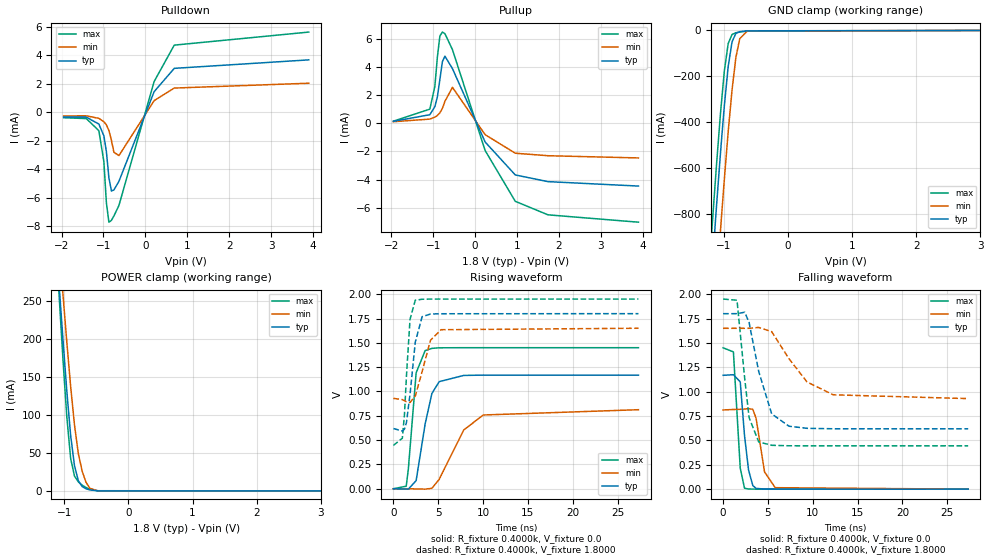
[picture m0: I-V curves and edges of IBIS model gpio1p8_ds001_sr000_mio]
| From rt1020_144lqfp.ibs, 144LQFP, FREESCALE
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[Model] gpio1p8_ds001_sr000_mio
|   Model gpio1p8_ds001_sr000_mio
| This model was characterised for following simulation conditions:
| External (pad) voltage:
|   - Typ: 1.8V,   - Min: 1.65V,   - Max: 1.95V
| Library cells for typ/min/max conditions are connected as defined below:
|  pad - External Pad
|  ipp_do - Core Input
|  ipp_obe - Output Buffer Enable
|  esd_boost - ovdd
|  ipp_dse0 - vddi
|  ipp_dse1 - vssi
|  ipp_dse2 - vssi
|  ipp_fsel0 - vssi
|  ipp_fsel1 - vssi
|  ipp_ina - ipp_ina
|  ipp_ind - ipp_ind
|  ipp_pwr_stable - vddi
|  ipp_sre - vssi
|  ovdd - ovdd
|  ovss - ovss
|  vddi - vddi
|  vssi - vssi
| All other pins connected to ground
Model_type I/O
Polarity   Non-Inverting
Enable   Active-High
Vinl =   0.5400V
Vinh =   1.2600V
Vmeas =  0.9000V
Cref =   0.0F
Rref =   0.4000k
Vref =   0.9000V
C_comp   1.2573pF   1.2208pF   1.3054pF
|C_comp_pullup   0.6439pF   0.6609pF   0.6284pF
|C_comp_pulldown   0.5473pF   0.5786pF   0.5258pF
[Model Spec]
| variable   typ   min   max
Vinh   1.2600V   1.1550V   1.3650V
Vinl   0.5400V   0.4950V   0.5850V
S_overshoot_high   1.8000V   1.6500V   1.9500V
S_overshoot_low   0.0V   0.0V   0.0V
Vmeas   0.9000V   0.8250V   0.9750V
Vref   0.9000V   0.8250V   0.9750V
Cref   0.0F   0.0F   0.0F
Rref   0.4000k   0.4000k   0.4000k
[Temperature Range]   25.0000   0.1050k   -20.0000
[Voltage Range]   1.8000V   1.6500V   1.9500V
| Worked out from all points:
|   slope of the pulldown table from 0 to 0.27 V, typ, clamps not added: 153 ohm
|   slope of the pullup table from 0 to 0.27 V, typ, clamps not added: 182 ohm
|   GND clamp passes 1 mA (typ) near -0.55 V on its own axis
|   POWER clamp passes 1 mA (typ) near -0.58 V on its own axis
|   rising waveform, R_fixture 0.4000k, V_fixture 0.0: 20-80 % time 1.3ns typ, 2.8ns min, 747ps max; typ from 0 V to 1.17 V
|   rising waveform, R_fixture 0.4000k, V_fixture 1.8000: 20-80 % time 809ps typ, 1.19ns min, 546ps max; typ from 0.619 V to 1.8 V
|   falling waveform, R_fixture 0.4000k, V_fixture 0.0: 20-80 % time 681ps typ, 847ps min, 496ps max; typ from 1.17 V to 0 V
|   falling waveform, R_fixture 0.4000k, V_fixture 1.8000: 20-80 % time 1.74ns typ, 3.42ns min, 947ps max; typ from 1.8 V to 0.619 V
[Pulldown]
|Voltage   I(typ)   I(min)   I(max)
-1.95V    -342uA     -265uA     -391uA
-1.41V    -350uA     -258uA     -451uA
-1.11V    -834.5uA   -436uA     -1.299mA
-990mV    -1.66mA    -669.8uA   -3.467mA
-930mV    -2.764mA   -895.4uA   -6.362mA
-870mV    -4.603mA   -1.287mA   -7.724mA
-810mV    -5.539mA   -1.972mA   -7.596mA
-750mV    -5.458mA   -2.817mA   -7.285mA
-630mV    -4.849mA   -3.046mA   -6.544mA
210mV     1.438mA    808.6uA    2.151mA
690mV     3.074mA    1.691mA    4.705mA
3.9V      3.67mA     2.03mA     5.62mA
[Pullup]
|Voltage   I(typ)   I(min)   I(max)
-1.95V    130uA      100uA      140uA
-1.08V    597uA      286uA      991uA
-960mV    1.17mA     422uA      2.604mA
-900mV    1.859mA    544uA      4.683mA
-840mV    3.095mA    733.5uA    6.184mA
-780mV    4.362mA    1.044mA    6.458mA
-720mV    4.75mA     1.549mA    6.347mA
-540mV    3.868mA    2.538mA    5.213mA
240mV     -1.338mA   -819.3uA   -1.942mA
960mV     -3.677mA   -2.134mA   -5.547mA
1.74V     -4.15mA    -2.312mA   -6.505mA
3.9V      -4.465mA   -2.469mA   -7.027mA
[GND_clamp]
|Voltage   I(typ)   I(min)   I(max)
-1.95V    -4.191A    -4.477A    -4.042A
-1.23V    -1.234A    -1.577A    -1.052A
-1.17V    -993.2mA   -1.338A    -811.1mA
-1.11V    -758.1mA   -1.102A    -578.5mA
-1.05V    -533.7mA   -870.8mA   -361.6mA
-990mV    -328mA     -648.8mA   -176.9mA
-930mV    -157.5mA   -441.8mA   -57.56mA
-870mV    -50.13mA   -259.5mA   -18.17mA
-810mV    -13.28mA   -118mA     -10.41mA
-750mV    -5.921mA   -36.52mA   -7.502mA
-630mV    -2.275mA   -2.653mA   -3.283mA
3.9V      0A         0A         0A
[POWER_clamp]
|Voltage   I(typ)   I(min)   I(max)
-1.95V    1.356A     1.328A     1.514A
-1.08V    270.6mA    322.7mA    256.8mA
-1.02V    199mA      258.1mA    173mA
-960mV    131.2mA    195.7mA    97.36mA
-900mV    72.67mA    137.2mA    42.48mA
-840mV    32.99mA    86.34mA    19.5mA
-780mV    13.32mA    48.87mA    11.87mA
-720mV    5.671mA    25.66mA    7.515mA
-660mV    2.793mA    11.19mA    4.477mA
-600mV    1.289mA    3.449mA    2.334mA
-480mV    122.1uA    182.3uA    260.9uA
3.9V      0A         0A         0A
[Ramp]
| variable   typ   min   max
dV/dt_r  0.7010/1.3019n   0.4876/2.8035n   0.8700/0.7474n
dV/dt_f  0.7085/1.7382n   0.4327/3.4239n   0.9031/0.9472n
R_load = 0.4000k
[Rising Waveform]
R_fixture= 0.4000k
V_fixture= 0.0
V_fixture_min= 0.0
V_fixture_max= 0.0
|time   V(typ)   V(min)   V(max)
0s        2.139nV    20.29nV    4.327nV
1.431ns   -2.85mV    235.8uV    26.33mV
1.669ns   -4.3mV     55.13uV    203.8mV
2.539ns   84.13mV    -1.822mV   1.192V
3.546ns   668.2mV    -3.978mV   1.421V
4.294ns   979.2mV    4.643mV    1.443V
5.107ns   1.101V     96.72mV    1.449V
7.845ns   1.165V     603.8mV    1.45V
10.02ns   1.168V     758.2mV    1.45V
27.33ns   1.168V     812.6mV    1.45V
[Rising Waveform]
R_fixture= 0.4000k
V_fixture= 1.8000
V_fixture_min= 1.6500
V_fixture_max= 1.9500
|time   V(typ)   V(min)   V(max)
0s        619.2mV    928.9mV    444.9mV
999.8ps   593.5mV    916.4mV    519.8mV
1.231ns   612.7mV    905.3mV    756.5mV
1.464ns   683mV      894.5mV    1.169V
1.857ns   973.2mV    886.9mV    1.742V
2.442ns   1.507V     953mV      1.938V
3.205ns   1.769V     1.205V     1.948V
4.137ns   1.796V     1.526V     1.95V
5.32ns    1.799V     1.635V     1.95V
27.33ns   1.8V       1.65V      1.95V
[Falling Waveform]
R_fixture= 0.4000k
V_fixture= 0.0
V_fixture_min= 0.0
V_fixture_max= 0.0
|time   V(typ)   V(min)   V(max)
0s        1.168V     812.6mV    1.45V
1.149ns   1.174V     817.2mV    1.408V
1.91ns    1.101V     819.3mV    216.3mV
2.387ns   550.1mV    821.6mV    9.584mV
2.836ns   196.7mV    826.4mV    1.791mV
3.312ns   36.88mV    818.7mV    930.4uV
3.674ns   8.03mV     728.9mV    571uV
4.621ns   1.159mV    176.5mV    153.6uV
5.811ns   395.8uV    15.16mV    27.52uV
27.33ns   3.031nV    1.416nV    11.3nV
[Falling Waveform]
R_fixture= 0.4000k
V_fixture= 1.8000
V_fixture_min= 1.6500
V_fixture_max= 1.9500
|time   V(typ)   V(min)   V(max)
0s        1.8V       1.65V      1.95V
1.549ns   1.8V       1.65V      1.938V
2.413ns   1.815V     1.65V      1.131V
2.898ns   1.71V      1.65V      733.5mV
3.97ns    1.207V     1.659V     484.8mV
5.416ns   772.1mV    1.616V     450.1mV
7.352ns   645.6mV    1.337V     445.1mV
9.351ns   624.2mV    1.1V       444.8mV
12.28ns   619.5mV    967.9mV    444.9mV
27.33ns   619.2mV    928.9mV    444.9mV
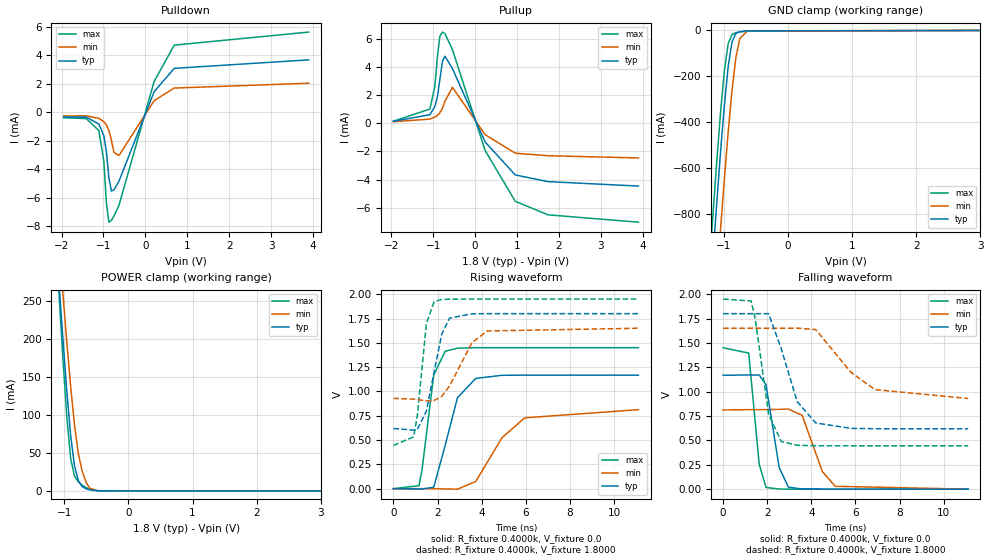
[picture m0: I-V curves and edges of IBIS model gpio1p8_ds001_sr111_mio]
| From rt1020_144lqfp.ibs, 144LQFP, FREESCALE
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[Model] gpio1p8_ds001_sr111_mio
|   Model gpio1p8_ds001_sr111_mio
| This model was characterised for following simulation conditions:
| External (pad) voltage:
|   - Typ: 1.8V,   - Min: 1.65V,   - Max: 1.95V
| Library cells for typ/min/max conditions are connected as defined below:
|  pad - External Pad
|  ipp_do - Core Input
|  ipp_obe - Output Buffer Enable
|  esd_boost - ovdd
|  ipp_dse0 - vddi
|  ipp_dse1 - vssi
|  ipp_dse2 - vssi
|  ipp_fsel0 - vddi
|  ipp_fsel1 - vddi
|  ipp_ina - ipp_ina
|  ipp_ind - ipp_ind
|  ipp_pwr_stable - vddi
|  ipp_sre - vddi
|  ovdd - ovdd
|  ovss - ovss
|  vddi - vddi
|  vssi - vssi
| All other pins connected to ground
Model_type I/O
Polarity   Non-Inverting
Enable   Active-High
Vinl =   0.5400V
Vinh =   1.2600V
Vmeas =  0.9000V
Cref =   0.0F
Rref =   0.4000k
Vref =   0.9000V
C_comp   1.2573pF   1.2208pF   1.3056pF
|C_comp_pullup   0.6440pF   0.6611pF   0.6285pF
|C_comp_pulldown   0.5474pF   0.5788pF   0.5258pF
[Model Spec]
| variable   typ   min   max
Vinh   1.2600V   1.1550V   1.3650V
Vinl   0.5400V   0.4950V   0.5850V
S_overshoot_high   1.8000V   1.6500V   1.9500V
S_overshoot_low   0.0V   0.0V   0.0V
Vmeas   0.9000V   0.8250V   0.9750V
Vref   0.9000V   0.8250V   0.9750V
Cref   0.0F   0.0F   0.0F
Rref   0.4000k   0.4000k   0.4000k
[Temperature Range]   25.0000   0.1050k   -20.0000
[Voltage Range]   1.8000V   1.6500V   1.9500V
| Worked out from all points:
|   slope of the pulldown table from 0 to 0.27 V, typ, clamps not added: 153 ohm
|   slope of the pullup table from 0 to 0.27 V, typ, clamps not added: 182 ohm
|   GND clamp passes 1 mA (typ) near -0.55 V on its own axis
|   POWER clamp passes 1 mA (typ) near -0.58 V on its own axis
|   rising waveform, R_fixture 0.4000k, V_fixture 0.0: 20-80 % time 752ps typ, 1.44ns min, 470ps max; typ from 0 V to 1.17 V
|   rising waveform, R_fixture 0.4000k, V_fixture 1.8000: 20-80 % time 605ps typ, 990ps min, 382ps max; typ from 0.619 V to 1.8 V
|   falling waveform, R_fixture 0.4000k, V_fixture 0.0: 20-80 % time 458ps typ, 735ps min, 307ps max; typ from 1.17 V to 0 V
|   falling waveform, R_fixture 0.4000k, V_fixture 1.8000: 20-80 % time 953ps typ, 1.66ns min, 572ps max; typ from 1.8 V to 0.619 V
[Pulldown]
|Voltage   I(typ)   I(min)   I(max)
-1.95V    -342uA     -265uA     -391uA
-1.41V    -350uA     -258uA     -451uA
-1.11V    -834.5uA   -436uA     -1.299mA
-990mV    -1.66mA    -669.8uA   -3.467mA
-930mV    -2.764mA   -895.4uA   -6.362mA
-870mV    -4.603mA   -1.287mA   -7.724mA
-810mV    -5.539mA   -1.972mA   -7.596mA
-750mV    -5.458mA   -2.817mA   -7.285mA
-630mV    -4.849mA   -3.046mA   -6.544mA
210mV     1.438mA    808.6uA    2.151mA
690mV     3.074mA    1.691mA    4.705mA
3.9V      3.67mA     2.03mA     5.62mA
[Pullup]
|Voltage   I(typ)   I(min)   I(max)
-1.95V    130uA      100uA      140uA
-1.08V    597uA      286uA      991uA
-960mV    1.17mA     422uA      2.604mA
-900mV    1.859mA    544uA      4.683mA
-840mV    3.095mA    733.5uA    6.184mA
-780mV    4.362mA    1.044mA    6.458mA
-720mV    4.75mA     1.549mA    6.347mA
-540mV    3.868mA    2.538mA    5.213mA
240mV     -1.338mA   -819.3uA   -1.942mA
960mV     -3.677mA   -2.134mA   -5.547mA
1.74V     -4.15mA    -2.312mA   -6.505mA
3.9V      -4.465mA   -2.469mA   -7.027mA
[GND_clamp]
|Voltage   I(typ)   I(min)   I(max)
-1.95V    -4.191A    -4.477A    -4.042A
-1.23V    -1.234A    -1.577A    -1.052A
-1.17V    -993.2mA   -1.338A    -811.1mA
-1.11V    -758.1mA   -1.102A    -578.5mA
-1.05V    -533.7mA   -870.8mA   -361.6mA
-990mV    -328mA     -648.8mA   -176.9mA
-930mV    -157.5mA   -441.8mA   -57.56mA
-870mV    -50.13mA   -259.5mA   -18.17mA
-810mV    -13.28mA   -118mA     -10.41mA
-750mV    -5.921mA   -36.52mA   -7.502mA
-630mV    -2.275mA   -2.653mA   -3.283mA
3.9V      0A         0A         0A
[POWER_clamp]
|Voltage   I(typ)   I(min)   I(max)
-1.95V    1.356A     1.328A     1.514A
-1.08V    270.6mA    322.7mA    256.8mA
-1.02V    199mA      258.1mA    173mA
-960mV    131.2mA    195.7mA    97.36mA
-900mV    72.67mA    137.2mA    42.48mA
-840mV    32.99mA    86.34mA    19.5mA
-780mV    13.32mA    48.87mA    11.87mA
-720mV    5.671mA    25.66mA    7.515mA
-660mV    2.793mA    11.19mA    4.477mA
-600mV    1.289mA    3.449mA    2.334mA
-480mV    122.1uA    182.3uA    260.9uA
3.9V      0A         0A         0A
[Ramp]
| variable   typ   min   max
dV/dt_r  0.7010/0.7524n   0.4875/1.4360n   0.8700/0.4697n
dV/dt_f  0.7085/0.9530n   0.4320/1.6566n   0.9031/0.5717n
R_load = 0.4000k
[Rising Waveform]
R_fixture= 0.4000k
V_fixture= 0.0
V_fixture_min= 0.0
V_fixture_max= 0.0
|time   V(typ)   V(min)   V(max)
0s        2.139nV    20.13nV    4.326nV
1.16ns    -1.984mV   207.4uV    31.12mV
1.3ns     -3.491mV   182uV      194.4mV
1.829ns   15.39mV    -477.3uV   1.169V
2.348ns   445.8mV    -2.4mV     1.413V
2.904ns   934.9mV    -4.934mV   1.445V
3.732ns   1.134V     74.28mV    1.45V
4.93ns    1.166V     525.9mV    1.45V
5.957ns   1.168V     728.8mV    1.45V
11.11ns   1.168V     812.5mV    1.45V
[Rising Waveform]
R_fixture= 0.4000k
V_fixture= 1.8000
V_fixture_min= 1.6500
V_fixture_max= 1.9500
|time   V(typ)   V(min)   V(max)
0s        619.2mV    928.9mV    444.9mV
921.8ps   602.2mV    921.1mV    533.1mV
1.09ns    611.9mV    915.4mV    760mV
1.497ns   796.9mV    903mV      1.701V
1.85ns    1.208V     906.4mV    1.925V
2.196ns   1.591V     950.8mV    1.946V
2.548ns   1.754V     1.058V     1.949V
3.566ns   1.798V     1.503V     1.95V
4.253ns   1.8V       1.622V     1.95V
11.11ns   1.8V       1.65V      1.95V
[Falling Waveform]
R_fixture= 0.4000k
V_fixture= 0.0
V_fixture_min= 0.0
V_fixture_max= 0.0
|time   V(typ)   V(min)   V(max)
0s        1.168V     812.6mV    1.45V
1.16ns    1.172V     815.7mV    1.396V
1.637ns   1.171V     816.1mV    255.4mV
1.945ns   1.071V     816.5mV    17.49mV
2.542ns   221.5mV    818.6mV    1.01mV
2.958ns   20.94mV    821.7mV    475.5uV
3.583ns   1.499mV    757.1mV    185.2uV
4.501ns   349.6uV    179.8mV    57.18uV
5.08ns    160.2uV    29.49mV    27.92uV
11.11ns   439.2nV    5.686uV    135.4nV
[Falling Waveform]
R_fixture= 0.4000k
V_fixture= 1.8000
V_fixture_min= 1.6500
V_fixture_max= 1.9500
|time   V(typ)   V(min)   V(max)
0s        1.8V       1.65V      1.95V
1.272ns   1.8V       1.65V      1.93V
1.452ns   1.8V       1.65V      1.752V
2.062ns   1.8V       1.65V      770.8mV
2.633ns   1.442V     1.65V      489.1mV
3.357ns   898.3mV    1.652V     450.4mV
4.198ns   679.1mV    1.637V     445.5mV
5.797ns   623.3mV    1.198V     444.9mV
6.883ns   619.8mV    1.021V     444.9mV
11.11ns   619.2mV    930mV      444.9mV
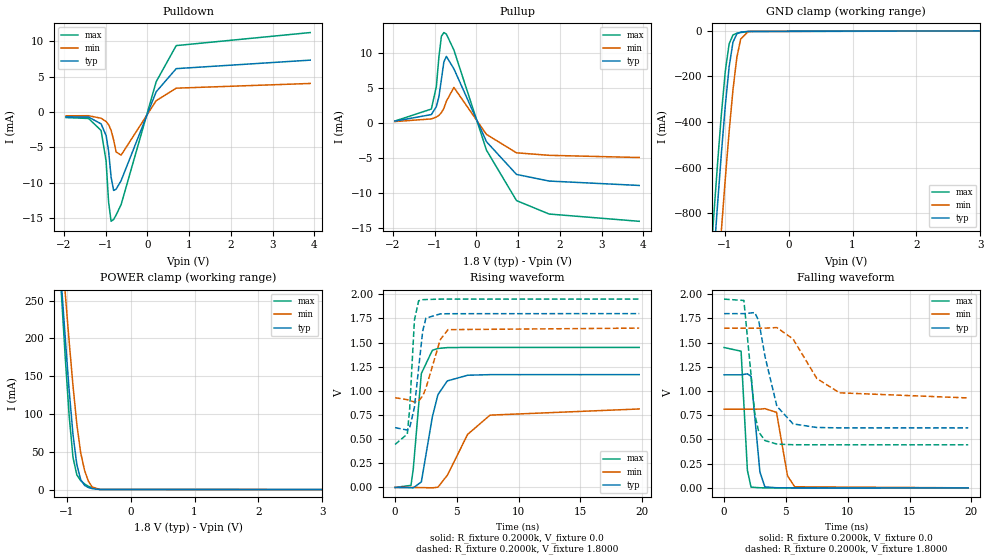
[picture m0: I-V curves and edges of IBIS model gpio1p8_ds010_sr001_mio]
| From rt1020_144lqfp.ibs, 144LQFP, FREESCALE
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[Model] gpio1p8_ds010_sr001_mio
|   Model gpio1p8_ds010_sr001_mio
| This model was characterised for following simulation conditions:
| External (pad) voltage:
|   - Typ: 1.8V,   - Min: 1.65V,   - Max: 1.95V
| Library cells for typ/min/max conditions are connected as defined below:
|  pad - External Pad
|  ipp_do - Core Input
|  ipp_obe - Output Buffer Enable
|  esd_boost - ovdd
|  ipp_dse0 - vssi
|  ipp_dse1 - vddi
|  ipp_dse2 - vssi
|  ipp_fsel0 - vddi
|  ipp_fsel1 - vssi
|  ipp_ina - ipp_ina
|  ipp_ind - ipp_ind
|  ipp_pwr_stable - vddi
|  ipp_sre - vssi
|  ovdd - ovdd
|  ovss - ovss
|  vddi - vddi
|  vssi - vssi
| All other pins connected to ground
Model_type I/O
Polarity   Non-Inverting
Enable   Active-High
Vinl =   0.5400V
Vinh =   1.2600V
Vmeas =  0.9000V
Cref =   0.0F
Rref =   0.2000k
Vref =   0.9000V
C_comp   1.2573pF   1.2208pF   1.3054pF
|C_comp_pullup   0.6439pF   0.6609pF   0.6284pF
|C_comp_pulldown   0.5473pF   0.5786pF   0.5258pF
[Model Spec]
| variable   typ   min   max
Vinh   1.2600V   1.1550V   1.3650V
Vinl   0.5400V   0.4950V   0.5850V
S_overshoot_high   1.8000V   1.6500V   1.9500V
S_overshoot_low   0.0V   0.0V   0.0V
Vmeas   0.9000V   0.8250V   0.9750V
Vref   0.9000V   0.8250V   0.9750V
Cref   0.0F   0.0F   0.0F
Rref   0.2000k   0.2000k   0.2000k
[Temperature Range]   25.0000   0.1050k   -20.0000
[Voltage Range]   1.8000V   1.6500V   1.9500V
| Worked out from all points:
|   slope of the pulldown table from 0 to 0.27 V, typ, clamps not added: 76.7 ohm
|   slope of the pullup table from 0 to 0.27 V, typ, clamps not added: 91 ohm
|   GND clamp passes 1 mA (typ) near -0.55 V on its own axis
|   POWER clamp passes 1 mA (typ) near -0.58 V on its own axis
|   rising waveform, R_fixture 0.2000k, V_fixture 0.0: 20-80 % time 1.01ns typ, 2.15ns min, 570ps max; typ from 0 V to 1.17 V
|   rising waveform, R_fixture 0.2000k, V_fixture 1.8000: 20-80 % time 582ps typ, 972ps min, 374ps max; typ from 0.619 V to 1.8 V
|   falling waveform, R_fixture 0.2000k, V_fixture 0.0: 20-80 % time 402ps typ, 594ps min, 280ps max; typ from 1.17 V to 0 V
|   falling waveform, R_fixture 0.2000k, V_fixture 1.8000: 20-80 % time 1.19ns typ, 2.27ns min, 642ps max; typ from 1.8 V to 0.619 V
[Pulldown]
|Voltage   I(typ)   I(min)   I(max)
-1.95V    -679uA     -527uA     -778uA
-1.41V    -700uA     -513uA     -902uA
-1.11V    -1.667mA   -870uA     -2.597mA
-990mV    -3.318mA   -1.338mA   -6.94mA
-930mV    -5.527mA   -1.788mA   -12.74mA
-870mV    -9.21mA    -2.57mA    -15.45mA
-810mV    -11.08mA   -3.94mA    -15.19mA
-750mV    -10.91mA   -5.632mA   -14.56mA
-630mV    -9.694mA   -6.09mA    -13.08mA
210mV     2.875mA    1.617mA    4.3mA
690mV     6.147mA    3.383mA    9.407mA
3.9V      7.35mA     4.05mA     11.25mA
[Pullup]
|Voltage   I(typ)   I(min)   I(max)
-1.95V    260uA      200uA      280uA
-1.08V    1.195mA    574uA      1.984mA
-960mV    2.342mA    845uA      5.218mA
-900mV    3.721mA    1.088mA    9.383mA
-840mV    6.196mA    1.468mA    12.37mA
-780mV    8.726mA    2.089mA    12.91mA
-720mV    9.498mA    3.099mA    12.69mA
-540mV    7.732mA    5.075mA    10.42mA
240mV     -2.675mA   -1.638mA   -3.883mA
960mV     -7.353mA   -4.267mA   -11.09mA
1.74V     -8.3mA     -4.625mA   -13.01mA
3.9V      -8.929mA   -4.938mA   -14.05mA
[GND_clamp]
|Voltage   I(typ)   I(min)   I(max)
-1.95V    -4.191A    -4.477A    -4.042A
-1.23V    -1.234A    -1.577A    -1.052A
-1.17V    -993.2mA   -1.338A    -811.1mA
-1.11V    -758.1mA   -1.102A    -578.5mA
-1.05V    -533.7mA   -870.8mA   -361.6mA
-990mV    -328mA     -648.8mA   -176.9mA
-930mV    -157.5mA   -441.8mA   -57.56mA
-870mV    -50.13mA   -259.5mA   -18.17mA
-810mV    -13.28mA   -118mA     -10.41mA
-750mV    -5.921mA   -36.52mA   -7.502mA
-630mV    -2.275mA   -2.653mA   -3.283mA
3.9V      0A         0A         0A
[POWER_clamp]
|Voltage   I(typ)   I(min)   I(max)
-1.95V    1.356A     1.328A     1.514A
-1.08V    270.6mA    322.7mA    256.8mA
-1.02V    199mA      258.1mA    173mA
-960mV    131.2mA    195.7mA    97.36mA
-900mV    72.67mA    137.2mA    42.48mA
-840mV    32.99mA    86.34mA    19.5mA
-780mV    13.32mA    48.87mA    11.87mA
-720mV    5.671mA    25.66mA    7.515mA
-660mV    2.793mA    11.19mA    4.477mA
-600mV    1.289mA    3.449mA    2.334mA
-480mV    122.1uA    182.3uA    260.9uA
3.9V      0A         0A         0A
[Ramp]
| variable   typ   min   max
dV/dt_r  0.7010/1.0091n   0.4875/2.1522n   0.8699/0.5697n
dV/dt_f  0.7084/1.1889n   0.4327/2.2737n   0.9030/0.6420n
R_load = 0.2000k
[Rising Waveform]
R_fixture= 0.2000k
V_fixture= 0.0
V_fixture_min= 0.0
V_fixture_max= 0.0
|time   V(typ)   V(min)   V(max)
0s        1.07nV     10.15nV    2.165nV
1.288ns   -2.879mV   250.1uV    21.54mV
1.473ns   -4.242mV   129.2uV    189.7mV
2.127ns   57.36mV    -1.559mV   1.18V
3.017ns   730.3mV    -4.03mV    1.42V
3.466ns   960.5mV    2.327mV    1.439V
4.225ns   1.103V     126.1mV    1.448V
5.875ns   1.162V     549.9mV    1.45V
7.68ns    1.168V     748.8mV    1.45V
19.75ns   1.168V     812.6mV    1.45V
[Rising Waveform]
R_fixture= 0.2000k
V_fixture= 1.8000
V_fixture_min= 1.6500
V_fixture_max= 1.9500
|time   V(typ)   V(min)   V(max)
0s        619.3mV    928.9mV    445mV
992.1ps   594.1mV    908.9mV    553.2mV
1.183ns   618.7mV    899.2mV    815.1mV
1.568ns   829.7mV    885.3mV    1.734V
1.91ns    1.238V     895.2mV    1.933V
2.238ns   1.621V     948.8mV    1.944V
2.495ns   1.753V     1.027V     1.946V
3.65ns    1.797V     1.528V     1.95V
4.278ns   1.799V     1.634V     1.95V
19.75ns   1.8V       1.65V      1.95V
[Falling Waveform]
R_fixture= 0.2000k
V_fixture= 0.0
V_fixture_min= 0.0
V_fixture_max= 0.0
|time   V(typ)   V(min)   V(max)
0s        1.168V     812.6mV    1.45V
1.376ns   1.168V     812.3mV    1.412V
1.886ns   1.178V     812.3mV    182.1mV
2.182ns   1.153V     812.3mV    7.233mV
2.899ns   163.2mV    813.7mV    1.108mV
3.299ns   9.851mV    818.5mV    562.6uV
4.241ns   1.202mV    780.6mV    113.5uV
5.132ns   412.4uV    124.3mV    25.77uV
5.714ns   200.3uV    11.06mV    10.23uV
19.75ns   7.434nV    69.75nV    8.35nV
[Falling Waveform]
R_fixture= 0.2000k
V_fixture= 1.8000
V_fixture_min= 1.6500
V_fixture_max= 1.9500
|time   V(typ)   V(min)   V(max)
0s        1.8V       1.65V      1.95V
1.603ns   1.8V       1.65V      1.936V
2.485ns   1.811V     1.65V      763.4mV
2.805ns   1.726V     1.65V      576.8mV
3.314ns   1.356V     1.65V      488.4mV
4.269ns   843.8mV    1.656V     452.6mV
5.581ns   660.9mV    1.538V     445.6mV
7.503ns   623.9mV    1.13V      445mV
9.339ns   619.7mV    982mV      445mV
19.75ns   619.3mV    928.9mV    445mV
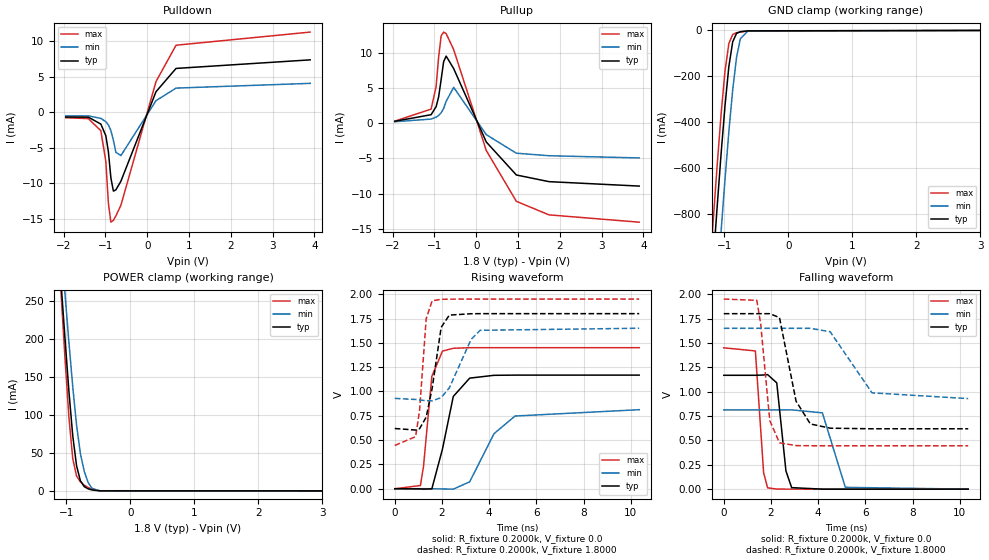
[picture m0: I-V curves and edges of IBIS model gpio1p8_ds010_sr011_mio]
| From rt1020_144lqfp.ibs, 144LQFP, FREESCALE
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[Model] gpio1p8_ds010_sr011_mio
|   Model gpio1p8_ds010_sr011_mio
| This model was characterised for following simulation conditions:
| External (pad) voltage:
|   - Typ: 1.8V,   - Min: 1.65V,   - Max: 1.95V
| Library cells for typ/min/max conditions are connected as defined below:
|  pad - External Pad
|  ipp_do - Core Input
|  ipp_obe - Output Buffer Enable
|  esd_boost - ovdd
|  ipp_dse0 - vssi
|  ipp_dse1 - vddi
|  ipp_dse2 - vssi
|  ipp_fsel0 - vddi
|  ipp_fsel1 - vddi
|  ipp_ina - ipp_ina
|  ipp_ind - ipp_ind
|  ipp_pwr_stable - vddi
|  ipp_sre - vssi
|  ovdd - ovdd
|  ovss - ovss
|  vddi - vddi
|  vssi - vssi
| All other pins connected to ground
Model_type I/O
Polarity   Non-Inverting
Enable   Active-High
Vinl =   0.5400V
Vinh =   1.2600V
Vmeas =  0.9000V
Cref =   0.0F
Rref =   0.2000k
Vref =   0.9000V
C_comp   1.2573pF   1.2208pF   1.3056pF
|C_comp_pullup   0.6440pF   0.6611pF   0.6285pF
|C_comp_pulldown   0.5474pF   0.5788pF   0.5258pF
[Model Spec]
| variable   typ   min   max
Vinh   1.2600V   1.1550V   1.3650V
Vinl   0.5400V   0.4950V   0.5850V
S_overshoot_high   1.8000V   1.6500V   1.9500V
S_overshoot_low   0.0V   0.0V   0.0V
Vmeas   0.9000V   0.8250V   0.9750V
Vref   0.9000V   0.8250V   0.9750V
Cref   0.0F   0.0F   0.0F
Rref   0.2000k   0.2000k   0.2000k
[Temperature Range]   25.0000   0.1050k   -20.0000
[Voltage Range]   1.8000V   1.6500V   1.9500V
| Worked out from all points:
|   slope of the pulldown table from 0 to 0.27 V, typ, clamps not added: 76.7 ohm
|   slope of the pullup table from 0 to 0.27 V, typ, clamps not added: 91 ohm
|   GND clamp passes 1 mA (typ) near -0.55 V on its own axis
|   POWER clamp passes 1 mA (typ) near -0.58 V on its own axis
|   rising waveform, R_fixture 0.2000k, V_fixture 0.0: 20-80 % time 556ps typ, 1.1ns min, 334ps max; typ from 0 V to 1.17 V
|   rising waveform, R_fixture 0.2000k, V_fixture 1.8000: 20-80 % time 431ps typ, 774ps min, 263ps max; typ from 0.619 V to 1.8 V
|   falling waveform, R_fixture 0.2000k, V_fixture 0.0: 20-80 % time 263ps typ, 424ps min, 185ps max; typ from 1.17 V to 0 V
|   falling waveform, R_fixture 0.2000k, V_fixture 1.8000: 20-80 % time 560ps typ, 955ps min, 339ps max; typ from 1.8 V to 0.619 V
[Pulldown]
|Voltage   I(typ)   I(min)   I(max)
-1.95V    -679uA     -527uA     -778uA
-1.41V    -700uA     -513uA     -902uA
-1.11V    -1.667mA   -870uA     -2.597mA
-990mV    -3.318mA   -1.338mA   -6.94mA
-930mV    -5.527mA   -1.788mA   -12.74mA
-870mV    -9.21mA    -2.57mA    -15.45mA
-810mV    -11.08mA   -3.94mA    -15.19mA
-750mV    -10.91mA   -5.632mA   -14.56mA
-630mV    -9.694mA   -6.09mA    -13.08mA
210mV     2.875mA    1.617mA    4.3mA
690mV     6.147mA    3.383mA    9.407mA
3.9V      7.35mA     4.05mA     11.25mA
[Pullup]
|Voltage   I(typ)   I(min)   I(max)
-1.95V    260uA      200uA      280uA
-1.08V    1.195mA    574uA      1.984mA
-960mV    2.342mA    845uA      5.218mA
-900mV    3.721mA    1.088mA    9.383mA
-840mV    6.196mA    1.468mA    12.37mA
-780mV    8.726mA    2.089mA    12.91mA
-720mV    9.498mA    3.099mA    12.69mA
-540mV    7.732mA    5.075mA    10.42mA
240mV     -2.675mA   -1.638mA   -3.883mA
960mV     -7.353mA   -4.267mA   -11.09mA
1.74V     -8.3mA     -4.625mA   -13.01mA
3.9V      -8.929mA   -4.938mA   -14.05mA
[GND_clamp]
|Voltage   I(typ)   I(min)   I(max)
-1.95V    -4.191A    -4.477A    -4.042A
-1.23V    -1.234A    -1.577A    -1.052A
-1.17V    -993.2mA   -1.338A    -811.1mA
-1.11V    -758.1mA   -1.102A    -578.5mA
-1.05V    -533.7mA   -870.8mA   -361.6mA
-990mV    -328mA     -648.8mA   -176.9mA
-930mV    -157.5mA   -441.8mA   -57.56mA
-870mV    -50.13mA   -259.5mA   -18.17mA
-810mV    -13.28mA   -118mA     -10.41mA
-750mV    -5.921mA   -36.52mA   -7.502mA
-630mV    -2.275mA   -2.653mA   -3.283mA
3.9V      0A         0A         0A
[POWER_clamp]
|Voltage   I(typ)   I(min)   I(max)
-1.95V    1.356A     1.328A     1.514A
-1.08V    270.6mA    322.7mA    256.8mA
-1.02V    199mA      258.1mA    173mA
-960mV    131.2mA    195.7mA    97.36mA
-900mV    72.67mA    137.2mA    42.48mA
-840mV    32.99mA    86.34mA    19.5mA
-780mV    13.32mA    48.87mA    11.87mA
-720mV    5.671mA    25.66mA    7.515mA
-660mV    2.793mA    11.19mA    4.477mA
-600mV    1.289mA    3.449mA    2.334mA
-480mV    122.1uA    182.3uA    260.9uA
3.9V      0A         0A         0A
[Ramp]
| variable   typ   min   max
dV/dt_r  0.7010/0.5561n   0.4875/1.1023n   0.8699/0.3344n
dV/dt_f  0.7084/0.5600n   0.4326/0.9546n   0.9030/0.3385n
R_load = 0.2000k
[Rising Waveform]
R_fixture= 0.2000k
V_fixture= 0.0
V_fixture_min= 0.0
V_fixture_max= 0.0
|time   V(typ)   V(min)   V(max)
0s        1.069nV    10.06nV    2.165nV
1.087ns   -2.116mV   168.2uV    32.85mV
1.218ns   -3.762mV   137.9uV    230mV
1.571ns   -1.582mV   -264.4uV   1.155V
2.023ns   409mV      -2.027mV   1.415V
2.48ns    948.6mV    -4.52mV    1.444V
3.175ns   1.137V     70.98mV    1.45V
4.207ns   1.166V     566.1mV    1.45V
5.099ns   1.168V     747.5mV    1.45V
10.36ns   1.168V     812.6mV    1.45V
[Rising Waveform]
R_fixture= 0.2000k
V_fixture= 1.8000
V_fixture_min= 1.6500
V_fixture_max= 1.9500
|time   V(typ)   V(min)   V(max)
0s        619.3mV    928.9mV    445mV
884.4ps   603.1mV    917.7mV    535.6mV
1.05ns    617.3mV    912.4mV    802.5mV
1.332ns   736mV      904.9mV    1.748V
1.585ns   1.033V     904mV      1.932V
1.966ns   1.659V     936.6mV    1.947V
2.312ns   1.785V     1.037V     1.949V
3.233ns   1.799V     1.535V     1.95V
3.623ns   1.8V       1.629V     1.95V
10.36ns   1.8V       1.65V      1.95V
[Falling Waveform]
R_fixture= 0.2000k
V_fixture= 0.0
V_fixture_min= 0.0
V_fixture_max= 0.0
|time   V(typ)   V(min)   V(max)
0s        1.168V     812.6mV    1.45V
1.339ns   1.168V     812.4mV    1.418V
1.688ns   1.171V     812.4mV    169.3mV
1.857ns   1.175V     812.4mV    13.2mV
2.246ns   1.09V      812.4mV    1.214mV
2.634ns   187.4mV    812.7mV    409.6uV
2.876ns   15.76mV    813.4mV    248uV
4.179ns   244.8uV    782.7mV    44.33uV
5.152ns   66.62uV    18.7mV     13.28uV
10.36ns   401.5nV    5.118uV    91.23nV
[Falling Waveform]
R_fixture= 0.2000k
V_fixture= 1.8000
V_fixture_min= 1.6500
V_fixture_max= 1.9500
|time   V(typ)   V(min)   V(max)
0s        1.8V       1.65V      1.95V
1.4ns     1.8V       1.65V      1.937V
1.564ns   1.8V       1.65V      1.695V
1.948ns   1.8V       1.65V      704.5mV
2.361ns   1.76V      1.65V      475.7mV
3.063ns   902.5mV    1.65V      447.1mV
3.67ns    668.9mV    1.65V      445.3mV
4.509ns   625.5mV    1.615V     445.1mV
6.283ns   619.4mV    988mV      445mV
10.36ns   619.3mV    929mV      445mV
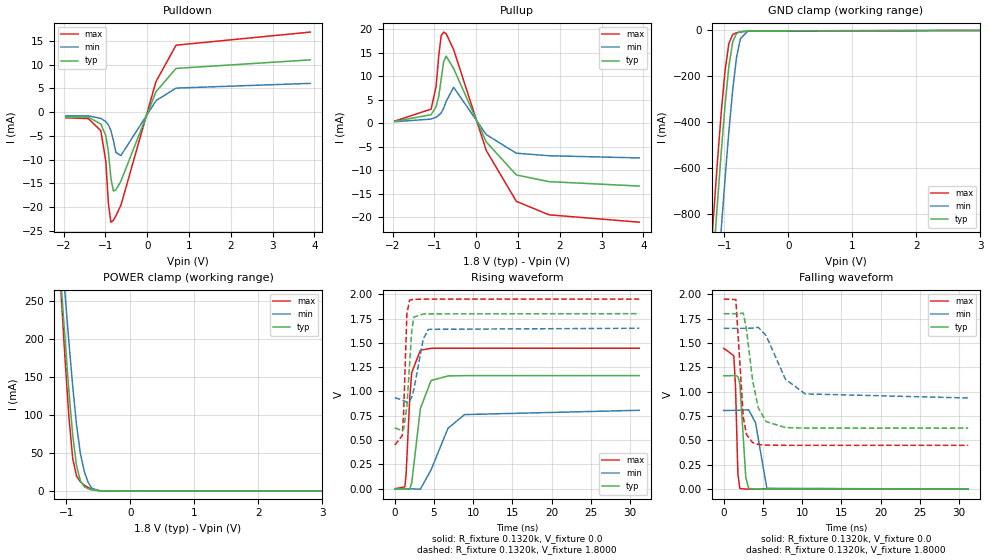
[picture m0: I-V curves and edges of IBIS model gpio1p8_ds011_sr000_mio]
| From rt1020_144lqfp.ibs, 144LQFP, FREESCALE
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[Model] gpio1p8_ds011_sr000_mio
|   Model gpio1p8_ds011_sr000_mio
| This model was characterised for following simulation conditions:
| External (pad) voltage:
|   - Typ: 1.8V,   - Min: 1.65V,   - Max: 1.95V
| Library cells for typ/min/max conditions are connected as defined below:
|  pad - External Pad
|  ipp_do - Core Input
|  ipp_obe - Output Buffer Enable
|  esd_boost - ovdd
|  ipp_dse0 - vddi
|  ipp_dse1 - vddi
|  ipp_dse2 - vssi
|  ipp_fsel0 - vssi
|  ipp_fsel1 - vssi
|  ipp_ina - ipp_ina
|  ipp_ind - ipp_ind
|  ipp_pwr_stable - vddi
|  ipp_sre - vssi
|  ovdd - ovdd
|  ovss - ovss
|  vddi - vddi
|  vssi - vssi
| All other pins connected to ground
Model_type I/O
Polarity   Non-Inverting
Enable   Active-High
Vinl =   0.5400V
Vinh =   1.2600V
Vmeas =  0.9000V
Cref =   0.0F
Rref =   0.1320k
Vref =   0.9000V
C_comp   1.2573pF   1.2208pF   1.3054pF
|C_comp_pullup   0.6439pF   0.6609pF   0.6284pF
|C_comp_pulldown   0.5473pF   0.5786pF   0.5258pF
[Model Spec]
| variable   typ   min   max
Vinh   1.2600V   1.1550V   1.3650V
Vinl   0.5400V   0.4950V   0.5850V
S_overshoot_high   1.8000V   1.6500V   1.9500V
S_overshoot_low   0.0V   0.0V   0.0V
Vmeas   0.9000V   0.8250V   0.9750V
Vref   0.9000V   0.8250V   0.9750V
Cref   0.0F   0.0F   0.0F
Rref   0.1320k   0.1320k   0.1320k
[Temperature Range]   25.0000   0.1050k   -20.0000
[Voltage Range]   1.8000V   1.6500V   1.9500V
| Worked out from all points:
|   slope of the pulldown table from 0 to 0.27 V, typ, clamps not added: 51.1 ohm
|   slope of the pullup table from 0 to 0.27 V, typ, clamps not added: 60.7 ohm
|   GND clamp passes 1 mA (typ) near -0.55 V on its own axis
|   POWER clamp passes 1 mA (typ) near -0.58 V on its own axis
|   rising waveform, R_fixture 0.1320k, V_fixture 0.0: 20-80 % time 1.1ns typ, 2.5ns min, 584ps max; typ from 0 V to 1.16 V
|   rising waveform, R_fixture 0.1320k, V_fixture 1.8000: 20-80 % time 546ps typ, 954ps min, 348ps max; typ from 0.626 V to 1.8 V
|   falling waveform, R_fixture 0.1320k, V_fixture 0.0: 20-80 % time 454ps typ, 745ps min, 298ps max; typ from 1.16 V to 0 V
|   falling waveform, R_fixture 0.1320k, V_fixture 1.8000: 20-80 % time 1.31ns typ, 2.65ns min, 664ps max; typ from 1.8 V to 0.626 V
[Pulldown]
|Voltage   I(typ)   I(min)   I(max)
-1.95V    -1.02mA    -793uA     -1.17mA
-1.41V    -1.051mA   -771uA     -1.353mA
-1.11V    -2.503mA   -1.306mA   -3.899mA
-990mV    -4.984mA   -2.008mA   -10.44mA
-930mV    -8.308mA   -2.685mA   -19.17mA
-870mV    -13.84mA   -3.86mA    -23.17mA
-810mV    -16.62mA   -5.918mA   -22.77mA
-750mV    -16.37mA   -8.456mA   -21.84mA
-630mV    -14.54mA   -9.133mA   -19.62mA
210mV     4.312mA    2.425mA    6.447mA
690mV     9.219mA    5.074mA    14.11mA
3.9V      11.02mA    6.07mA     16.87mA
[Pullup]
|Voltage   I(typ)   I(min)   I(max)
-1.95V    380uA      300uA      430uA
-1.08V    1.792mA    861uA      2.975mA
-960mV    3.514mA    1.267mA    7.834mA
-900mV    5.585mA    1.631mA    14.1mA
-840mV    9.305mA    2.201mA    18.57mA
-780mV    13.1mA     3.135mA    19.37mA
-720mV    14.25mA    4.65mA     19.03mA
-540mV    11.59mA    7.612mA    15.62mA
240mV     -4.012mA   -2.457mA   -5.822mA
960mV     -11.03mA   -6.4mA     -16.64mA
1.74V     -12.45mA   -6.938mA   -19.51mA
3.9V      -13.39mA   -7.407mA   -21.08mA
[GND_clamp]
|Voltage   I(typ)   I(min)   I(max)
-1.95V    -4.191A    -4.477A    -4.042A
-1.23V    -1.234A    -1.577A    -1.052A
-1.17V    -993.2mA   -1.338A    -811.1mA
-1.11V    -758.1mA   -1.102A    -578.5mA
-1.05V    -533.7mA   -870.8mA   -361.6mA
-990mV    -328mA     -648.8mA   -176.9mA
-930mV    -157.5mA   -441.8mA   -57.56mA
-870mV    -50.13mA   -259.5mA   -18.17mA
-810mV    -13.28mA   -118mA     -10.41mA
-750mV    -5.921mA   -36.52mA   -7.502mA
-630mV    -2.275mA   -2.653mA   -3.283mA
3.9V      0A         0A         0A
[POWER_clamp]
|Voltage   I(typ)   I(min)   I(max)
-1.95V    1.356A     1.328A     1.514A
-1.08V    270.6mA    322.7mA    256.8mA
-1.02V    199mA      258.1mA    173mA
-960mV    131.2mA    195.7mA    97.36mA
-900mV    72.67mA    137.2mA    42.48mA
-840mV    32.99mA    86.34mA    19.5mA
-780mV    13.32mA    48.87mA    11.87mA
-720mV    5.671mA    25.66mA    7.515mA
-660mV    2.793mA    11.19mA    4.477mA
-600mV    1.289mA    3.449mA    2.334mA
-480mV    122.1uA    182.3uA    260.9uA
3.9V      0A         0A         0A
[Ramp]
| variable   typ   min   max
dV/dt_r  0.6978/1.0954n   0.4841/2.5005n   0.8672/0.5842n
dV/dt_f  0.7044/1.3081n   0.4287/2.6523n   0.9000/0.6639n
R_load = 0.1320k
[Rising Waveform]
R_fixture= 0.1320k
V_fixture= 0.0
V_fixture_min= 0.0
V_fixture_max= 0.0
|time   V(typ)   V(min)   V(max)
0s        711.9pV    6.687nV    1.441nV
1.29ns    -2.865mV   249uV      19.12mV
1.452ns   -4.007mV   146.2uV    160mV
1.919ns   563.8uV    -821.4uV   944.7mV
2.164ns   62.45mV    -1.591mV   1.195V
3.27ns    826.2mV    -2.987mV   1.424V
4.624ns   1.112V     193.9mV    1.444V
6.783ns   1.16V      621.7mV    1.445V
8.891ns   1.163V     762.6mV    1.445V
31.16ns   1.163V     806.8mV    1.445V
[Rising Waveform]
R_fixture= 0.1320k
V_fixture= 1.8000
V_fixture_min= 1.6500
V_fixture_max= 1.9500
|time   V(typ)   V(min)   V(max)
0s        626mV      935.4mV    450mV
955ps     597.3mV    914.5mV    546mV
1.133ns   616.4mV    904.9mV    783.8mV
1.544ns   842.4mV    888.8mV    1.799V
1.886ns   1.276V     898.5mV    1.939V
2.162ns   1.621V     941.5mV    1.944V
2.429ns   1.764V     1.018V     1.946V
3.637ns   1.797V     1.541V     1.95V
4.29ns    1.798V     1.639V     1.95V
31.16ns   1.8V       1.65V      1.95V
[Falling Waveform]
R_fixture= 0.1320k
V_fixture= 0.0
V_fixture_min= 0.0
V_fixture_max= 0.0
|time   V(typ)   V(min)   V(max)
0s        1.163V     806.8mV    1.445V
1.276ns   1.165V     808.6mV    1.369V
1.493ns   1.167V     808.7mV    1.056V
1.797ns   1.154V     809mV      157.8mV
2.046ns   1.085V     809.3mV    6.986mV
2.804ns   121.2mV    812.7mV    1.16mV
3.164ns   7.164mV    814.4mV    656.4uV
4.042ns   1.37mV     683.1mV    162uV
5.487ns   288.9uV    9.199mV    15.67uV
31.16ns   1.457nV    8.333nV    3.68nV
[Falling Waveform]
R_fixture= 0.1320k
V_fixture= 1.8000
V_fixture_min= 1.6500
V_fixture_max= 1.9500
|time   V(typ)   V(min)   V(max)
0s        1.8V       1.65V      1.95V
1.532ns   1.8V       1.65V      1.945V
2.489ns   1.805V     1.65V      737.9mV
2.888ns   1.641V     1.65V      562.5mV
3.683ns   1.111V     1.652V     476.7mV
4.394ns   835.4mV    1.66V      458.6mV
5.397ns   692.8mV    1.575V     451.7mV
7.86ns    631.7mV    1.127V     450mV
10.39ns   626.4mV    977.3mV    450mV
31.16ns   626mV      935.4mV    450mV
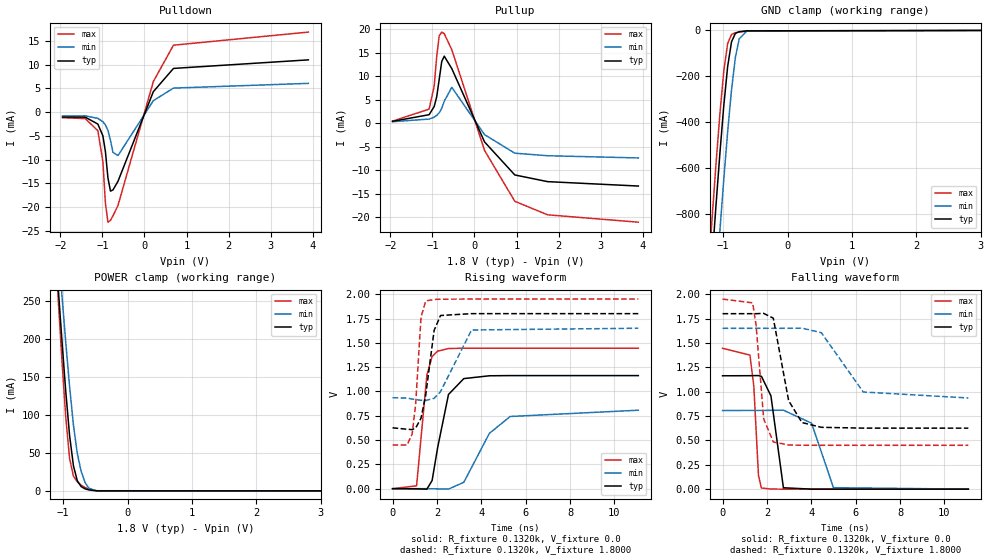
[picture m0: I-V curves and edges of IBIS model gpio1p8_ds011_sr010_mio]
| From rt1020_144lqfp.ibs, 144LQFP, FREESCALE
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[Model] gpio1p8_ds011_sr010_mio
|   Model gpio1p8_ds011_sr010_mio
| This model was characterised for following simulation conditions:
| External (pad) voltage:
|   - Typ: 1.8V,   - Min: 1.65V,   - Max: 1.95V
| Library cells for typ/min/max conditions are connected as defined below:
|  pad - External Pad
|  ipp_do - Core Input
|  ipp_obe - Output Buffer Enable
|  esd_boost - ovdd
|  ipp_dse0 - vddi
|  ipp_dse1 - vddi
|  ipp_dse2 - vssi
|  ipp_fsel0 - vssi
|  ipp_fsel1 - vddi
|  ipp_ina - ipp_ina
|  ipp_ind - ipp_ind
|  ipp_pwr_stable - vddi
|  ipp_sre - vssi
|  ovdd - ovdd
|  ovss - ovss
|  vddi - vddi
|  vssi - vssi
| All other pins connected to ground
Model_type I/O
Polarity   Non-Inverting
Enable   Active-High
Vinl =   0.5400V
Vinh =   1.2600V
Vmeas =  0.9000V
Cref =   0.0F
Rref =   0.1320k
Vref =   0.9000V
C_comp   1.2573pF   1.2208pF   1.3056pF
|C_comp_pullup   0.6440pF   0.6611pF   0.6285pF
|C_comp_pulldown   0.5474pF   0.5788pF   0.5258pF
[Model Spec]
| variable   typ   min   max
Vinh   1.2600V   1.1550V   1.3650V
Vinl   0.5400V   0.4950V   0.5850V
S_overshoot_high   1.8000V   1.6500V   1.9500V
S_overshoot_low   0.0V   0.0V   0.0V
Vmeas   0.9000V   0.8250V   0.9750V
Vref   0.9000V   0.8250V   0.9750V
Cref   0.0F   0.0F   0.0F
Rref   0.1320k   0.1320k   0.1320k
[Temperature Range]   25.0000   0.1050k   -20.0000
[Voltage Range]   1.8000V   1.6500V   1.9500V
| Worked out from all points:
|   slope of the pulldown table from 0 to 0.27 V, typ, clamps not added: 51.1 ohm
|   slope of the pullup table from 0 to 0.27 V, typ, clamps not added: 60.7 ohm
|   GND clamp passes 1 mA (typ) near -0.55 V on its own axis
|   POWER clamp passes 1 mA (typ) near -0.58 V on its own axis
|   rising waveform, R_fixture 0.1320k, V_fixture 0.0: 20-80 % time 551ps typ, 1.2ns min, 311ps max; typ from 0 V to 1.16 V
|   rising waveform, R_fixture 0.1320k, V_fixture 1.8000: 20-80 % time 411ps typ, 751ps min, 244ps max; typ from 0.626 V to 1.8 V
|   falling waveform, R_fixture 0.1320k, V_fixture 0.0: 20-80 % time 309ps typ, 573ps min, 199ps max; typ from 1.16 V to 0 V
|   falling waveform, R_fixture 0.1320k, V_fixture 1.8000: 20-80 % time 550ps typ, 1.03ns min, 313ps max; typ from 1.8 V to 0.626 V
[Pulldown]
|Voltage   I(typ)   I(min)   I(max)
-1.95V    -1.02mA    -793uA     -1.17mA
-1.41V    -1.051mA   -771uA     -1.353mA
-1.11V    -2.503mA   -1.306mA   -3.899mA
-990mV    -4.984mA   -2.008mA   -10.44mA
-930mV    -8.308mA   -2.685mA   -19.17mA
-870mV    -13.84mA   -3.86mA    -23.17mA
-810mV    -16.62mA   -5.918mA   -22.77mA
-750mV    -16.37mA   -8.456mA   -21.84mA
-630mV    -14.54mA   -9.133mA   -19.62mA
210mV     4.312mA    2.425mA    6.447mA
690mV     9.219mA    5.074mA    14.11mA
3.9V      11.02mA    6.07mA     16.87mA
[Pullup]
|Voltage   I(typ)   I(min)   I(max)
-1.95V    380uA      300uA      430uA
-1.08V    1.792mA    861uA      2.975mA
-960mV    3.514mA    1.267mA    7.834mA
-900mV    5.585mA    1.631mA    14.1mA
-840mV    9.305mA    2.201mA    18.57mA
-780mV    13.1mA     3.135mA    19.37mA
-720mV    14.25mA    4.65mA     19.03mA
-540mV    11.59mA    7.612mA    15.62mA
240mV     -4.012mA   -2.457mA   -5.822mA
960mV     -11.03mA   -6.4mA     -16.64mA
1.74V     -12.45mA   -6.938mA   -19.51mA
3.9V      -13.39mA   -7.407mA   -21.08mA
[GND_clamp]
|Voltage   I(typ)   I(min)   I(max)
-1.95V    -4.191A    -4.477A    -4.042A
-1.23V    -1.234A    -1.577A    -1.052A
-1.17V    -993.2mA   -1.338A    -811.1mA
-1.11V    -758.1mA   -1.102A    -578.5mA
-1.05V    -533.7mA   -870.8mA   -361.6mA
-990mV    -328mA     -648.8mA   -176.9mA
-930mV    -157.5mA   -441.8mA   -57.56mA
-870mV    -50.13mA   -259.5mA   -18.17mA
-810mV    -13.28mA   -118mA     -10.41mA
-750mV    -5.921mA   -36.52mA   -7.502mA
-630mV    -2.275mA   -2.653mA   -3.283mA
3.9V      0A         0A         0A
[POWER_clamp]
|Voltage   I(typ)   I(min)   I(max)
-1.95V    1.356A     1.328A     1.514A
-1.08V    270.6mA    322.7mA    256.8mA
-1.02V    199mA      258.1mA    173mA
-960mV    131.2mA    195.7mA    97.36mA
-900mV    72.67mA    137.2mA    42.48mA
-840mV    32.99mA    86.34mA    19.5mA
-780mV    13.32mA    48.87mA    11.87mA
-720mV    5.671mA    25.66mA    7.515mA
-660mV    2.793mA    11.19mA    4.477mA
-600mV    1.289mA    3.449mA    2.334mA
-480mV    122.1uA    182.3uA    260.9uA
3.9V      0A         0A         0A
[Ramp]
| variable   typ   min   max
dV/dt_r  0.6978/0.5515n   0.4841/1.2023n   0.8672/0.3109n
dV/dt_f  0.7044/0.5501n   0.4287/1.0314n   0.9000/0.3126n
R_load = 0.1320k
[Rising Waveform]
R_fixture= 0.1320k
V_fixture= 0.0
V_fixture_min= 0.0
V_fixture_max= 0.0
|time   V(typ)   V(min)   V(max)
0s        711.9pV    6.687nV    1.441nV
1.083ns   -2.131mV   172.8uV    29.47mV
1.546ns   -5.151mV   -182.5uV   1.167V
1.782ns   83.33mV    -875.4uV   1.358V
2.033ns   422.8mV    -2.005mV   1.415V
2.521ns   968.7mV    -4.505mV   1.441V
3.212ns   1.132V     65.38mV    1.445V
4.363ns   1.161V     568mV      1.445V
5.3ns     1.163V     742.3mV    1.445V
11.08ns   1.163V     806.8mV    1.445V
[Rising Waveform]
R_fixture= 0.1320k
V_fixture= 1.8000
V_fixture_min= 1.6500
V_fixture_max= 1.9500
|time   V(typ)   V(min)   V(max)
0s        626mV      935.4mV    450mV
648.9ps   611.3mV    931.9mV    448.2mV
882.2ps   607.6mV    922.1mV    560.2mV
1.04ns    622.9mV    916.4mV    867mV
1.282ns   724.5mV    909.2mV    1.763V
1.494ns   961.7mV    906.2mV    1.931V
1.874ns   1.628V     929mV      1.946V
2.161ns   1.781V     997.3mV    1.949V
3.561ns   1.8V       1.632V     1.95V
11.08ns   1.8V       1.65V      1.95V
[Falling Waveform]
R_fixture= 0.1320k
V_fixture= 0.0
V_fixture_min= 0.0
V_fixture_max= 0.0
|time   V(typ)   V(min)   V(max)
0s        1.163V     806.8mV    1.445V
1.234ns   1.164V     807.8mV    1.376V
1.409ns   1.165V     807.9mV    1.056V
1.62ns    1.165V     807.9mV    136.7mV
1.754ns   1.157V     808mV      11.99mV
2.181ns   956.6mV    808.3mV    1.143mV
2.743ns   14.32mV    810.1mV    230.1uV
4.012ns   276.9uV    677mV      25.27uV
4.999ns   54.44uV    15.27mV    4.949uV
11.08ns   145.2nV    1.746uV    -208.3nV
[Falling Waveform]
R_fixture= 0.1320k
V_fixture= 1.8000
V_fixture_min= 1.6500
V_fixture_max= 1.9500
|time   V(typ)   V(min)   V(max)
0s        1.8V       1.65V      1.95V
1.357ns   1.8V       1.65V      1.911V
1.514ns   1.8V       1.65V      1.676V
1.854ns   1.803V     1.65V      720.9mV
2.287ns   1.754V     1.65V      484.3mV
2.979ns   907.4mV    1.65V      453.2mV
3.58ns    683.4mV    1.652V     450.6mV
4.452ns   634.5mV    1.605V     450.1mV
6.344ns   626.1mV    996.6mV    450mV
11.08ns   626mV      935.5mV    450mV
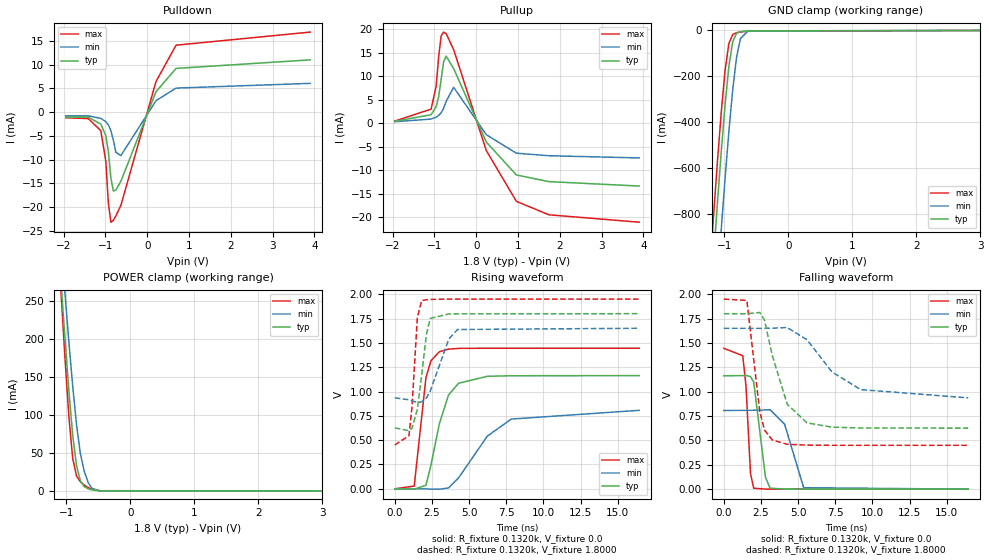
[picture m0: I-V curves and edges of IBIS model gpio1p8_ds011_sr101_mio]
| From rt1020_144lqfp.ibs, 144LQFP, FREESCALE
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[Model] gpio1p8_ds011_sr101_mio
|   Model gpio1p8_ds011_sr101_mio
| This model was characterised for following simulation conditions:
| External (pad) voltage:
|   - Typ: 1.8V,   - Min: 1.65V,   - Max: 1.95V
| Library cells for typ/min/max conditions are connected as defined below:
|  pad - External Pad
|  ipp_do - Core Input
|  ipp_obe - Output Buffer Enable
|  esd_boost - ovdd
|  ipp_dse0 - vddi
|  ipp_dse1 - vddi
|  ipp_dse2 - vssi
|  ipp_fsel0 - vddi
|  ipp_fsel1 - vssi
|  ipp_ina - ipp_ina
|  ipp_ind - ipp_ind
|  ipp_pwr_stable - vddi
|  ipp_sre - vddi
|  ovdd - ovdd
|  ovss - ovss
|  vddi - vddi
|  vssi - vssi
| All other pins connected to ground
Model_type I/O
Polarity   Non-Inverting
Enable   Active-High
Vinl =   0.5400V
Vinh =   1.2600V
Vmeas =  0.9000V
Cref =   0.0F
Rref =   0.1320k
Vref =   0.9000V
C_comp   1.2573pF   1.2208pF   1.3054pF
|C_comp_pullup   0.6439pF   0.6609pF   0.6284pF
|C_comp_pulldown   0.5473pF   0.5786pF   0.5258pF
[Model Spec]
| variable   typ   min   max
Vinh   1.2600V   1.1550V   1.3650V
Vinl   0.5400V   0.4950V   0.5850V
S_overshoot_high   1.8000V   1.6500V   1.9500V
S_overshoot_low   0.0V   0.0V   0.0V
Vmeas   0.9000V   0.8250V   0.9750V
Vref   0.9000V   0.8250V   0.9750V
Cref   0.0F   0.0F   0.0F
Rref   0.1320k   0.1320k   0.1320k
[Temperature Range]   25.0000   0.1050k   -20.0000
[Voltage Range]   1.8000V   1.6500V   1.9500V
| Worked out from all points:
|   slope of the pulldown table from 0 to 0.27 V, typ, clamps not added: 51.1 ohm
|   slope of the pullup table from 0 to 0.27 V, typ, clamps not added: 60.7 ohm
|   GND clamp passes 1 mA (typ) near -0.55 V on its own axis
|   POWER clamp passes 1 mA (typ) near -0.58 V on its own axis
|   rising waveform, R_fixture 0.1320k, V_fixture 0.0: 20-80 % time 1.1ns typ, 2.5ns min, 584ps max; typ from 0 V to 1.16 V
|   rising waveform, R_fixture 0.1320k, V_fixture 1.8000: 20-80 % time 546ps typ, 954ps min, 348ps max; typ from 0.626 V to 1.8 V
|   falling waveform, R_fixture 0.1320k, V_fixture 0.0: 20-80 % time 454ps typ, 745ps min, 298ps max; typ from 1.16 V to 0 V
|   falling waveform, R_fixture 0.1320k, V_fixture 1.8000: 20-80 % time 1.31ns typ, 2.64ns min, 664ps max; typ from 1.8 V to 0.626 V
[Pulldown]
|Voltage   I(typ)   I(min)   I(max)
-1.95V    -1.02mA    -793uA     -1.17mA
-1.41V    -1.051mA   -771uA     -1.353mA
-1.11V    -2.503mA   -1.306mA   -3.899mA
-990mV    -4.984mA   -2.008mA   -10.44mA
-930mV    -8.308mA   -2.685mA   -19.17mA
-870mV    -13.84mA   -3.86mA    -23.17mA
-810mV    -16.62mA   -5.918mA   -22.77mA
-750mV    -16.37mA   -8.456mA   -21.84mA
-630mV    -14.54mA   -9.133mA   -19.62mA
210mV     4.312mA    2.425mA    6.447mA
690mV     9.219mA    5.074mA    14.11mA
3.9V      11.02mA    6.07mA     16.87mA
[Pullup]
|Voltage   I(typ)   I(min)   I(max)
-1.95V    380uA      300uA      430uA
-1.08V    1.792mA    861uA      2.975mA
-960mV    3.514mA    1.267mA    7.834mA
-900mV    5.585mA    1.631mA    14.1mA
-840mV    9.305mA    2.201mA    18.57mA
-780mV    13.1mA     3.135mA    19.37mA
-720mV    14.25mA    4.65mA     19.03mA
-540mV    11.59mA    7.612mA    15.62mA
240mV     -4.012mA   -2.457mA   -5.822mA
960mV     -11.03mA   -6.4mA     -16.64mA
1.74V     -12.45mA   -6.938mA   -19.51mA
3.9V      -13.39mA   -7.407mA   -21.08mA
[GND_clamp]
|Voltage   I(typ)   I(min)   I(max)
-1.95V    -4.191A    -4.477A    -4.042A
-1.23V    -1.234A    -1.577A    -1.052A
-1.17V    -993.2mA   -1.338A    -811.1mA
-1.11V    -758.1mA   -1.102A    -578.5mA
-1.05V    -533.7mA   -870.8mA   -361.6mA
-990mV    -328mA     -648.8mA   -176.9mA
-930mV    -157.5mA   -441.8mA   -57.56mA
-870mV    -50.13mA   -259.5mA   -18.17mA
-810mV    -13.28mA   -118mA     -10.41mA
-750mV    -5.921mA   -36.52mA   -7.502mA
-630mV    -2.275mA   -2.653mA   -3.283mA
3.9V      0A         0A         0A
[POWER_clamp]
|Voltage   I(typ)   I(min)   I(max)
-1.95V    1.356A     1.328A     1.514A
-1.08V    270.6mA    322.7mA    256.8mA
-1.02V    199mA      258.1mA    173mA
-960mV    131.2mA    195.7mA    97.36mA
-900mV    72.67mA    137.2mA    42.48mA
-840mV    32.99mA    86.34mA    19.5mA
-780mV    13.32mA    48.87mA    11.87mA
-720mV    5.671mA    25.66mA    7.515mA
-660mV    2.793mA    11.19mA    4.477mA
-600mV    1.289mA    3.449mA    2.334mA
-480mV    122.1uA    182.3uA    260.9uA
3.9V      0A         0A         0A
[Ramp]
| variable   typ   min   max
dV/dt_r  0.6978/1.0955n   0.4839/2.4990n   0.8672/0.5843n
dV/dt_f  0.7044/1.3081n   0.4281/2.6435n   0.9000/0.6639n
R_load = 0.1320k
[Rising Waveform]
R_fixture= 0.1320k
V_fixture= 0.0
V_fixture_min= 0.0
V_fixture_max= 0.0
|time   V(typ)   V(min)   V(max)
0s        711.9pV    6.687nV    1.441nV
1.309ns   -3.008mV   238.9uV    27.97mV
2.096ns   35.69mV    -1.378mV   1.142V
2.431ns   241.6mV    -2.353mV   1.316V
2.993ns   664.6mV    -3.744mV   1.408V
3.611ns   962.9mV    8.15mV     1.435V
4.29ns    1.085V     112mV      1.443V
6.223ns   1.156V     540.9mV    1.445V
7.832ns   1.162V     716.6mV    1.445V
16.44ns   1.163V     806.5mV    1.445V
[Rising Waveform]
R_fixture= 0.1320k
V_fixture= 1.8000
V_fixture_min= 1.6500
V_fixture_max= 1.9500
|time   V(typ)   V(min)   V(max)
0s        626mV      935.4mV    450mV
954.8ps   597.3mV    914.5mV    545.8mV
1.16ns    622.5mV    903.5mV    842.6mV
1.517ns   816.3mV    889.2mV    1.757V
1.806ns   1.164V     892.7mV    1.934V
2.124ns   1.583V     932.8mV    1.943V
2.38ns    1.751V     1.002V     1.946V
3.637ns   1.797V     1.54V      1.95V
4.22ns    1.798V     1.637V     1.95V
16.44ns   1.8V       1.65V      1.95V
[Falling Waveform]
R_fixture= 0.1320k
V_fixture= 0.0
V_fixture_min= 0.0
V_fixture_max= 0.0
|time   V(typ)   V(min)   V(max)
0s        1.163V     806.8mV    1.445V
1.276ns   1.165V     808.6mV    1.369V
1.493ns   1.167V     808.7mV    1.057V
1.797ns   1.154V     809mV      158.1mV
2.013ns   1.1V       809.2mV    9.287mV
2.803ns   121.5mV    812.7mV    1.16mV
3.113ns   9.772mV    814.7mV    716.3uV
4.093ns   1.3mV      665.5mV    149.3uV
5.373ns   330uV      14.89mV    18.26uV
16.44ns   16.53nV    3.79uV     9.796nV
[Falling Waveform]
R_fixture= 0.1320k
V_fixture= 1.8000
V_fixture_min= 1.6500
V_fixture_max= 1.9500
|time   V(typ)   V(min)   V(max)
0s        1.8V       1.65V      1.95V
1.552ns   1.8V       1.65V      1.936V
2.421ns   1.812V     1.65V      793mV
2.737ns   1.734V     1.65V      606.6mV
3.26ns    1.372V     1.651V     505.2mV
4.264ns   871.6mV    1.658V     460.4mV
5.596ns   680.1mV    1.533V     451.3mV
7.283ns   636.1mV    1.201V     450.1mV
9.218ns   627.5mV    1.021V     450mV
16.44ns   626mV      936.5mV    450mV
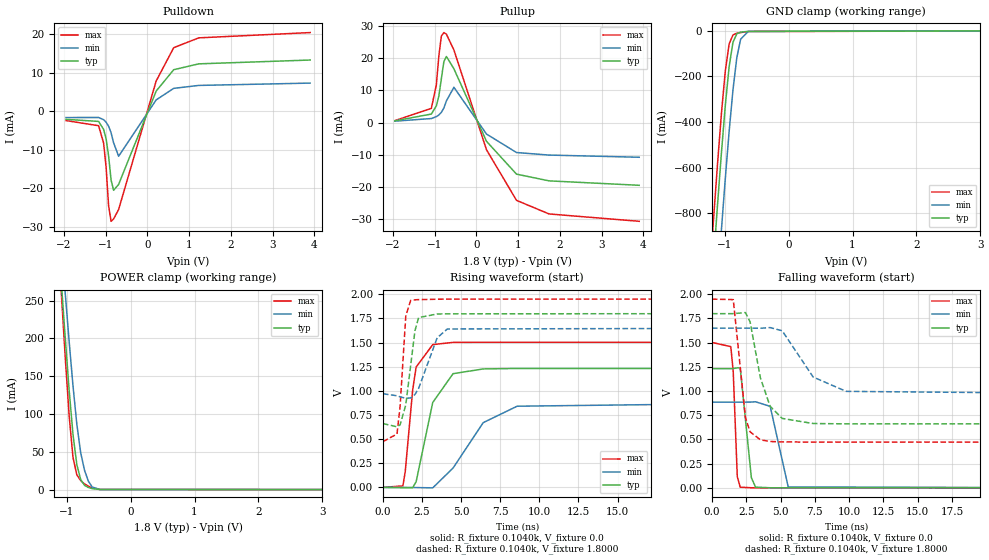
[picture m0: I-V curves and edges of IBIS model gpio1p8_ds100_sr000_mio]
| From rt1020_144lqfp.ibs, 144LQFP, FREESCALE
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[Model] gpio1p8_ds100_sr000_mio
|   Model gpio1p8_ds100_sr000_mio
| This model was characterised for following simulation conditions:
| External (pad) voltage:
|   - Typ: 1.8V,   - Min: 1.65V,   - Max: 1.95V
| Library cells for typ/min/max conditions are connected as defined below:
|  pad - External Pad
|  ipp_do - Core Input
|  ipp_obe - Output Buffer Enable
|  esd_boost - ovdd
|  ipp_dse0 - vssi
|  ipp_dse1 - vssi
|  ipp_dse2 - vddi
|  ipp_fsel0 - vssi
|  ipp_fsel1 - vssi
|  ipp_ina - ipp_ina
|  ipp_ind - ipp_ind
|  ipp_pwr_stable - vddi
|  ipp_sre - vssi
|  ovdd - ovdd
|  ovss - ovss
|  vddi - vddi
|  vssi - vssi
| All other pins connected to ground
Model_type I/O
Polarity   Non-Inverting
Enable   Active-High
Vinl =   0.5400V
Vinh =   1.2600V
Vmeas =  0.9000V
Cref =   0.0F
Rref =   0.1040k
Vref =   0.9000V
C_comp   1.2573pF   1.2208pF   1.3054pF
|C_comp_pullup   0.6439pF   0.6609pF   0.6284pF
|C_comp_pulldown   0.5473pF   0.5786pF   0.5258pF
[Model Spec]
| variable   typ   min   max
Vinh   1.2600V   1.1550V   1.3650V
Vinl   0.5400V   0.4950V   0.5850V
S_overshoot_high   1.8000V   1.6500V   1.9500V
S_overshoot_low   0.0V   0.0V   0.0V
Vmeas   0.9000V   0.8250V   0.9750V
Vref   0.9000V   0.8250V   0.9750V
Cref   0.0F   0.0F   0.0F
Rref   0.1040k   0.1040k   0.1040k
[Temperature Range]   25.0000   0.1050k   -20.0000
[Voltage Range]   1.8000V   1.6500V   1.9500V
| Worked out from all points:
|   slope of the pulldown table from 0 to 0.27 V, typ, clamps not added: 42.3 ohm
|   slope of the pullup table from 0 to 0.27 V, typ, clamps not added: 41.8 ohm
|   GND clamp passes 1 mA (typ) near -0.55 V on its own axis
|   POWER clamp passes 1 mA (typ) near -0.58 V on its own axis
|   rising waveform, R_fixture 0.1040k, V_fixture 0.0: 20-80 % time 1.03ns typ, 2.26ns min, 565ps max; typ from 0 V to 1.23 V
|   rising waveform, R_fixture 0.1040k, V_fixture 1.8000: 20-80 % time 506ps typ, 874ps min, 333ps max; typ from 0.661 V to 1.8 V
|   falling waveform, R_fixture 0.1040k, V_fixture 0.0: 20-80 % time 346ps typ, 560ps min, 230ps max; typ from 1.23 V to 0 V
|   falling waveform, R_fixture 0.1040k, V_fixture 1.8000: 20-80 % time 1.12ns typ, 2.14ns min, 573ps max; typ from 1.8 V to 0.661 V
[Pulldown]
|Voltage   I(typ)   I(min)   I(max)
-1.95V    -2.116mA   -1.648mA   -2.433mA
-1.17V    -2.655mA   -1.64mA    -3.771mA
-1.05V    -4.712mA   -2.199mA   -8.241mA
-990mV    -7.134mA   -2.853mA   -14.49mA
-930mV    -11.63mA   -3.901mA   -24.57mA
-870mV    -17.89mA   -5.605mA   -28.55mA
-810mV    -20.51mA   -8.198mA   -27.94mA
-690mV    -18.99mA   -11.69mA   -25.49mA
210mV     5.219mA    2.926mA    7.83mA
630mV     10.75mA    5.914mA    16.46mA
1.23V     12.27mA    6.677mA    19.01mA
3.9V      13.26mA    7.28mA     20.38mA
[Pullup]
|Voltage   I(typ)   I(min)   I(max)
-1.95V    560uA      440uA      630uA
-1.08V    2.65mA     1.257mA    4.43mA
-960mV    5.224mA    1.847mA    11.81mA
-900mV    8.315mA    2.377mA    20.88mA
-840mV    13.72mA    3.206mA    26.97mA
-780mV    19.01mA    4.561mA    28.05mA
-720mV    20.6mA     6.748mA    27.55mA
-540mV    16.77mA    11mA       22.63mA
240mV     -5.825mA   -3.571mA   -8.452mA
960mV     -16.07mA   -9.337mA   -24.24mA
1.74V     -18.17mA   -10.13mA   -28.48mA
3.9V      -19.55mA   -10.81mA   -30.77mA
[GND_clamp]
|Voltage   I(typ)   I(min)   I(max)
-1.95V    -4.191A    -4.477A    -4.042A
-1.23V    -1.234A    -1.577A    -1.052A
-1.17V    -993.2mA   -1.338A    -811.1mA
-1.11V    -758.1mA   -1.102A    -578.5mA
-1.05V    -533.7mA   -870.8mA   -361.6mA
-990mV    -328mA     -648.8mA   -176.9mA
-930mV    -157.5mA   -441.8mA   -57.56mA
-870mV    -50.13mA   -259.5mA   -18.17mA
-810mV    -13.28mA   -118mA     -10.41mA
-750mV    -5.921mA   -36.52mA   -7.502mA
-630mV    -2.275mA   -2.653mA   -3.283mA
3.9V      0A         0A         0A
[POWER_clamp]
|Voltage   I(typ)   I(min)   I(max)
-1.95V    1.356A     1.328A     1.514A
-1.08V    270.6mA    322.7mA    256.8mA
-1.02V    199mA      258.1mA    173mA
-960mV    131.2mA    195.7mA    97.36mA
-900mV    72.67mA    137.2mA    42.48mA
-840mV    32.99mA    86.34mA    19.5mA
-780mV    13.32mA    48.87mA    11.87mA
-720mV    5.671mA    25.66mA    7.515mA
-660mV    2.793mA    11.19mA    4.477mA
-600mV    1.289mA    3.449mA    2.334mA
-480mV    122.1uA    182.3uA    260.9uA
3.9V      0A         0A         0A
[Ramp]
| variable   typ   min   max
dV/dt_r  0.7391/1.0299n   0.5313/2.2640n   0.9019/0.5652n
dV/dt_f  0.6833/1.1203n   0.4079/2.1394n   0.8860/0.5734n
R_load = 0.1040k
[Rising Waveform]
R_fixture= 0.1040k
V_fixture= 0.0
V_fixture_min= 0.0
V_fixture_max= 0.0
|time   V(typ)   V(min)   V(max)
0s        580.6pV    5.471nV    1.176nV
1.282ns   -3.308mV   267.1uV    15.58mV
1.432ns   -4.529mV   155.1uV    164.5mV
1.902ns   -3.518mV   -990.7uV   1.004V
2.127ns   58.37mV    -1.827mV   1.246V
3.189ns   879.5mV    -4.714mV   1.479V
4.488ns   1.178V     200.5mV    1.502V
6.416ns   1.227V     670.9mV    1.503V
8.583ns   1.232V     840.9mV    1.503V
31.5ns    1.232V     885.4mV    1.503V
[Rising Waveform]
R_fixture= 0.1040k
V_fixture= 1.8000
V_fixture_min= 1.6500
V_fixture_max= 1.9500
|time   V(typ)   V(min)   V(max)
0s        661.1mV    970.1mV    473.3mV
905ps     627.9mV    949.3mV    553.2mV
1.103ns   648.5mV    938.3mV    838.4mV
1.466ns   854.4mV    922.8mV    1.775V
1.778ns   1.262V     926.7mV    1.937V
2.051ns   1.622V     962mV      1.943V
2.288ns   1.759V     1.026V     1.945V
3.471ns   1.796V     1.549V     1.949V
4.124ns   1.798V     1.641V     1.95V
31.5ns    1.8V       1.65V      1.95V
[Falling Waveform]
R_fixture= 0.1040k
V_fixture= 0.0
V_fixture_min= 0.0
V_fixture_max= 0.0
|time   V(typ)   V(min)   V(max)
0s        1.232V     885.4mV    1.503V
1.379ns   1.232V     885.2mV    1.459V
1.555ns   1.233V     885.2mV    1.203V
1.852ns   1.24V      885.2mV    115.4mV
2.065ns   1.24V      885.2mV    6.969mV
2.877ns   104.7mV    886.5mV    913.9uV
3.184ns   7.29mV     889.5mV    525uV
4.249ns   987.4uV    841.7mV    74.65uV
5.561ns   185.7uV    9.564mV    7.103uV
31.5ns    1.323nV    9.109nV    3.065nV
[Falling Waveform]
R_fixture= 0.1040k
V_fixture= 1.8000
V_fixture_min= 1.6500
V_fixture_max= 1.9500
|time   V(typ)   V(min)   V(max)
0s        1.8V       1.65V      1.95V
1.559ns   1.8V       1.65V      1.945V
2.446ns   1.811V     1.65V      726.2mV
2.783ns   1.716V     1.65V      579.5mV
3.534ns   1.137V     1.649V     495.9mV
4.241ns   842.8mV    1.656V     479.3mV
5.122ns   717.6mV    1.623V     474.3mV
7.378ns   664.7mV    1.145V     473.3mV
9.781ns   661.3mV    997mV      473.3mV
31.5ns    661.1mV    970.1mV    473.3mV
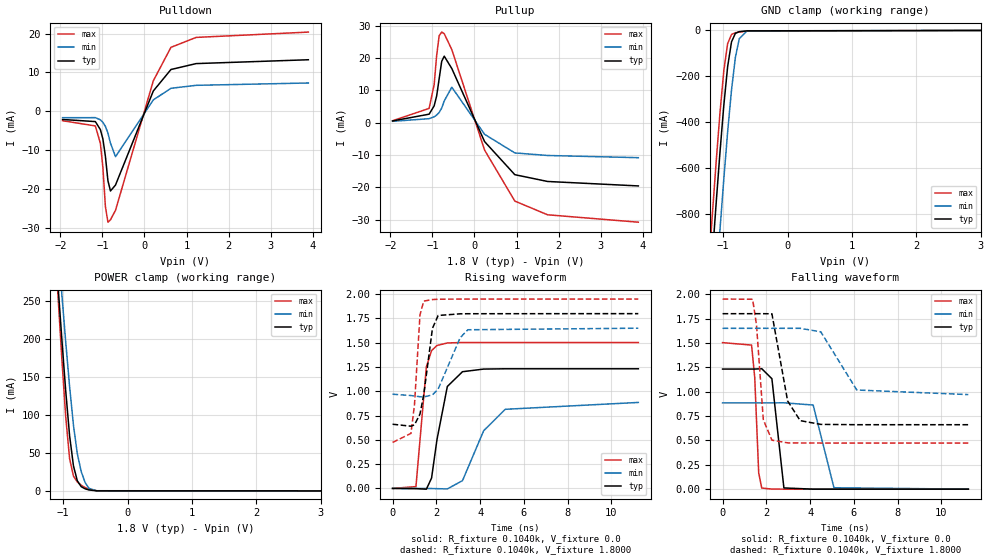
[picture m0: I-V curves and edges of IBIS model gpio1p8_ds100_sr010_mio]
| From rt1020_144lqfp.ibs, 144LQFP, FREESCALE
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[Model] gpio1p8_ds100_sr010_mio
|   Model gpio1p8_ds100_sr010_mio
| This model was characterised for following simulation conditions:
| External (pad) voltage:
|   - Typ: 1.8V,   - Min: 1.65V,   - Max: 1.95V
| Library cells for typ/min/max conditions are connected as defined below:
|  pad - External Pad
|  ipp_do - Core Input
|  ipp_obe - Output Buffer Enable
|  esd_boost - ovdd
|  ipp_dse0 - vssi
|  ipp_dse1 - vssi
|  ipp_dse2 - vddi
|  ipp_fsel0 - vssi
|  ipp_fsel1 - vddi
|  ipp_ina - ipp_ina
|  ipp_ind - ipp_ind
|  ipp_pwr_stable - vddi
|  ipp_sre - vssi
|  ovdd - ovdd
|  ovss - ovss
|  vddi - vddi
|  vssi - vssi
| All other pins connected to ground
Model_type I/O
Polarity   Non-Inverting
Enable   Active-High
Vinl =   0.5400V
Vinh =   1.2600V
Vmeas =  0.9000V
Cref =   0.0F
Rref =   0.1040k
Vref =   0.9000V
C_comp   1.2573pF   1.2208pF   1.3056pF
|C_comp_pullup   0.6440pF   0.6611pF   0.6285pF
|C_comp_pulldown   0.5474pF   0.5788pF   0.5258pF
[Model Spec]
| variable   typ   min   max
Vinh   1.2600V   1.1550V   1.3650V
Vinl   0.5400V   0.4950V   0.5850V
S_overshoot_high   1.8000V   1.6500V   1.9500V
S_overshoot_low   0.0V   0.0V   0.0V
Vmeas   0.9000V   0.8250V   0.9750V
Vref   0.9000V   0.8250V   0.9750V
Cref   0.0F   0.0F   0.0F
Rref   0.1040k   0.1040k   0.1040k
[Temperature Range]   25.0000   0.1050k   -20.0000
[Voltage Range]   1.8000V   1.6500V   1.9500V
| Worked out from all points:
|   slope of the pulldown table from 0 to 0.27 V, typ, clamps not added: 42.3 ohm
|   slope of the pullup table from 0 to 0.27 V, typ, clamps not added: 41.8 ohm
|   GND clamp passes 1 mA (typ) near -0.55 V on its own axis
|   POWER clamp passes 1 mA (typ) near -0.58 V on its own axis
|   rising waveform, R_fixture 0.1040k, V_fixture 0.0: 20-80 % time 526ps typ, 1.13ns min, 297ps max; typ from 0 V to 1.23 V
|   rising waveform, R_fixture 0.1040k, V_fixture 1.8000: 20-80 % time 401ps typ, 719ps min, 240ps max; typ from 0.661 V to 1.8 V
|   falling waveform, R_fixture 0.1040k, V_fixture 0.0: 20-80 % time 234ps typ, 398ps min, 163ps max; typ from 1.23 V to 0 V
|   falling waveform, R_fixture 0.1040k, V_fixture 1.8000: 20-80 % time 459ps typ, 814ps min, 269ps max; typ from 1.8 V to 0.661 V
[Pulldown]
|Voltage   I(typ)   I(min)   I(max)
-1.95V    -2.116mA   -1.648mA   -2.433mA
-1.17V    -2.655mA   -1.64mA    -3.771mA
-1.05V    -4.712mA   -2.199mA   -8.241mA
-990mV    -7.134mA   -2.853mA   -14.49mA
-930mV    -11.63mA   -3.901mA   -24.57mA
-870mV    -17.89mA   -5.605mA   -28.55mA
-810mV    -20.51mA   -8.198mA   -27.94mA
-690mV    -18.99mA   -11.69mA   -25.49mA
210mV     5.219mA    2.926mA    7.83mA
630mV     10.75mA    5.914mA    16.46mA
1.23V     12.27mA    6.677mA    19.01mA
3.9V      13.26mA    7.28mA     20.38mA
[Pullup]
|Voltage   I(typ)   I(min)   I(max)
-1.95V    560uA      440uA      630uA
-1.08V    2.65mA     1.257mA    4.43mA
-960mV    5.224mA    1.847mA    11.81mA
-900mV    8.315mA    2.377mA    20.88mA
-840mV    13.72mA    3.206mA    26.97mA
-780mV    19.01mA    4.561mA    28.05mA
-720mV    20.6mA     6.748mA    27.55mA
-540mV    16.77mA    11mA       22.63mA
240mV     -5.825mA   -3.571mA   -8.452mA
960mV     -16.07mA   -9.337mA   -24.24mA
1.74V     -18.17mA   -10.13mA   -28.48mA
3.9V      -19.55mA   -10.81mA   -30.77mA
[GND_clamp]
|Voltage   I(typ)   I(min)   I(max)
-1.95V    -4.191A    -4.477A    -4.042A
-1.23V    -1.234A    -1.577A    -1.052A
-1.17V    -993.2mA   -1.338A    -811.1mA
-1.11V    -758.1mA   -1.102A    -578.5mA
-1.05V    -533.7mA   -870.8mA   -361.6mA
-990mV    -328mA     -648.8mA   -176.9mA
-930mV    -157.5mA   -441.8mA   -57.56mA
-870mV    -50.13mA   -259.5mA   -18.17mA
-810mV    -13.28mA   -118mA     -10.41mA
-750mV    -5.921mA   -36.52mA   -7.502mA
-630mV    -2.275mA   -2.653mA   -3.283mA
3.9V      0A         0A         0A
[POWER_clamp]
|Voltage   I(typ)   I(min)   I(max)
-1.95V    1.356A     1.328A     1.514A
-1.08V    270.6mA    322.7mA    256.8mA
-1.02V    199mA      258.1mA    173mA
-960mV    131.2mA    195.7mA    97.36mA
-900mV    72.67mA    137.2mA    42.48mA
-840mV    32.99mA    86.34mA    19.5mA
-780mV    13.32mA    48.87mA    11.87mA
-720mV    5.671mA    25.66mA    7.515mA
-660mV    2.793mA    11.19mA    4.477mA
-600mV    1.289mA    3.449mA    2.334mA
-480mV    122.1uA    182.3uA    260.9uA
3.9V      0A         0A         0A
[Ramp]
| variable   typ   min   max
dV/dt_r  0.7391/0.5256n   0.5313/1.1285n   0.9019/0.2967n
dV/dt_f  0.6833/0.4587n   0.4079/0.8135n   0.8860/0.2686n
R_load = 0.1040k
[Rising Waveform]
R_fixture= 0.1040k
V_fixture= 0.0
V_fixture_min= 0.0
V_fixture_max= 0.0
|time   V(typ)   V(min)   V(max)
0s        580.6pV    5.426nV    1.176nV
1.068ns   -2.335mV   178.1uV    18.66mV
1.545ns   -7.641mV   -289.2uV   1.253V
1.782ns   106.7mV    -1.127mV   1.419V
2.029ns   502.4mV    -2.445mV   1.472V
2.503ns   1.05V      -5.386mV   1.498V
3.196ns   1.202V     80.56mV    1.503V
4.162ns   1.229V     593.9mV    1.503V
5.149ns   1.232V     814.8mV    1.503V
11.23ns   1.232V     885.5mV    1.503V
[Rising Waveform]
R_fixture= 0.1040k
V_fixture= 1.8000
V_fixture_min= 1.6500
V_fixture_max= 1.9500
|time   V(typ)   V(min)   V(max)
0s        661.1mV    970.1mV    473.3mV
841.7ps   640.7mV    956.8mV    566.9mV
1.002ns   654.7mV    951.2mV    863mV
1.253ns   766.1mV    944.3mV    1.787V
1.424ns   963.5mV    941.8mV    1.929V
1.823ns   1.649V     963.3mV    1.945V
2.084ns   1.781V     1.024V     1.948V
3.089ns   1.798V     1.552V     1.95V
3.442ns   1.799V     1.634V     1.95V
11.23ns   1.8V       1.65V      1.95V
[Falling Waveform]
R_fixture= 0.1040k
V_fixture= 0.0
V_fixture_min= 0.0
V_fixture_max= 0.0
|time   V(typ)   V(min)   V(max)
0s        1.232V     885.4mV    1.503V
1.325ns   1.232V     885.3mV    1.478V
1.47ns    1.232V     885.3mV    1.145V
1.651ns   1.234V     885.3mV    166.5mV
1.789ns   1.236V     885.3mV    11.67mV
2.254ns   1.133V     885.3mV    798.8uV
2.802ns   12.58mV    886mV      153.6uV
4.141ns   148uV      862.7mV    19.41uV
5.09ns    32.15uV    14.56mV    4.147uV
11.23ns   -506.8nV   1.291uV    -154.5nV
[Falling Waveform]
R_fixture= 0.1040k
V_fixture= 1.8000
V_fixture_min= 1.6500
V_fixture_max= 1.9500
|time   V(typ)   V(min)   V(max)
0s        1.8V       1.65V      1.95V
1.374ns   1.8V       1.65V      1.948V
1.55ns    1.8V       1.65V      1.686V
1.862ns   1.8V       1.65V      712.6mV
2.255ns   1.799V     1.65V      502.6mV
2.972ns   905mV      1.65V      474.8mV
3.547ns   702.9mV    1.65V      473.5mV
4.487ns   664.5mV    1.614V     473.3mV
6.133ns   661.2mV    1.017V     473.3mV
11.23ns   661.1mV    970.1mV    473.3mV
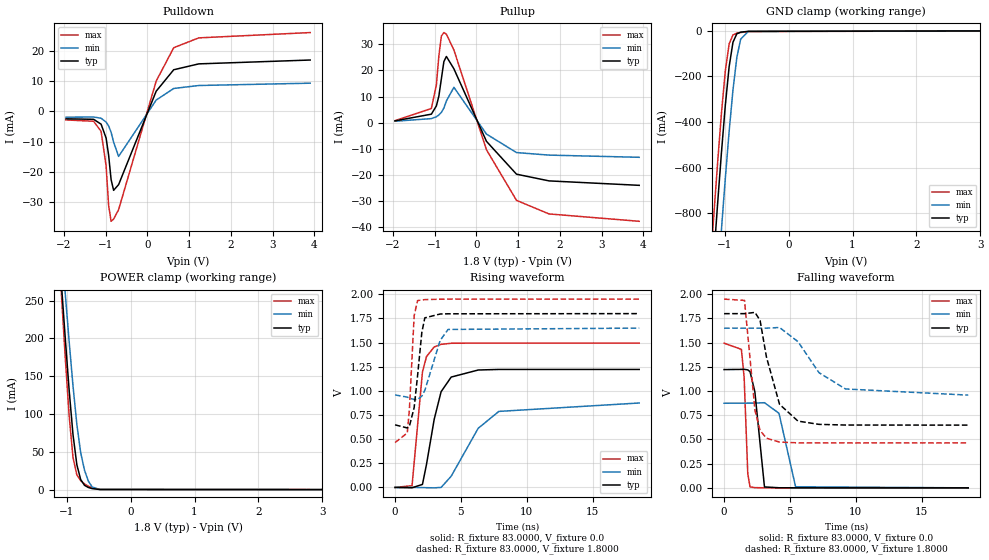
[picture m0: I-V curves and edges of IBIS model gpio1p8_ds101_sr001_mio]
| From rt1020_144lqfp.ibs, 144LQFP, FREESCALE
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[Model] gpio1p8_ds101_sr001_mio
|   Model gpio1p8_ds101_sr001_mio
| This model was characterised for following simulation conditions:
| External (pad) voltage:
|   - Typ: 1.8V,   - Min: 1.65V,   - Max: 1.95V
| Library cells for typ/min/max conditions are connected as defined below:
|  pad - External Pad
|  ipp_do - Core Input
|  ipp_obe - Output Buffer Enable
|  esd_boost - ovdd
|  ipp_dse0 - vddi
|  ipp_dse1 - vssi
|  ipp_dse2 - vddi
|  ipp_fsel0 - vddi
|  ipp_fsel1 - vssi
|  ipp_ina - ipp_ina
|  ipp_ind - ipp_ind
|  ipp_pwr_stable - vddi
|  ipp_sre - vssi
|  ovdd - ovdd
|  ovss - ovss
|  vddi - vddi
|  vssi - vssi
| All other pins connected to ground
Model_type I/O
Polarity   Non-Inverting
Enable   Active-High
Vinl =   0.5400V
Vinh =   1.2600V
Vmeas =  0.9000V
Cref =   0.0F
Rref =   83.0000
Vref =   0.9000V
C_comp   1.2573pF   1.2208pF   1.3054pF
|C_comp_pullup   0.6439pF   0.6609pF   0.6284pF
|C_comp_pulldown   0.5473pF   0.5786pF   0.5258pF
[Model Spec]
| variable   typ   min   max
Vinh   1.2600V   1.1550V   1.3650V
Vinl   0.5400V   0.4950V   0.5850V
S_overshoot_high   1.8000V   1.6500V   1.9500V
S_overshoot_low   0.0V   0.0V   0.0V
Vmeas   0.9000V   0.8250V   0.9750V
Vref   0.9000V   0.8250V   0.9750V
Cref   0.0F   0.0F   0.0F
Rref   83.0000   83.0000   83.0000
[Temperature Range]   25.0000   0.1050k   -20.0000
[Voltage Range]   1.8000V   1.6500V   1.9500V
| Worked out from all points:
|   slope of the pulldown table from 0 to 0.27 V, typ, clamps not added: 33.1 ohm
|   slope of the pullup table from 0 to 0.27 V, typ, clamps not added: 34 ohm
|   GND clamp passes 1 mA (typ) near -0.55 V on its own axis
|   POWER clamp passes 1 mA (typ) near -0.58 V on its own axis
|   rising waveform, R_fixture 83.0000, V_fixture 0.0: 20-80 % time 1.07ns typ, 2.41ns min, 574ps max; typ from 0 V to 1.22 V
|   rising waveform, R_fixture 83.0000, V_fixture 1.8000: 20-80 % time 502ps typ, 892ps min, 323ps max; typ from 0.648 V to 1.8 V
|   falling waveform, R_fixture 83.0000, V_fixture 0.0: 20-80 % time 387ps typ, 641ps min, 250ps max; typ from 1.22 V to 0 V
|   falling waveform, R_fixture 83.0000, V_fixture 1.8000: 20-80 % time 1.21ns typ, 2.43ns min, 598ps max; typ from 1.8 V to 0.648 V
[Pulldown]
|Voltage   I(typ)   I(min)   I(max)
-1.95V    -2.457mA   -1.914mA   -2.825mA
-1.29V    -2.614mA   -1.868mA   -3.261mA
-1.11V    -4.227mA   -2.263mA   -6.582mA
-990mV    -8.797mA   -3.523mA   -17.97mA
-930mV    -14.4mA    -4.797mA   -30.96mA
-870mV    -22.51mA   -6.893mA   -36.27mA
-810mV    -26.05mA   -10.17mA   -35.53mA
-690mV    -24.16mA   -14.85mA   -32.42mA
210mV     6.656mA    3.734mA    9.979mA
630mV     13.73mA    7.555mA    21mA
1.23V     15.67mA    8.534mA    24.25mA
3.9V      16.94mA    9.3mA      26mA
[Pullup]
|Voltage   I(typ)   I(min)   I(max)
-1.95V    690uA      540uA      780uA
-1.08V    3.247mA    1.544mA    5.422mA
-960mV    6.396mA    2.27mA     14.43mA
-900mV    10.18mA    2.92mA     25.61mA
-840mV    16.83mA    3.941mA    33.18mA
-780mV    23.39mA    5.607mA    34.51mA
-720mV    25.35mA    8.301mA    33.89mA
-540mV    20.63mA    13.54mA    27.83mA
240mV     -7.162mA   -4.39mA    -10.39mA
960mV     -19.75mA   -11.47mA   -29.78mA
1.74V     -22.32mA   -12.44mA   -34.98mA
3.9V      -24.02mA   -13.28mA   -37.8mA
[GND_clamp]
|Voltage   I(typ)   I(min)   I(max)
-1.95V    -4.191A    -4.477A    -4.042A
-1.23V    -1.234A    -1.577A    -1.052A
-1.17V    -993.2mA   -1.338A    -811.1mA
-1.11V    -758.1mA   -1.102A    -578.5mA
-1.05V    -533.7mA   -870.8mA   -361.6mA
-990mV    -328mA     -648.8mA   -176.9mA
-930mV    -157.5mA   -441.8mA   -57.56mA
-870mV    -50.13mA   -259.5mA   -18.17mA
-810mV    -13.28mA   -118mA     -10.41mA
-750mV    -5.921mA   -36.52mA   -7.502mA
-630mV    -2.275mA   -2.653mA   -3.283mA
3.9V      0A         0A         0A
[POWER_clamp]
|Voltage   I(typ)   I(min)   I(max)
-1.95V    1.356A     1.328A     1.514A
-1.08V    270.6mA    322.7mA    256.8mA
-1.02V    199mA      258.1mA    173mA
-960mV    131.2mA    195.7mA    97.36mA
-900mV    72.67mA    137.2mA    42.48mA
-840mV    32.99mA    86.34mA    19.5mA
-780mV    13.32mA    48.87mA    11.87mA
-720mV    5.671mA    25.66mA    7.515mA
-660mV    2.793mA    11.19mA    4.477mA
-600mV    1.289mA    3.449mA    2.334mA
-480mV    122.1uA    182.3uA    260.9uA
3.9V      0A         0A         0A
[Ramp]
| variable   typ   min   max
dV/dt_r  0.7334/1.0681n   0.5246/2.4052n   0.8972/0.5745n
dV/dt_f  0.6911/1.2132n   0.4151/2.4286n   0.8914/0.5975n
R_load = 83.0000
[Rising Waveform]
R_fixture= 83.0000
V_fixture= 0.0
V_fixture_min= 0.0
V_fixture_max= 0.0
|time   V(typ)   V(min)   V(max)
0s        457.3pV    4.283nV    925.5pV
1.291ns   -3.273mV   259.6uV    18.23mV
2.081ns   31.4mV     -1.564mV   1.196V
2.39ns    240.2mV    -2.56mV    1.356V
2.973ns   705.7mV    -4.267mV   1.455V
3.498ns   991.8mV    160.2uV    1.482V
4.264ns   1.143V     116.7mV    1.493V
6.312ns   1.216V     612.1mV    1.495V
7.881ns   1.222V     787.4mV    1.495V
18.54ns   1.222V     874.4mV    1.495V
[Rising Waveform]
R_fixture= 83.0000
V_fixture= 1.8000
V_fixture_min= 1.6500
V_fixture_max= 1.9500
|time   V(typ)   V(min)   V(max)
0s        648.2mV    958mV      464.3mV
927.4ps   616mV      935mV      564.2mV
1.088ns   632.9mV    926.1mV    803.4mV
1.451ns   827.4mV    910.1mV    1.778V
1.705ns   1.15V      910.1mV    1.934V
2.032ns   1.604V     945.5mV    1.942V
2.26ns    1.756V     1.005V     1.945V
3.427ns   1.796V     1.523V     1.949V
4.026ns   1.798V     1.636V     1.95V
18.54ns   1.8V       1.65V      1.95V
[Falling Waveform]
R_fixture= 83.0000
V_fixture= 0.0
V_fixture_min= 0.0
V_fixture_max= 0.0
|time   V(typ)   V(min)   V(max)
0s        1.222V     874.4mV    1.495V
1.315ns   1.224V     875.3mV    1.431V
1.523ns   1.225V     875.4mV    1.143V
1.8ns     1.219V     875.5mV    147.2mV
1.972ns   1.201V     875.6mV    9.733mV
2.335ns   995.1mV    876mV      2.434mV
3.067ns   9.753mV    879.8mV    655.9uV
4.17ns    1.084mV    770.3mV    98.85uV
5.431ns   253.2uV    11.05mV    11.89uV
18.54ns   7.673nV    614.9nV    4.744nV
[Falling Waveform]
R_fixture= 83.0000
V_fixture= 1.8000
V_fixture_min= 1.6500
V_fixture_max= 1.9500
|time   V(typ)   V(min)   V(max)
0s        1.8V       1.65V      1.95V
1.55ns    1.8V       1.65V      1.937V
2.347ns   1.813V     1.65V      800.7mV
2.736ns   1.729V     1.65V      592.5mV
3.219ns   1.351V     1.65V      512.9mV
4.212ns   863.1mV    1.657V     473mV
5.611ns   689.7mV    1.511V     465.2mV
7.208ns   656mV      1.19V      464.4mV
9.219ns   649.1mV    1.022V     464.3mV
18.54ns   648.2mV    958.2mV    464.3mV
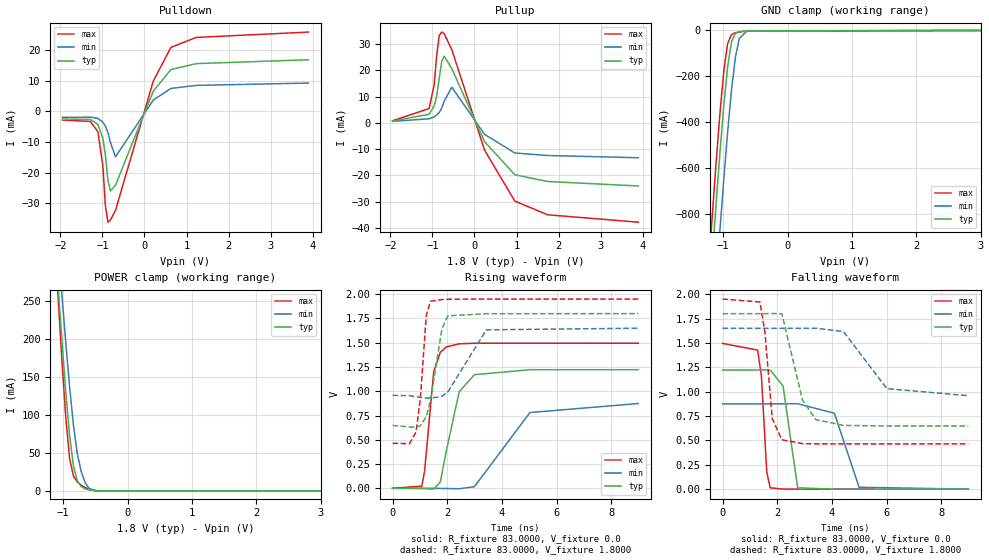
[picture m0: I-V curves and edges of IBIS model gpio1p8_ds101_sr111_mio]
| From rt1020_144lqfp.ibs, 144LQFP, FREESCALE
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[Model] gpio1p8_ds101_sr111_mio
|   Model gpio1p8_ds101_sr111_mio
| This model was characterised for following simulation conditions:
| External (pad) voltage:
|   - Typ: 1.8V,   - Min: 1.65V,   - Max: 1.95V
| Library cells for typ/min/max conditions are connected as defined below:
|  pad - External Pad
|  ipp_do - Core Input
|  ipp_obe - Output Buffer Enable
|  esd_boost - ovdd
|  ipp_dse0 - vddi
|  ipp_dse1 - vssi
|  ipp_dse2 - vddi
|  ipp_fsel0 - vddi
|  ipp_fsel1 - vddi
|  ipp_ina - ipp_ina
|  ipp_ind - ipp_ind
|  ipp_pwr_stable - vddi
|  ipp_sre - vddi
|  ovdd - ovdd
|  ovss - ovss
|  vddi - vddi
|  vssi - vssi
| All other pins connected to ground
Model_type I/O
Polarity   Non-Inverting
Enable   Active-High
Vinl =   0.5400V
Vinh =   1.2600V
Vmeas =  0.9000V
Cref =   0.0F
Rref =   83.0000
Vref =   0.9000V
C_comp   1.2573pF   1.2208pF   1.3056pF
|C_comp_pullup   0.6440pF   0.6611pF   0.6285pF
|C_comp_pulldown   0.5474pF   0.5788pF   0.5258pF
[Model Spec]
| variable   typ   min   max
Vinh   1.2600V   1.1550V   1.3650V
Vinl   0.5400V   0.4950V   0.5850V
S_overshoot_high   1.8000V   1.6500V   1.9500V
S_overshoot_low   0.0V   0.0V   0.0V
Vmeas   0.9000V   0.8250V   0.9750V
Vref   0.9000V   0.8250V   0.9750V
Cref   0.0F   0.0F   0.0F
Rref   83.0000   83.0000   83.0000
[Temperature Range]   25.0000   0.1050k   -20.0000
[Voltage Range]   1.8000V   1.6500V   1.9500V
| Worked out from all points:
|   slope of the pulldown table from 0 to 0.27 V, typ, clamps not added: 33.1 ohm
|   slope of the pullup table from 0 to 0.27 V, typ, clamps not added: 34 ohm
|   GND clamp passes 1 mA (typ) near -0.55 V on its own axis
|   POWER clamp passes 1 mA (typ) near -0.58 V on its own axis
|   rising waveform, R_fixture 83.0000, V_fixture 0.0: 20-80 % time 529ps typ, 1.17ns min, 292ps max; typ from 0 V to 1.22 V
|   rising waveform, R_fixture 83.0000, V_fixture 1.8000: 20-80 % time 393ps typ, 719ps min, 231ps max; typ from 0.648 V to 1.8 V
|   falling waveform, R_fixture 83.0000, V_fixture 0.0: 20-80 % time 263ps typ, 467ps min, 176ps max; typ from 1.22 V to 0 V
|   falling waveform, R_fixture 83.0000, V_fixture 1.8000: 20-80 % time 471ps typ, 888ps min, 266ps max; typ from 1.8 V to 0.648 V
[Pulldown]
|Voltage   I(typ)   I(min)   I(max)
-1.95V    -2.457mA   -1.914mA   -2.825mA
-1.29V    -2.614mA   -1.868mA   -3.261mA
-1.11V    -4.227mA   -2.263mA   -6.582mA
-990mV    -8.797mA   -3.523mA   -17.97mA
-930mV    -14.4mA    -4.797mA   -30.96mA
-870mV    -22.51mA   -6.893mA   -36.27mA
-810mV    -26.05mA   -10.17mA   -35.53mA
-690mV    -24.16mA   -14.85mA   -32.42mA
210mV     6.656mA    3.734mA    9.979mA
630mV     13.73mA    7.555mA    21mA
1.23V     15.67mA    8.534mA    24.25mA
3.9V      16.94mA    9.3mA      26mA
[Pullup]
|Voltage   I(typ)   I(min)   I(max)
-1.95V    690uA      540uA      780uA
-1.08V    3.247mA    1.544mA    5.422mA
-960mV    6.396mA    2.27mA     14.43mA
-900mV    10.18mA    2.92mA     25.61mA
-840mV    16.83mA    3.941mA    33.18mA
-780mV    23.39mA    5.607mA    34.51mA
-720mV    25.35mA    8.301mA    33.89mA
-540mV    20.63mA    13.54mA    27.83mA
240mV     -7.162mA   -4.39mA    -10.39mA
960mV     -19.75mA   -11.47mA   -29.78mA
1.74V     -22.32mA   -12.44mA   -34.98mA
3.9V      -24.02mA   -13.28mA   -37.8mA
[GND_clamp]
|Voltage   I(typ)   I(min)   I(max)
-1.95V    -4.191A    -4.477A    -4.042A
-1.23V    -1.234A    -1.577A    -1.052A
-1.17V    -993.2mA   -1.338A    -811.1mA
-1.11V    -758.1mA   -1.102A    -578.5mA
-1.05V    -533.7mA   -870.8mA   -361.6mA
-990mV    -328mA     -648.8mA   -176.9mA
-930mV    -157.5mA   -441.8mA   -57.56mA
-870mV    -50.13mA   -259.5mA   -18.17mA
-810mV    -13.28mA   -118mA     -10.41mA
-750mV    -5.921mA   -36.52mA   -7.502mA
-630mV    -2.275mA   -2.653mA   -3.283mA
3.9V      0A         0A         0A
[POWER_clamp]
|Voltage   I(typ)   I(min)   I(max)
-1.95V    1.356A     1.328A     1.514A
-1.08V    270.6mA    322.7mA    256.8mA
-1.02V    199mA      258.1mA    173mA
-960mV    131.2mA    195.7mA    97.36mA
-900mV    72.67mA    137.2mA    42.48mA
-840mV    32.99mA    86.34mA    19.5mA
-780mV    13.32mA    48.87mA    11.87mA
-720mV    5.671mA    25.66mA    7.515mA
-660mV    2.793mA    11.19mA    4.477mA
-600mV    1.289mA    3.449mA    2.334mA
-480mV    122.1uA    182.3uA    260.9uA
3.9V      0A         0A         0A
[Ramp]
| variable   typ   min   max
dV/dt_r  0.7334/0.5291n   0.5244/1.1703n   0.8972/0.2916n
dV/dt_f  0.6911/0.4713n   0.4146/0.8883n   0.8914/0.2659n
R_load = 83.0000
[Rising Waveform]
R_fixture= 83.0000
V_fixture= 0.0
V_fixture_min= 0.0
V_fixture_max= 0.0
|time   V(typ)   V(min)   V(max)
0s        457.3pV    4.283nV    925.5pV
1.073ns   -2.36mV    180.2uV    22.69mV
1.172ns   -3.731mV   163.9uV    178.7mV
1.506ns   -8.769mV   -175.6uV   1.203V
1.748ns   67.33mV    -920.4uV   1.402V
1.968ns   387.4mV    -1.99mV    1.457V
2.437ns   994.8mV    -4.733mV   1.489V
2.994ns   1.171V     16.54mV    1.495V
5.024ns   1.222V     780.6mV    1.495V
8.99ns    1.222V     874mV      1.495V
[Rising Waveform]
R_fixture= 83.0000
V_fixture= 1.8000
V_fixture_min= 1.6500
V_fixture_max= 1.9500
|time   V(typ)   V(min)   V(max)
0s        648.2mV    958mV      464.3mV
613.9ps   632.4mV    954.2mV    459.3mV
858.4ps   627.7mV    943.2mV    579.6mV
1.016ns   644.2mV    937.6mV    922.3mV
1.232ns   738.7mV    931.3mV    1.78V
1.386ns   904.2mV    928.2mV    1.927V
1.805ns   1.641V     947.6mV    1.945V
2.022ns   1.777V     992.6mV    1.948V
3.43ns    1.799V     1.633V     1.95V
8.99ns    1.8V       1.65V      1.95V
[Falling Waveform]
R_fixture= 83.0000
V_fixture= 0.0
V_fixture_min= 0.0
V_fixture_max= 0.0
|time   V(typ)   V(min)   V(max)
0s        1.222V     874.4mV    1.495V
1.283ns   1.223V     874.9mV    1.427V
1.422ns   1.224V     874.9mV    1.155V
1.617ns   1.224V     875mV      175.1mV
1.743ns   1.221V     875mV      13.53mV
2.213ns   1.058V     875.2mV    867.1uV
2.747ns   13.58mV    876.5mV    160uV
4.09ns    172.7uV    778.8mV    15.2uV
4.991ns   38.01uV    19.61mV    3.535uV
8.99ns    548.5nV    15.9uV     -358nV
[Falling Waveform]
R_fixture= 83.0000
V_fixture= 1.8000
V_fixture_min= 1.6500
V_fixture_max= 1.9500
|time   V(typ)   V(min)   V(max)
0s        1.8V       1.65V      1.95V
1.367ns   1.8V       1.65V      1.92V
1.548ns   1.8V       1.65V      1.613V
1.817ns   1.802V     1.65V      724.1mV
2.169ns   1.799V     1.65V      506.2mV
2.926ns   912.5mV    1.65V      466.9mV
3.416ns   712.5mV    1.651V     464.8mV
4.422ns   654.2mV    1.617V     464.4mV
6.011ns   648.3mV    1.031V     464.3mV
8.99ns    648.2mV    959mV      464.3mV
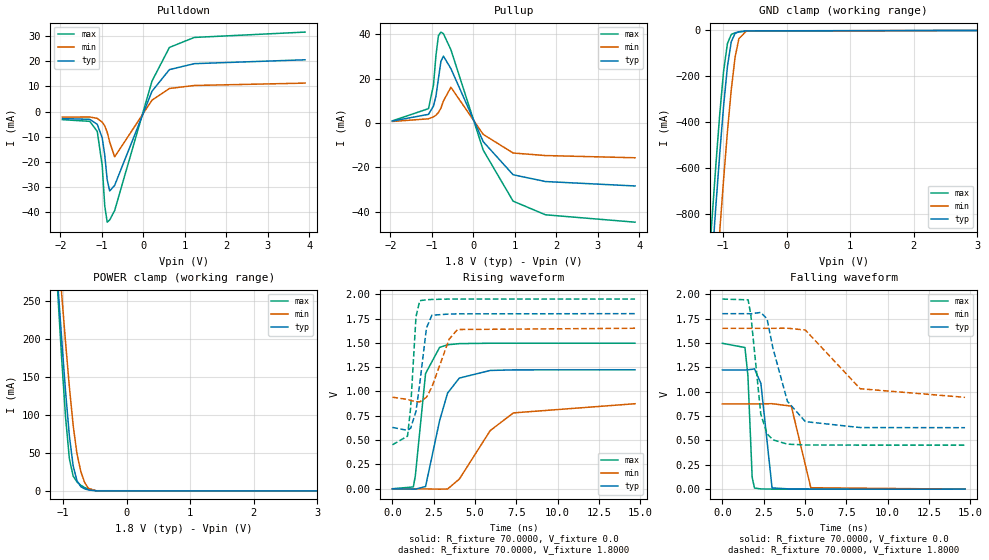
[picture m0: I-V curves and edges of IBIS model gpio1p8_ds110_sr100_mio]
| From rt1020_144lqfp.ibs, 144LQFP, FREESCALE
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[Model] gpio1p8_ds110_sr100_mio
|   Model gpio1p8_ds110_sr100_mio
| This model was characterised for following simulation conditions:
| External (pad) voltage:
|   - Typ: 1.8V,   - Min: 1.65V,   - Max: 1.95V
| Library cells for typ/min/max conditions are connected as defined below:
|  pad - External Pad
|  ipp_do - Core Input
|  ipp_obe - Output Buffer Enable
|  esd_boost - ovdd
|  ipp_dse0 - vssi
|  ipp_dse1 - vddi
|  ipp_dse2 - vddi
|  ipp_fsel0 - vssi
|  ipp_fsel1 - vssi
|  ipp_ina - ipp_ina
|  ipp_ind - ipp_ind
|  ipp_pwr_stable - vddi
|  ipp_sre - vddi
|  ovdd - ovdd
|  ovss - ovss
|  vddi - vddi
|  vssi - vssi
| All other pins connected to ground
Model_type I/O
Polarity   Non-Inverting
Enable   Active-High
Vinl =   0.5400V
Vinh =   1.2600V
Vmeas =  0.9000V
Cref =   0.0F
Rref =   70.0000
Vref =   0.9000V
C_comp   1.2573pF   1.2208pF   1.3054pF
|C_comp_pullup   0.6439pF   0.6609pF   0.6284pF
|C_comp_pulldown   0.5473pF   0.5786pF   0.5258pF
[Model Spec]
| variable   typ   min   max
Vinh   1.2600V   1.1550V   1.3650V
Vinl   0.5400V   0.4950V   0.5850V
S_overshoot_high   1.8000V   1.6500V   1.9500V
S_overshoot_low   0.0V   0.0V   0.0V
Vmeas   0.9000V   0.8250V   0.9750V
Vref   0.9000V   0.8250V   0.9750V
Cref   0.0F   0.0F   0.0F
Rref   70.0000   70.0000   70.0000
[Temperature Range]   25.0000   0.1050k   -20.0000
[Voltage Range]   1.8000V   1.6500V   1.9500V
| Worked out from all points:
|   slope of the pulldown table from 0 to 0.27 V, typ, clamps not added: 27.2 ohm
|   slope of the pullup table from 0 to 0.27 V, typ, clamps not added: 28.7 ohm
|   GND clamp passes 1 mA (typ) near -0.55 V on its own axis
|   POWER clamp passes 1 mA (typ) near -0.58 V on its own axis
|   rising waveform, R_fixture 70.0000, V_fixture 0.0: 20-80 % time 1.01ns typ, 2.22ns min, 547ps max; typ from 0 V to 1.22 V
|   rising waveform, R_fixture 70.0000, V_fixture 1.8000: 20-80 % time 492ps typ, 878ps min, 309ps max; typ from 0.631 V to 1.8 V
|   falling waveform, R_fixture 70.0000, V_fixture 0.0: 20-80 % time 323ps typ, 532ps min, 213ps max; typ from 1.22 V to 0 V
|   falling waveform, R_fixture 70.0000, V_fixture 1.8000: 20-80 % time 1.11ns typ, 2.17ns min, 553ps max; typ from 1.8 V to 0.631 V
[Pulldown]
|Voltage   I(typ)   I(min)   I(max)
-1.95V    -2.794mA   -2.176mA   -3.212mA
-1.29V    -3.073mA   -2.149mA   -3.876mA
-1.11V    -5.06mA    -2.697mA   -7.882mA
-990mV    -10.46mA   -4.192mA   -21.47mA
-930mV    -17.18mA   -5.69mA    -37.39mA
-870mV    -27.13mA   -8.178mA   -44mA
-810mV    -31.59mA   -12.14mA   -43.11mA
-690mV    -29.33mA   -18mA      -39.34mA
210mV     8.092mA    4.542mA    12.13mA
630mV     16.7mA     9.196mA    25.53mA
1.23V     19.07mA    10.39mA    29.5mA
3.9V      20.61mA    11.33mA    31.63mA
[Pullup]
|Voltage   I(typ)   I(min)   I(max)
-1.95V    820uA      630uA      920uA
-1.08V    3.846mA    1.832mA    6.417mA
-960mV    7.572mA    2.692mA    17.07mA
-900mV    12.06mA    3.465mA    30.37mA
-840mV    19.96mA    4.676mA    39.39mA
-780mV    27.77mA    6.655mA    40.96mA
-720mV    30.1mA     9.856mA    40.22mA
-540mV    24.49mA    16.07mA    33.02mA
240mV     -8.497mA   -5.208mA   -12.33mA
960mV     -23.42mA   -13.6mA    -35.32mA
1.74V     -26.47mA   -14.75mA   -41.48mA
3.9V      -28.48mA   -15.75mA   -44.82mA
[GND_clamp]
|Voltage   I(typ)   I(min)   I(max)
-1.95V    -4.191A    -4.477A    -4.042A
-1.23V    -1.234A    -1.577A    -1.052A
-1.17V    -993.2mA   -1.338A    -811.1mA
-1.11V    -758.1mA   -1.102A    -578.5mA
-1.05V    -533.7mA   -870.8mA   -361.6mA
-990mV    -328mA     -648.8mA   -176.9mA
-930mV    -157.5mA   -441.8mA   -57.56mA
-870mV    -50.13mA   -259.5mA   -18.17mA
-810mV    -13.28mA   -118mA     -10.41mA
-750mV    -5.921mA   -36.52mA   -7.502mA
-630mV    -2.275mA   -2.653mA   -3.283mA
3.9V      0A         0A         0A
[POWER_clamp]
|Voltage   I(typ)   I(min)   I(max)
-1.95V    1.356A     1.328A     1.514A
-1.08V    270.6mA    322.7mA    256.8mA
-1.02V    199mA      258.1mA    173mA
-960mV    131.2mA    195.7mA    97.36mA
-900mV    72.67mA    137.2mA    42.48mA
-840mV    32.99mA    86.34mA    19.5mA
-780mV    13.32mA    48.87mA    11.87mA
-720mV    5.671mA    25.66mA    7.515mA
-660mV    2.793mA    11.19mA    4.477mA
-600mV    1.289mA    3.449mA    2.334mA
-480mV    122.1uA    182.3uA    260.9uA
3.9V      0A         0A         0A
[Ramp]
| variable   typ   min   max
dV/dt_r  0.7336/1.0066n   0.5245/2.2191n   0.8973/0.5468n
dV/dt_f  0.7016/1.1108n   0.4249/2.1728n   0.8988/0.5532n
R_load = 70.0000
[Rising Waveform]
R_fixture= 70.0000
V_fixture= 0.0
V_fixture_min= 0.0
V_fixture_max= 0.0
|time   V(typ)   V(min)   V(max)
0s        378.1pV    3.555nV    765.1pV
1.268ns   -3.234mV   266.7uV    19.2mV
1.389ns   -4.195mV   186uV      133.8mV
2.008ns   23.18mV    -1.437mV   1.185V
2.857ns   700.1mV    -4.169mV   1.453V
3.34ns    983.5mV    -2.215mV   1.48V
4.052ns   1.138V     99.48mV    1.492V
5.921ns   1.216V     598.1mV    1.496V
7.326ns   1.222V     779.9mV    1.496V
14.69ns   1.223V     874.1mV    1.496V
[Rising Waveform]
R_fixture= 70.0000
V_fixture= 1.8000
V_fixture_min= 1.6500
V_fixture_max= 1.9500
|time   V(typ)   V(min)   V(max)
0s        630.7mV    941.3mV    451.9mV
914.9ps   600.3mV    918mV      541.2mV
1.103ns   621.9mV    907.9mV    829.9mV
1.428ns   795.9mV    894.2mV    1.769V
1.655ns   1.079V     893.5mV    1.933V
2.062ns   1.653V     940.2mV    1.943V
2.39ns    1.784V     1.045V     1.946V
3.43ns    1.796V     1.536V     1.95V
3.941ns   1.798V     1.637V     1.95V
14.69ns   1.8V       1.65V      1.95V
[Falling Waveform]
R_fixture= 70.0000
V_fixture= 0.0
V_fixture_min= 0.0
V_fixture_max= 0.0
|time   V(typ)   V(min)   V(max)
0s        1.223V     874.6mV    1.496V
1.364ns   1.223V     874.4mV    1.453V
1.544ns   1.224V     874.4mV    1.166V
1.801ns   1.23V      874.3mV    124.1mV
1.94ns    1.235V     874.3mV    11.67mV
2.328ns   1.086V     874.4mV    2.437mV
3.006ns   12.95mV    876.9mV    685.2uV
4.172ns   1.042mV    851.6mV    78.68uV
5.352ns   238.3uV    14.64mV    8.23uV
14.69ns   17.02nV    2.106uV    8.053nV
[Falling Waveform]
R_fixture= 70.0000
V_fixture= 1.8000
V_fixture_min= 1.6500
V_fixture_max= 1.9500
|time   V(typ)   V(min)   V(max)
0s        1.8V       1.65V      1.95V
1.557ns   1.8V       1.65V      1.942V
1.722ns   1.799V     1.65V      1.786V
2.322ns   1.813V     1.65V      771.1mV
2.702ns   1.747V     1.65V      568.7mV
3.055ns   1.449V     1.65V      506.3mV
3.935ns   901.4mV    1.651V     461.8mV
5.023ns   692.8mV    1.632V     453.2mV
8.344ns   631.8mV    1.03V      451.9mV
14.69ns   630.7mV    941.9mV    451.9mV
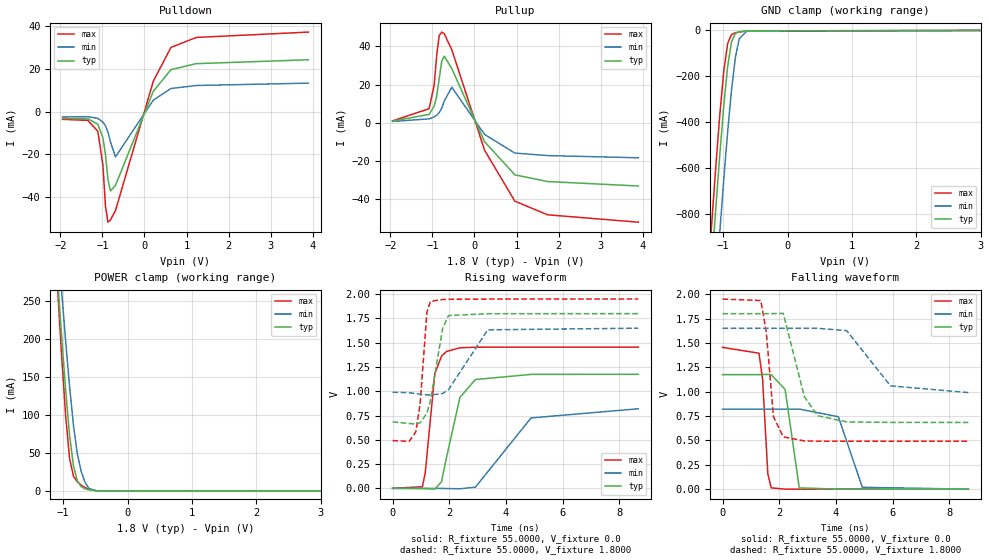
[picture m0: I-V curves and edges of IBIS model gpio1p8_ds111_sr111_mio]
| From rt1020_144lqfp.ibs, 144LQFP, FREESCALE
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[Model] gpio1p8_ds111_sr111_mio
|   Model gpio1p8_ds111_sr111_mio
| This model was characterised for following simulation conditions:
| External (pad) voltage:
|   - Typ: 1.8V,   - Min: 1.65V,   - Max: 1.95V
| Library cells for typ/min/max conditions are connected as defined below:
|  pad - External Pad
|  ipp_do - Core Input
|  ipp_obe - Output Buffer Enable
|  esd_boost - ovdd
|  ipp_dse0 - vddi
|  ipp_dse1 - vddi
|  ipp_dse2 - vddi
|  ipp_fsel0 - vddi
|  ipp_fsel1 - vddi
|  ipp_ina - ipp_ina
|  ipp_ind - ipp_ind
|  ipp_pwr_stable - vddi
|  ipp_sre - vddi
|  ovdd - ovdd
|  ovss - ovss
|  vddi - vddi
|  vssi - vssi
| All other pins connected to ground
Model_type I/O
Polarity   Non-Inverting
Enable   Active-High
Vinl =   0.5400V
Vinh =   1.2600V
Vmeas =  0.9000V
Cref =   0.0F
Rref =   55.0000
Vref =   0.9000V
C_comp   1.2573pF   1.2208pF   1.3056pF
|C_comp_pullup   0.6440pF   0.6611pF   0.6285pF
|C_comp_pulldown   0.5474pF   0.5788pF   0.5258pF
[Model Spec]
| variable   typ   min   max
Vinh   1.2600V   1.1550V   1.3650V
Vinl   0.5400V   0.4950V   0.5850V
S_overshoot_high   1.8000V   1.6500V   1.9500V
S_overshoot_low   0.0V   0.0V   0.0V
Vmeas   0.9000V   0.8250V   0.9750V
Vref   0.9000V   0.8250V   0.9750V
Cref   0.0F   0.0F   0.0F
Rref   55.0000   55.0000   55.0000
[Temperature Range]   25.0000   0.1050k   -20.0000
[Voltage Range]   1.8000V   1.6500V   1.9500V
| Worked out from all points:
|   slope of the pulldown table from 0 to 0.27 V, typ, clamps not added: 23.1 ohm
|   slope of the pullup table from 0 to 0.27 V, typ, clamps not added: 24.8 ohm
|   GND clamp passes 1 mA (typ) near -0.55 V on its own axis
|   POWER clamp passes 1 mA (typ) near -0.58 V on its own axis
|   rising waveform, R_fixture 55.0000, V_fixture 0.0: 20-80 % time 523ps typ, 1.15ns min, 286ps max; typ from 0 V to 1.18 V
|   rising waveform, R_fixture 55.0000, V_fixture 1.8000: 20-80 % time 384ps typ, 709ps min, 224ps max; typ from 0.685 V to 1.8 V
|   falling waveform, R_fixture 55.0000, V_fixture 0.0: 20-80 % time 240ps typ, 428ps min, 160ps max; typ from 1.18 V to 0 V
|   falling waveform, R_fixture 55.0000, V_fixture 1.8000: 20-80 % time 456ps typ, 853ps min, 252ps max; typ from 1.8 V to 0.685 V
[Pulldown]
|Voltage   I(typ)   I(min)   I(max)
-1.95V    -3.135mA   -2.441mA   -3.603mA
-1.35V    -3.301mA   -2.354mA   -4.07mA
-1.11V    -5.896mA   -3.133mA   -9.185mA
-990mV    -12.13mA   -4.862mA   -24.98mA
-930mV    -19.97mA   -6.587mA   -43.84mA
-870mV    -31.78mA   -9.469mA   -51.73mA
-810mV    -37.13mA   -14.13mA   -50.7mA
-690mV    -34.5mA    -21.16mA   -46.27mA
210mV     9.528mA    5.35mA     14.27mA
630mV     19.67mA    10.84mA    30.06mA
1.23V     22.47mA    12.25mA    34.74mA
3.9V      24.29mA    13.35mA    37.25mA
[Pullup]
|Voltage   I(typ)   I(min)   I(max)
-1.95V    940uA      730uA      1.07mA
-1.08V    4.444mA    2.119mA    7.411mA
-960mV    8.747mA    3.115mA    19.71mA
-900mV    13.93mA    4.008mA    35.13mA
-840mV    23.09mA    5.41mA     45.6mA
-780mV    32.16mA    7.702mA    47.42mA
-720mV    34.85mA    11.41mA    46.56mA
-540mV    28.34mA    18.61mA    38.21mA
240mV     -9.832mA   -6.026mA   -14.26mA
960mV     -27.1mA    -15.74mA   -40.86mA
1.74V     -30.62mA   -17.07mA   -47.99mA
3.9V      -32.95mA   -18.22mA   -51.85mA
[GND_clamp]
|Voltage   I(typ)   I(min)   I(max)
-1.95V    -4.191A    -4.477A    -4.042A
-1.23V    -1.234A    -1.577A    -1.052A
-1.17V    -993.2mA   -1.338A    -811.1mA
-1.11V    -758.1mA   -1.102A    -578.5mA
-1.05V    -533.7mA   -870.8mA   -361.6mA
-990mV    -328mA     -648.8mA   -176.9mA
-930mV    -157.5mA   -441.8mA   -57.56mA
-870mV    -50.13mA   -259.5mA   -18.17mA
-810mV    -13.28mA   -118mA     -10.41mA
-750mV    -5.921mA   -36.52mA   -7.502mA
-630mV    -2.275mA   -2.653mA   -3.283mA
3.9V      0A         0A         0A
[POWER_clamp]
|Voltage   I(typ)   I(min)   I(max)
-1.95V    1.356A     1.328A     1.514A
-1.08V    270.6mA    322.7mA    256.8mA
-1.02V    199mA      258.1mA    173mA
-960mV    131.2mA    195.7mA    97.36mA
-900mV    72.67mA    137.2mA    42.48mA
-840mV    32.99mA    86.34mA    19.5mA
-780mV    13.32mA    48.87mA    11.87mA
-720mV    5.671mA    25.66mA    7.515mA
-660mV    2.793mA    11.19mA    4.477mA
-600mV    1.289mA    3.449mA    2.334mA
-480mV    122.1uA    182.3uA    260.9uA
3.9V      0A         0A         0A
[Ramp]
| variable   typ   min   max
dV/dt_r  0.7048/0.5234n   0.4920/1.1499n   0.8729/0.2860n
dV/dt_f  0.6692/0.4565n   0.3956/0.8525n   0.8748/0.2515n
R_load = 55.0000
[Rising Waveform]
R_fixture= 55.0000
V_fixture= 0.0
V_fixture_min= 0.0
V_fixture_max= 0.0
|time   V(typ)   V(min)   V(max)
0s        315.1pV    2.935nV    641.2pV
1.052ns   -2.145mV   171uV      16.95mV
1.154ns   -3.5mV     155.1uV    164.1mV
1.49ns    -8.277mV   -171.4uV   1.18V
1.725ns   67.22mV    -863.8uV   1.361V
1.901ns   315.2mV    -1.672mV   1.41V
2.376ns   937.3mV    -4.329mV   1.448V
2.922ns   1.121V     12.45mV    1.454V
4.886ns   1.174V     725.5mV    1.455V
8.67ns    1.175V     819.9mV    1.455V
[Rising Waveform]
R_fixture= 55.0000
V_fixture= 1.8000
V_fixture_min= 1.6500
V_fixture_max= 1.9500
|time   V(typ)   V(min)   V(max)
0s        684.7mV    989.6mV    492mV
587.6ps   668.4mV    985.9mV    484.4mV
819.7ps   662.2mV    975.6mV    582.2mV
971.4ps   674.5mV    970.4mV    867.6mV
1.211ns   774.1mV    963.6mV    1.812V
1.334ns   900.5mV    961.1mV    1.927V
1.766ns   1.647V     977.6mV    1.945V
1.972ns   1.78V      1.017V     1.948V
3.359ns   1.799V     1.633V     1.95V
8.67ns    1.8V       1.65V      1.95V
[Falling Waveform]
R_fixture= 55.0000
V_fixture= 0.0
V_fixture_min= 0.0
V_fixture_max= 0.0
|time   V(typ)   V(min)   V(max)
0s        1.175V     820.4mV    1.455V
1.284ns   1.175V     820.7mV    1.394V
1.412ns   1.176V     820.7mV    1.13V
1.596ns   1.177V     820.8mV    158.5mV
1.715ns   1.175V     820.8mV    13.23mV
2.208ns   1.022V     821mV      770uV
2.706ns   13.29mV    822mV      136uV
4.085ns   132.3uV    742.8mV    9.849uV
4.93ns    24.36uV    19.31mV    2.434uV
8.67ns    -469.1nV   14.74uV    -287.1nV
[Falling Waveform]
R_fixture= 55.0000
V_fixture= 1.8000
V_fixture_min= 1.6500
V_fixture_max= 1.9500
|time   V(typ)   V(min)   V(max)
0s        1.8V       1.65V      1.95V
1.351ns   1.8V       1.65V      1.935V
1.542ns   1.8V       1.65V      1.611V
1.797ns   1.801V     1.65V      742.9mV
2.141ns   1.803V     1.65V      536.8mV
2.886ns   949.5mV    1.65V      494.6mV
3.354ns   752.8mV    1.65V      492.5mV
4.378ns   690.2mV    1.626V     492mV
5.923ns   684.8mV    1.06V      492mV
8.67ns    684.7mV    990.6mV    492mV
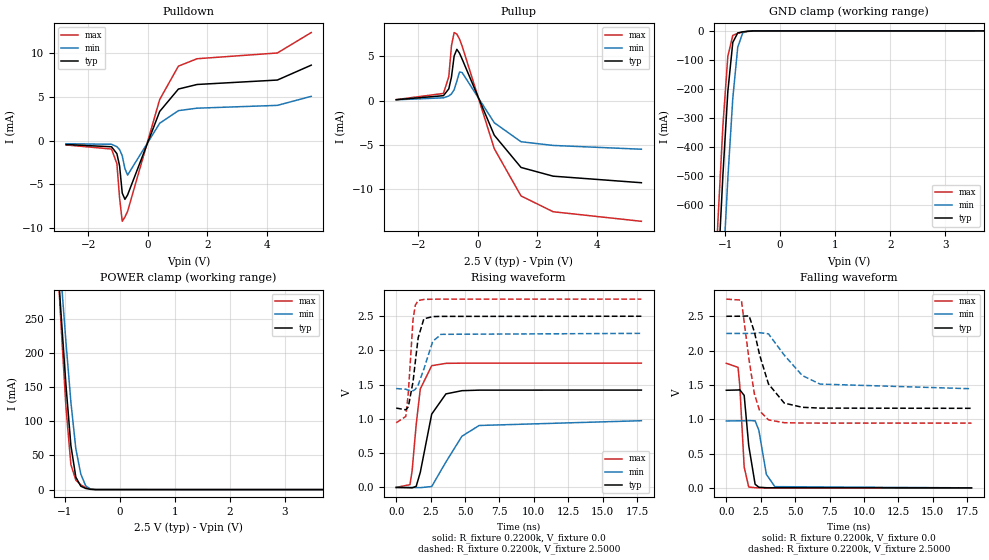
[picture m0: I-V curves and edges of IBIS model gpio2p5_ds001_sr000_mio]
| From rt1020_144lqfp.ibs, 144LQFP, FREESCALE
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[Model] gpio2p5_ds001_sr000_mio
|   Model gpio2p5_ds001_sr000_mio
| This model was characterised for following simulation conditions:
| External (pad) voltage:
|   - Typ: 2.5V,   - Min: 2.25V,   - Max: 2.75V
| Library cells for typ/min/max conditions are connected as defined below:
|  pad - External Pad
|  ipp_do - Core Input
|  ipp_obe - Output Buffer Enable
|  esd_boost - ovdd
|  ipp_dse0 - vddi
|  ipp_dse1 - vssi
|  ipp_dse2 - vssi
|  ipp_fsel0 - vssi
|  ipp_fsel1 - vssi
|  ipp_ina - ipp_ina
|  ipp_ind - ipp_ind
|  ipp_pwr_stable - vddi
|  ipp_sre - vssi
|  ovdd - ovdd
|  ovss - ovss
|  vddi - vddi
|  vssi - vssi
| All other pins connected to ground
Model_type I/O
Polarity   Non-Inverting
Enable   Active-High
Vinl =   0.7500V
Vinh =   1.7500V
Vmeas =  1.2500V
Cref =   0.0F
Rref =   0.2200k
Vref =   1.2500V
C_comp   1.2356pF   1.1994pF   1.2834pF
|C_comp_pullup   0.6221pF   0.6388pF   0.6072pF
|C_comp_pulldown   0.5474pF   0.5787pF   0.5258pF
[Model Spec]
| variable   typ   min   max
Vinh   1.7500V   1.5750V   1.9250V
Vinl   0.7500V   0.6750V   0.8250V
S_overshoot_high   2.5000V   2.2500V   2.7500V
S_overshoot_low   0.0V   0.0V   0.0V
Vmeas   1.2500V   1.1250V   1.3750V
Vref   1.2500V   1.1250V   1.3750V
Cref   0.0F   0.0F   0.0F
Rref   0.2200k   0.2200k   0.2200k
[Temperature Range]   25.0000   0.1050k   -20.0000
[Voltage Range]   2.5000V   2.2500V   2.7500V
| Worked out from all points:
|   slope of the pulldown table from 0 to 0.375 V, typ, clamps not added: 118 ohm
|   slope of the pullup table from 0 to 0.375 V, typ, clamps not added: 134 ohm
|   GND clamp passes 1 mA (typ) near -0.54 V on its own axis
|   POWER clamp passes 1 mA (typ) near -0.57 V on its own axis
|   rising waveform, R_fixture 0.2200k, V_fixture 0.0: 20-80 % time 882ps typ, 1.75ns min, 548ps max; typ from 0 V to 1.42 V
|   rising waveform, R_fixture 0.2200k, V_fixture 2.5000: 20-80 % time 484ps typ, 739ps min, 343ps max; typ from 1.16 V to 2.5 V
|   falling waveform, R_fixture 0.2200k, V_fixture 0.0: 20-80 % time 382ps typ, 492ps min, 286ps max; typ from 1.42 V to 0 V
|   falling waveform, R_fixture 0.2200k, V_fixture 2.5000: 20-80 % time 1.19ns typ, 2.03ns min, 756ps max; typ from 2.5 V to 1.16 V
[Pulldown]
|Voltage   I(typ)   I(min)   I(max)
-2.75V    -437uA     -349uA     -488uA
-1.22V    -696uA     -410uA     -955uA
-1.04V    -1.485mA   -688.7uA   -2.63mA
-950mV    -2.87mA    -1.013mA   -6.54mA
-860mV    -5.981mA   -1.728mA   -9.203mA
-770mV    -6.697mA   -3.198mA   -8.717mA
-680mV    -6.194mA   -3.924mA   -8.067mA
400mV     3.337mA    1.986mA    4.698mA
1.03V     5.893mA    3.429mA    8.508mA
1.66V     6.415mA    3.709mA    9.354mA
4.36V     6.92mA     4.03mA     10.01mA
5.5V      8.62mA     5.06mA     12.34mA
[Pullup]
|Voltage   I(typ)   I(min)   I(max)
-2.75V    90uA       80uA       100uA
-1.16V    543uA      304uA      797uA
-980mV    1.318mA    507uA      2.697mA
-890mV    2.653mA    742uA      6.183mA
-800mV    5.023mA    1.217mA    7.66mA
-710mV    5.768mA    2.181mA    7.493mA
-620mV    5.336mA    3.213mA    6.929mA
-530mV    4.654mA    3.148mA    6.127mA
550mV     -3.913mA   -2.508mA   -5.429mA
1.45V     -7.548mA   -4.649mA   -10.76mA
2.53V     -8.531mA   -5.066mA   -12.54mA
5.5V      -9.27mA    -5.494mA   -13.62mA
[GND_clamp]
|Voltage   I(typ)   I(min)   I(max)
-2.75V    -7.488A    -7.708A    -7.379A
-1.22V    -1.193A    -1.537A    -1.012A
-1.13V    -835.6mA   -1.18A     -654.7mA
-1.04V    -497.8mA   -833mA     -328mA
-950mV    -208.9mA   -508.7mA   -87.54mA
-860mV    -39.89mA   -232.5mA   -15.89mA
-770mV    -7.264mA   -56.44mA   -8.363mA
-680mV    -3.422mA   -7.048mA   -4.851mA
-590mV    -1.552mA   -1.455mA   -2.251mA
-500mV    -482.7uA   -438.2uA   -698.4uA
5.5V      0A         0A         0A
[POWER_clamp]
|Voltage   I(typ)   I(min)   I(max)
-2.75V    2.386A     2.288A     2.687A
-1.16V    368.2mA    410.8mA    372.9mA
-1.07V    258.5mA    311.8mA    242.5mA
-980mV    153.1mA    216.2mA    121.1mA
-890mV    64.5mA     128mA      36.56mA
-800mV    18.16mA    59.6mA     13.82mA
-710mV    5.012mA    22.76mA    6.935mA
-620mV    1.706mA    5.315mA    2.959mA
-530mV    383.1uA    636.8uA    795.1uA
-440mV    42.36uA    66.97uA    84.45uA
5.5V      0A         0A         0A
[Ramp]
| variable   typ   min   max
dV/dt_r  0.8533/0.8808n   0.5847/1.7456n   1.0888/0.5485n
dV/dt_f  0.8044/1.1876n   0.4833/2.0336n   1.0836/0.7560n
R_load = 0.2200k
[Rising Waveform]
R_fixture= 0.2200k
V_fixture= 0.0
V_fixture_min= 0.0
V_fixture_max= 0.0
|time   V(typ)   V(min)   V(max)
0s        3.706nV    14.41nV    11.69nV
997.9ps   -4.222mV   179.4uV    40.34mV
1.151ns   -6.178mV   -246.6uV   234.3mV
1.451ns   15.87mV    -1.638mV   917.7mV
1.749ns   220mV      -3.213mV   1.438V
2.579ns   1.071V     13.5mV     1.778V
3.612ns   1.366V     371.8mV    1.812V
4.775ns   1.413V     747.9mV    1.815V
6.027ns   1.421V     904.7mV    1.815V
17.81ns   1.422V     974.5mV    1.815V
[Rising Waveform]
R_fixture= 0.2200k
V_fixture= 2.5000
V_fixture_min= 2.2500
V_fixture_max= 2.7500
|time   V(typ)   V(min)   V(max)
0s        1.159V     1.444V     944mV
697.5ps   1.133V     1.434V     1.037V
880.4ps   1.178V     1.419V     1.381V
1.225ns   1.547V     1.412V     2.457V
1.385ns   1.83V      1.432V     2.66V
1.595ns   2.186V     1.496V     2.73V
2.008ns   2.462V     1.728V     2.745V
2.654ns   2.495V     2.133V     2.749V
3.26ns    2.498V     2.236V     2.75V
17.81ns   2.5V       2.25V      2.75V
[Falling Waveform]
R_fixture= 0.2200k
V_fixture= 0.0
V_fixture_min= 0.0
V_fixture_max= 0.0
|time   V(typ)   V(min)   V(max)
0s        1.422V     974.5mV    1.815V
851.5ps   1.426V     976.8mV    1.756V
975.3ps   1.429V     977.1mV    1.493V
1.297ns   1.347V     977.7mV    302mV
1.626ns   617.3mV    981.1mV    12.9mV
2.091ns   52.5mV     976.7mV    2.187mV
2.364ns   8.897mV    838mV      1.417mV
2.908ns   2.077mV    196.4mV    562.1uV
3.526ns   1.025mV    17.59mV    186.2uV
17.81ns   26.14nV    37.13nV    6.403nV
[Falling Waveform]
R_fixture= 0.2200k
V_fixture= 2.5000
V_fixture_min= 2.2500
V_fixture_max= 2.7500
|time   V(typ)   V(min)   V(max)
0s        2.5V       2.25V      2.75V
1.092ns   2.501V     2.25V      2.736V
1.657ns   2.505V     2.25V      1.858V
2.042ns   2.269V     2.251V     1.366V
2.425ns   1.931V     2.261V     1.12V
3.062ns   1.514V     2.244V     990.1mV
4.208ns   1.235V     1.934V     949.4mV
5.519ns   1.174V     1.636V     944.4mV
6.815ns   1.162V     1.512V     944mV
17.81ns   1.159V     1.444V     944mV
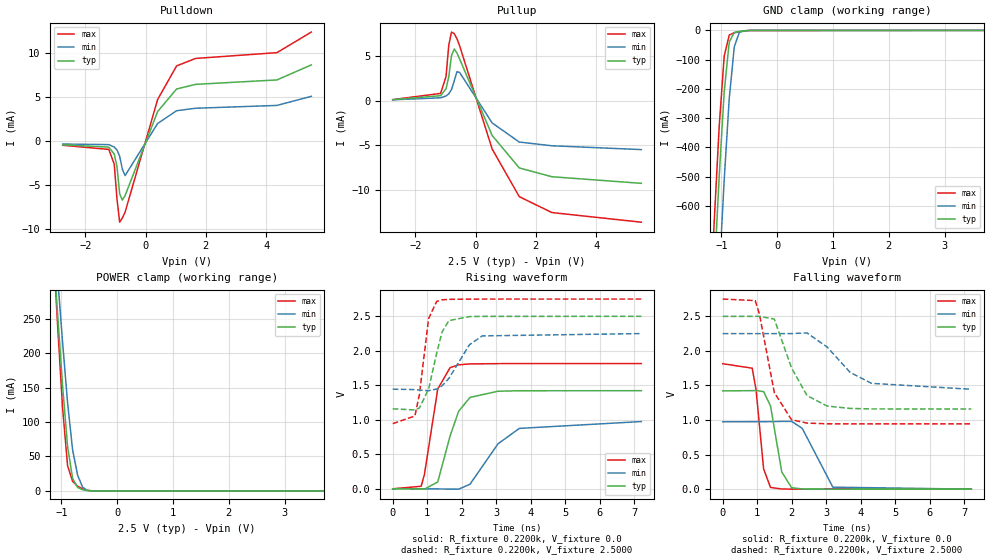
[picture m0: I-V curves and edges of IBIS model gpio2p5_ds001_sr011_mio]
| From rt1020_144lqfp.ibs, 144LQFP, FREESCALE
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[Model] gpio2p5_ds001_sr011_mio
|   Model gpio2p5_ds001_sr011_mio
| This model was characterised for following simulation conditions:
| External (pad) voltage:
|   - Typ: 2.5V,   - Min: 2.25V,   - Max: 2.75V
| Library cells for typ/min/max conditions are connected as defined below:
|  pad - External Pad
|  ipp_do - Core Input
|  ipp_obe - Output Buffer Enable
|  esd_boost - ovdd
|  ipp_dse0 - vddi
|  ipp_dse1 - vssi
|  ipp_dse2 - vssi
|  ipp_fsel0 - vddi
|  ipp_fsel1 - vddi
|  ipp_ina - ipp_ina
|  ipp_ind - ipp_ind
|  ipp_pwr_stable - vddi
|  ipp_sre - vssi
|  ovdd - ovdd
|  ovss - ovss
|  vddi - vddi
|  vssi - vssi
| All other pins connected to ground
Model_type I/O
Polarity   Non-Inverting
Enable   Active-High
Vinl =   0.7500V
Vinh =   1.7500V
Vmeas =  1.2500V
Cref =   0.0F
Rref =   0.2200k
Vref =   1.2500V
C_comp   1.2356pF   1.1994pF   1.2834pF
|C_comp_pullup   0.6222pF   0.6389pF   0.6073pF
|C_comp_pulldown   0.5474pF   0.5788pF   0.5258pF
[Model Spec]
| variable   typ   min   max
Vinh   1.7500V   1.5750V   1.9250V
Vinl   0.7500V   0.6750V   0.8250V
S_overshoot_high   2.5000V   2.2500V   2.7500V
S_overshoot_low   0.0V   0.0V   0.0V
Vmeas   1.2500V   1.1250V   1.3750V
Vref   1.2500V   1.1250V   1.3750V
Cref   0.0F   0.0F   0.0F
Rref   0.2200k   0.2200k   0.2200k
[Temperature Range]   25.0000   0.1050k   -20.0000
[Voltage Range]   2.5000V   2.2500V   2.7500V
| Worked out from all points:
|   slope of the pulldown table from 0 to 0.375 V, typ, clamps not added: 118 ohm
|   slope of the pullup table from 0 to 0.375 V, typ, clamps not added: 134 ohm
|   GND clamp passes 1 mA (typ) near -0.54 V on its own axis
|   POWER clamp passes 1 mA (typ) near -0.57 V on its own axis
|   rising waveform, R_fixture 0.2200k, V_fixture 0.0: 20-80 % time 503ps typ, 881ps min, 340ps max; typ from 0 V to 1.42 V
|   rising waveform, R_fixture 0.2200k, V_fixture 2.5000: 20-80 % time 373ps typ, 589ps min, 256ps max; typ from 1.16 V to 2.5 V
|   falling waveform, R_fixture 0.2200k, V_fixture 0.0: 20-80 % time 281ps typ, 433ps min, 202ps max; typ from 1.42 V to 0 V
|   falling waveform, R_fixture 0.2200k, V_fixture 2.5000: 20-80 % time 629ps typ, 972ps min, 439ps max; typ from 2.5 V to 1.16 V
[Pulldown]
|Voltage   I(typ)   I(min)   I(max)
-2.75V    -437uA     -349uA     -488uA
-1.22V    -696uA     -410uA     -955uA
-1.04V    -1.485mA   -688.7uA   -2.63mA
-950mV    -2.87mA    -1.013mA   -6.54mA
-860mV    -5.981mA   -1.728mA   -9.203mA
-770mV    -6.697mA   -3.198mA   -8.717mA
-680mV    -6.194mA   -3.924mA   -8.067mA
400mV     3.337mA    1.986mA    4.698mA
1.03V     5.893mA    3.429mA    8.508mA
1.66V     6.415mA    3.709mA    9.354mA
4.36V     6.92mA     4.03mA     10.01mA
5.5V      8.62mA     5.06mA     12.34mA
[Pullup]
|Voltage   I(typ)   I(min)   I(max)
-2.75V    90uA       80uA       100uA
-1.16V    543uA      304uA      797uA
-980mV    1.318mA    507uA      2.697mA
-890mV    2.653mA    742uA      6.183mA
-800mV    5.023mA    1.217mA    7.66mA
-710mV    5.768mA    2.181mA    7.493mA
-620mV    5.336mA    3.213mA    6.929mA
-530mV    4.654mA    3.148mA    6.127mA
550mV     -3.913mA   -2.508mA   -5.429mA
1.45V     -7.548mA   -4.649mA   -10.76mA
2.53V     -8.531mA   -5.066mA   -12.54mA
5.5V      -9.27mA    -5.494mA   -13.62mA
[GND_clamp]
|Voltage   I(typ)   I(min)   I(max)
-2.75V    -7.488A    -7.708A    -7.379A
-1.22V    -1.193A    -1.537A    -1.012A
-1.13V    -835.6mA   -1.18A     -654.7mA
-1.04V    -497.8mA   -833mA     -328mA
-950mV    -208.9mA   -508.7mA   -87.54mA
-860mV    -39.89mA   -232.5mA   -15.89mA
-770mV    -7.264mA   -56.44mA   -8.363mA
-680mV    -3.422mA   -7.048mA   -4.851mA
-590mV    -1.552mA   -1.455mA   -2.251mA
-500mV    -482.7uA   -438.2uA   -698.4uA
5.5V      0A         0A         0A
[POWER_clamp]
|Voltage   I(typ)   I(min)   I(max)
-2.75V    2.386A     2.288A     2.687A
-1.16V    368.2mA    410.8mA    372.9mA
-1.07V    258.5mA    311.8mA    242.5mA
-980mV    153.1mA    216.2mA    121.1mA
-890mV    64.5mA     128mA      36.56mA
-800mV    18.16mA    59.6mA     13.82mA
-710mV    5.012mA    22.76mA    6.935mA
-620mV    1.706mA    5.315mA    2.959mA
-530mV    383.1uA    636.8uA    795.1uA
-440mV    42.36uA    66.97uA    84.45uA
5.5V      0A         0A         0A
[Ramp]
| variable   typ   min   max
dV/dt_r  0.8533/0.5029n   0.5846/0.8814n   1.0888/0.3400n
dV/dt_f  0.8044/0.6294n   0.4830/0.9721n   1.0836/0.4387n
R_load = 0.2200k
[Rising Waveform]
R_fixture= 0.2200k
V_fixture= 0.0
V_fixture_min= 0.0
V_fixture_max= 0.0
|time   V(typ)   V(min)   V(max)
0s        3.704nV    14.52nV    11.69nV
825.5ps   -3.479mV   286.4uV    36.97mV
919.3ps   -5.486mV   145.9uV    205.9mV
1.306ns   98.89mV    -1.663mV   1.446V
1.665ns   766.6mV    -4.924mV   1.757V
1.912ns   1.124V     -5.442mV   1.797V
2.243ns   1.325V     66.67mV    1.81V
3.055ns   1.414V     652.9mV    1.814V
3.673ns   1.421V     875.4mV    1.815V
7.21ns    1.422V     974.4mV    1.815V
[Rising Waveform]
R_fixture= 0.2200k
V_fixture= 2.5000
V_fixture_min= 2.2500
V_fixture_max= 2.7500
|time   V(typ)   V(min)   V(max)
0s        1.159V     1.444V     944mV
643.2ps   1.143V     1.438V     1.055V
772.9ps   1.17V      1.431V     1.362V
1.041ns   1.445V     1.422V     2.467V
1.276ns   1.968V     1.446V     2.716V
1.431ns   2.272V     1.492V     2.739V
1.631ns   2.438V     1.601V     2.746V
2.226ns   2.496V     2.088V     2.749V
2.598ns   2.499V     2.216V     2.75V
7.21ns    2.5V       2.25V      2.75V
[Falling Waveform]
R_fixture= 0.2200k
V_fixture= 0.0
V_fixture_min= 0.0
V_fixture_max= 0.0
|time   V(typ)   V(min)   V(max)
0s        1.422V     974.5mV    1.815V
855.3ps   1.425V     976mV      1.75V
967.1ps   1.427V     976.1mV    1.438V
1.186ns   1.411V     976.2mV    293.5mV
1.386ns   1.205V     976.6mV    25.11mV
1.712ns   250.1mV    980.2mV    2.242mV
1.998ns   21.06mV    980.7mV    1.008mV
2.308ns   3.045mV    878.6mV    538.6uV
3.194ns   452.8uV    29.05mV    151.8uV
7.21ns    5.365uV    26.32uV    1.363uV
[Falling Waveform]
R_fixture= 0.2200k
V_fixture= 2.5000
V_fixture_min= 2.2500
V_fixture_max= 2.7500
|time   V(typ)   V(min)   V(max)
0s        2.5V       2.25V      2.75V
942.1ps   2.5V       2.25V      2.728V
1.064ns   2.501V     2.25V      2.534V
1.497ns   2.46V      2.25V      1.398V
1.996ns   1.754V     2.251V     1.004V
2.445ns   1.354V     2.26V      955.7mV
3.031ns   1.202V     2.055V     945.7mV
3.696ns   1.168V     1.689V     944.3mV
4.315ns   1.161V     1.531V     944.1mV
7.21ns    1.159V     1.445V     944mV
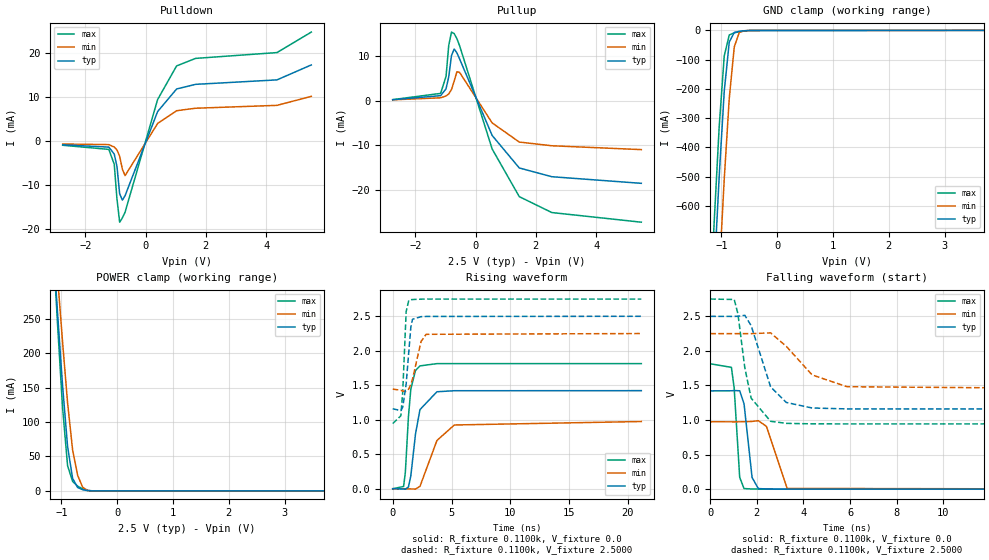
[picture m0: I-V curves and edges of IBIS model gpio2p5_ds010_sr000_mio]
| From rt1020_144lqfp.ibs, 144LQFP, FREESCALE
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[Model] gpio2p5_ds010_sr000_mio
|   Model gpio2p5_ds010_sr000_mio
| This model was characterised for following simulation conditions:
| External (pad) voltage:
|   - Typ: 2.5V,   - Min: 2.25V,   - Max: 2.75V
| Library cells for typ/min/max conditions are connected as defined below:
|  pad - External Pad
|  ipp_do - Core Input
|  ipp_obe - Output Buffer Enable
|  esd_boost - ovdd
|  ipp_dse0 - vssi
|  ipp_dse1 - vddi
|  ipp_dse2 - vssi
|  ipp_fsel0 - vssi
|  ipp_fsel1 - vssi
|  ipp_ina - ipp_ina
|  ipp_ind - ipp_ind
|  ipp_pwr_stable - vddi
|  ipp_sre - vssi
|  ovdd - ovdd
|  ovss - ovss
|  vddi - vddi
|  vssi - vssi
| All other pins connected to ground
Model_type I/O
Polarity   Non-Inverting
Enable   Active-High
Vinl =   0.7500V
Vinh =   1.7500V
Vmeas =  1.2500V
Cref =   0.0F
Rref =   0.1100k
Vref =   1.2500V
C_comp   1.2356pF   1.1994pF   1.2834pF
|C_comp_pullup   0.6221pF   0.6388pF   0.6072pF
|C_comp_pulldown   0.5474pF   0.5787pF   0.5258pF
[Model Spec]
| variable   typ   min   max
Vinh   1.7500V   1.5750V   1.9250V
Vinl   0.7500V   0.6750V   0.8250V
S_overshoot_high   2.5000V   2.2500V   2.7500V
S_overshoot_low   0.0V   0.0V   0.0V
Vmeas   1.2500V   1.1250V   1.3750V
Vref   1.2500V   1.1250V   1.3750V
Cref   0.0F   0.0F   0.0F
Rref   0.1100k   0.1100k   0.1100k
[Temperature Range]   25.0000   0.1050k   -20.0000
[Voltage Range]   2.5000V   2.2500V   2.7500V
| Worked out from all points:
|   slope of the pulldown table from 0 to 0.375 V, typ, clamps not added: 59.2 ohm
|   slope of the pullup table from 0 to 0.375 V, typ, clamps not added: 66.8 ohm
|   GND clamp passes 1 mA (typ) near -0.54 V on its own axis
|   POWER clamp passes 1 mA (typ) near -0.57 V on its own axis
|   rising waveform, R_fixture 0.1100k, V_fixture 0.0: 20-80 % time 692ps typ, 1.35ns min, 424ps max; typ from 0 V to 1.42 V
|   rising waveform, R_fixture 0.1100k, V_fixture 2.5000: 20-80 % time 388ps typ, 628ps min, 265ps max; typ from 1.16 V to 2.5 V
|   falling waveform, R_fixture 0.1100k, V_fixture 0.0: 20-80 % time 253ps typ, 373ps min, 185ps max; typ from 1.42 V to 0 V
|   falling waveform, R_fixture 0.1100k, V_fixture 2.5000: 20-80 % time 826ps typ, 1.39ns min, 517ps max; typ from 2.5 V to 1.16 V
[Pulldown]
|Voltage   I(typ)   I(min)   I(max)
-2.75V    -867uA     -694uA     -970uA
-1.22V    -1.39mA    -820uA     -1.909mA
-1.04V    -2.968mA   -1.376mA   -5.261mA
-950mV    -5.74mA    -2.023mA   -13.11mA
-860mV    -11.97mA   -3.453mA   -18.4mA
-770mV    -13.39mA   -6.394mA   -17.42mA
-680mV    -12.38mA   -7.845mA   -16.13mA
400mV     6.671mA    3.97mA     9.391mA
1.03V     11.78mA    6.858mA    17.01mA
1.66V     12.83mA    7.418mA    18.71mA
4.36V     13.84mA    8.07mA     20.03mA
5.5V      17.23mA    10.11mA    24.67mA
[Pullup]
|Voltage   I(typ)   I(min)   I(max)
-2.75V    180uA      160uA      200uA
-1.16V    1.087mA    609uA      1.595mA
-980mV    2.638mA    1.014mA    5.407mA
-890mV    5.313mA    1.485mA    12.39mA
-800mV    10.05mA    2.436mA    15.32mA
-710mV    11.53mA    4.364mA    14.98mA
-620mV    10.67mA    6.425mA    13.85mA
-530mV    9.303mA    6.294mA    12.25mA
550mV     -7.823mA   -5.015mA   -10.85mA
1.45V     -15.1mA    -9.298mA   -21.52mA
2.53V     -17.06mA   -10.13mA   -25.08mA
5.5V      -18.54mA   -10.99mA   -27.24mA
[GND_clamp]
|Voltage   I(typ)   I(min)   I(max)
-2.75V    -7.488A    -7.708A    -7.379A
-1.22V    -1.193A    -1.537A    -1.012A
-1.13V    -835.6mA   -1.18A     -654.7mA
-1.04V    -497.8mA   -833mA     -328mA
-950mV    -208.9mA   -508.7mA   -87.54mA
-860mV    -39.89mA   -232.5mA   -15.89mA
-770mV    -7.264mA   -56.44mA   -8.363mA
-680mV    -3.422mA   -7.048mA   -4.851mA
-590mV    -1.552mA   -1.455mA   -2.251mA
-500mV    -482.7uA   -438.2uA   -698.4uA
5.5V      0A         0A         0A
[POWER_clamp]
|Voltage   I(typ)   I(min)   I(max)
-2.75V    2.386A     2.288A     2.687A
-1.16V    368.2mA    410.8mA    372.9mA
-1.07V    258.5mA    311.8mA    242.5mA
-980mV    153.1mA    216.2mA    121.1mA
-890mV    64.5mA     128mA      36.56mA
-800mV    18.16mA    59.6mA     13.82mA
-710mV    5.012mA    22.76mA    6.935mA
-620mV    1.706mA    5.315mA    2.959mA
-530mV    383.1uA    636.8uA    795.1uA
-440mV    42.36uA    66.97uA    84.45uA
5.5V      0A         0A         0A
[Ramp]
| variable   typ   min   max
dV/dt_r  0.8532/0.6917n   0.5847/1.3512n   1.0887/0.4238n
dV/dt_f  0.8044/0.8260n   0.4833/1.3879n   1.0835/0.5171n
R_load = 0.1100k
[Rising Waveform]
R_fixture= 0.1100k
V_fixture= 0.0
V_fixture_min= 0.0
V_fixture_max= 0.0
|time   V(typ)   V(min)   V(max)
0s        1.854nV    7.204nV    5.85nV
927.5ps   -4.039mV   195.8uV    32.78mV
1.076ns   -6.42mV    -260.9uV   240.3mV
1.338ns   25.42mV    -1.563mV   1.046V
1.541ns   187.3mV    -2.984mV   1.446V
1.938ns   792.8mV    -5.048mV   1.714V
2.317ns   1.147V     33.82mV    1.781V
3.76ns    1.406V     699mV      1.814V
5.239ns   1.421V     924.2mV    1.814V
21.14ns   1.422V     974.5mV    1.814V
[Rising Waveform]
R_fixture= 0.1100k
V_fixture= 2.5000
V_fixture_min= 2.2500
V_fixture_max= 2.7500
|time   V(typ)   V(min)   V(max)
0s        1.159V     1.444V     944.2mV
694.1ps   1.133V     1.428V     1.058V
852.9ps   1.183V     1.415V     1.405V
1.143ns   1.516V     1.411V     2.566V
1.368ns   1.988V     1.447V     2.733V
1.543ns   2.343V     1.512V     2.741V
1.683ns   2.457V     1.589V     2.743V
2.409ns   2.495V     2.135V     2.749V
2.841ns   2.498V     2.239V     2.75V
21.14ns   2.5V       2.25V      2.75V
[Falling Waveform]
R_fixture= 0.1100k
V_fixture= 0.0
V_fixture_min= 0.0
V_fixture_max= 0.0
|time   V(typ)   V(min)   V(max)
0s        1.422V     974.5mV    1.814V
906.7ps   1.423V     974.2mV    1.762V
1.025ns   1.427V     974.1mV    1.467V
1.263ns   1.423V     974.2mV    170mV
1.45ns    1.234V     974.7mV    8.927mV
1.794ns   169mV      980mV      2.519mV
2.062ns   8.749mV    990.3mV    1.431mV
2.41ns    2.793mV    908.1mV    683.7uV
3.299ns   686.7uV    10.74mV    102.4uV
21.14ns   4.211nV    17.86nV    9.228nV
[Falling Waveform]
R_fixture= 0.1100k
V_fixture= 2.5000
V_fixture_min= 2.2500
V_fixture_max= 2.7500
|time   V(typ)   V(min)   V(max)
0s        2.5V       2.25V      2.75V
1.028ns   2.499V     2.25V      2.744V
1.186ns   2.501V     2.25V      2.537V
1.482ns   2.515V     2.25V      1.756V
1.753ns   2.367V     2.25V      1.317V
2.59ns    1.479V     2.261V     981.9mV
3.263ns   1.254V     2.066V     952mV
4.374ns   1.174V     1.652V     944.7mV
5.869ns   1.161V     1.482V     944.2mV
21.14ns   1.159V     1.444V     944.2mV
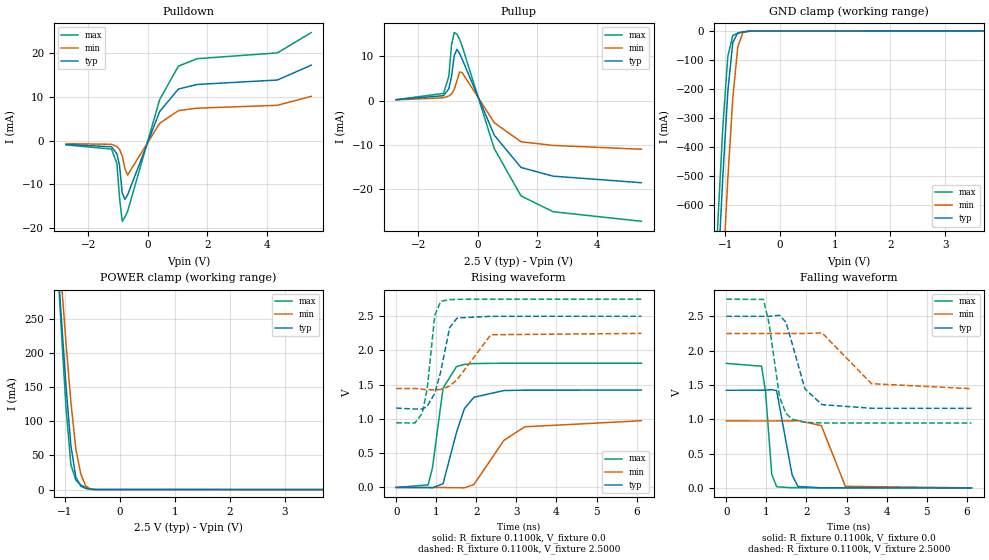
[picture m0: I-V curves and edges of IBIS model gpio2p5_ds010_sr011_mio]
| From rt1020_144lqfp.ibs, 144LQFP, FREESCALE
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[Model] gpio2p5_ds010_sr011_mio
|   Model gpio2p5_ds010_sr011_mio
| This model was characterised for following simulation conditions:
| External (pad) voltage:
|   - Typ: 2.5V,   - Min: 2.25V,   - Max: 2.75V
| Library cells for typ/min/max conditions are connected as defined below:
|  pad - External Pad
|  ipp_do - Core Input
|  ipp_obe - Output Buffer Enable
|  esd_boost - ovdd
|  ipp_dse0 - vssi
|  ipp_dse1 - vddi
|  ipp_dse2 - vssi
|  ipp_fsel0 - vddi
|  ipp_fsel1 - vddi
|  ipp_ina - ipp_ina
|  ipp_ind - ipp_ind
|  ipp_pwr_stable - vddi
|  ipp_sre - vssi
|  ovdd - ovdd
|  ovss - ovss
|  vddi - vddi
|  vssi - vssi
| All other pins connected to ground
Model_type I/O
Polarity   Non-Inverting
Enable   Active-High
Vinl =   0.7500V
Vinh =   1.7500V
Vmeas =  1.2500V
Cref =   0.0F
Rref =   0.1100k
Vref =   1.2500V
C_comp   1.2356pF   1.1994pF   1.2834pF
|C_comp_pullup   0.6222pF   0.6389pF   0.6073pF
|C_comp_pulldown   0.5474pF   0.5788pF   0.5258pF
[Model Spec]
| variable   typ   min   max
Vinh   1.7500V   1.5750V   1.9250V
Vinl   0.7500V   0.6750V   0.8250V
S_overshoot_high   2.5000V   2.2500V   2.7500V
S_overshoot_low   0.0V   0.0V   0.0V
Vmeas   1.2500V   1.1250V   1.3750V
Vref   1.2500V   1.1250V   1.3750V
Cref   0.0F   0.0F   0.0F
Rref   0.1100k   0.1100k   0.1100k
[Temperature Range]   25.0000   0.1050k   -20.0000
[Voltage Range]   2.5000V   2.2500V   2.7500V
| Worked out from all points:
|   slope of the pulldown table from 0 to 0.375 V, typ, clamps not added: 59.2 ohm
|   slope of the pullup table from 0 to 0.375 V, typ, clamps not added: 66.8 ohm
|   GND clamp passes 1 mA (typ) near -0.54 V on its own axis
|   POWER clamp passes 1 mA (typ) near -0.57 V on its own axis
|   rising waveform, R_fixture 0.1100k, V_fixture 0.0: 20-80 % time 377ps typ, 691ps min, 246ps max; typ from 0 V to 1.42 V
|   rising waveform, R_fixture 0.1100k, V_fixture 2.5000: 20-80 % time 292ps typ, 492ps min, 194ps max; typ from 1.16 V to 2.5 V
|   falling waveform, R_fixture 0.1100k, V_fixture 0.0: 20-80 % time 177ps typ, 276ps min, 133ps max; typ from 1.42 V to 0 V
|   falling waveform, R_fixture 0.1100k, V_fixture 2.5000: 20-80 % time 384ps typ, 583ps min, 269ps max; typ from 2.5 V to 1.16 V
[Pulldown]
|Voltage   I(typ)   I(min)   I(max)
-2.75V    -867uA     -694uA     -970uA
-1.22V    -1.39mA    -820uA     -1.909mA
-1.04V    -2.968mA   -1.376mA   -5.261mA
-950mV    -5.74mA    -2.023mA   -13.11mA
-860mV    -11.97mA   -3.453mA   -18.4mA
-770mV    -13.39mA   -6.394mA   -17.42mA
-680mV    -12.38mA   -7.845mA   -16.13mA
400mV     6.671mA    3.97mA     9.391mA
1.03V     11.78mA    6.858mA    17.01mA
1.66V     12.83mA    7.418mA    18.71mA
4.36V     13.84mA    8.07mA     20.03mA
5.5V      17.23mA    10.11mA    24.67mA
[Pullup]
|Voltage   I(typ)   I(min)   I(max)
-2.75V    180uA      160uA      200uA
-1.16V    1.087mA    609uA      1.595mA
-980mV    2.638mA    1.014mA    5.407mA
-890mV    5.313mA    1.485mA    12.39mA
-800mV    10.05mA    2.436mA    15.32mA
-710mV    11.53mA    4.364mA    14.98mA
-620mV    10.67mA    6.425mA    13.85mA
-530mV    9.303mA    6.294mA    12.25mA
550mV     -7.823mA   -5.015mA   -10.85mA
1.45V     -15.1mA    -9.298mA   -21.52mA
2.53V     -17.06mA   -10.13mA   -25.08mA
5.5V      -18.54mA   -10.99mA   -27.24mA
[GND_clamp]
|Voltage   I(typ)   I(min)   I(max)
-2.75V    -7.488A    -7.708A    -7.379A
-1.22V    -1.193A    -1.537A    -1.012A
-1.13V    -835.6mA   -1.18A     -654.7mA
-1.04V    -497.8mA   -833mA     -328mA
-950mV    -208.9mA   -508.7mA   -87.54mA
-860mV    -39.89mA   -232.5mA   -15.89mA
-770mV    -7.264mA   -56.44mA   -8.363mA
-680mV    -3.422mA   -7.048mA   -4.851mA
-590mV    -1.552mA   -1.455mA   -2.251mA
-500mV    -482.7uA   -438.2uA   -698.4uA
5.5V      0A         0A         0A
[POWER_clamp]
|Voltage   I(typ)   I(min)   I(max)
-2.75V    2.386A     2.288A     2.687A
-1.16V    368.2mA    410.8mA    372.9mA
-1.07V    258.5mA    311.8mA    242.5mA
-980mV    153.1mA    216.2mA    121.1mA
-890mV    64.5mA     128mA      36.56mA
-800mV    18.16mA    59.6mA     13.82mA
-710mV    5.012mA    22.76mA    6.935mA
-620mV    1.706mA    5.315mA    2.959mA
-530mV    383.1uA    636.8uA    795.1uA
-440mV    42.36uA    66.97uA    84.45uA
5.5V      0A         0A         0A
[Ramp]
| variable   typ   min   max
dV/dt_r  0.8532/0.3773n   0.5846/0.6910n   1.0887/0.2460n
dV/dt_f  0.8044/0.3836n   0.4832/0.5831n   1.0835/0.2693n
R_load = 0.1100k
[Rising Waveform]
R_fixture= 0.1100k
V_fixture= 0.0
V_fixture_min= 0.0
V_fixture_max= 0.0
|time   V(typ)   V(min)   V(max)
0s        1.854nV    7.26nV     5.849nV
795.6ps   -3.358mV   216.2uV    37.45mV
904.6ps   -6.094mV   -897.8nV   283.9mV
1.17ns    54.51mV    -1.241mV   1.451V
1.507ns   808.8mV    -4.625mV   1.766V
1.703ns   1.151V     -5.381mV   1.797V
1.94ns    1.317V     42.62mV    1.809V
2.688ns   1.415V     687.6mV    1.814V
3.207ns   1.421V     885.3mV    1.814V
6.12ns    1.422V     974.3mV    1.814V
[Rising Waveform]
R_fixture= 0.1100k
V_fixture= 2.5000
V_fixture_min= 2.2500
V_fixture_max= 2.7500
|time   V(typ)   V(min)   V(max)
0s        1.159V     1.444V     944.2mV
466.5ps   1.145V     1.445V     941.3mV
651.4ps   1.146V     1.434V     1.084V
771.8ps   1.184V     1.428V     1.432V
963.7ps   1.375V     1.423V     2.514V
1.111ns   1.689V     1.432V     2.719V
1.334ns   2.335V     1.482V     2.742V
1.524ns   2.475V     1.577V     2.747V
2.363ns   2.499V     2.23V      2.75V
6.12ns    2.5V       2.25V      2.75V
[Falling Waveform]
R_fixture= 0.1100k
V_fixture= 0.0
V_fixture_min= 0.0
V_fixture_max= 0.0
|time   V(typ)   V(min)   V(max)
0s        1.422V     974.5mV    1.814V
880.2ps   1.423V     974.2mV    1.772V
978.3ps   1.425V     974.2mV    1.402V
1.134ns   1.43V      974.2mV    197.2mV
1.256ns   1.417V     974.3mV    15.98mV
1.641ns   190.8mV    976.3mV    1.163mV
1.789ns   20.3mV     978.6mV    664.1uV
2.372ns   926.6uV    907mV      177.2uV
2.971ns   224.6uV    22.2mV     77.5uV
6.12ns    7.405uV    18.67uV    -1.983uV
[Falling Waveform]
R_fixture= 0.1100k
V_fixture= 2.5000
V_fixture_min= 2.2500
V_fixture_max= 2.7500
|time   V(typ)   V(min)   V(max)
0s        2.5V       2.25V      2.75V
924.5ps   2.5V       2.25V      2.745V
1.061ns   2.499V     2.25V      2.414V
1.329ns   2.514V     2.25V      1.324V
1.487ns   2.415V     2.25V      1.084V
1.653ns   2.082V     2.25V      996.5mV
1.961ns   1.443V     2.25V      955.1mV
2.389ns   1.212V     2.258V     945.8mV
3.623ns   1.16V      1.518V     944.4mV
6.12ns    1.159V     1.445V     944.2mV
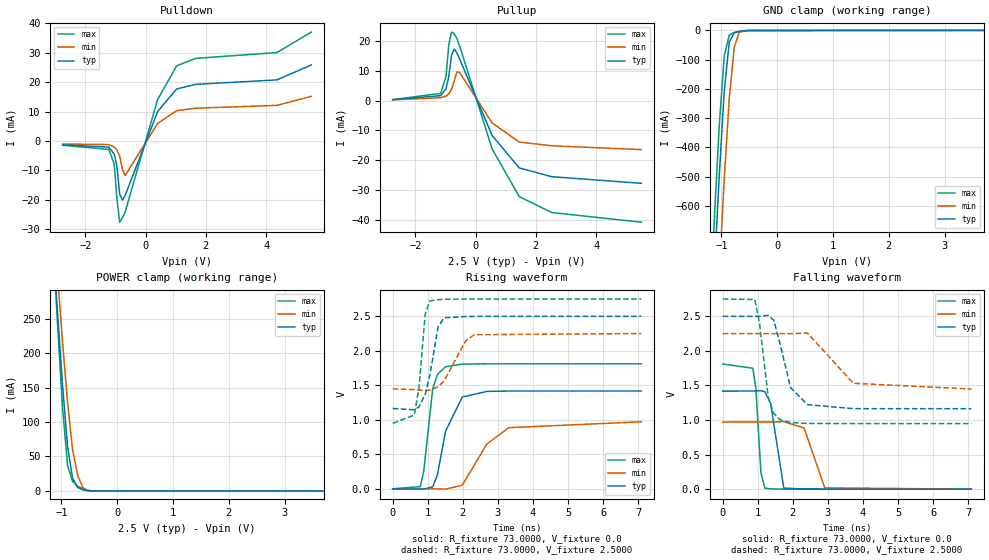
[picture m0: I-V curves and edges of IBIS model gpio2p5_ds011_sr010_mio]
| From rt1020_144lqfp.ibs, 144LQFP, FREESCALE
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[Model] gpio2p5_ds011_sr010_mio
|   Model gpio2p5_ds011_sr010_mio
| This model was characterised for following simulation conditions:
| External (pad) voltage:
|   - Typ: 2.5V,   - Min: 2.25V,   - Max: 2.75V
| Library cells for typ/min/max conditions are connected as defined below:
|  pad - External Pad
|  ipp_do - Core Input
|  ipp_obe - Output Buffer Enable
|  esd_boost - ovdd
|  ipp_dse0 - vddi
|  ipp_dse1 - vddi
|  ipp_dse2 - vssi
|  ipp_fsel0 - vssi
|  ipp_fsel1 - vddi
|  ipp_ina - ipp_ina
|  ipp_ind - ipp_ind
|  ipp_pwr_stable - vddi
|  ipp_sre - vssi
|  ovdd - ovdd
|  ovss - ovss
|  vddi - vddi
|  vssi - vssi
| All other pins connected to ground
Model_type I/O
Polarity   Non-Inverting
Enable   Active-High
Vinl =   0.7500V
Vinh =   1.7500V
Vmeas =  1.2500V
Cref =   0.0F
Rref =   73.0000
Vref =   1.2500V
C_comp   1.2356pF   1.1994pF   1.2834pF
|C_comp_pullup   0.6222pF   0.6389pF   0.6073pF
|C_comp_pulldown   0.5474pF   0.5788pF   0.5258pF
[Model Spec]
| variable   typ   min   max
Vinh   1.7500V   1.5750V   1.9250V
Vinl   0.7500V   0.6750V   0.8250V
S_overshoot_high   2.5000V   2.2500V   2.7500V
S_overshoot_low   0.0V   0.0V   0.0V
Vmeas   1.2500V   1.1250V   1.3750V
Vref   1.2500V   1.1250V   1.3750V
Cref   0.0F   0.0F   0.0F
Rref   73.0000   73.0000   73.0000
[Temperature Range]   25.0000   0.1050k   -20.0000
[Voltage Range]   2.5000V   2.2500V   2.7500V
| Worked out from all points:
|   slope of the pulldown table from 0 to 0.375 V, typ, clamps not added: 39.5 ohm
|   slope of the pullup table from 0 to 0.375 V, typ, clamps not added: 44.5 ohm
|   GND clamp passes 1 mA (typ) near -0.54 V on its own axis
|   POWER clamp passes 1 mA (typ) near -0.57 V on its own axis
|   rising waveform, R_fixture 73.0000, V_fixture 0.0: 20-80 % time 372ps typ, 730ps min, 230ps max; typ from 0 V to 1.42 V
|   rising waveform, R_fixture 73.0000, V_fixture 2.5000: 20-80 % time 287ps typ, 487ps min, 186ps max; typ from 1.16 V to 2.5 V
|   falling waveform, R_fixture 73.0000, V_fixture 0.0: 20-80 % time 174ps typ, 285ps min, 125ps max; typ from 1.42 V to 0 V
|   falling waveform, R_fixture 73.0000, V_fixture 2.5000: 20-80 % time 391ps typ, 663ps min, 253ps max; typ from 2.5 V to 1.16 V
[Pulldown]
|Voltage   I(typ)   I(min)   I(max)
-2.75V    -1.303mA   -1.044mA   -1.458mA
-1.22V    -2.085mA   -1.23mA    -2.864mA
-1.04V    -4.456mA   -2.065mA   -7.906mA
-950mV    -8.629mA   -3.037mA   -19.74mA
-860mV    -17.99mA   -5.186mA   -27.6mA
-770mV    -20.08mA   -9.605mA   -26.13mA
-680mV    -18.57mA   -11.77mA   -24.18mA
400mV     10mA       5.954mA    14.08mA
1.03V     17.67mA    10.29mA    25.51mA
1.66V     19.24mA    11.13mA    28.06mA
4.36V     20.76mA    12.1mA     30.04mA
5.5V      25.84mA    15.17mA    37mA
[Pullup]
|Voltage   I(typ)   I(min)   I(max)
-2.75V    280uA      240uA      300uA
-1.16V    1.631mA    914uA      2.392mA
-980mV    3.957mA    1.52mA     8.117mA
-890mV    7.977mA    2.227mA    18.61mA
-800mV    15.09mA    3.655mA    22.98mA
-710mV    17.3mA     6.55mA     22.47mA
-620mV    16mA       9.641mA    20.77mA
-530mV    13.95mA    9.44mA     18.36mA
550mV     -11.73mA   -7.522mA   -16.27mA
1.45V     -22.64mA   -13.95mA   -32.27mA
2.53V     -25.59mA   -15.2mA    -37.62mA
5.5V      -27.81mA   -16.48mA   -40.86mA
[GND_clamp]
|Voltage   I(typ)   I(min)   I(max)
-2.75V    -7.488A    -7.708A    -7.379A
-1.22V    -1.193A    -1.537A    -1.012A
-1.13V    -835.6mA   -1.18A     -654.7mA
-1.04V    -497.8mA   -833mA     -328mA
-950mV    -208.9mA   -508.7mA   -87.54mA
-860mV    -39.89mA   -232.5mA   -15.89mA
-770mV    -7.264mA   -56.44mA   -8.363mA
-680mV    -3.422mA   -7.048mA   -4.851mA
-590mV    -1.552mA   -1.455mA   -2.251mA
-500mV    -482.7uA   -438.2uA   -698.4uA
5.5V      0A         0A         0A
[POWER_clamp]
|Voltage   I(typ)   I(min)   I(max)
-2.75V    2.386A     2.288A     2.687A
-1.16V    368.2mA    410.8mA    372.9mA
-1.07V    258.5mA    311.8mA    242.5mA
-980mV    153.1mA    216.2mA    121.1mA
-890mV    64.5mA     128mA      36.56mA
-800mV    18.16mA    59.6mA     13.82mA
-710mV    5.012mA    22.76mA    6.935mA
-620mV    1.706mA    5.315mA    2.959mA
-530mV    383.1uA    636.8uA    795.1uA
-440mV    42.36uA    66.97uA    84.45uA
5.5V      0A         0A         0A
[Ramp]
| variable   typ   min   max
dV/dt_r  0.8510/0.3718n   0.5826/0.7298n   1.0865/0.2298n
dV/dt_f  0.8015/0.3912n   0.4812/0.6632n   1.0807/0.2531n
R_load = 73.0000
[Rising Waveform]
R_fixture= 73.0000
V_fixture= 0.0
V_fixture_min= 0.0
V_fixture_max= 0.0
|time   V(typ)   V(min)   V(max)
0s        1.235nV    4.832nV    3.898nV
784.9ps   -3.465mV   233.8uV    30.93mV
883.3ps   -5.841mV   55.19uV    248.4mV
1.141ns   28.46mV    -1.111mV   1.451V
1.275ns   201.9mV    -2.102mV   1.658V
1.507ns   834.9mV    -4.635mV   1.768V
1.984ns   1.33V      51.18mV    1.807V
2.686ns   1.411V     649.8mV    1.811V
3.31ns    1.417V     885.6mV    1.811V
7.09ns    1.418V     971.1mV    1.811V
[Rising Waveform]
R_fixture= 73.0000
V_fixture= 2.5000
V_fixture_min= 2.2500
V_fixture_max= 2.7500
|time   V(typ)   V(min)   V(max)
0s        1.164V     1.448V     948.9mV
614.7ps   1.145V     1.438V     1.069V
745.8ps   1.185V     1.43V      1.449V
927.7ps   1.371V     1.423V     2.534V
1.057ns   1.642V     1.429V     2.722V
1.295ns   2.346V     1.478V     2.742V
1.466ns   2.478V     1.563V     2.746V
2.079ns   2.497V     2.142V     2.75V
2.324ns   2.499V     2.233V     2.75V
7.09ns    2.5V       2.25V      2.75V
[Falling Waveform]
R_fixture= 73.0000
V_fixture= 0.0
V_fixture_min= 0.0
V_fixture_max= 0.0
|time   V(typ)   V(min)   V(max)
0s        1.418V     971.1mV    1.811V
860.3ps   1.42V      971.5mV    1.749V
945.2ps   1.422V     971.5mV    1.454V
1.092ns   1.424V     971.5mV    230.8mV
1.202ns   1.41V      971.6mV    16.02mV
1.366ns   1.24V      971.9mV    3.902mV
1.742ns   16.01mV    976.4mV    738.5uV
2.321ns   1.103mV    885.1mV    141.3uV
2.911ns   234.7uV    18.79mV    53.25uV
7.09ns    1.758uV    8.441uV    -1.245uV
[Falling Waveform]
R_fixture= 73.0000
V_fixture= 2.5000
V_fixture_min= 2.2500
V_fixture_max= 2.7500
|time   V(typ)   V(min)   V(max)
0s        2.5V       2.25V      2.75V
914.2ps   2.5V       2.25V      2.744V
1.051ns   2.5V       2.25V      2.401V
1.298ns   2.514V     2.25V      1.329V
1.457ns   2.443V     2.25V      1.095V
1.633ns   2.106V     2.25V      1.006V
1.937ns   1.468V     2.25V      962.9mV
2.419ns   1.222V     2.257V     950.7mV
3.724ns   1.165V     1.532V     949mV
7.09ns    1.164V     1.448V     948.9mV
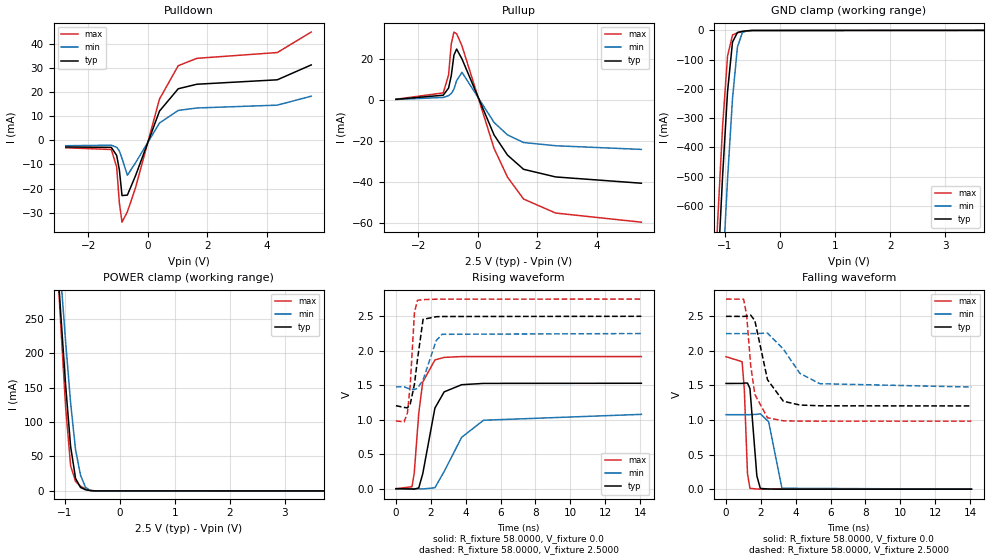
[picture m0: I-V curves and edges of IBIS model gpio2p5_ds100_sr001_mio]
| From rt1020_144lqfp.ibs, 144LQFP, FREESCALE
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[Model] gpio2p5_ds100_sr001_mio
|   Model gpio2p5_ds100_sr001_mio
| This model was characterised for following simulation conditions:
| External (pad) voltage:
|   - Typ: 2.5V,   - Min: 2.25V,   - Max: 2.75V
| Library cells for typ/min/max conditions are connected as defined below:
|  pad - External Pad
|  ipp_do - Core Input
|  ipp_obe - Output Buffer Enable
|  esd_boost - ovdd
|  ipp_dse0 - vssi
|  ipp_dse1 - vssi
|  ipp_dse2 - vddi
|  ipp_fsel0 - vddi
|  ipp_fsel1 - vssi
|  ipp_ina - ipp_ina
|  ipp_ind - ipp_ind
|  ipp_pwr_stable - vddi
|  ipp_sre - vssi
|  ovdd - ovdd
|  ovss - ovss
|  vddi - vddi
|  vssi - vssi
| All other pins connected to ground
Model_type I/O
Polarity   Non-Inverting
Enable   Active-High
Vinl =   0.7500V
Vinh =   1.7500V
Vmeas =  1.2500V
Cref =   0.0F
Rref =   58.0000
Vref =   1.2500V
C_comp   1.2356pF   1.1994pF   1.2834pF
|C_comp_pullup   0.6221pF   0.6388pF   0.6072pF
|C_comp_pulldown   0.5474pF   0.5787pF   0.5258pF
[Model Spec]
| variable   typ   min   max
Vinh   1.7500V   1.5750V   1.9250V
Vinl   0.7500V   0.6750V   0.8250V
S_overshoot_high   2.5000V   2.2500V   2.7500V
S_overshoot_low   0.0V   0.0V   0.0V
Vmeas   1.2500V   1.1250V   1.3750V
Vref   1.2500V   1.1250V   1.3750V
Cref   0.0F   0.0F   0.0F
Rref   58.0000   58.0000   58.0000
[Temperature Range]   25.0000   0.1050k   -20.0000
[Voltage Range]   2.5000V   2.2500V   2.7500V
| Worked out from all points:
|   slope of the pulldown table from 0 to 0.375 V, typ, clamps not added: 32.5 ohm
|   slope of the pullup table from 0 to 0.375 V, typ, clamps not added: 30.7 ohm
|   GND clamp passes 1 mA (typ) near -0.54 V on its own axis
|   POWER clamp passes 1 mA (typ) near -0.57 V on its own axis
|   rising waveform, R_fixture 58.0000, V_fixture 0.0: 20-80 % time 721ps typ, 1.45ns min, 429ps max; typ from 0 V to 1.53 V
|   rising waveform, R_fixture 58.0000, V_fixture 2.5000: 20-80 % time 363ps typ, 586ps min, 251ps max; typ from 1.2 V to 2.5 V
|   falling waveform, R_fixture 58.0000, V_fixture 0.0: 20-80 % time 233ps typ, 362ps min, 169ps max; typ from 1.53 V to 0 V
|   falling waveform, R_fixture 58.0000, V_fixture 2.5000: 20-80 % time 747ps typ, 1.29ns min, 453ps max; typ from 2.5 V to 1.2 V
[Pulldown]
|Voltage   I(typ)   I(min)   I(max)
-2.75V    -2.761mA   -2.233mA   -3.086mA
-1.22V    -2.901mA   -2.018mA   -3.8mA
-1.04V    -6.257mA   -2.877mA   -11.05mA
-950mV    -12.24mA   -4.387mA   -25.89mA
-860mV    -22.93mA   -7.491mA   -33.98mA
-680mV    -22.73mA   -14.5mA    -29.66mA
-410mV    -14.8mA    -9.393mA   -19.86mA
400mV     12.16mA    7.219mA    17.16mA
1.03V     21.43mA    12.43mA    31mA
1.66V     23.3mA     13.44mA    34.06mA
4.36V     25.14mA    14.62mA    36.46mA
5.5V      31.32mA    18.34mA    44.95mA
[Pullup]
|Voltage   I(typ)   I(min)   I(max)
-2.75V    410uA      350uA      450uA
-1.16V    2.417mA    1.339mA    3.554mA
-980mV    5.918mA    2.226mA    12.31mA
-890mV    11.95mA    3.26mA     27.43mA
-800mV    21.99mA    5.348mA    33.28mA
-710mV    24.98mA    9.532mA    32.5mA
-530mV    20.16mA    13.63mA    26.57mA
550mV     -17.02mA   -10.92mA   -23.61mA
1V        -26.84mA   -16.97mA   -37.61mA
1.54V     -33.79mA   -20.71mA   -48.33mA
2.62V     -37.53mA   -22.28mA   -55.18mA
5.5V      -40.6mA    -24.07mA   -59.65mA
[GND_clamp]
|Voltage   I(typ)   I(min)   I(max)
-2.75V    -7.488A    -7.708A    -7.379A
-1.22V    -1.193A    -1.537A    -1.012A
-1.13V    -835.6mA   -1.18A     -654.7mA
-1.04V    -497.8mA   -833mA     -328mA
-950mV    -208.9mA   -508.7mA   -87.54mA
-860mV    -39.89mA   -232.5mA   -15.89mA
-770mV    -7.264mA   -56.44mA   -8.363mA
-680mV    -3.422mA   -7.048mA   -4.851mA
-590mV    -1.552mA   -1.455mA   -2.251mA
-500mV    -482.7uA   -438.2uA   -698.4uA
5.5V      0A         0A         0A
[POWER_clamp]
|Voltage   I(typ)   I(min)   I(max)
-2.75V    2.386A     2.288A     2.687A
-1.16V    368.2mA    410.8mA    372.9mA
-1.07V    258.5mA    311.8mA    242.5mA
-980mV    153.1mA    216.2mA    121.1mA
-890mV    64.5mA     128mA      36.56mA
-800mV    18.16mA    59.6mA     13.82mA
-710mV    5.012mA    22.76mA    6.935mA
-620mV    1.706mA    5.315mA    2.959mA
-530mV    383.1uA    636.8uA    795.1uA
-440mV    42.36uA    66.97uA    84.45uA
5.5V      0A         0A         0A
[Ramp]
| variable   typ   min   max
dV/dt_r  0.9172/0.7212n   0.6469/1.4518n   1.1497/0.4292n
dV/dt_f  0.7774/0.7468n   0.4639/1.2855n   1.0598/0.4532n
R_load = 58.0000
[Rising Waveform]
R_fixture= 58.0000
V_fixture= 0.0
V_fixture_min= 0.0
V_fixture_max= 0.0
|time   V(typ)   V(min)   V(max)
0s        1.003nV    3.879nV    3.167nV
921.9ps   -4.594mV   183.3uV    28.4mV
1.05ns    -6.753mV   -251.8uV   224.8mV
1.309ns   11.45mV    -1.635mV   1.091V
1.537ns   214.4mV    -3.385mV   1.545V
2.236ns   1.169V     13.7mV     1.867V
2.766ns   1.404V     248.8mV    1.904V
3.769ns   1.508V     744.7mV    1.916V
5.026ns   1.527V     992.7mV    1.916V
14.08ns   1.529V     1.078V     1.916V
[Rising Waveform]
R_fixture= 58.0000
V_fixture= 2.5000
V_fixture_min= 2.2500
V_fixture_max= 2.7500
|time   V(typ)   V(min)   V(max)
0s        1.204V     1.477V     983.7mV
466.8ps   1.179V     1.477V     967.4mV
663.4ps   1.172V     1.458V     1.103V
822.5ps   1.228V     1.444V     1.511V
1.062ns   1.514V     1.438V     2.552V
1.234ns   1.87V      1.456V     2.732V
1.558ns   2.456V     1.578V     2.742V
2.307ns   2.494V     2.146V     2.748V
2.65ns    2.497V     2.239V     2.749V
14.08ns   2.5V       2.25V      2.75V
[Falling Waveform]
R_fixture= 58.0000
V_fixture= 0.0
V_fixture_min= 0.0
V_fixture_max= 0.0
|time   V(typ)   V(min)   V(max)
0s        1.529V     1.078V     1.916V
920ps     1.53V      1.078V     1.844V
1.047ns   1.535V     1.078V     1.449V
1.23ns    1.535V     1.078V     223.7mV
1.371ns   1.456V     1.078V     12.05mV
1.767ns   192.4mV    1.083V     2.332mV
1.966ns   10.71mV    1.09V      1.467mV
2.442ns   2.353mV    976.2mV    485.1uV
3.206ns   647.1uV    12.66mV    81.79uV
14.08ns   21.73nV    38.93nV    -26.51nV
[Falling Waveform]
R_fixture= 58.0000
V_fixture= 2.5000
V_fixture_min= 2.2500
V_fixture_max= 2.7500
|time   V(typ)   V(min)   V(max)
0s        2.5V       2.25V      2.75V
1.008ns   2.499V     2.25V      2.748V
1.182ns   2.502V     2.25V      2.516V
1.414ns   2.517V     2.25V      1.788V
1.653ns   2.438V     2.25V      1.371V
2.378ns   1.583V     2.258V     1.033V
3.287ns   1.272V     2.026V     988.8mV
4.235ns   1.217V     1.675V     984.1mV
5.384ns   1.206V     1.526V     983.7mV
14.08ns   1.204V     1.477V     983.7mV
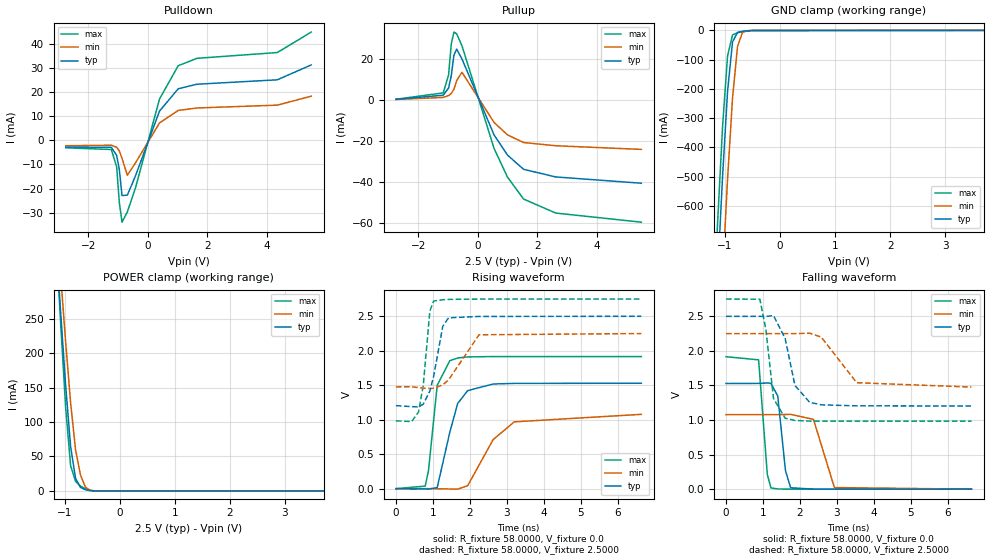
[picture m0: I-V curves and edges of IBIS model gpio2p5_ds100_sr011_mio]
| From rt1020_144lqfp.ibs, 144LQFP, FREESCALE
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[Model] gpio2p5_ds100_sr011_mio
|   Model gpio2p5_ds100_sr011_mio
| This model was characterised for following simulation conditions:
| External (pad) voltage:
|   - Typ: 2.5V,   - Min: 2.25V,   - Max: 2.75V
| Library cells for typ/min/max conditions are connected as defined below:
|  pad - External Pad
|  ipp_do - Core Input
|  ipp_obe - Output Buffer Enable
|  esd_boost - ovdd
|  ipp_dse0 - vssi
|  ipp_dse1 - vssi
|  ipp_dse2 - vddi
|  ipp_fsel0 - vddi
|  ipp_fsel1 - vddi
|  ipp_ina - ipp_ina
|  ipp_ind - ipp_ind
|  ipp_pwr_stable - vddi
|  ipp_sre - vssi
|  ovdd - ovdd
|  ovss - ovss
|  vddi - vddi
|  vssi - vssi
| All other pins connected to ground
Model_type I/O
Polarity   Non-Inverting
Enable   Active-High
Vinl =   0.7500V
Vinh =   1.7500V
Vmeas =  1.2500V
Cref =   0.0F
Rref =   58.0000
Vref =   1.2500V
C_comp   1.2356pF   1.1994pF   1.2834pF
|C_comp_pullup   0.6222pF   0.6389pF   0.6073pF
|C_comp_pulldown   0.5474pF   0.5788pF   0.5258pF
[Model Spec]
| variable   typ   min   max
Vinh   1.7500V   1.5750V   1.9250V
Vinl   0.7500V   0.6750V   0.8250V
S_overshoot_high   2.5000V   2.2500V   2.7500V
S_overshoot_low   0.0V   0.0V   0.0V
Vmeas   1.2500V   1.1250V   1.3750V
Vref   1.2500V   1.1250V   1.3750V
Cref   0.0F   0.0F   0.0F
Rref   58.0000   58.0000   58.0000
[Temperature Range]   25.0000   0.1050k   -20.0000
[Voltage Range]   2.5000V   2.2500V   2.7500V
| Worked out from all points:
|   slope of the pulldown table from 0 to 0.375 V, typ, clamps not added: 32.5 ohm
|   slope of the pullup table from 0 to 0.375 V, typ, clamps not added: 30.7 ohm
|   GND clamp passes 1 mA (typ) near -0.54 V on its own axis
|   POWER clamp passes 1 mA (typ) near -0.57 V on its own axis
|   rising waveform, R_fixture 58.0000, V_fixture 0.0: 20-80 % time 364ps typ, 715ps min, 224ps max; typ from 0 V to 1.53 V
|   rising waveform, R_fixture 58.0000, V_fixture 2.5000: 20-80 % time 279ps typ, 469ps min, 181ps max; typ from 1.2 V to 2.5 V
|   falling waveform, R_fixture 58.0000, V_fixture 0.0: 20-80 % time 165ps typ, 263ps min, 123ps max; typ from 1.53 V to 0 V
|   falling waveform, R_fixture 58.0000, V_fixture 2.5000: 20-80 % time 319ps typ, 509ps min, 221ps max; typ from 2.5 V to 1.2 V
[Pulldown]
|Voltage   I(typ)   I(min)   I(max)
-2.75V    -2.761mA   -2.233mA   -3.086mA
-1.22V    -2.901mA   -2.018mA   -3.8mA
-1.04V    -6.257mA   -2.877mA   -11.05mA
-950mV    -12.24mA   -4.387mA   -25.89mA
-860mV    -22.93mA   -7.491mA   -33.98mA
-680mV    -22.73mA   -14.5mA    -29.66mA
-410mV    -14.8mA    -9.393mA   -19.86mA
400mV     12.16mA    7.219mA    17.16mA
1.03V     21.43mA    12.43mA    31mA
1.66V     23.3mA     13.44mA    34.06mA
4.36V     25.14mA    14.62mA    36.46mA
5.5V      31.32mA    18.34mA    44.95mA
[Pullup]
|Voltage   I(typ)   I(min)   I(max)
-2.75V    410uA      350uA      450uA
-1.16V    2.417mA    1.339mA    3.554mA
-980mV    5.918mA    2.226mA    12.31mA
-890mV    11.95mA    3.26mA     27.43mA
-800mV    21.99mA    5.348mA    33.28mA
-710mV    24.98mA    9.532mA    32.5mA
-530mV    20.16mA    13.63mA    26.57mA
550mV     -17.02mA   -10.92mA   -23.61mA
1V        -26.84mA   -16.97mA   -37.61mA
1.54V     -33.79mA   -20.71mA   -48.33mA
2.62V     -37.53mA   -22.28mA   -55.18mA
5.5V      -40.6mA    -24.07mA   -59.65mA
[GND_clamp]
|Voltage   I(typ)   I(min)   I(max)
-2.75V    -7.488A    -7.708A    -7.379A
-1.22V    -1.193A    -1.537A    -1.012A
-1.13V    -835.6mA   -1.18A     -654.7mA
-1.04V    -497.8mA   -833mA     -328mA
-950mV    -208.9mA   -508.7mA   -87.54mA
-860mV    -39.89mA   -232.5mA   -15.89mA
-770mV    -7.264mA   -56.44mA   -8.363mA
-680mV    -3.422mA   -7.048mA   -4.851mA
-590mV    -1.552mA   -1.455mA   -2.251mA
-500mV    -482.7uA   -438.2uA   -698.4uA
5.5V      0A         0A         0A
[POWER_clamp]
|Voltage   I(typ)   I(min)   I(max)
-2.75V    2.386A     2.288A     2.687A
-1.16V    368.2mA    410.8mA    372.9mA
-1.07V    258.5mA    311.8mA    242.5mA
-980mV    153.1mA    216.2mA    121.1mA
-890mV    64.5mA     128mA      36.56mA
-800mV    18.16mA    59.6mA     13.82mA
-710mV    5.012mA    22.76mA    6.935mA
-620mV    1.706mA    5.315mA    2.959mA
-530mV    383.1uA    636.8uA    795.1uA
-440mV    42.36uA    66.97uA    84.45uA
5.5V      0A         0A         0A
[Ramp]
| variable   typ   min   max
dV/dt_r  0.9172/0.3643n   0.6468/0.7155n   1.1497/0.2236n
dV/dt_f  0.7774/0.3192n   0.4639/0.5093n   1.0598/0.2206n
R_load = 58.0000
[Rising Waveform]
R_fixture= 58.0000
V_fixture= 0.0
V_fixture_min= 0.0
V_fixture_max= 0.0
|time   V(typ)   V(min)   V(max)
0s        1.003nV    3.899nV    3.167nV
792ps     -3.885mV   217.2uV    37.29mV
881.2ps   -6.349mV   22.86uV    261.5mV
1.117ns   16.1mV     -1.128mV   1.5V
1.46ns    823.1mV    -4.662mV   1.857V
1.671ns   1.236V     -7.181mV   1.895V
1.942ns   1.422V     43.85mV    1.911V
2.629ns   1.518V     710.7mV    1.916V
3.201ns   1.527V     969.2mV    1.916V
6.64ns    1.529V     1.078V     1.916V
[Rising Waveform]
R_fixture= 58.0000
V_fixture= 2.5000
V_fixture_min= 2.2500
V_fixture_max= 2.7500
|time   V(typ)   V(min)   V(max)
0s        1.204V     1.477V     983.7mV
425.8ps   1.19V      1.478V     973.7mV
612.3ps   1.185V     1.466V     1.112V
740.1ps   1.227V     1.458V     1.5V
918.6ps   1.417V     1.453V     2.578V
1.021ns   1.629V     1.457V     2.721V
1.268ns   2.356V     1.505V     2.74V
1.424ns   2.478V     1.578V     2.745V
2.25ns    2.498V     2.232V     2.75V
6.64ns    2.5V       2.25V      2.75V
[Falling Waveform]
R_fixture= 58.0000
V_fixture= 0.0
V_fixture_min= 0.0
V_fixture_max= 0.0
|time   V(typ)   V(min)   V(max)
0s        1.529V     1.078V     1.916V
880.7ps   1.53V      1.078V     1.871V
1.116ns   1.536V     1.078V     214.3mV
1.215ns   1.531V     1.078V     17.45mV
1.399ns   1.348V     1.078V     3.139mV
1.607ns   270.5mV    1.08V      975.1uV
1.747ns   20.24mV    1.082V     519.9uV
2.365ns   660.8uV    1.01V      107.6uV
2.931ns   132.3uV    23.05mV    53.03uV
6.64ns    -418nV     10.82uV    652.4nV
[Falling Waveform]
R_fixture= 58.0000
V_fixture= 2.5000
V_fixture_min= 2.2500
V_fixture_max= 2.7500
|time   V(typ)   V(min)   V(max)
0s        2.5V       2.25V      2.75V
915.2ps   2.5V       2.25V      2.748V
1.076ns   2.499V     2.25V      2.316V
1.285ns   2.511V     2.25V      1.31V
1.601ns   2.176V     2.25V      1.026V
1.864ns   1.5V       2.25V      993.9mV
2.263ns   1.256V     2.256V     985mV
2.575ns   1.22V      2.2V       984mV
3.535ns   1.205V     1.54V      983.8mV
6.64ns    1.204V     1.477V     983.7mV
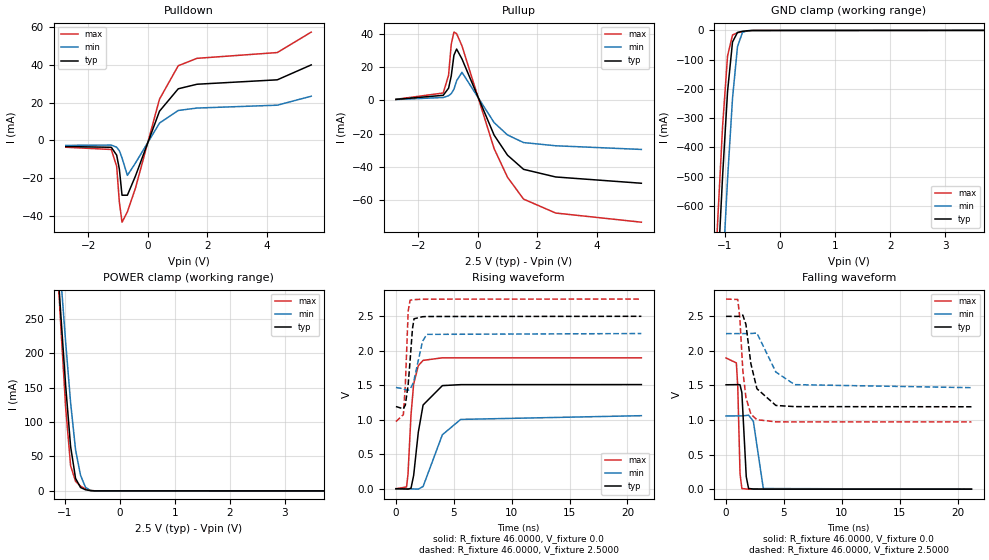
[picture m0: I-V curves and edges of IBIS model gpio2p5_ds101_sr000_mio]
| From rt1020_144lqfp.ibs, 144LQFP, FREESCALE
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[Model] gpio2p5_ds101_sr000_mio
|   Model gpio2p5_ds101_sr000_mio
| This model was characterised for following simulation conditions:
| External (pad) voltage:
|   - Typ: 2.5V,   - Min: 2.25V,   - Max: 2.75V
| Library cells for typ/min/max conditions are connected as defined below:
|  pad - External Pad
|  ipp_do - Core Input
|  ipp_obe - Output Buffer Enable
|  esd_boost - ovdd
|  ipp_dse0 - vddi
|  ipp_dse1 - vssi
|  ipp_dse2 - vddi
|  ipp_fsel0 - vssi
|  ipp_fsel1 - vssi
|  ipp_ina - ipp_ina
|  ipp_ind - ipp_ind
|  ipp_pwr_stable - vddi
|  ipp_sre - vssi
|  ovdd - ovdd
|  ovss - ovss
|  vddi - vddi
|  vssi - vssi
| All other pins connected to ground
Model_type I/O
Polarity   Non-Inverting
Enable   Active-High
Vinl =   0.7500V
Vinh =   1.7500V
Vmeas =  1.2500V
Cref =   0.0F
Rref =   46.0000
Vref =   1.2500V
C_comp   1.2356pF   1.1994pF   1.2834pF
|C_comp_pullup   0.6221pF   0.6388pF   0.6072pF
|C_comp_pulldown   0.5474pF   0.5787pF   0.5258pF
[Model Spec]
| variable   typ   min   max
Vinh   1.7500V   1.5750V   1.9250V
Vinl   0.7500V   0.6750V   0.8250V
S_overshoot_high   2.5000V   2.2500V   2.7500V
S_overshoot_low   0.0V   0.0V   0.0V
Vmeas   1.2500V   1.1250V   1.3750V
Vref   1.2500V   1.1250V   1.3750V
Cref   0.0F   0.0F   0.0F
Rref   46.0000   46.0000   46.0000
[Temperature Range]   25.0000   0.1050k   -20.0000
[Voltage Range]   2.5000V   2.2500V   2.7500V
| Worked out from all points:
|   slope of the pulldown table from 0 to 0.375 V, typ, clamps not added: 25.5 ohm
|   slope of the pullup table from 0 to 0.375 V, typ, clamps not added: 25 ohm
|   GND clamp passes 1 mA (typ) near -0.54 V on its own axis
|   POWER clamp passes 1 mA (typ) near -0.57 V on its own axis
|   rising waveform, R_fixture 46.0000, V_fixture 0.0: 20-80 % time 739ps typ, 1.51ns min, 434ps max; typ from 0 V to 1.51 V
|   rising waveform, R_fixture 46.0000, V_fixture 2.5000: 20-80 % time 363ps typ, 593ps min, 249ps max; typ from 1.19 V to 2.5 V
|   falling waveform, R_fixture 46.0000, V_fixture 0.0: 20-80 % time 243ps typ, 375ps min, 173ps max; typ from 1.51 V to 0 V
|   falling waveform, R_fixture 46.0000, V_fixture 2.5000: 20-80 % time 833ps typ, 1.48ns min, 490ps max; typ from 2.5 V to 1.19 V
[Pulldown]
|Voltage   I(typ)   I(min)   I(max)
-2.75V    -3.197mA   -2.582mA   -3.573mA
-1.22V    -3.596mA   -2.428mA   -4.755mA
-1.04V    -7.744mA   -3.566mA   -13.69mA
-950mV    -15.11mA   -5.401mA   -32.48mA
-860mV    -28.93mA   -9.221mA   -43.18mA
-680mV    -28.92mA   -18.42mA   -37.72mA
-410mV    -18.84mA   -11.96mA   -25.27mA
400mV     15.49mA    9.203mA    21.85mA
1.03V     27.32mA    15.86mA    39.51mA
1.66V     29.72mA    17.14mA    43.41mA
4.36V     32.06mA    18.65mA    46.47mA
5.5V      39.94mA    23.39mA    57.28mA
[Pullup]
|Voltage   I(typ)   I(min)   I(max)
-2.75V    500uA      430uA      550uA
-1.16V    2.96mA     1.644mA    4.352mA
-980mV    7.238mA    2.732mA    15.03mA
-890mV    14.62mA    4.003mA    33.68mA
-800mV    27.04mA    6.569mA    40.94mA
-710mV    30.75mA    11.72mA    39.99mA
-530mV    24.8mA     16.78mA    32.68mA
550mV     -20.93mA   -13.43mA   -29.03mA
1V        -32.99mA   -20.85mA   -46.23mA
1.54V     -41.51mA   -25.43mA   -59.39mA
2.62V     -46.1mA    -27.36mA   -67.77mA
5.5V      -49.87mA   -29.56mA   -73.27mA
[GND_clamp]
|Voltage   I(typ)   I(min)   I(max)
-2.75V    -7.488A    -7.708A    -7.379A
-1.22V    -1.193A    -1.537A    -1.012A
-1.13V    -835.6mA   -1.18A     -654.7mA
-1.04V    -497.8mA   -833mA     -328mA
-950mV    -208.9mA   -508.7mA   -87.54mA
-860mV    -39.89mA   -232.5mA   -15.89mA
-770mV    -7.264mA   -56.44mA   -8.363mA
-680mV    -3.422mA   -7.048mA   -4.851mA
-590mV    -1.552mA   -1.455mA   -2.251mA
-500mV    -482.7uA   -438.2uA   -698.4uA
5.5V      0A         0A         0A
[POWER_clamp]
|Voltage   I(typ)   I(min)   I(max)
-2.75V    2.386A     2.288A     2.687A
-1.16V    368.2mA    410.8mA    372.9mA
-1.07V    258.5mA    311.8mA    242.5mA
-980mV    153.1mA    216.2mA    121.1mA
-890mV    64.5mA     128mA      36.56mA
-800mV    18.16mA    59.6mA     13.82mA
-710mV    5.012mA    22.76mA    6.935mA
-620mV    1.706mA    5.315mA    2.959mA
-530mV    383.1uA    636.8uA    795.1uA
-440mV    42.36uA    66.97uA    84.45uA
5.5V      0A         0A         0A
[Ramp]
| variable   typ   min   max
dV/dt_r  0.9057/0.7388n   0.6355/1.5142n   1.1389/0.4340n
dV/dt_f  0.7845/0.8327n   0.4689/1.4842n   1.0662/0.4903n
R_load = 46.0000
[Rising Waveform]
R_fixture= 46.0000
V_fixture= 0.0
V_fixture_min= 0.0
V_fixture_max= 0.0
|time   V(typ)   V(min)   V(max)
0s        789.8pV    3.083nV    2.494nV
917.8ps   -4.501mV   189uV      25.67mV
1.042ns   -6.49mV    -220.6uV   206.2mV
1.303ns   7.541mV    -1.563mV   1.071V
1.531ns   192.3mV    -3.236mV   1.519V
1.933ns   819.3mV    -5.605mV   1.784V
2.347ns   1.214V     32.31mV    1.861V
4.012ns   1.495V     782.6mV    1.898V
5.596ns   1.509V     1.005V     1.898V
21.2ns    1.51V      1.059V     1.898V
[Rising Waveform]
R_fixture= 46.0000
V_fixture= 2.5000
V_fixture_min= 2.2500
V_fixture_max= 2.7500
|time   V(typ)   V(min)   V(max)
0s        1.192V     1.468V     973mV
643.1ps   1.158V     1.45V      1.074V
813.2ps   1.214V     1.435V     1.502V
1.06ns    1.515V     1.428V     2.578V
1.224ns   1.86V      1.446V     2.733V
1.429ns   2.319V     1.508V     2.74V
1.564ns   2.464V     1.577V     2.742V
2.297ns   2.494V     2.137V     2.748V
2.662ns   2.497V     2.238V     2.749V
21.2ns    2.5V       2.25V      2.75V
[Falling Waveform]
R_fixture= 46.0000
V_fixture= 0.0
V_fixture_min= 0.0
V_fixture_max= 0.0
|time   V(typ)   V(min)   V(max)
0s        1.51V      1.059V     1.898V
891.6ps   1.512V     1.06V      1.826V
1.012ns   1.515V     1.06V      1.483V
1.209ns   1.509V     1.06V      220.3mV
1.366ns   1.396V     1.06V      9.555mV
1.745ns   180.9mV    1.065V     2.415mV
1.945ns   9.786mV    1.071V     1.57mV
2.359ns   2.66mV     981.4mV    645.8uV
3.219ns   689.6uV    8.876mV    103.2uV
21.2ns    -1.105nV   7.971nV    4.603nV
[Falling Waveform]
R_fixture= 46.0000
V_fixture= 2.5000
V_fixture_min= 2.2500
V_fixture_max= 2.7500
|time   V(typ)   V(min)   V(max)
0s        2.5V       2.25V      2.75V
1.014ns   2.499V     2.25V      2.744V
1.193ns   2.503V     2.25V      2.474V
1.447ns   2.518V     2.25V      1.721V
1.715ns   2.385V     2.25V      1.327V
2.147ns   1.813V     2.252V     1.084V
2.667ns   1.453V     2.258V     1.005V
4.304ns   1.211V     1.694V     973.8mV
5.929ns   1.194V     1.512V     973mV
21.2ns    1.192V     1.468V     973mV
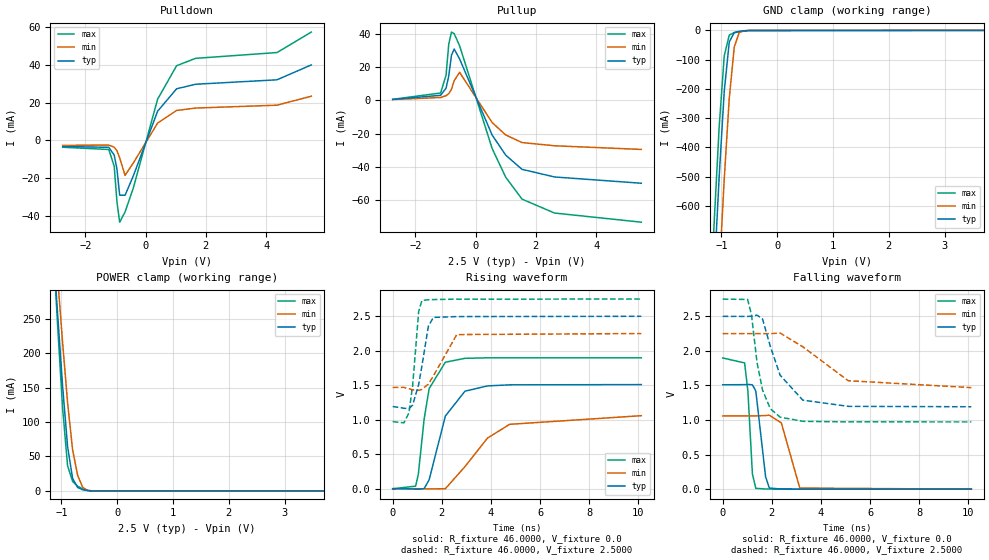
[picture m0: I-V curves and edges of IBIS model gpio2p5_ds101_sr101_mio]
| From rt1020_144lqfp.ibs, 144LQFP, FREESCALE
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[Model] gpio2p5_ds101_sr101_mio
|   Model gpio2p5_ds101_sr101_mio
| This model was characterised for following simulation conditions:
| External (pad) voltage:
|   - Typ: 2.5V,   - Min: 2.25V,   - Max: 2.75V
| Library cells for typ/min/max conditions are connected as defined below:
|  pad - External Pad
|  ipp_do - Core Input
|  ipp_obe - Output Buffer Enable
|  esd_boost - ovdd
|  ipp_dse0 - vddi
|  ipp_dse1 - vssi
|  ipp_dse2 - vddi
|  ipp_fsel0 - vddi
|  ipp_fsel1 - vssi
|  ipp_ina - ipp_ina
|  ipp_ind - ipp_ind
|  ipp_pwr_stable - vddi
|  ipp_sre - vddi
|  ovdd - ovdd
|  ovss - ovss
|  vddi - vddi
|  vssi - vssi
| All other pins connected to ground
Model_type I/O
Polarity   Non-Inverting
Enable   Active-High
Vinl =   0.7500V
Vinh =   1.7500V
Vmeas =  1.2500V
Cref =   0.0F
Rref =   46.0000
Vref =   1.2500V
C_comp   1.2356pF   1.1994pF   1.2834pF
|C_comp_pullup   0.6221pF   0.6388pF   0.6072pF
|C_comp_pulldown   0.5474pF   0.5787pF   0.5258pF
[Model Spec]
| variable   typ   min   max
Vinh   1.7500V   1.5750V   1.9250V
Vinl   0.7500V   0.6750V   0.8250V
S_overshoot_high   2.5000V   2.2500V   2.7500V
S_overshoot_low   0.0V   0.0V   0.0V
Vmeas   1.2500V   1.1250V   1.3750V
Vref   1.2500V   1.1250V   1.3750V
Cref   0.0F   0.0F   0.0F
Rref   46.0000   46.0000   46.0000
[Temperature Range]   25.0000   0.1050k   -20.0000
[Voltage Range]   2.5000V   2.2500V   2.7500V
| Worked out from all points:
|   slope of the pulldown table from 0 to 0.375 V, typ, clamps not added: 25.5 ohm
|   slope of the pullup table from 0 to 0.375 V, typ, clamps not added: 25 ohm
|   GND clamp passes 1 mA (typ) near -0.54 V on its own axis
|   POWER clamp passes 1 mA (typ) near -0.57 V on its own axis
|   rising waveform, R_fixture 46.0000, V_fixture 0.0: 20-80 % time 739ps typ, 1.51ns min, 434ps max; typ from 0 V to 1.51 V
|   rising waveform, R_fixture 46.0000, V_fixture 2.5000: 20-80 % time 363ps typ, 593ps min, 249ps max; typ from 1.19 V to 2.5 V
|   falling waveform, R_fixture 46.0000, V_fixture 0.0: 20-80 % time 243ps typ, 375ps min, 173ps max; typ from 1.51 V to 0 V
|   falling waveform, R_fixture 46.0000, V_fixture 2.5000: 20-80 % time 833ps typ, 1.48ns min, 490ps max; typ from 2.5 V to 1.19 V
[Pulldown]
|Voltage   I(typ)   I(min)   I(max)
-2.75V    -3.197mA   -2.582mA   -3.573mA
-1.22V    -3.596mA   -2.428mA   -4.755mA
-1.04V    -7.744mA   -3.566mA   -13.69mA
-950mV    -15.11mA   -5.401mA   -32.48mA
-860mV    -28.93mA   -9.221mA   -43.18mA
-680mV    -28.92mA   -18.42mA   -37.72mA
-410mV    -18.84mA   -11.96mA   -25.27mA
400mV     15.49mA    9.203mA    21.85mA
1.03V     27.32mA    15.86mA    39.51mA
1.66V     29.72mA    17.14mA    43.41mA
4.36V     32.06mA    18.65mA    46.47mA
5.5V      39.94mA    23.39mA    57.28mA
[Pullup]
|Voltage   I(typ)   I(min)   I(max)
-2.75V    500uA      430uA      550uA
-1.16V    2.96mA     1.644mA    4.352mA
-980mV    7.238mA    2.732mA    15.03mA
-890mV    14.62mA    4.003mA    33.68mA
-800mV    27.04mA    6.569mA    40.94mA
-710mV    30.75mA    11.72mA    39.99mA
-530mV    24.8mA     16.78mA    32.68mA
550mV     -20.93mA   -13.43mA   -29.03mA
1V        -32.99mA   -20.85mA   -46.23mA
1.54V     -41.51mA   -25.43mA   -59.39mA
2.62V     -46.1mA    -27.36mA   -67.77mA
5.5V      -49.87mA   -29.56mA   -73.27mA
[GND_clamp]
|Voltage   I(typ)   I(min)   I(max)
-2.75V    -7.488A    -7.708A    -7.379A
-1.22V    -1.193A    -1.537A    -1.012A
-1.13V    -835.6mA   -1.18A     -654.7mA
-1.04V    -497.8mA   -833mA     -328mA
-950mV    -208.9mA   -508.7mA   -87.54mA
-860mV    -39.89mA   -232.5mA   -15.89mA
-770mV    -7.264mA   -56.44mA   -8.363mA
-680mV    -3.422mA   -7.048mA   -4.851mA
-590mV    -1.552mA   -1.455mA   -2.251mA
-500mV    -482.7uA   -438.2uA   -698.4uA
5.5V      0A         0A         0A
[POWER_clamp]
|Voltage   I(typ)   I(min)   I(max)
-2.75V    2.386A     2.288A     2.687A
-1.16V    368.2mA    410.8mA    372.9mA
-1.07V    258.5mA    311.8mA    242.5mA
-980mV    153.1mA    216.2mA    121.1mA
-890mV    64.5mA     128mA      36.56mA
-800mV    18.16mA    59.6mA     13.82mA
-710mV    5.012mA    22.76mA    6.935mA
-620mV    1.706mA    5.315mA    2.959mA
-530mV    383.1uA    636.8uA    795.1uA
-440mV    42.36uA    66.97uA    84.45uA
5.5V      0A         0A         0A
[Ramp]
| variable   typ   min   max
dV/dt_r  0.9057/0.7389n   0.6352/1.5123n   1.1389/0.4340n
dV/dt_f  0.7845/0.8327n   0.4686/1.4815n   1.0662/0.4903n
R_load = 46.0000
[Rising Waveform]
R_fixture= 46.0000
V_fixture= 0.0
V_fixture_min= 0.0
V_fixture_max= 0.0
|time   V(typ)   V(min)   V(max)
0s        789.8pV    3.083nV    2.494nV
932.4ps   -4.748mV   148.7uV    37.31mV
1.042ns   -6.49mV    -220.5uV   206.2mV
1.279ns   1.464mV    -1.412mV   1.008V
1.485ns   130.8mV    -2.901mV   1.453V
2.143ns   1.054V     237.7uV    1.834V
2.94ns    1.414V     320.1mV    1.891V
3.861ns   1.491V     735mV      1.898V
4.758ns   1.506V     933.8mV    1.898V
10.12ns   1.51V      1.059V     1.898V
[Rising Waveform]
R_fixture= 46.0000
V_fixture= 2.5000
V_fixture_min= 2.2500
V_fixture_max= 2.7500
|time   V(typ)   V(min)   V(max)
0s        1.192V     1.468V     973mV
456.3ps   1.167V     1.469V     955.3mV
660.5ps   1.16V      1.449V     1.099V
813.1ps   1.214V     1.435V     1.501V
1.057ns   1.511V     1.428V     2.57V
1.188ns   1.778V     1.44V      2.729V
1.45ns    2.354V     1.517V     2.74V
1.654ns   2.484V     1.634V     2.743V
2.607ns   2.496V     2.235V     2.749V
10.12ns   2.5V       2.25V      2.75V
[Falling Waveform]
R_fixture= 46.0000
V_fixture= 0.0
V_fixture_min= 0.0
V_fixture_max= 0.0
|time   V(typ)   V(min)   V(max)
0s        1.51V      1.059V     1.898V
891.5ps   1.512V     1.06V      1.826V
1.025ns   1.516V     1.06V      1.42V
1.209ns   1.509V     1.06V      220.4mV
1.347ns   1.421V     1.06V      11.76mV
1.745ns   181mV      1.065V     2.415mV
1.898ns   15.84mV    1.07V      1.737mV
2.386ns   2.528mV    958.3mV    609.4uV
3.138ns   781.9uV    15.97mV    121.7uV
10.12ns   -458.6nV   5.063uV    38.87nV
[Falling Waveform]
R_fixture= 46.0000
V_fixture= 2.5000
V_fixture_min= 2.2500
V_fixture_max= 2.7500
|time   V(typ)   V(min)   V(max)
0s        2.5V       2.25V      2.75V
1.014ns   2.499V     2.25V      2.744V
1.171ns   2.502V     2.25V      2.525V
1.394ns   2.518V     2.25V      1.841V
1.622ns   2.461V     2.25V      1.433V
1.94ns    2.064V     2.25V      1.163V
2.337ns   1.649V     2.258V     1.042V
3.259ns   1.288V     2.06V      981.5mV
5.109ns   1.198V     1.569V     973.1mV
10.12ns   1.192V     1.469V     973mV
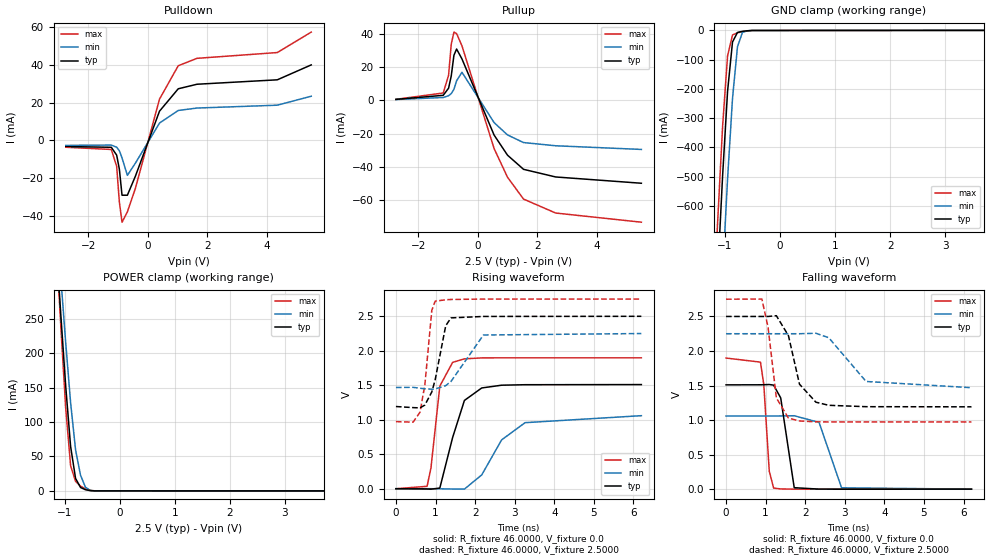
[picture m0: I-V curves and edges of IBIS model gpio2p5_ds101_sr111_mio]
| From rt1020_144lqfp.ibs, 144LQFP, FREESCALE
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[Model] gpio2p5_ds101_sr111_mio
|   Model gpio2p5_ds101_sr111_mio
| This model was characterised for following simulation conditions:
| External (pad) voltage:
|   - Typ: 2.5V,   - Min: 2.25V,   - Max: 2.75V
| Library cells for typ/min/max conditions are connected as defined below:
|  pad - External Pad
|  ipp_do - Core Input
|  ipp_obe - Output Buffer Enable
|  esd_boost - ovdd
|  ipp_dse0 - vddi
|  ipp_dse1 - vssi
|  ipp_dse2 - vddi
|  ipp_fsel0 - vddi
|  ipp_fsel1 - vddi
|  ipp_ina - ipp_ina
|  ipp_ind - ipp_ind
|  ipp_pwr_stable - vddi
|  ipp_sre - vddi
|  ovdd - ovdd
|  ovss - ovss
|  vddi - vddi
|  vssi - vssi
| All other pins connected to ground
Model_type I/O
Polarity   Non-Inverting
Enable   Active-High
Vinl =   0.7500V
Vinh =   1.7500V
Vmeas =  1.2500V
Cref =   0.0F
Rref =   46.0000
Vref =   1.2500V
C_comp   1.2356pF   1.1994pF   1.2834pF
|C_comp_pullup   0.6222pF   0.6389pF   0.6073pF
|C_comp_pulldown   0.5474pF   0.5788pF   0.5258pF
[Model Spec]
| variable   typ   min   max
Vinh   1.7500V   1.5750V   1.9250V
Vinl   0.7500V   0.6750V   0.8250V
S_overshoot_high   2.5000V   2.2500V   2.7500V
S_overshoot_low   0.0V   0.0V   0.0V
Vmeas   1.2500V   1.1250V   1.3750V
Vref   1.2500V   1.1250V   1.3750V
Cref   0.0F   0.0F   0.0F
Rref   46.0000   46.0000   46.0000
[Temperature Range]   25.0000   0.1050k   -20.0000
[Voltage Range]   2.5000V   2.2500V   2.7500V
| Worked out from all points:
|   slope of the pulldown table from 0 to 0.375 V, typ, clamps not added: 25.5 ohm
|   slope of the pullup table from 0 to 0.375 V, typ, clamps not added: 25 ohm
|   GND clamp passes 1 mA (typ) near -0.54 V on its own axis
|   POWER clamp passes 1 mA (typ) near -0.57 V on its own axis
|   rising waveform, R_fixture 46.0000, V_fixture 0.0: 20-80 % time 366ps typ, 730ps min, 220ps max; typ from 0 V to 1.51 V
|   rising waveform, R_fixture 46.0000, V_fixture 2.5000: 20-80 % time 278ps typ, 471ps min, 180ps max; typ from 1.19 V to 2.5 V
|   falling waveform, R_fixture 46.0000, V_fixture 0.0: 20-80 % time 166ps typ, 273ps min, 121ps max; typ from 1.51 V to 0 V
|   falling waveform, R_fixture 46.0000, V_fixture 2.5000: 20-80 % time 338ps typ, 577ps min, 220ps max; typ from 2.5 V to 1.19 V
[Pulldown]
|Voltage   I(typ)   I(min)   I(max)
-2.75V    -3.197mA   -2.582mA   -3.573mA
-1.22V    -3.596mA   -2.428mA   -4.755mA
-1.04V    -7.744mA   -3.566mA   -13.69mA
-950mV    -15.11mA   -5.401mA   -32.48mA
-860mV    -28.93mA   -9.221mA   -43.18mA
-680mV    -28.92mA   -18.42mA   -37.72mA
-410mV    -18.84mA   -11.96mA   -25.27mA
400mV     15.49mA    9.203mA    21.85mA
1.03V     27.32mA    15.86mA    39.51mA
1.66V     29.72mA    17.14mA    43.41mA
4.36V     32.06mA    18.65mA    46.47mA
5.5V      39.94mA    23.39mA    57.28mA
[Pullup]
|Voltage   I(typ)   I(min)   I(max)
-2.75V    500uA      430uA      550uA
-1.16V    2.96mA     1.644mA    4.352mA
-980mV    7.238mA    2.732mA    15.03mA
-890mV    14.62mA    4.003mA    33.68mA
-800mV    27.04mA    6.569mA    40.94mA
-710mV    30.75mA    11.72mA    39.99mA
-530mV    24.8mA     16.78mA    32.68mA
550mV     -20.93mA   -13.43mA   -29.03mA
1V        -32.99mA   -20.85mA   -46.23mA
1.54V     -41.51mA   -25.43mA   -59.39mA
2.62V     -46.1mA    -27.36mA   -67.77mA
5.5V      -49.87mA   -29.56mA   -73.27mA
[GND_clamp]
|Voltage   I(typ)   I(min)   I(max)
-2.75V    -7.488A    -7.708A    -7.379A
-1.22V    -1.193A    -1.537A    -1.012A
-1.13V    -835.6mA   -1.18A     -654.7mA
-1.04V    -497.8mA   -833mA     -328mA
-950mV    -208.9mA   -508.7mA   -87.54mA
-860mV    -39.89mA   -232.5mA   -15.89mA
-770mV    -7.264mA   -56.44mA   -8.363mA
-680mV    -3.422mA   -7.048mA   -4.851mA
-590mV    -1.552mA   -1.455mA   -2.251mA
-500mV    -482.7uA   -438.2uA   -698.4uA
5.5V      0A         0A         0A
[POWER_clamp]
|Voltage   I(typ)   I(min)   I(max)
-2.75V    2.386A     2.288A     2.687A
-1.16V    368.2mA    410.8mA    372.9mA
-1.07V    258.5mA    311.8mA    242.5mA
-980mV    153.1mA    216.2mA    121.1mA
-890mV    64.5mA     128mA      36.56mA
-800mV    18.16mA    59.6mA     13.82mA
-710mV    5.012mA    22.76mA    6.935mA
-620mV    1.706mA    5.315mA    2.959mA
-530mV    383.1uA    636.8uA    795.1uA
-440mV    42.36uA    66.97uA    84.45uA
5.5V      0A         0A         0A
[Ramp]
| variable   typ   min   max
dV/dt_r  0.9057/0.3659n   0.6354/0.7303n   1.1389/0.2204n
dV/dt_f  0.7845/0.3381n   0.4688/0.5766n   1.0662/0.2201n
R_load = 46.0000
[Rising Waveform]
R_fixture= 46.0000
V_fixture= 0.0
V_fixture_min= 0.0
V_fixture_max= 0.0
|time   V(typ)   V(min)   V(max)
0s        789.8pV    3.083nV    2.494nV
787.1ps   -3.872mV   228.1uV    34.78mV
885.1ps   -6.544mV   17.01uV    301.1mV
1.109ns   9.985mV    -1.065mV   1.488V
1.432ns   741.8mV    -4.201mV   1.832V
1.73ns    1.28V      -5.98mV    1.883V
2.168ns   1.461V     200.6mV    1.897V
2.67ns    1.501V     708.1mV    1.898V
3.262ns   1.508V     957.6mV    1.898V
6.2ns     1.51V      1.059V     1.898V
[Rising Waveform]
R_fixture= 46.0000
V_fixture= 2.5000
V_fixture_min= 2.2500
V_fixture_max= 2.7500
|time   V(typ)   V(min)   V(max)
0s        1.192V     1.468V     973mV
432.8ps   1.176V     1.47V      964.9mV
607.7ps   1.172V     1.457V     1.109V
730.6ps   1.213V     1.449V     1.502V
906.4ps   1.403V     1.443V     2.587V
991.4ps   1.579V     1.446V     2.719V
1.258ns   2.363V     1.495V     2.74V
1.391ns   2.477V     1.555V     2.744V
2.21ns    2.498V     2.229V     2.75V
6.2ns     2.5V       2.25V      2.75V
[Falling Waveform]
R_fixture= 46.0000
V_fixture= 0.0
V_fixture_min= 0.0
V_fixture_max= 0.0
|time   V(typ)   V(min)   V(max)
0s        1.51V      1.059V     1.898V
870ps     1.511V     1.059V     1.839V
953.8ps   1.512V     1.059V     1.513V
1.092ns   1.515V     1.059V     258.7mV
1.202ns   1.506V     1.059V     15.97mV
1.381ns   1.321V     1.06V      3.325mV
1.722ns   21.47mV    1.063V     603.4uV
2.35ns    774.4uV    966.2mV    89.08uV
2.918ns   151.1uV    19.72mV    35.36uV
6.2ns     272.6nV    15.93uV    -832.1nV
[Falling Waveform]
R_fixture= 46.0000
V_fixture= 2.5000
V_fixture_min= 2.2500
V_fixture_max= 2.7500
|time   V(typ)   V(min)   V(max)
0s        2.5V       2.25V      2.75V
905.1ps   2.5V       2.25V      2.752V
1.062ns   2.5V       2.25V      2.342V
1.271ns   2.511V     2.25V      1.321V
1.576ns   2.223V     2.25V      1.029V
1.855ns   1.52V      2.25V      987.1mV
2.27ns    1.259V     2.257V     975.1mV
2.595ns   1.214V     2.192V     973.5mV
3.537ns   1.194V     1.559V     973mV
6.2ns     1.192V     1.469V     973mV
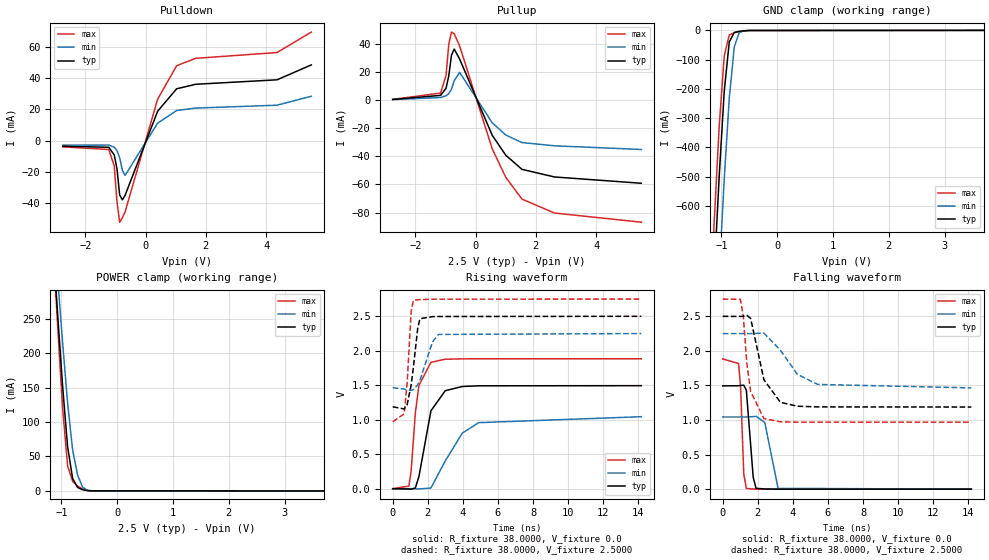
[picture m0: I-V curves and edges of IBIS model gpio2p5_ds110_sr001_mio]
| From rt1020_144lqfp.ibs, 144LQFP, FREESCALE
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[Model] gpio2p5_ds110_sr001_mio
|   Model gpio2p5_ds110_sr001_mio
| This model was characterised for following simulation conditions:
| External (pad) voltage:
|   - Typ: 2.5V,   - Min: 2.25V,   - Max: 2.75V
| Library cells for typ/min/max conditions are connected as defined below:
|  pad - External Pad
|  ipp_do - Core Input
|  ipp_obe - Output Buffer Enable
|  esd_boost - ovdd
|  ipp_dse0 - vssi
|  ipp_dse1 - vddi
|  ipp_dse2 - vddi
|  ipp_fsel0 - vddi
|  ipp_fsel1 - vssi
|  ipp_ina - ipp_ina
|  ipp_ind - ipp_ind
|  ipp_pwr_stable - vddi
|  ipp_sre - vssi
|  ovdd - ovdd
|  ovss - ovss
|  vddi - vddi
|  vssi - vssi
| All other pins connected to ground
Model_type I/O
Polarity   Non-Inverting
Enable   Active-High
Vinl =   0.7500V
Vinh =   1.7500V
Vmeas =  1.2500V
Cref =   0.0F
Rref =   38.0000
Vref =   1.2500V
C_comp   1.2356pF   1.1994pF   1.2834pF
|C_comp_pullup   0.6221pF   0.6388pF   0.6072pF
|C_comp_pulldown   0.5474pF   0.5787pF   0.5258pF
[Model Spec]
| variable   typ   min   max
Vinh   1.7500V   1.5750V   1.9250V
Vinl   0.7500V   0.6750V   0.8250V
S_overshoot_high   2.5000V   2.2500V   2.7500V
S_overshoot_low   0.0V   0.0V   0.0V
Vmeas   1.2500V   1.1250V   1.3750V
Vref   1.2500V   1.1250V   1.3750V
Cref   0.0F   0.0F   0.0F
Rref   38.0000   38.0000   38.0000
[Temperature Range]   25.0000   0.1050k   -20.0000
[Voltage Range]   2.5000V   2.2500V   2.7500V
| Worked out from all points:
|   slope of the pulldown table from 0 to 0.375 V, typ, clamps not added: 21 ohm
|   slope of the pullup table from 0 to 0.375 V, typ, clamps not added: 21.1 ohm
|   GND clamp passes 1 mA (typ) near -0.54 V on its own axis
|   POWER clamp passes 1 mA (typ) near -0.57 V on its own axis
|   rising waveform, R_fixture 38.0000, V_fixture 0.0: 20-80 % time 704ps typ, 1.42ns min, 416ps max; typ from 0 V to 1.49 V
|   rising waveform, R_fixture 38.0000, V_fixture 2.5000: 20-80 % time 359ps typ, 588ps min, 244ps max; typ from 1.19 V to 2.5 V
|   falling waveform, R_fixture 38.0000, V_fixture 0.0: 20-80 % time 221ps typ, 346ps min, 158ps max; typ from 1.49 V to 0 V
|   falling waveform, R_fixture 38.0000, V_fixture 2.5000: 20-80 % time 756ps typ, 1.31ns min, 451ps max; typ from 2.5 V to 1.19 V
[Pulldown]
|Voltage   I(typ)   I(min)   I(max)
-2.75V    -3.628mA   -2.927mA   -4.055mA
-1.22V    -4.29mA    -2.837mA   -5.71mA
-1.04V    -9.229mA   -4.254mA   -16.33mA
-950mV    -18mA      -6.412mA   -39.1mA
-860mV    -34.94mA   -10.95mA   -52.37mA
-770mV    -38.02mA   -19.05mA   -49.48mA
-680mV    -35.11mA   -22.35mA   -45.77mA
400mV     18.83mA    11.19mA    26.54mA
1.03V     33.21mA    19.29mA    48.01mA
1.66V     36.13mA    20.85mA    52.77mA
4.36V     38.98mA    22.69mA    56.49mA
5.5V      48.55mA    28.45mA    69.61mA
[Pullup]
|Voltage   I(typ)   I(min)   I(max)
-2.75V    590uA      510uA      650uA
-1.16V    3.505mA    1.949mA    5.151mA
-980mV    8.563mA    3.24mA     17.77mA
-890mV    17.3mA     4.747mA    39.95mA
-800mV    32.11mA    7.79mA     48.61mA
-710mV    36.51mA    13.91mA    47.46mA
-530mV    29.43mA    19.92mA    38.77mA
550mV     -24.83mA   -15.93mA   -34.44mA
1V        -39.13mA   -24.74mA   -54.84mA
1.54V     -49.23mA   -30.16mA   -70.43mA
2.62V     -54.66mA   -32.45mA   -80.37mA
5.5V      -59.14mA   -35.06mA   -86.89mA
[GND_clamp]
|Voltage   I(typ)   I(min)   I(max)
-2.75V    -7.488A    -7.708A    -7.379A
-1.22V    -1.193A    -1.537A    -1.012A
-1.13V    -835.6mA   -1.18A     -654.7mA
-1.04V    -497.8mA   -833mA     -328mA
-950mV    -208.9mA   -508.7mA   -87.54mA
-860mV    -39.89mA   -232.5mA   -15.89mA
-770mV    -7.264mA   -56.44mA   -8.363mA
-680mV    -3.422mA   -7.048mA   -4.851mA
-590mV    -1.552mA   -1.455mA   -2.251mA
-500mV    -482.7uA   -438.2uA   -698.4uA
5.5V      0A         0A         0A
[POWER_clamp]
|Voltage   I(typ)   I(min)   I(max)
-2.75V    2.386A     2.288A     2.687A
-1.16V    368.2mA    410.8mA    372.9mA
-1.07V    258.5mA    311.8mA    242.5mA
-980mV    153.1mA    216.2mA    121.1mA
-890mV    64.5mA     128mA      36.56mA
-800mV    18.16mA    59.6mA     13.82mA
-710mV    5.012mA    22.76mA    6.935mA
-620mV    1.706mA    5.315mA    2.959mA
-530mV    383.1uA    636.8uA    795.1uA
-440mV    42.36uA    66.97uA    84.45uA
5.5V      0A         0A         0A
[Ramp]
| variable   typ   min   max
dV/dt_r  0.8966/0.7043n   0.6266/1.4161n   1.1302/0.4158n
dV/dt_f  0.7872/0.7559n   0.4709/1.3120n   1.0685/0.4510n
R_load = 38.0000
[Rising Waveform]
R_fixture= 38.0000
V_fixture= 0.0
V_fixture_min= 0.0
V_fixture_max= 0.0
|time   V(typ)   V(min)   V(max)
0s        651pV      2.522nV    2.056nV
922.2ps   -4.634mV   148.3uV    38.08mV
1.052ns   -6.803mV   -303.1uV   261.8mV
1.291ns   11.58mV    -1.552mV   1.098V
1.495ns   176.2mV    -3.092mV   1.499V
2.179ns   1.129V     9.487mV    1.833V
2.992ns   1.421V     401.7mV    1.878V
3.966ns   1.482V     805mV      1.883V
4.89ns    1.492V     957.6mV    1.884V
14.17ns   1.494V     1.044V     1.884V
[Rising Waveform]
R_fixture= 38.0000
V_fixture= 2.5000
V_fixture_min= 2.2500
V_fixture_max= 2.7500
|time   V(typ)   V(min)   V(max)
0s        1.188V     1.465V     969.2mV
656ps     1.156V     1.445V     1.087V
823.5ps   1.219V     1.431V     1.535V
1.055ns   1.508V     1.426V     2.58V
1.185ns   1.775V     1.439V     2.731V
1.426ns   2.328V     1.508V     2.74V
1.552ns   2.465V     1.572V     2.742V
2.266ns   2.495V     2.127V     2.748V
2.605ns   2.497V     2.237V     2.749V
14.17ns   2.5V       2.25V      2.75V
[Falling Waveform]
R_fixture= 38.0000
V_fixture= 0.0
V_fixture_min= 0.0
V_fixture_max= 0.0
|time   V(typ)   V(min)   V(max)
0s        1.494V     1.044V     1.884V
904.4ps   1.496V     1.044V     1.818V
1.019ns   1.5V       1.044V     1.48V
1.2ns     1.504V     1.044V     220.6mV
1.347ns   1.433V     1.044V     10.39mV
1.739ns   169.4mV    1.049V     2.345mV
1.902ns   12.44mV    1.054V     1.62mV
2.397ns   2.389mV    966.2mV    515.5uV
3.154ns   678.5uV    11.73mV    87.04uV
14.17ns   11.97nV    20.36nV    8.23nV
[Falling Waveform]
R_fixture= 38.0000
V_fixture= 2.5000
V_fixture_min= 2.2500
V_fixture_max= 2.7500
|time   V(typ)   V(min)   V(max)
0s        2.5V       2.25V      2.75V
1.006ns   2.499V     2.25V      2.746V
1.172ns   2.501V     2.25V      2.506V
1.374ns   2.516V     2.25V      1.823V
1.592ns   2.471V     2.25V      1.413V
2.35ns    1.582V     2.258V     1.021V
3.29ns    1.256V     2.009V     974.3mV
4.259ns   1.2V       1.661V     969.6mV
5.418ns   1.19V      1.515V     969.2mV
14.17ns   1.188V     1.465V     969.2mV
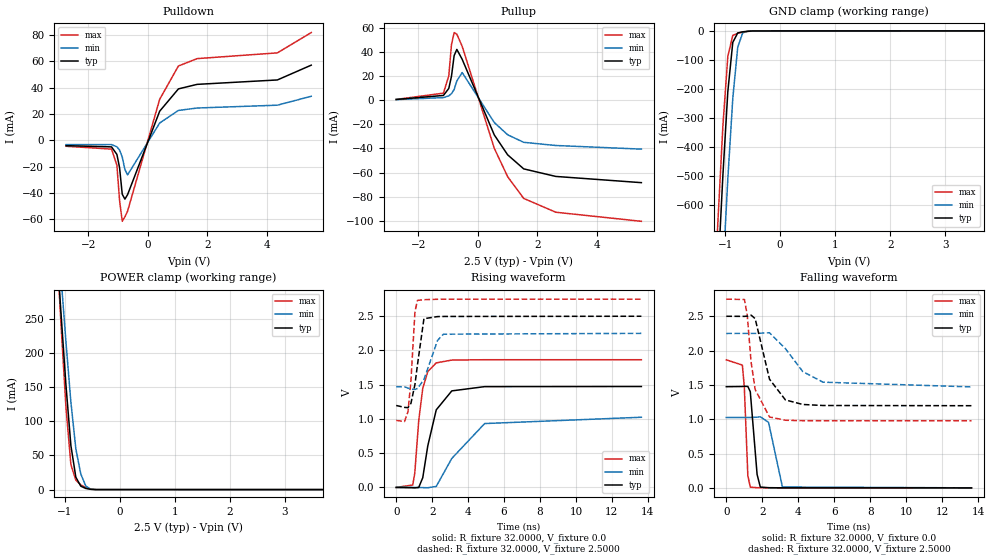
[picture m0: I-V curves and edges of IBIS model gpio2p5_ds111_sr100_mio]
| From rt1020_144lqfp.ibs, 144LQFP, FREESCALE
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[Model] gpio2p5_ds111_sr100_mio
|   Model gpio2p5_ds111_sr100_mio
| This model was characterised for following simulation conditions:
| External (pad) voltage:
|   - Typ: 2.5V,   - Min: 2.25V,   - Max: 2.75V
| Library cells for typ/min/max conditions are connected as defined below:
|  pad - External Pad
|  ipp_do - Core Input
|  ipp_obe - Output Buffer Enable
|  esd_boost - ovdd
|  ipp_dse0 - vddi
|  ipp_dse1 - vddi
|  ipp_dse2 - vddi
|  ipp_fsel0 - vssi
|  ipp_fsel1 - vssi
|  ipp_ina - ipp_ina
|  ipp_ind - ipp_ind
|  ipp_pwr_stable - vddi
|  ipp_sre - vddi
|  ovdd - ovdd
|  ovss - ovss
|  vddi - vddi
|  vssi - vssi
| All other pins connected to ground
Model_type I/O
Polarity   Non-Inverting
Enable   Active-High
Vinl =   0.7500V
Vinh =   1.7500V
Vmeas =  1.2500V
Cref =   0.0F
Rref =   32.0000
Vref =   1.2500V
C_comp   1.2356pF   1.1994pF   1.2834pF
|C_comp_pullup   0.6221pF   0.6388pF   0.6072pF
|C_comp_pulldown   0.5474pF   0.5787pF   0.5258pF
[Model Spec]
| variable   typ   min   max
Vinh   1.7500V   1.5750V   1.9250V
Vinl   0.7500V   0.6750V   0.8250V
S_overshoot_high   2.5000V   2.2500V   2.7500V
S_overshoot_low   0.0V   0.0V   0.0V
Vmeas   1.2500V   1.1250V   1.3750V
Vref   1.2500V   1.1250V   1.3750V
Cref   0.0F   0.0F   0.0F
Rref   32.0000   32.0000   32.0000
[Temperature Range]   25.0000   0.1050k   -20.0000
[Voltage Range]   2.5000V   2.2500V   2.7500V
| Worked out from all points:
|   slope of the pulldown table from 0 to 0.375 V, typ, clamps not added: 17.8 ohm
|   slope of the pullup table from 0 to 0.375 V, typ, clamps not added: 18.2 ohm
|   GND clamp passes 1 mA (typ) near -0.54 V on its own axis
|   POWER clamp passes 1 mA (typ) near -0.57 V on its own axis
|   rising waveform, R_fixture 32.0000, V_fixture 0.0: 20-80 % time 724ps typ, 1.47ns min, 425ps max; typ from 0 V to 1.47 V
|   rising waveform, R_fixture 32.0000, V_fixture 2.5000: 20-80 % time 359ps typ, 592ps min, 245ps max; typ from 1.2 V to 2.5 V
|   falling waveform, R_fixture 32.0000, V_fixture 0.0: 20-80 % time 229ps typ, 356ps min, 162ps max; typ from 1.47 V to 0 V
|   falling waveform, R_fixture 32.0000, V_fixture 2.5000: 20-80 % time 816ps typ, 1.44ns min, 483ps max; typ from 2.5 V to 1.2 V
[Pulldown]
|Voltage   I(typ)   I(min)   I(max)
-2.75V    -4.064mA   -3.276mA   -4.543mA
-1.22V    -4.986mA   -3.248mA   -6.666mA
-1.04V    -10.72mA   -4.943mA   -18.99mA
-950mV    -20.89mA   -7.426mA   -45.78mA
-860mV    -40.97mA   -12.69mA   -61.57mA
-770mV    -44.71mA   -22.26mA   -58.18mA
-680mV    -41.29mA   -26.27mA   -53.82mA
400mV     22.16mA    13.17mA    31.22mA
1.03V     39.1mA     22.72mA    56.51mA
1.66V     42.55mA    24.56mA    62.12mA
4.36V     45.9mA     26.72mA    66.5mA
5.5V      57.16mA    33.5mA     81.93mA
[Pullup]
|Voltage   I(typ)   I(min)   I(max)
-2.75V    690uA      590uA      750uA
-1.16V    4.049mA    2.254mA    5.949mA
-980mV    9.885mA    3.746mA    20.5mA
-890mV    19.98mA    5.49mA     46.24mA
-800mV    37.18mA    9.012mA    56.27mA
-710mV    42.27mA    16.11mA    54.94mA
-530mV    34.07mA    23.06mA    44.87mA
550mV     -28.73mA   -18.44mA   -39.84mA
1V        -45.28mA   -28.62mA   -63.44mA
1.54V     -56.95mA   -34.89mA   -81.48mA
2.62V     -63.23mA   -37.53mA   -92.97mA
5.5V      -68.4mA    -40.55mA   -100.5mA
[GND_clamp]
|Voltage   I(typ)   I(min)   I(max)
-2.75V    -7.488A    -7.708A    -7.379A
-1.22V    -1.193A    -1.537A    -1.012A
-1.13V    -835.6mA   -1.18A     -654.7mA
-1.04V    -497.8mA   -833mA     -328mA
-950mV    -208.9mA   -508.7mA   -87.54mA
-860mV    -39.89mA   -232.5mA   -15.89mA
-770mV    -7.264mA   -56.44mA   -8.363mA
-680mV    -3.422mA   -7.048mA   -4.851mA
-590mV    -1.552mA   -1.455mA   -2.251mA
-500mV    -482.7uA   -438.2uA   -698.4uA
5.5V      0A         0A         0A
[POWER_clamp]
|Voltage   I(typ)   I(min)   I(max)
-2.75V    2.386A     2.288A     2.687A
-1.16V    368.2mA    410.8mA    372.9mA
-1.07V    258.5mA    311.8mA    242.5mA
-980mV    153.1mA    216.2mA    121.1mA
-890mV    64.5mA     128mA      36.56mA
-800mV    18.16mA    59.6mA     13.82mA
-710mV    5.012mA    22.76mA    6.935mA
-620mV    1.706mA    5.315mA    2.959mA
-530mV    383.1uA    636.8uA    795.1uA
-440mV    42.36uA    66.97uA    84.45uA
5.5V      0A         0A         0A
[Ramp]
| variable   typ   min   max
dV/dt_r  0.8847/0.7238n   0.6151/1.4724n   1.1188/0.4246n
dV/dt_f  0.7818/0.8160n   0.4671/1.4434n   1.0631/0.4825n
R_load = 32.0000
[Rising Waveform]
R_fixture= 32.0000
V_fixture= 0.0
V_fixture_min= 0.0
V_fixture_max= 0.0
|time   V(typ)   V(min)   V(max)
0s        552pV      2.135nV    1.744nV
920.4ps   -4.562mV   155.4uV    35.63mV
1.032ns   -6.329mV   -216.5uV   204.9mV
1.253ns   -64.87uV   -1.285mV   976.8mV
1.477ns   141.7mV    -2.876mV   1.447V
1.757ns   607.1mV    -4.737mV   1.692V
2.228ns   1.133V     15.03mV    1.819V
3.093ns   1.41V      423.4mV    1.86V
4.921ns   1.472V     932.7mV    1.865V
13.64ns   1.474V     1.025V     1.865V
[Rising Waveform]
R_fixture= 32.0000
V_fixture= 2.5000
V_fixture_min= 2.2500
V_fixture_max= 2.7500
|time   V(typ)   V(min)   V(max)
0s        1.197V     1.471V     978.2mV
461.9ps   1.169V     1.47V      962.6mV
655.2ps   1.165V     1.451V     1.105V
819ps     1.227V     1.437V     1.556V
1.043ns   1.505V     1.431V     2.566V
1.183ns   1.791V     1.445V     2.732V
1.542ns   2.464V     1.574V     2.742V
2.299ns   2.495V     2.147V     2.748V
2.626ns   2.497V     2.238V     2.749V
13.64ns   2.5V       2.25V      2.75V
[Falling Waveform]
R_fixture= 32.0000
V_fixture= 0.0
V_fixture_min= 0.0
V_fixture_max= 0.0
|time   V(typ)   V(min)   V(max)
0s        1.474V     1.025V     1.865V
891.6ps   1.477V     1.025V     1.789V
999.3ps   1.48V      1.025V     1.475V
1.197ns   1.478V     1.025V     179.9mV
1.333ns   1.4V       1.026V     10.43mV
1.712ns   194.6mV    1.03V      2.465mV
1.891ns   11.64mV    1.036V     1.665mV
2.35ns    2.556mV    954.1mV    613.1uV
3.121ns   758.7uV    12.54mV    107.2uV
13.64ns   16.63nV    82.93nV    8.151nV
[Falling Waveform]
R_fixture= 32.0000
V_fixture= 2.5000
V_fixture_min= 2.2500
V_fixture_max= 2.7500
|time   V(typ)   V(min)   V(max)
0s        2.5V       2.25V      2.75V
1.009ns   2.499V     2.25V      2.744V
1.165ns   2.502V     2.25V      2.514V
1.378ns   2.517V     2.25V      1.833V
1.605ns   2.465V     2.25V      1.433V
2.403ns   1.583V     2.26V      1.033V
3.289ns   1.281V     2.028V     985.3mV
4.254ns   1.215V     1.694V     978.9mV
5.381ns   1.2V       1.54V      978.2mV
13.64ns   1.197V     1.471V     978.2mV
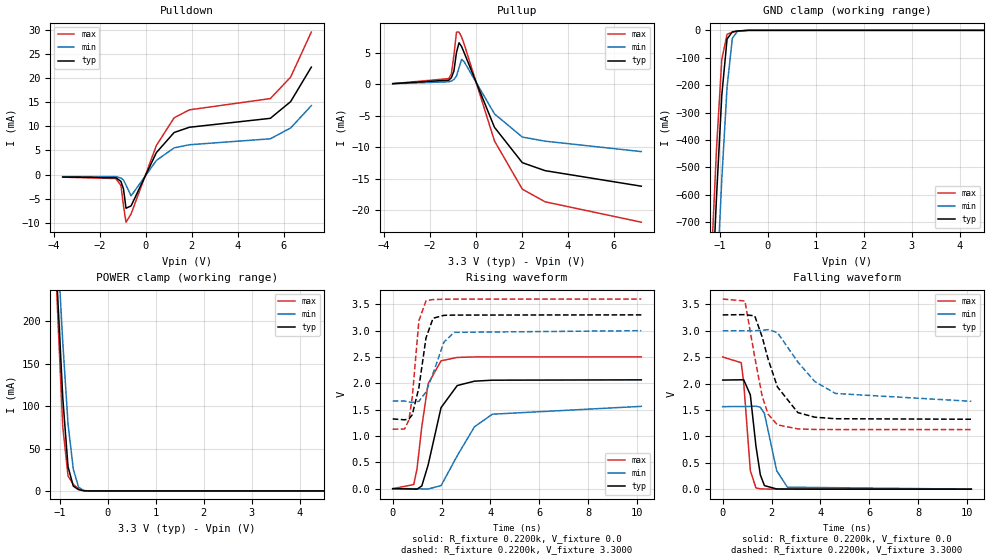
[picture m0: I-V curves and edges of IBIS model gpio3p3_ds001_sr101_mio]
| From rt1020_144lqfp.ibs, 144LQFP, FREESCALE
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[Model] gpio3p3_ds001_sr101_mio
|   Model gpio3p3_ds001_sr101_mio
| This model was characterised for following simulation conditions:
| External (pad) voltage:
|   - Typ: 3.3V,   - Min: 3.0V,   - Max: 3.6V
| Library cells for typ/min/max conditions are connected as defined below:
|  pad - External Pad
|  ipp_do - Core Input
|  ipp_obe - Output Buffer Enable
|  esd_boost - ovdd
|  ipp_dse0 - vddi
|  ipp_dse1 - vssi
|  ipp_dse2 - vssi
|  ipp_fsel0 - vddi
|  ipp_fsel1 - vssi
|  ipp_ina - ipp_ina
|  ipp_ind - ipp_ind
|  ipp_pwr_stable - vddi
|  ipp_sre - vddi
|  ovdd - ovdd
|  ovss - ovss
|  vddi - vddi
|  vssi - vssi
| All other pins connected to ground
Model_type I/O
Polarity   Non-Inverting
Enable   Active-High
Vinl =   0.9900V
Vinh =   2.3100V
Vmeas =  1.6500V
Cref =   0.0F
Rref =   0.2200k
Vref =   1.6500V
C_comp   1.2178pF   1.1833pF   1.2636pF
|C_comp_pullup   0.6042pF   0.6189pF   0.5908pF
|C_comp_pulldown   0.5474pF   0.5788pF   0.5258pF
[Model Spec]
| variable   typ   min   max
Vinh   2.3100V   2.1000V   2.5200V
Vinl   0.9900V   0.9000V   1.0800V
S_overshoot_high   3.3000V   3.0000V   3.6000V
S_overshoot_low   0.0V   0.0V   0.0V
Vmeas   1.6500V   1.5000V   1.8000V
Vref   1.6500V   1.5000V   1.8000V
Cref   0.0F   0.0F   0.0F
Rref   0.2200k   0.2200k   0.2200k
[Temperature Range]   25.0000   0.1050k   -20.0000
[Voltage Range]   3.3000V   3.0000V   3.6000V
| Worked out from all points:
|   slope of the pulldown table from 0 to 0.495 V, typ, clamps not added: 104 ohm
|   slope of the pullup table from 0 to 0.495 V, typ, clamps not added: 112 ohm
|   GND clamp passes 1 mA (typ) near -0.54 V on its own axis
|   POWER clamp passes 1 mA (typ) near -0.57 V on its own axis
|   rising waveform, R_fixture 0.2200k, V_fixture 0.0: 20-80 % time 640ps typ, 1.18ns min, 426ps max; typ from 0 V to 2.07 V
|   rising waveform, R_fixture 0.2200k, V_fixture 3.3000: 20-80 % time 385ps typ, 592ps min, 275ps max; typ from 1.32 V to 3.3 V
|   falling waveform, R_fixture 0.2200k, V_fixture 0.0: 20-80 % time 310ps typ, 419ps min, 233ps max; typ from 2.07 V to 0 V
|   falling waveform, R_fixture 0.2200k, V_fixture 3.3000: 20-80 % time 875ps typ, 1.46ns min, 582ps max; typ from 3.3 V to 1.32 V
[Pulldown]
|Voltage   I(typ)   I(min)   I(max)
-3.6V     -510uA     -430uA     -540uA
-1.29V    -647uA     -417uA     -827uA
-1.07V    -1.427mA   -731.3uA   -2.281mA
-960mV    -2.986mA   -1.137mA   -6.485mA
-850mV    -7mA       -2.186mA   -9.891mA
-630mV    -6.507mA   -4.426mA   -8.193mA
470mV     4.567mA    2.939mA    6.048mA
1.24V     8.736mA    5.546mA    11.79mA
1.9V      9.822mA    6.191mA    13.44mA
5.42V     11.68mA    7.43mA     15.78mA
6.3V      15.14mA    9.67mA     20.23mA
7.2V      22.31mA    14.31mA    29.59mA
[Pullup]
|Voltage   I(typ)   I(min)   I(max)
-3.6V     80uA       60uA       70uA
-1.16V    634uA      374uA      887uA
-1.05V    1.031mA    497uA      1.681mA
-940mV    2.112mA    740uA      4.609mA
-830mV    5.029mA    1.286mA    8.268mA
-720mV    6.574mA    2.584mA    8.272mA
-610mV    5.992mA    3.932mA    7.525mA
-500mV    5.025mA    3.584mA    6.406mA
820mV     -6.857mA   -4.721mA   -9.018mA
2.03V     -12.48mA   -8.409mA   -16.69mA
3.02V     -13.75mA   -9.063mA   -18.7mA
7.2V      -16.22mA   -10.72mA   -21.94mA
[GND_clamp]
|Voltage   I(typ)   I(min)   I(max)
-3.6V     -10.99A    -11.14A    -10.93A
-1.18V    -1.033A    -1.378A    -850.8mA
-1.07V    -607mA     -947.1mA   -431.4mA
-960mV    -236.8mA   -543mA     -106.4mA
-850mV    -31.63mA   -206.7mA   -14.18mA
-740mV    -5.424mA   -29mA      -7.092mA
-630mV    -2.275mA   -2.653mA   -3.283mA
-410mV    -62.05uA   -83.52uA   -82.05uA
7.2V      0A         0A         0A
[POWER_clamp]
|Voltage   I(typ)   I(min)   I(max)
-3.6V     3.491A     3.319A     3.949A
-1.16V    368.2mA    410.8mA    372.9mA
-1.05V    234.5mA    290.2mA    214.3mA
-940mV    110.2mA    175.6mA    75.85mA
-830mV    28.53mA    79.02mA    17.73mA
-720mV    5.671mA    25.66mA    7.515mA
-610mV    1.49mA     4.301mA    2.636mA
-500mV    198.2uA    300.8uA    424.4uA
-390mV    9.667uA    18.86uA    16.14uA
7.2V      0A         0A         0A
[Ramp]
| variable   typ   min   max
dV/dt_r  1.2397/0.6401n   0.9378/1.1760n   1.5016/0.4265n
dV/dt_f  1.1856/0.8752n   0.8015/1.4599n   1.4829/0.5817n
R_load = 0.2200k
[Rising Waveform]
R_fixture= 0.2200k
V_fixture= 0.0
V_fixture_min= 0.0
V_fixture_max= 0.0
|time   V(typ)   V(min)   V(max)
0s        16.92nV    15.3nV     179.1nV
860.6ps   -6.867mV   -208.7uV   78.47mV
993.9ps   -9.29mV    -1.259mV   372.4mV
1.191ns   51.61mV    -3.232mV   1.175V
1.45ns    449mV      -6.087mV   1.992V
1.98ns    1.539V     57.17mV    2.427V
2.642ns   1.958V     625mV      2.492V
3.348ns   2.041V     1.175V     2.501V
4.082ns   2.06V      1.414V     2.502V
10.18ns   2.066V     1.563V     2.503V
[Rising Waveform]
R_fixture= 0.2200k
V_fixture= 3.3000
V_fixture_min= 3.0000
V_fixture_max= 3.6000
|time   V(typ)   V(min)   V(max)
0s        1.324V     1.664V     1.129V
484.3ps   1.308V     1.663V     1.133V
666.1ps   1.324V     1.647V     1.305V
801.1ps   1.404V     1.635V     1.738V
1.072ns   1.919V     1.659V     3.188V
1.364ns   2.865V     1.837V     3.568V
1.653ns   3.236V     2.187V     3.591V
2.097ns   3.291V     2.783V     3.597V
2.516ns   3.296V     2.968V     3.599V
10.18ns   3.3V       3V         3.6V
[Falling Waveform]
R_fixture= 0.2200k
V_fixture= 0.0
V_fixture_min= 0.0
V_fixture_max= 0.0
|time   V(typ)   V(min)   V(max)
0s        2.066V     1.563V     2.503V
757.7ps   2.071V     1.564V     2.395V
858.2ps   2.071V     1.564V     2.027V
1.131ns   1.787V     1.567V     350.9mV
1.361ns   816mV      1.573V     23.34mV
1.542ns   268.7mV    1.55V      5.868mV
1.709ns   67.42mV    1.433V     3.676mV
2.209ns   3.835mV    351.3mV    1.514mV
2.648ns   2.047mV    37.51mV    684.9uV
10.18ns   496.3nV    2.369uV    382nV
[Falling Waveform]
R_fixture= 0.2200k
V_fixture= 3.3000
V_fixture_min= 3.0000
V_fixture_max= 3.6000
|time   V(typ)   V(min)   V(max)
0s        3.3V       3V         3.6V
908.7ps   3.305V     3V         3.564V
1.312ns   3.281V     3V         2.501V
1.619ns   2.878V     3.009V     1.753V
1.866ns   2.451V     3.021V     1.415V
2.241ns   1.936V     2.965V     1.218V
3.076ns   1.45V      2.408V     1.141V
3.769ns   1.363V     2.039V     1.131V
4.616ns   1.334V     1.812V     1.129V
10.18ns   1.324V     1.664V     1.129V
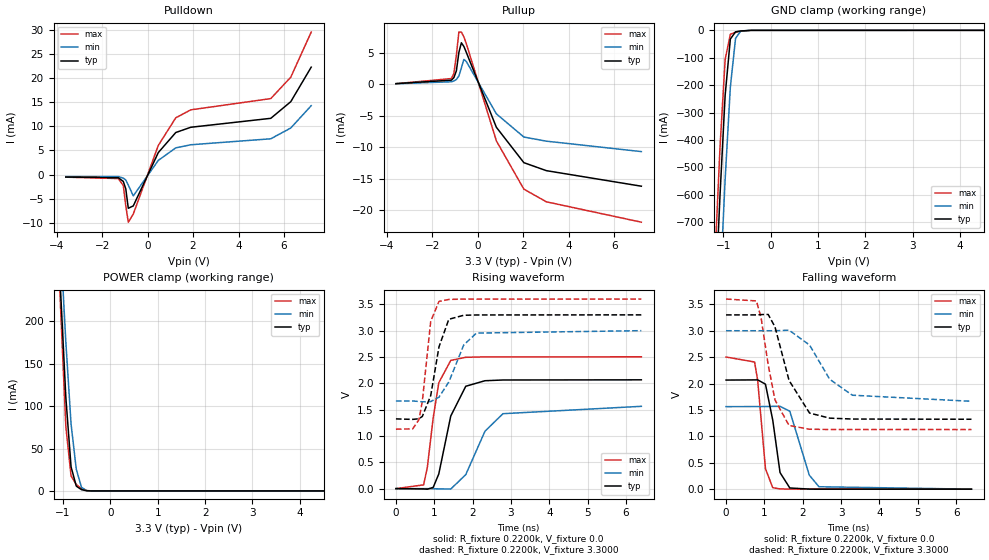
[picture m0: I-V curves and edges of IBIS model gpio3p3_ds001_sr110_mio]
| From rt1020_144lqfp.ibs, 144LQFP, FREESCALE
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[Model] gpio3p3_ds001_sr110_mio
|   Model gpio3p3_ds001_sr110_mio
| This model was characterised for following simulation conditions:
| External (pad) voltage:
|   - Typ: 3.3V,   - Min: 3.0V,   - Max: 3.6V
| Library cells for typ/min/max conditions are connected as defined below:
|  pad - External Pad
|  ipp_do - Core Input
|  ipp_obe - Output Buffer Enable
|  esd_boost - ovdd
|  ipp_dse0 - vddi
|  ipp_dse1 - vssi
|  ipp_dse2 - vssi
|  ipp_fsel0 - vssi
|  ipp_fsel1 - vddi
|  ipp_ina - ipp_ina
|  ipp_ind - ipp_ind
|  ipp_pwr_stable - vddi
|  ipp_sre - vddi
|  ovdd - ovdd
|  ovss - ovss
|  vddi - vddi
|  vssi - vssi
| All other pins connected to ground
Model_type I/O
Polarity   Non-Inverting
Enable   Active-High
Vinl =   0.9900V
Vinh =   2.3100V
Vmeas =  1.6500V
Cref =   0.0F
Rref =   0.2200k
Vref =   1.6500V
C_comp   1.2179pF   1.1833pF   1.2636pF
|C_comp_pullup   0.6043pF   0.6190pF   0.5909pF
|C_comp_pulldown   0.5474pF   0.5788pF   0.5258pF
[Model Spec]
| variable   typ   min   max
Vinh   2.3100V   2.1000V   2.5200V
Vinl   0.9900V   0.9000V   1.0800V
S_overshoot_high   3.3000V   3.0000V   3.6000V
S_overshoot_low   0.0V   0.0V   0.0V
Vmeas   1.6500V   1.5000V   1.8000V
Vref   1.6500V   1.5000V   1.8000V
Cref   0.0F   0.0F   0.0F
Rref   0.2200k   0.2200k   0.2200k
[Temperature Range]   25.0000   0.1050k   -20.0000
[Voltage Range]   3.3000V   3.0000V   3.6000V
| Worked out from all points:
|   slope of the pulldown table from 0 to 0.495 V, typ, clamps not added: 104 ohm
|   slope of the pullup table from 0 to 0.495 V, typ, clamps not added: 112 ohm
|   GND clamp passes 1 mA (typ) near -0.54 V on its own axis
|   POWER clamp passes 1 mA (typ) near -0.57 V on its own axis
|   rising waveform, R_fixture 0.2200k, V_fixture 0.0: 20-80 % time 388ps typ, 632ps min, 279ps max; typ from 0 V to 2.07 V
|   rising waveform, R_fixture 0.2200k, V_fixture 3.3000: 20-80 % time 293ps typ, 458ps min, 209ps max; typ from 1.32 V to 3.3 V
|   falling waveform, R_fixture 0.2200k, V_fixture 0.0: 20-80 % time 227ps typ, 335ps min, 175ps max; typ from 2.07 V to 0 V
|   falling waveform, R_fixture 0.2200k, V_fixture 3.3000: 20-80 % time 491ps typ, 738ps min, 354ps max; typ from 3.3 V to 1.32 V
[Pulldown]
|Voltage   I(typ)   I(min)   I(max)
-3.6V     -510uA     -430uA     -540uA
-1.29V    -647uA     -417uA     -827uA
-1.07V    -1.427mA   -731.3uA   -2.281mA
-960mV    -2.986mA   -1.137mA   -6.485mA
-850mV    -7mA       -2.186mA   -9.891mA
-630mV    -6.507mA   -4.426mA   -8.193mA
470mV     4.567mA    2.939mA    6.048mA
1.24V     8.736mA    5.546mA    11.79mA
1.9V      9.822mA    6.191mA    13.44mA
5.42V     11.68mA    7.43mA     15.78mA
6.3V      15.14mA    9.67mA     20.23mA
7.2V      22.31mA    14.31mA    29.59mA
[Pullup]
|Voltage   I(typ)   I(min)   I(max)
-3.6V     80uA       60uA       70uA
-1.16V    634uA      374uA      887uA
-1.05V    1.031mA    497uA      1.681mA
-940mV    2.112mA    740uA      4.609mA
-830mV    5.029mA    1.286mA    8.268mA
-720mV    6.574mA    2.584mA    8.272mA
-610mV    5.992mA    3.932mA    7.525mA
-500mV    5.025mA    3.584mA    6.406mA
820mV     -6.857mA   -4.721mA   -9.018mA
2.03V     -12.48mA   -8.409mA   -16.69mA
3.02V     -13.75mA   -9.063mA   -18.7mA
7.2V      -16.22mA   -10.72mA   -21.94mA
[GND_clamp]
|Voltage   I(typ)   I(min)   I(max)
-3.6V     -10.99A    -11.14A    -10.93A
-1.18V    -1.033A    -1.378A    -850.8mA
-1.07V    -607mA     -947.1mA   -431.4mA
-960mV    -236.8mA   -543mA     -106.4mA
-850mV    -31.63mA   -206.7mA   -14.18mA
-740mV    -5.424mA   -29mA      -7.092mA
-630mV    -2.275mA   -2.653mA   -3.283mA
-410mV    -62.05uA   -83.52uA   -82.04uA
7.2V      0A         0A         0A
[POWER_clamp]
|Voltage   I(typ)   I(min)   I(max)
-3.6V     3.491A     3.319A     3.949A
-1.16V    368.2mA    410.8mA    372.9mA
-1.05V    234.5mA    290.2mA    214.3mA
-940mV    110.2mA    175.6mA    75.85mA
-830mV    28.53mA    79.02mA    17.73mA
-720mV    5.671mA    25.66mA    7.515mA
-610mV    1.49mA     4.301mA    2.636mA
-500mV    198.2uA    300.8uA    424.4uA
-390mV    9.667uA    18.86uA    16.14uA
7.2V      0A         0A         0A
[Ramp]
| variable   typ   min   max
dV/dt_r  1.2397/0.3877n   0.9378/0.6316n   1.5016/0.2789n
dV/dt_f  1.1856/0.4912n   0.8016/0.7381n   1.4829/0.3544n
R_load = 0.2200k
[Rising Waveform]
R_fixture= 0.2200k
V_fixture= 0.0
V_fixture_min= 0.0
V_fixture_max= 0.0
|time   V(typ)   V(min)   V(max)
0s        16.92nV    15.3nV     179.1nV
722.4ps   -6.308mV   256.3uV    71.17mV
819.6ps   -10.38mV   -421.7uV   406.1mV
971.9ps   23.13mV    -2.057mV   1.345V
1.118ns   278.9mV    -4.189mV   2.011V
1.43ns    1.379V     -8.102mV   2.435V
1.821ns   1.944V     265.8mV    2.494V
2.322ns   2.049V     1.09V      2.502V
2.791ns   2.063V     1.423V     2.502V
6.4ns     2.066V     1.563V     2.503V
[Rising Waveform]
R_fixture= 0.2200k
V_fixture= 3.3000
V_fixture_min= 3.0000
V_fixture_max= 3.6000
|time   V(typ)   V(min)   V(max)
0s        1.324V     1.664V     1.129V
436ps     1.315V     1.665V     1.134V
600.1ps   1.327V     1.655V     1.307V
688.5ps   1.371V     1.649V     1.656V
907.3ps   1.767V     1.653V     3.179V
1.123ns   2.692V     1.737V     3.555V
1.379ns   3.216V     2.024V     3.593V
1.767ns   3.292V     2.727V     3.599V
2.099ns   3.298V     2.954V     3.599V
6.4ns     3.3V       3V         3.6V
[Falling Waveform]
R_fixture= 0.2200k
V_fixture= 0.0
V_fixture_min= 0.0
V_fixture_max= 0.0
|time   V(typ)   V(min)   V(max)
0s        2.066V     1.563V     2.503V
744.2ps   2.069V     1.564V     2.408V
825.1ps   2.07V      1.564V     2.057V
1.028ns   1.988V     1.565V     387.1mV
1.218ns   1.306V     1.568V     27.79mV
1.408ns   313.5mV    1.568V     4.712mV
1.663ns   22.34mV    1.476V     1.763mV
2.171ns   1.764mV    265mV      616uV
2.423ns   1.003mV    45.85mV    426.9uV
6.4ns     -2.423uV   38.64uV    3.64uV
[Falling Waveform]
R_fixture= 0.2200k
V_fixture= 3.3000
V_fixture_min= 3.0000
V_fixture_max= 3.6000
|time   V(typ)   V(min)   V(max)
0s        3.3V       3V         3.6V
792.5ps   3.3V       3V         3.565V
913.6ps   3.306V     3V         3.247V
1.098ns   3.309V     3V         2.359V
1.276ns   3.074V     3V         1.691V
1.643ns   2.059V     3.011V     1.205V
2.178ns   1.441V     2.729V     1.135V
2.703ns   1.345V     2.081V     1.13V
3.293ns   1.328V     1.779V     1.129V
6.4ns     1.324V     1.664V     1.129V
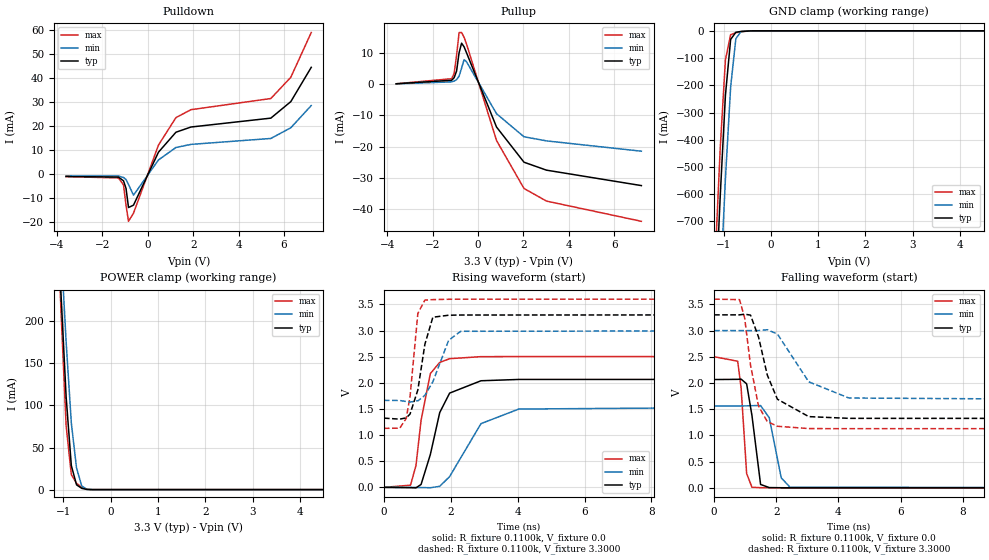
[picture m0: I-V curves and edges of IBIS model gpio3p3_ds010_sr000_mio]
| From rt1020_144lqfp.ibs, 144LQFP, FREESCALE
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[Model] gpio3p3_ds010_sr000_mio
|   Model gpio3p3_ds010_sr000_mio
| This model was characterised for following simulation conditions:
| External (pad) voltage:
|   - Typ: 3.3V,   - Min: 3.0V,   - Max: 3.6V
| Library cells for typ/min/max conditions are connected as defined below:
|  pad - External Pad
|  ipp_do - Core Input
|  ipp_obe - Output Buffer Enable
|  esd_boost - ovdd
|  ipp_dse0 - vssi
|  ipp_dse1 - vddi
|  ipp_dse2 - vssi
|  ipp_fsel0 - vssi
|  ipp_fsel1 - vssi
|  ipp_ina - ipp_ina
|  ipp_ind - ipp_ind
|  ipp_pwr_stable - vddi
|  ipp_sre - vssi
|  ovdd - ovdd
|  ovss - ovss
|  vddi - vddi
|  vssi - vssi
| All other pins connected to ground
Model_type I/O
Polarity   Non-Inverting
Enable   Active-High
Vinl =   0.9900V
Vinh =   2.3100V
Vmeas =  1.6500V
Cref =   0.0F
Rref =   0.1100k
Vref =   1.6500V
C_comp   1.2178pF   1.1833pF   1.2636pF
|C_comp_pullup   0.6042pF   0.6189pF   0.5908pF
|C_comp_pulldown   0.5474pF   0.5788pF   0.5258pF
[Model Spec]
| variable   typ   min   max
Vinh   2.3100V   2.1000V   2.5200V
Vinl   0.9900V   0.9000V   1.0800V
S_overshoot_high   3.3000V   3.0000V   3.6000V
S_overshoot_low   0.0V   0.0V   0.0V
Vmeas   1.6500V   1.5000V   1.8000V
Vref   1.6500V   1.5000V   1.8000V
Cref   0.0F   0.0F   0.0F
Rref   0.1100k   0.1100k   0.1100k
[Temperature Range]   25.0000   0.1050k   -20.0000
[Voltage Range]   3.3000V   3.0000V   3.6000V
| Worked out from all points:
|   slope of the pulldown table from 0 to 0.495 V, typ, clamps not added: 52.1 ohm
|   slope of the pullup table from 0 to 0.495 V, typ, clamps not added: 55.8 ohm
|   GND clamp passes 1 mA (typ) near -0.54 V on its own axis
|   POWER clamp passes 1 mA (typ) near -0.57 V on its own axis
|   rising waveform, R_fixture 0.1100k, V_fixture 0.0: 20-80 % time 488ps typ, 905ps min, 319ps max; typ from 0 V to 2.07 V
|   rising waveform, R_fixture 0.1100k, V_fixture 3.3000: 20-80 % time 301ps typ, 483ps min, 213ps max; typ from 1.32 V to 3.3 V
|   falling waveform, R_fixture 0.1100k, V_fixture 0.0: 20-80 % time 204ps typ, 292ps min, 158ps max; typ from 2.07 V to 0 V
|   falling waveform, R_fixture 0.1100k, V_fixture 3.3000: 20-80 % time 588ps typ, 986ps min, 380ps max; typ from 3.3 V to 1.32 V
[Pulldown]
|Voltage   I(typ)   I(min)   I(max)
-3.6V     -1.02mA    -860uA     -1.08mA
-1.29V    -1.294mA   -833uA     -1.653mA
-1.07V    -2.852mA   -1.461mA   -4.561mA
-960mV    -5.973mA   -2.272mA   -13mA
-850mV    -14.01mA   -4.368mA   -19.77mA
-630mV    -13.01mA   -8.848mA   -16.37mA
470mV     9.13mA     5.875mA    12.09mA
1.24V     17.47mA    11.09mA    23.58mA
1.9V      19.64mA    12.38mA    26.89mA
5.42V     23.36mA    14.86mA    31.56mA
6.3V      30.26mA    19.33mA    40.44mA
7.2V      44.59mA    28.62mA    59.13mA
[Pullup]
|Voltage   I(typ)   I(min)   I(max)
-3.6V     150uA      130uA      150uA
-1.16V    1.269mA    750uA      1.777mA
-1.05V    2.063mA    994uA      3.366mA
-940mV    4.231mA    1.48mA     9.243mA
-830mV    10.07mA    2.574mA    16.54mA
-720mV    13.14mA    5.17mA     16.54mA
-610mV    11.98mA    7.864mA    15.04mA
-500mV    10.04mA    7.165mA    12.8mA
820mV     -13.71mA   -9.439mA   -18.03mA
2.03V     -24.96mA   -16.82mA   -33.37mA
3.02V     -27.5mA    -18.13mA   -37.4mA
7.2V      -32.44mA   -21.43mA   -43.87mA
[GND_clamp]
|Voltage   I(typ)   I(min)   I(max)
-3.6V     -10.99A    -11.14A    -10.93A
-1.18V    -1.033A    -1.378A    -850.8mA
-1.07V    -607mA     -947.1mA   -431.4mA
-960mV    -236.8mA   -543mA     -106.4mA
-850mV    -31.63mA   -206.7mA   -14.18mA
-740mV    -5.424mA   -29mA      -7.092mA
-630mV    -2.275mA   -2.653mA   -3.283mA
-410mV    -62.05uA   -83.52uA   -82.05uA
7.2V      0A         0A         0A
[POWER_clamp]
|Voltage   I(typ)   I(min)   I(max)
-3.6V     3.491A     3.319A     3.949A
-1.16V    368.2mA    410.8mA    372.9mA
-1.05V    234.5mA    290.2mA    214.3mA
-940mV    110.2mA    175.6mA    75.85mA
-830mV    28.53mA    79.02mA    17.73mA
-720mV    5.671mA    25.66mA    7.515mA
-610mV    1.49mA     4.301mA    2.636mA
-500mV    198.2uA    300.8uA    424.4uA
-390mV    9.667uA    18.86uA    16.14uA
7.2V      0A         0A         0A
[Ramp]
| variable   typ   min   max
dV/dt_r  1.2395/0.4876n   0.9378/0.9052n   1.5013/0.3190n
dV/dt_f  1.1855/0.5884n   0.8017/0.9860n   1.4827/0.3803n
R_load = 0.1100k
[Rising Waveform]
R_fixture= 0.1100k
V_fixture= 0.0
V_fixture_min= 0.0
V_fixture_max= 0.0
|time   V(typ)   V(min)   V(max)
0s        8.464nV    7.703nV    89.62nV
794ps     -5.819mV   -1.814uV   42.41mV
957.1ps   -9.235mV   -1.377mV   415.4mV
1.11ns    55.92mV    -2.896mV   1.282V
1.387ns   627.4mV    -6.879mV   2.175V
1.668ns   1.431V     20.14mV    2.39V
1.964ns   1.803V     206.8mV    2.461V
2.902ns   2.039V     1.219V     2.5V
4.032ns   2.064V     1.498V     2.502V
18.61ns   2.066V     1.563V     2.502V
[Rising Waveform]
R_fixture= 0.1100k
V_fixture= 3.3000
V_fixture_min= 3.0000
V_fixture_max= 3.6000
|time   V(typ)   V(min)   V(max)
0s        1.324V     1.664V     1.129V
473.2ps   1.305V     1.662V     1.132V
667.1ps   1.33V      1.641V     1.32V
779.3ps   1.401V     1.631V     1.733V
1.014ns   1.864V     1.655V     3.328V
1.224ns   2.736V     1.759V     3.581V
1.462ns   3.254V     2.019V     3.591V
1.934ns   3.292V     2.812V     3.597V
2.296ns   3.296V     2.985V     3.599V
18.61ns   3.3V       3V         3.6V
[Falling Waveform]
R_fixture= 0.1100k
V_fixture= 0.0
V_fixture_min= 0.0
V_fixture_max= 0.0
|time   V(typ)   V(min)   V(max)
0s        2.066V     1.563V     2.502V
760.1ps   2.07V      1.563V     2.415V
870ps     2.074V     1.563V     1.905V
1.048ns   1.984V     1.564V     273mV
1.219ns   1.379V     1.568V     11.27mV
1.497ns   64.74mV    1.57V      3.646mV
1.775ns   5.432mV    1.338V     1.906mV
2.16ns    2.451mV    191.8mV    758.1uV
2.442ns   1.453mV    12.93mV    393uV
18.61ns   -13.22nV   26.89nV    84.9nV
[Falling Waveform]
R_fixture= 0.1100k
V_fixture= 3.3000
V_fixture_min= 3.0000
V_fixture_max= 3.6000
|time   V(typ)   V(min)   V(max)
0s        3.3V       3V         3.6V
820.7ps   3.3V       3V         3.59V
984.4ps   3.313V     3V         3.238V
1.173ns   3.295V     2.999V     2.341V
1.431ns   2.877V     3.001V     1.56V
1.713ns   2.151V     3.016V     1.264V
2.038ns   1.691V     2.935V     1.175V
3.046ns   1.359V     2.023V     1.131V
4.339ns   1.326V     1.714V     1.129V
18.61ns   1.324V     1.664V     1.129V
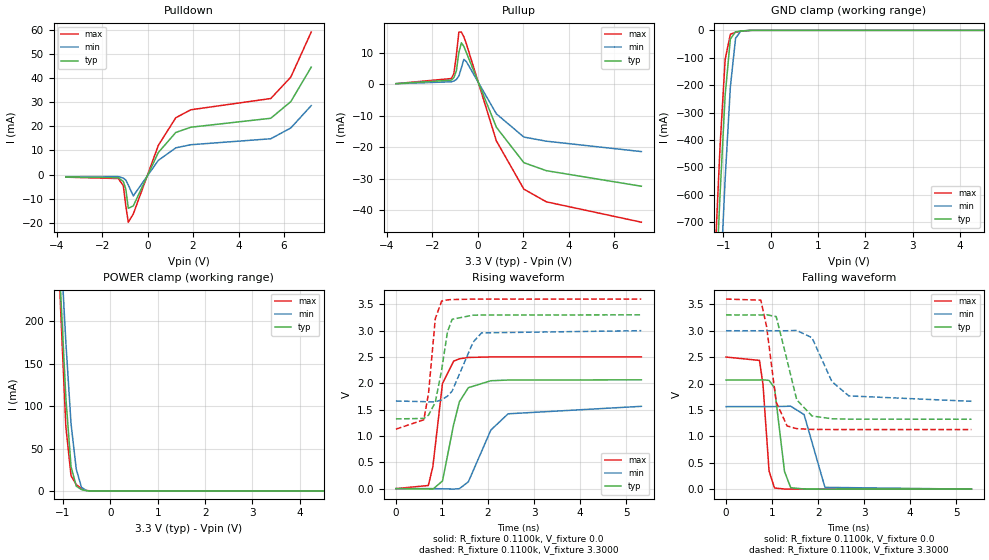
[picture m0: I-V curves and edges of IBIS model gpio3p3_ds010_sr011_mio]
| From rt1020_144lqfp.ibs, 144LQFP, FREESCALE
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[Model] gpio3p3_ds010_sr011_mio
|   Model gpio3p3_ds010_sr011_mio
| This model was characterised for following simulation conditions:
| External (pad) voltage:
|   - Typ: 3.3V,   - Min: 3.0V,   - Max: 3.6V
| Library cells for typ/min/max conditions are connected as defined below:
|  pad - External Pad
|  ipp_do - Core Input
|  ipp_obe - Output Buffer Enable
|  esd_boost - ovdd
|  ipp_dse0 - vssi
|  ipp_dse1 - vddi
|  ipp_dse2 - vssi
|  ipp_fsel0 - vddi
|  ipp_fsel1 - vddi
|  ipp_ina - ipp_ina
|  ipp_ind - ipp_ind
|  ipp_pwr_stable - vddi
|  ipp_sre - vssi
|  ovdd - ovdd
|  ovss - ovss
|  vddi - vddi
|  vssi - vssi
| All other pins connected to ground
Model_type I/O
Polarity   Non-Inverting
Enable   Active-High
Vinl =   0.9900V
Vinh =   2.3100V
Vmeas =  1.6500V
Cref =   0.0F
Rref =   0.1100k
Vref =   1.6500V
C_comp   1.2179pF   1.1833pF   1.2636pF
|C_comp_pullup   0.6043pF   0.6190pF   0.5909pF
|C_comp_pulldown   0.5474pF   0.5788pF   0.5258pF
[Model Spec]
| variable   typ   min   max
Vinh   2.3100V   2.1000V   2.5200V
Vinl   0.9900V   0.9000V   1.0800V
S_overshoot_high   3.3000V   3.0000V   3.6000V
S_overshoot_low   0.0V   0.0V   0.0V
Vmeas   1.6500V   1.5000V   1.8000V
Vref   1.6500V   1.5000V   1.8000V
Cref   0.0F   0.0F   0.0F
Rref   0.1100k   0.1100k   0.1100k
[Temperature Range]   25.0000   0.1050k   -20.0000
[Voltage Range]   3.3000V   3.0000V   3.6000V
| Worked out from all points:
|   slope of the pulldown table from 0 to 0.495 V, typ, clamps not added: 52.1 ohm
|   slope of the pullup table from 0 to 0.495 V, typ, clamps not added: 55.8 ohm
|   GND clamp passes 1 mA (typ) near -0.54 V on its own axis
|   POWER clamp passes 1 mA (typ) near -0.57 V on its own axis
|   rising waveform, R_fixture 0.1100k, V_fixture 0.0: 20-80 % time 282ps typ, 482ps min, 197ps max; typ from 0 V to 2.07 V
|   rising waveform, R_fixture 0.1100k, V_fixture 3.3000: 20-80 % time 222ps typ, 367ps min, 156ps max; typ from 1.32 V to 3.3 V
|   falling waveform, R_fixture 0.1100k, V_fixture 0.0: 20-80 % time 147ps typ, 213ps min, 117ps max; typ from 2.07 V to 0 V
|   falling waveform, R_fixture 0.1100k, V_fixture 3.3000: 20-80 % time 299ps typ, 443ps min, 219ps max; typ from 3.3 V to 1.32 V
[Pulldown]
|Voltage   I(typ)   I(min)   I(max)
-3.6V     -1.02mA    -860uA     -1.08mA
-1.29V    -1.294mA   -833uA     -1.653mA
-1.07V    -2.852mA   -1.461mA   -4.561mA
-960mV    -5.973mA   -2.272mA   -13mA
-850mV    -14.01mA   -4.368mA   -19.77mA
-630mV    -13.01mA   -8.848mA   -16.37mA
470mV     9.13mA     5.875mA    12.09mA
1.24V     17.47mA    11.09mA    23.58mA
1.9V      19.64mA    12.38mA    26.89mA
5.42V     23.36mA    14.86mA    31.56mA
6.3V      30.26mA    19.33mA    40.44mA
7.2V      44.59mA    28.62mA    59.13mA
[Pullup]
|Voltage   I(typ)   I(min)   I(max)
-3.6V     150uA      130uA      150uA
-1.16V    1.269mA    750uA      1.777mA
-1.05V    2.063mA    994uA      3.366mA
-940mV    4.231mA    1.48mA     9.243mA
-830mV    10.07mA    2.574mA    16.54mA
-720mV    13.14mA    5.17mA     16.54mA
-610mV    11.98mA    7.864mA    15.04mA
-500mV    10.04mA    7.165mA    12.8mA
820mV     -13.71mA   -9.439mA   -18.03mA
2.03V     -24.96mA   -16.82mA   -33.37mA
3.02V     -27.5mA    -18.13mA   -37.4mA
7.2V      -32.44mA   -21.43mA   -43.87mA
[GND_clamp]
|Voltage   I(typ)   I(min)   I(max)
-3.6V     -10.99A    -11.14A    -10.93A
-1.18V    -1.033A    -1.378A    -850.8mA
-1.07V    -607mA     -947.1mA   -431.4mA
-960mV    -236.8mA   -543mA     -106.4mA
-850mV    -31.63mA   -206.7mA   -14.18mA
-740mV    -5.424mA   -29mA      -7.092mA
-630mV    -2.275mA   -2.653mA   -3.283mA
-410mV    -62.05uA   -83.52uA   -82.04uA
7.2V      0A         0A         0A
[POWER_clamp]
|Voltage   I(typ)   I(min)   I(max)
-3.6V     3.491A     3.319A     3.949A
-1.16V    368.2mA    410.8mA    372.9mA
-1.05V    234.5mA    290.2mA    214.3mA
-940mV    110.2mA    175.6mA    75.85mA
-830mV    28.53mA    79.02mA    17.73mA
-720mV    5.671mA    25.66mA    7.515mA
-610mV    1.49mA     4.301mA    2.636mA
-500mV    198.2uA    300.8uA    424.4uA
-390mV    9.667uA    18.86uA    16.14uA
7.2V      0A         0A         0A
[Ramp]
| variable   typ   min   max
dV/dt_r  1.2395/0.2815n   0.9377/0.4817n   1.5013/0.1969n
dV/dt_f  1.1855/0.2987n   0.8016/0.4429n   1.4827/0.2191n
R_load = 0.1100k
[Rising Waveform]
R_fixture= 0.1100k
V_fixture= 0.0
V_fixture_min= 0.0
V_fixture_max= 0.0
|time   V(typ)   V(min)   V(max)
0s        8.464nV    7.651nV    89.62nV
703.3ps   -5.513mV   183.9uV    59.39mV
801.8ps   -10.14mV   -587.8uV   413.8mV
1.011ns   144.7mV    -2.967mV   1.997V
1.254ns   1.219V     -8.377mV   2.422V
1.378ns   1.649V     -543.3uV   2.465V
1.573ns   1.917V     129.4mV    2.491V
2.062ns   2.049V     1.113V     2.501V
2.436ns   2.062V     1.421V     2.502V
5.33ns    2.066V     1.563V     2.502V
[Rising Waveform]
R_fixture= 0.1100k
V_fixture= 3.3000
V_fixture_min= 3.0000
V_fixture_max= 3.6000
|time   V(typ)   V(min)   V(max)
0s        1.324V     1.664V     1.129V
606.6ps   1.333V     1.652V     1.308V
708.3ps   1.396V     1.645V     1.812V
854.6ps   1.639V     1.65V      3.227V
991.7ps   2.247V     1.685V     3.56V
1.119ns   2.975V     1.756V     3.585V
1.22ns    3.216V     1.851V     3.591V
1.675ns   3.294V     2.78V      3.599V
1.861ns   3.297V     2.958V     3.599V
5.33ns    3.3V       3V         3.6V
[Falling Waveform]
R_fixture= 0.1100k
V_fixture= 0.0
V_fixture_min= 0.0
V_fixture_max= 0.0
|time   V(typ)   V(min)   V(max)
0s        2.066V     1.563V     2.502V
725.8ps   2.068V     1.563V     2.438V
802ps     2.071V     1.563V     1.984V
934.2ps   2.06V      1.563V     343.3mV
1.052ns   1.92V      1.564V     21.7mV
1.27ns    333.3mV    1.568V     3.039mV
1.404ns   29.06mV    1.571V     1.567mV
1.694ns   2.929mV    1.413V     573.9uV
2.148ns   582uV      34.41mV    258.8uV
5.33ns    4.869uV    43.08uV    5.536uV
[Falling Waveform]
R_fixture= 0.1100k
V_fixture= 3.3000
V_fixture_min= 3.0000
V_fixture_max= 3.6000
|time   V(typ)   V(min)   V(max)
0s        3.3V       3V         3.6V
755.3ps   3.299V     3V         3.579V
880.5ps   3.303V     3V         3.08V
1.089ns   3.268V     3V         1.649V
1.325ns   2.442V     3V         1.198V
1.535ns   1.692V     3.006V     1.146V
1.867ns   1.386V     2.868V     1.132V
2.299ns   1.333V     2.037V     1.129V
2.667ns   1.326V     1.766V     1.129V
5.33ns    1.324V     1.664V     1.129V
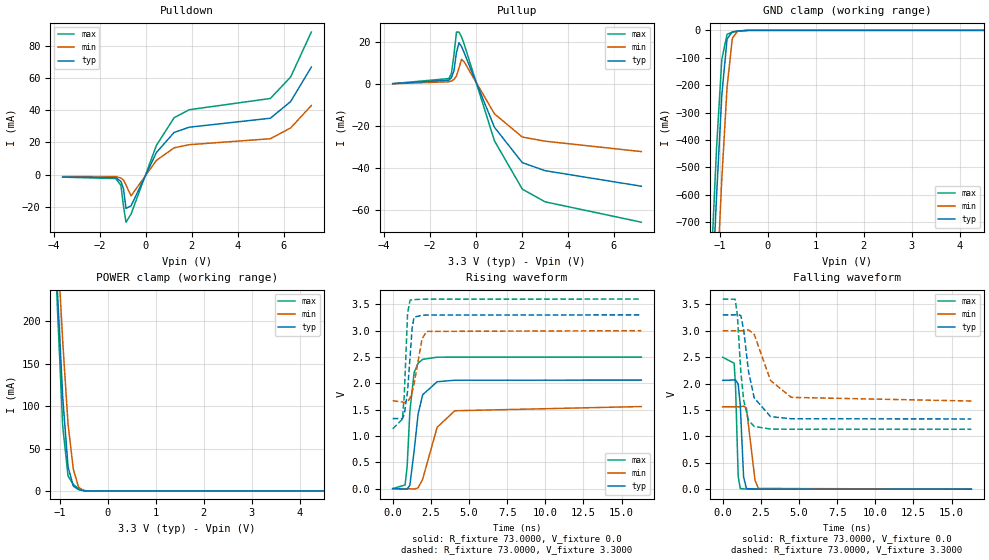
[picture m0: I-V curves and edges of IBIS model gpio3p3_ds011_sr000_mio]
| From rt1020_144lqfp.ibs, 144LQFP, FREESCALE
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[Model] gpio3p3_ds011_sr000_mio
|   Model gpio3p3_ds011_sr000_mio
| This model was characterised for following simulation conditions:
| External (pad) voltage:
|   - Typ: 3.3V,   - Min: 3.0V,   - Max: 3.6V
| Library cells for typ/min/max conditions are connected as defined below:
|  pad - External Pad
|  ipp_do - Core Input
|  ipp_obe - Output Buffer Enable
|  esd_boost - ovdd
|  ipp_dse0 - vddi
|  ipp_dse1 - vddi
|  ipp_dse2 - vssi
|  ipp_fsel0 - vssi
|  ipp_fsel1 - vssi
|  ipp_ina - ipp_ina
|  ipp_ind - ipp_ind
|  ipp_pwr_stable - vddi
|  ipp_sre - vssi
|  ovdd - ovdd
|  ovss - ovss
|  vddi - vddi
|  vssi - vssi
| All other pins connected to ground
Model_type I/O
Polarity   Non-Inverting
Enable   Active-High
Vinl =   0.9900V
Vinh =   2.3100V
Vmeas =  1.6500V
Cref =   0.0F
Rref =   73.0000
Vref =   1.6500V
C_comp   1.2178pF   1.1833pF   1.2636pF
|C_comp_pullup   0.6042pF   0.6189pF   0.5908pF
|C_comp_pulldown   0.5474pF   0.5788pF   0.5258pF
[Model Spec]
| variable   typ   min   max
Vinh   2.3100V   2.1000V   2.5200V
Vinl   0.9900V   0.9000V   1.0800V
S_overshoot_high   3.3000V   3.0000V   3.6000V
S_overshoot_low   0.0V   0.0V   0.0V
Vmeas   1.6500V   1.5000V   1.8000V
Vref   1.6500V   1.5000V   1.8000V
Cref   0.0F   0.0F   0.0F
Rref   73.0000   73.0000   73.0000
[Temperature Range]   25.0000   0.1050k   -20.0000
[Voltage Range]   3.3000V   3.0000V   3.6000V
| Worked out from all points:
|   slope of the pulldown table from 0 to 0.495 V, typ, clamps not added: 34.7 ohm
|   slope of the pullup table from 0 to 0.495 V, typ, clamps not added: 37.2 ohm
|   GND clamp passes 1 mA (typ) near -0.54 V on its own axis
|   POWER clamp passes 1 mA (typ) near -0.57 V on its own axis
|   rising waveform, R_fixture 73.0000, V_fixture 0.0: 20-80 % time 504ps typ, 986ps min, 314ps max; typ from 0 V to 2.06 V
|   rising waveform, R_fixture 73.0000, V_fixture 3.3000: 20-80 % time 298ps typ, 483ps min, 205ps max; typ from 1.33 V to 3.3 V
|   falling waveform, R_fixture 73.0000, V_fixture 0.0: 20-80 % time 192ps typ, 276ps min, 145ps max; typ from 2.06 V to 0 V
|   falling waveform, R_fixture 73.0000, V_fixture 3.3000: 20-80 % time 651ps typ, 1.15ns min, 396ps max; typ from 3.3 V to 1.33 V
[Pulldown]
|Voltage   I(typ)   I(min)   I(max)
-3.6V     -1.52mA    -1.29mA    -1.63mA
-1.29V    -1.942mA   -1.25mA    -2.48mA
-1.07V    -4.282mA   -2.193mA   -6.851mA
-960mV    -8.978mA   -3.411mA   -19.59mA
-850mV    -21.05mA   -6.563mA   -29.65mA
-630mV    -19.5mA    -13.27mA   -24.55mA
470mV     13.69mA    8.81mA     18.12mA
1.24V     26.2mA     16.63mA    35.36mA
1.9V      29.46mA    18.57mA    40.33mA
5.42V     35.03mA    22.28mA    47.33mA
6.3V      45.37mA    28.98mA    60.64mA
7.2V      66.85mA    42.91mA    88.63mA
[Pullup]
|Voltage   I(typ)   I(min)   I(max)
-3.6V     230uA      200uA      230uA
-1.16V    1.904mA    1.124mA    2.664mA
-1.05V    3.095mA    1.491mA    5.051mA
-940mV    6.35mA     2.219mA    13.89mA
-830mV    15.12mA    3.862mA    24.82mA
-720mV    19.72mA    7.761mA    24.8mA
-610mV    17.96mA    11.8mA     22.55mA
-500mV    15.06mA    10.74mA    19.2mA
820mV     -20.56mA   -14.16mA   -27.03mA
2.03V     -37.44mA   -25.22mA   -50.05mA
3.02V     -41.25mA   -27.19mA   -56.1mA
7.2V      -48.66mA   -32.15mA   -65.81mA
[GND_clamp]
|Voltage   I(typ)   I(min)   I(max)
-3.6V     -10.99A    -11.14A    -10.93A
-1.18V    -1.033A    -1.378A    -850.8mA
-1.07V    -607mA     -947.1mA   -431.4mA
-960mV    -236.8mA   -543mA     -106.4mA
-850mV    -31.63mA   -206.7mA   -14.18mA
-740mV    -5.424mA   -29mA      -7.092mA
-630mV    -2.275mA   -2.653mA   -3.283mA
-410mV    -62.05uA   -83.52uA   -82.05uA
7.2V      0A         0A         0A
[POWER_clamp]
|Voltage   I(typ)   I(min)   I(max)
-3.6V     3.491A     3.319A     3.949A
-1.16V    368.2mA    410.8mA    372.9mA
-1.05V    234.5mA    290.2mA    214.3mA
-940mV    110.2mA    175.6mA    75.85mA
-830mV    28.53mA    79.02mA    17.73mA
-720mV    5.671mA    25.66mA    7.515mA
-610mV    1.49mA     4.301mA    2.636mA
-500mV    198.2uA    300.8uA    424.4uA
-390mV    9.667uA    18.86uA    16.14uA
7.2V      0A         0A         0A
[Ramp]
| variable   typ   min   max
dV/dt_r  1.2368/0.5037n   0.9352/0.9859n   1.4986/0.3144n
dV/dt_f  1.1820/0.6506n   0.7985/1.1522n   1.4794/0.3961n
R_load = 73.0000
[Rising Waveform]
R_fixture= 73.0000
V_fixture= 0.0
V_fixture_min= 0.0
V_fixture_max= 0.0
|time   V(typ)   V(min)   V(max)
0s        5.638nV    5.094nV    59.72nV
812.4ps   -6.764mV   -245.9uV   70.44mV
946.8ps   -9.968mV   -1.421mV   421.5mV
1.124ns   64.94mV    -3.228mV   1.467V
1.403ns   713.9mV    -7.074mV   2.205V
1.666ns   1.421V     14.7mV     2.383V
1.967ns   1.784V     184.6mV    2.455V
2.913ns   2.03V      1.166V     2.496V
4.07ns    2.059V     1.479V     2.498V
16.29ns   2.061V     1.559V     2.498V
[Rising Waveform]
R_fixture= 73.0000
V_fixture= 3.3000
V_fixture_min= 3.0000
V_fixture_max= 3.6000
|time   V(typ)   V(min)   V(max)
0s        1.33V      1.669V     1.134V
637.5ps   1.331V     1.645V     1.319V
757.2ps   1.41V      1.633V     1.771V
974.5ps   1.851V     1.653V     3.331V
1.139ns   2.508V     1.724V     3.579V
1.275ns   3.061V     1.839V     3.587V
1.4ns     3.256V     1.991V     3.59V
1.923ns   3.293V     2.844V     3.597V
2.229ns   3.296V     2.986V     3.599V
16.29ns   3.3V       3V         3.6V
[Falling Waveform]
R_fixture= 73.0000
V_fixture= 0.0
V_fixture_min= 0.0
V_fixture_max= 0.0
|time   V(typ)   V(min)   V(max)
0s        2.061V     1.559V     2.498V
750ps     2.067V     1.559V     2.385V
842.1ps   2.069V     1.559V     1.935V
1.014ns   1.989V     1.56V      245mV
1.149ns   1.599V     1.563V     12.02mV
1.369ns   232.3mV    1.571V     4.552mV
1.554ns   11.58mV    1.54V      3.027mV
2.116ns   2.587mV    167.5mV    881.6uV
2.344ns   1.779mV    13.41mV    529uV
16.29ns   -45.47nV   34.11nV    62.6nV
[Falling Waveform]
R_fixture= 73.0000
V_fixture= 3.3000
V_fixture_min= 3.0000
V_fixture_max= 3.6000
|time   V(typ)   V(min)   V(max)
0s        3.3V       3V         3.6V
816.9ps   3.3V       3V         3.597V
959ps     3.312V     3V         3.3V
1.192ns   3.287V     2.999V     2.206V
1.376ns   3.013V     3V         1.681V
1.691ns   2.228V     3.017V     1.304V
2.065ns   1.728V     2.932V     1.188V
3.131ns   1.374V     2.059V     1.138V
4.492ns   1.333V     1.738V     1.134V
16.29ns   1.33V      1.669V     1.134V
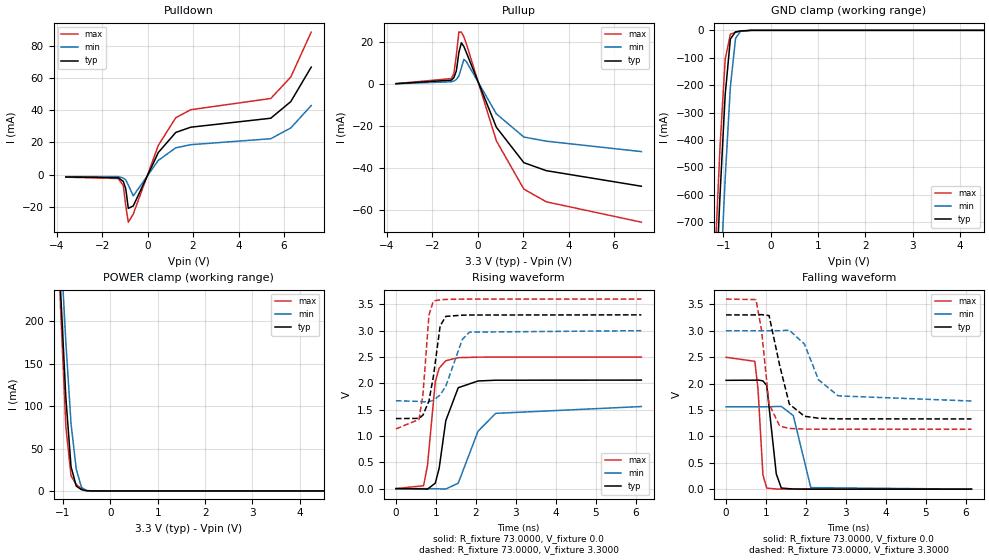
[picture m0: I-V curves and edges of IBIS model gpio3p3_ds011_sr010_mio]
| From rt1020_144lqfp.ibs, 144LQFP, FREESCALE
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[Model] gpio3p3_ds011_sr010_mio
|   Model gpio3p3_ds011_sr010_mio
| This model was characterised for following simulation conditions:
| External (pad) voltage:
|   - Typ: 3.3V,   - Min: 3.0V,   - Max: 3.6V
| Library cells for typ/min/max conditions are connected as defined below:
|  pad - External Pad
|  ipp_do - Core Input
|  ipp_obe - Output Buffer Enable
|  esd_boost - ovdd
|  ipp_dse0 - vddi
|  ipp_dse1 - vddi
|  ipp_dse2 - vssi
|  ipp_fsel0 - vssi
|  ipp_fsel1 - vddi
|  ipp_ina - ipp_ina
|  ipp_ind - ipp_ind
|  ipp_pwr_stable - vddi
|  ipp_sre - vssi
|  ovdd - ovdd
|  ovss - ovss
|  vddi - vddi
|  vssi - vssi
| All other pins connected to ground
Model_type I/O
Polarity   Non-Inverting
Enable   Active-High
Vinl =   0.9900V
Vinh =   2.3100V
Vmeas =  1.6500V
Cref =   0.0F
Rref =   73.0000
Vref =   1.6500V
C_comp   1.2179pF   1.1833pF   1.2636pF
|C_comp_pullup   0.6043pF   0.6190pF   0.5909pF
|C_comp_pulldown   0.5474pF   0.5788pF   0.5258pF
[Model Spec]
| variable   typ   min   max
Vinh   2.3100V   2.1000V   2.5200V
Vinl   0.9900V   0.9000V   1.0800V
S_overshoot_high   3.3000V   3.0000V   3.6000V
S_overshoot_low   0.0V   0.0V   0.0V
Vmeas   1.6500V   1.5000V   1.8000V
Vref   1.6500V   1.5000V   1.8000V
Cref   0.0F   0.0F   0.0F
Rref   73.0000   73.0000   73.0000
[Temperature Range]   25.0000   0.1050k   -20.0000
[Voltage Range]   3.3000V   3.0000V   3.6000V
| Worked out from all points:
|   slope of the pulldown table from 0 to 0.495 V, typ, clamps not added: 34.7 ohm
|   slope of the pullup table from 0 to 0.495 V, typ, clamps not added: 37.2 ohm
|   GND clamp passes 1 mA (typ) near -0.54 V on its own axis
|   POWER clamp passes 1 mA (typ) near -0.57 V on its own axis
|   rising waveform, R_fixture 73.0000, V_fixture 0.0: 20-80 % time 268ps typ, 489ps min, 180ps max; typ from 0 V to 2.06 V
|   rising waveform, R_fixture 73.0000, V_fixture 3.3000: 20-80 % time 218ps typ, 367ps min, 148ps max; typ from 1.33 V to 3.3 V
|   falling waveform, R_fixture 73.0000, V_fixture 0.0: 20-80 % time 139ps typ, 210ps min, 109ps max; typ from 2.06 V to 0 V
|   falling waveform, R_fixture 73.0000, V_fixture 3.3000: 20-80 % time 293ps typ, 485ps min, 201ps max; typ from 3.3 V to 1.33 V
[Pulldown]
|Voltage   I(typ)   I(min)   I(max)
-3.6V     -1.52mA    -1.29mA    -1.63mA
-1.29V    -1.942mA   -1.25mA    -2.48mA
-1.07V    -4.282mA   -2.193mA   -6.851mA
-960mV    -8.978mA   -3.411mA   -19.59mA
-850mV    -21.05mA   -6.563mA   -29.65mA
-630mV    -19.5mA    -13.27mA   -24.55mA
470mV     13.69mA    8.81mA     18.12mA
1.24V     26.2mA     16.63mA    35.36mA
1.9V      29.46mA    18.57mA    40.33mA
5.42V     35.03mA    22.28mA    47.33mA
6.3V      45.37mA    28.98mA    60.64mA
7.2V      66.85mA    42.91mA    88.63mA
[Pullup]
|Voltage   I(typ)   I(min)   I(max)
-3.6V     230uA      200uA      230uA
-1.16V    1.904mA    1.124mA    2.664mA
-1.05V    3.095mA    1.491mA    5.051mA
-940mV    6.35mA     2.219mA    13.89mA
-830mV    15.12mA    3.862mA    24.82mA
-720mV    19.72mA    7.761mA    24.8mA
-610mV    17.96mA    11.8mA     22.55mA
-500mV    15.06mA    10.74mA    19.2mA
820mV     -20.56mA   -14.16mA   -27.03mA
2.03V     -37.44mA   -25.22mA   -50.05mA
3.02V     -41.25mA   -27.19mA   -56.1mA
7.2V      -48.66mA   -32.15mA   -65.81mA
[GND_clamp]
|Voltage   I(typ)   I(min)   I(max)
-3.6V     -10.99A    -11.14A    -10.93A
-1.18V    -1.033A    -1.378A    -850.8mA
-1.07V    -607mA     -947.1mA   -431.4mA
-960mV    -236.8mA   -543mA     -106.4mA
-850mV    -31.63mA   -206.7mA   -14.18mA
-740mV    -5.424mA   -29mA      -7.092mA
-630mV    -2.275mA   -2.653mA   -3.283mA
-410mV    -62.05uA   -83.52uA   -82.04uA
7.2V      0A         0A         0A
[POWER_clamp]
|Voltage   I(typ)   I(min)   I(max)
-3.6V     3.491A     3.319A     3.949A
-1.16V    368.2mA    410.8mA    372.9mA
-1.05V    234.5mA    290.2mA    214.3mA
-940mV    110.2mA    175.6mA    75.85mA
-830mV    28.53mA    79.02mA    17.73mA
-720mV    5.671mA    25.66mA    7.515mA
-610mV    1.49mA     4.301mA    2.636mA
-500mV    198.2uA    300.8uA    424.4uA
-390mV    9.667uA    18.86uA    16.14uA
7.2V      0A         0A         0A
[Ramp]
| variable   typ   min   max
dV/dt_r  1.2368/0.2677n   0.9351/0.4890n   1.4986/0.1796n
dV/dt_f  1.1820/0.2929n   0.7984/0.4850n   1.4794/0.2014n
R_load = 73.0000
[Rising Waveform]
R_fixture= 73.0000
V_fixture= 0.0
V_fixture_min= 0.0
V_fixture_max= 0.0
|time   V(typ)   V(min)   V(max)
0s        5.638nV    5.128nV    59.72nV
692.1ps   -5.939mV   196.5uV    55.21mV
789.3ps   -10.36mV   -605.2uV   436.2mV
985.5ps   104.3mV    -2.919mV   2.035V
1.082ns   388.3mV    -4.38mV    2.287V
1.248ns   1.292V     -8.541mV   2.428V
1.559ns   1.917V     103.7mV    2.487V
2.054ns   2.044V     1.09V      2.497V
2.496ns   2.059V     1.429V     2.498V
6.14ns    2.061V     1.559V     2.498V
[Rising Waveform]
R_fixture= 73.0000
V_fixture= 3.3000
V_fixture_min= 3.0000
V_fixture_max= 3.6000
|time   V(typ)   V(min)   V(max)
0s        1.33V      1.669V     1.134V
577.9ps   1.334V     1.656V     1.314V
676.3ps   1.396V     1.648V     1.788V
827.2ps   1.667V     1.651V     3.301V
938.1ps   2.134V     1.678V     3.564V
1.107ns   3.092V     1.779V     3.586V
1.249ns   3.271V     1.946V     3.593V
1.66ns    3.294V     2.832V     3.599V
1.84ns    3.297V     2.972V     3.6V
6.14ns    3.3V       3V         3.6V
[Falling Waveform]
R_fixture= 73.0000
V_fixture= 0.0
V_fixture_min= 0.0
V_fixture_max= 0.0
|time   V(typ)   V(min)   V(max)
0s        2.061V     1.559V     2.498V
720.1ps   2.064V     1.559V     2.421V
800.1ps   2.067V     1.559V     1.892V
922.4ps   2.051V     1.559V     271.8mV
1.018ns   1.965V     1.56V      20.32mV
1.257ns   287.2mV    1.565V     3.078mV
1.383ns   20.95mV    1.567V     1.667mV
1.682ns   3.054mV    1.394V     516.8uV
2.121ns   658.4uV    29.23mV    186.7uV
6.14ns    -709.4nV   13.43uV    1.452uV
[Falling Waveform]
R_fixture= 73.0000
V_fixture= 3.3000
V_fixture_min= 3.0000
V_fixture_max= 3.6000
|time   V(typ)   V(min)   V(max)
0s        3.3V       3V         3.6V
747.9ps   3.3V       3V         3.59V
884.1ps   3.305V     3V         3.03V
1.076ns   3.288V     3V         1.612V
1.343ns   2.339V     3V         1.194V
1.583ns   1.612V     3.011V     1.15V
1.961ns   1.381V     2.747V     1.137V
2.315ns   1.343V     2.07V      1.135V
2.806ns   1.332V     1.767V     1.135V
6.14ns    1.33V      1.669V     1.134V
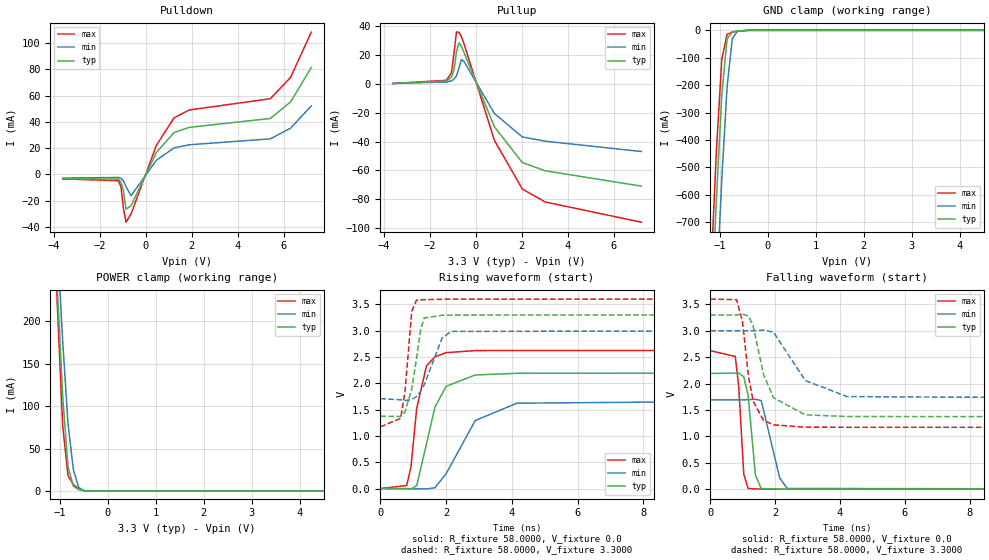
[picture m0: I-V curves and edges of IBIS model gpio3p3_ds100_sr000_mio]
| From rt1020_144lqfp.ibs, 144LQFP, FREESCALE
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[Model] gpio3p3_ds100_sr000_mio
|   Model gpio3p3_ds100_sr000_mio
| This model was characterised for following simulation conditions:
| External (pad) voltage:
|   - Typ: 3.3V,   - Min: 3.0V,   - Max: 3.6V
| Library cells for typ/min/max conditions are connected as defined below:
|  pad - External Pad
|  ipp_do - Core Input
|  ipp_obe - Output Buffer Enable
|  esd_boost - ovdd
|  ipp_dse0 - vssi
|  ipp_dse1 - vssi
|  ipp_dse2 - vddi
|  ipp_fsel0 - vssi
|  ipp_fsel1 - vssi
|  ipp_ina - ipp_ina
|  ipp_ind - ipp_ind
|  ipp_pwr_stable - vddi
|  ipp_sre - vssi
|  ovdd - ovdd
|  ovss - ovss
|  vddi - vddi
|  vssi - vssi
| All other pins connected to ground
Model_type I/O
Polarity   Non-Inverting
Enable   Active-High
Vinl =   0.9900V
Vinh =   2.3100V
Vmeas =  1.6500V
Cref =   0.0F
Rref =   58.0000
Vref =   1.6500V
C_comp   1.2178pF   1.1833pF   1.2636pF
|C_comp_pullup   0.6042pF   0.6189pF   0.5908pF
|C_comp_pulldown   0.5474pF   0.5788pF   0.5258pF
[Model Spec]
| variable   typ   min   max
Vinh   2.3100V   2.1000V   2.5200V
Vinl   0.9900V   0.9000V   1.0800V
S_overshoot_high   3.3000V   3.0000V   3.6000V
S_overshoot_low   0.0V   0.0V   0.0V
Vmeas   1.6500V   1.5000V   1.8000V
Vref   1.6500V   1.5000V   1.8000V
Cref   0.0F   0.0F   0.0F
Rref   58.0000   58.0000   58.0000
[Temperature Range]   25.0000   0.1050k   -20.0000
[Voltage Range]   3.3000V   3.0000V   3.6000V
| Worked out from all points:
|   slope of the pulldown table from 0 to 0.495 V, typ, clamps not added: 28.5 ohm
|   slope of the pullup table from 0 to 0.495 V, typ, clamps not added: 25.7 ohm
|   GND clamp passes 1 mA (typ) near -0.54 V on its own axis
|   POWER clamp passes 1 mA (typ) near -0.57 V on its own axis
|   rising waveform, R_fixture 58.0000, V_fixture 0.0: 20-80 % time 494ps typ, 947ps min, 310ps max; typ from 0 V to 2.19 V
|   rising waveform, R_fixture 58.0000, V_fixture 3.3000: 20-80 % time 287ps typ, 458ps min, 198ps max; typ from 1.37 V to 3.3 V
|   falling waveform, R_fixture 58.0000, V_fixture 0.0: 20-80 % time 187ps typ, 274ps min, 146ps max; typ from 2.19 V to 0 V
|   falling waveform, R_fixture 58.0000, V_fixture 3.3000: 20-80 % time 517ps typ, 894ps min, 318ps max; typ from 3.3 V to 1.37 V
[Pulldown]
|Voltage   I(typ)   I(min)   I(max)
-3.6V     -3.29mA    -2.84mA    -3.51mA
-1.18V    -3.645mA   -2.421mA   -4.835mA
-1.07V    -5.921mA   -3.024mA   -9.452mA
-960mV    -12.77mA   -4.911mA   -25.98mA
-850mV    -26.55mA   -9.409mA   -36.48mA
-630mV    -23.88mA   -16.25mA   -30.12mA
470mV     16.68mA    10.72mA    22.13mA
1.24V     31.86mA    20.19mA    43.07mA
1.9V      35.79mA    22.52mA    49.06mA
5.42V     42.57mA    27.03mA    57.6mA
6.3V      55.19mA    35.19mA    73.91mA
7.2V      81.51mA    52.18mA    108.4mA
[Pullup]
|Voltage   I(typ)   I(min)   I(max)
-3.6V     330uA      290uA      330uA
-1.27V    2.011mA    1.347mA    2.56mA
-1.05V    4.628mA    2.191mA    7.616mA
-940mV    9.591mA    3.262mA    21.02mA
-830mV    22.24mA    5.683mA    36mA
-720mV    28.46mA    11.34mA    35.87mA
-610mV    25.92mA    17.01mA    32.61mA
-500mV    21.74mA    15.5mA     27.75mA
820mV     -29.79mA   -20.52mA   -39.2mA
2.03V     -54.53mA   -36.77mA   -72.89mA
3.02V     -60.23mA   -39.71mA   -81.88mA
7.2V      -70.9mA    -46.86mA   -95.92mA
[GND_clamp]
|Voltage   I(typ)   I(min)   I(max)
-3.6V     -10.99A    -11.14A    -10.93A
-1.18V    -1.033A    -1.378A    -850.8mA
-1.07V    -607mA     -947.1mA   -431.4mA
-960mV    -236.8mA   -543mA     -106.4mA
-850mV    -31.63mA   -206.7mA   -14.18mA
-740mV    -5.424mA   -29mA      -7.092mA
-630mV    -2.275mA   -2.653mA   -3.283mA
-410mV    -62.05uA   -83.52uA   -82.05uA
7.2V      0A         0A         0A
[POWER_clamp]
|Voltage   I(typ)   I(min)   I(max)
-3.6V     3.491A     3.319A     3.949A
-1.16V    368.2mA    410.8mA    372.9mA
-1.05V    234.5mA    290.2mA    214.3mA
-940mV    110.2mA    175.6mA    75.85mA
-830mV    28.53mA    79.02mA    17.73mA
-720mV    5.671mA    25.66mA    7.515mA
-610mV    1.49mA     4.301mA    2.636mA
-500mV    198.2uA    300.8uA    424.4uA
-390mV    9.667uA    18.86uA    16.14uA
7.2V      0A         0A         0A
[Ramp]
| variable   typ   min   max
dV/dt_r  1.3153/0.4943n   1.0150/0.9471n   1.5740/0.3100n
dV/dt_f  1.1558/0.5173n   0.7746/0.8938n   1.4570/0.3177n
R_load = 58.0000
[Rising Waveform]
R_fixture= 58.0000
V_fixture= 0.0
V_fixture_min= 0.0
V_fixture_max= 0.0
|time   V(typ)   V(min)   V(max)
0s        4.578nV    4.118nV    48.47nV
803.8ps   -7.07mV    -206uV     58.29mV
932.1ps   -11.51mV   -1.417mV   409mV
1.108ns   57mV       -3.315mV   1.53V
1.405ns   849.8mV    -8.075mV   2.332V
1.659ns   1.544V     14.98mV    2.501V
2.002ns   1.942V     281.2mV    2.582V
2.886ns   2.158V     1.293V     2.621V
4.156ns   2.19V      1.622V     2.623V
18.16ns   2.192V     1.692V     2.623V
[Rising Waveform]
R_fixture= 58.0000
V_fixture= 3.3000
V_fixture_min= 3.0000
V_fixture_max= 3.6000
|time   V(typ)   V(min)   V(max)
0s        1.374V     1.709V     1.172V
618.6ps   1.369V     1.686V     1.333V
748.5ps   1.453V     1.672V     1.826V
956.2ps   1.89V      1.69V      3.362V
1.101ns   2.467V     1.748V     3.579V
1.225ns   3.012V     1.842V     3.586V
1.333ns   3.241V     1.965V     3.588V
1.873ns   3.292V     2.855V     3.596V
2.154ns   3.295V     2.986V     3.598V
18.16ns   3.3V       3V         3.6V
[Falling Waveform]
R_fixture= 58.0000
V_fixture= 0.0
V_fixture_min= 0.0
V_fixture_max= 0.0
|time   V(typ)   V(min)   V(max)
0s        2.192V     1.692V     2.623V
770.5ps   2.197V     1.691V     2.514V
876.7ps   2.199V     1.692V     1.953V
1.033ns   2.127V     1.692V     290.1mV
1.167ns   1.781V     1.695V     13.16mV
1.392ns   268.3mV    1.703V     4.272mV
1.571ns   11.95mV    1.678V     2.628mV
2.144ns   2.17mV     207.9mV    591.6uV
2.373ns   1.378mV    13.13mV    333uV
18.16ns   12.02nV    17.97nV    51.95nV
[Falling Waveform]
R_fixture= 58.0000
V_fixture= 3.3000
V_fixture_min= 3.0000
V_fixture_max= 3.6000
|time   V(typ)   V(min)   V(max)
0s        3.3V       3V         3.6V
811.3ps   3.3V       3V         3.588V
993.7ps   3.316V     3V         3.175V
1.179ns   3.278V     2.999V     2.13V
1.323ns   3.089V     2.999V     1.666V
1.641ns   2.178V     3.013V     1.304V
1.949ns   1.732V     2.973V     1.218V
2.93ns    1.407V     2.058V     1.174V
4.218ns   1.376V     1.753V     1.172V
18.16ns   1.374V     1.709V     1.172V
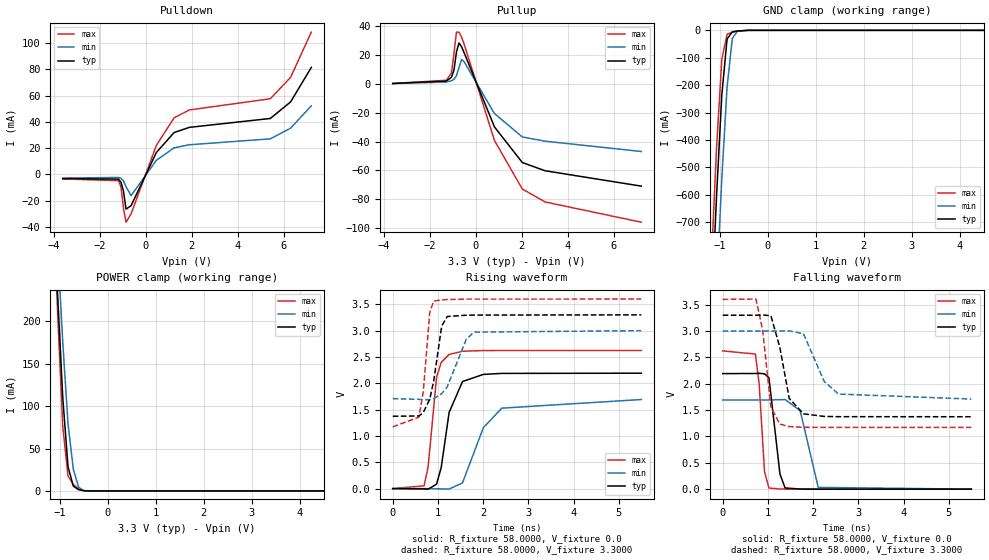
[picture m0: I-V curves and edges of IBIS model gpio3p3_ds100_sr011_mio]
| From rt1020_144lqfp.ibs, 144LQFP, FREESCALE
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[Model] gpio3p3_ds100_sr011_mio
|   Model gpio3p3_ds100_sr011_mio
| This model was characterised for following simulation conditions:
| External (pad) voltage:
|   - Typ: 3.3V,   - Min: 3.0V,   - Max: 3.6V
| Library cells for typ/min/max conditions are connected as defined below:
|  pad - External Pad
|  ipp_do - Core Input
|  ipp_obe - Output Buffer Enable
|  esd_boost - ovdd
|  ipp_dse0 - vssi
|  ipp_dse1 - vssi
|  ipp_dse2 - vddi
|  ipp_fsel0 - vddi
|  ipp_fsel1 - vddi
|  ipp_ina - ipp_ina
|  ipp_ind - ipp_ind
|  ipp_pwr_stable - vddi
|  ipp_sre - vssi
|  ovdd - ovdd
|  ovss - ovss
|  vddi - vddi
|  vssi - vssi
| All other pins connected to ground
Model_type I/O
Polarity   Non-Inverting
Enable   Active-High
Vinl =   0.9900V
Vinh =   2.3100V
Vmeas =  1.6500V
Cref =   0.0F
Rref =   58.0000
Vref =   1.6500V
C_comp   1.2179pF   1.1833pF   1.2636pF
|C_comp_pullup   0.6043pF   0.6190pF   0.5909pF
|C_comp_pulldown   0.5474pF   0.5788pF   0.5258pF
[Model Spec]
| variable   typ   min   max
Vinh   2.3100V   2.1000V   2.5200V
Vinl   0.9900V   0.9000V   1.0800V
S_overshoot_high   3.3000V   3.0000V   3.6000V
S_overshoot_low   0.0V   0.0V   0.0V
Vmeas   1.6500V   1.5000V   1.8000V
Vref   1.6500V   1.5000V   1.8000V
Cref   0.0F   0.0F   0.0F
Rref   58.0000   58.0000   58.0000
[Temperature Range]   25.0000   0.1050k   -20.0000
[Voltage Range]   3.3000V   3.0000V   3.6000V
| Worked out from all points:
|   slope of the pulldown table from 0 to 0.495 V, typ, clamps not added: 28.5 ohm
|   slope of the pullup table from 0 to 0.495 V, typ, clamps not added: 25.7 ohm
|   GND clamp passes 1 mA (typ) near -0.54 V on its own axis
|   POWER clamp passes 1 mA (typ) near -0.57 V on its own axis
|   rising waveform, R_fixture 58.0000, V_fixture 0.0: 20-80 % time 257ps typ, 474ps min, 169ps max; typ from 0 V to 2.19 V
|   rising waveform, R_fixture 58.0000, V_fixture 3.3000: 20-80 % time 209ps typ, 351ps min, 140ps max; typ from 1.37 V to 3.3 V
|   falling waveform, R_fixture 58.0000, V_fixture 0.0: 20-80 % time 136ps typ, 199ps min, 109ps max; typ from 2.19 V to 0 V
|   falling waveform, R_fixture 58.0000, V_fixture 3.3000: 20-80 % time 247ps typ, 376ps min, 182ps max; typ from 3.3 V to 1.37 V
[Pulldown]
|Voltage   I(typ)   I(min)   I(max)
-3.6V     -3.29mA    -2.84mA    -3.51mA
-1.18V    -3.645mA   -2.421mA   -4.835mA
-1.07V    -5.921mA   -3.024mA   -9.452mA
-960mV    -12.77mA   -4.911mA   -25.98mA
-850mV    -26.55mA   -9.409mA   -36.48mA
-630mV    -23.88mA   -16.25mA   -30.12mA
470mV     16.68mA    10.72mA    22.13mA
1.24V     31.86mA    20.19mA    43.07mA
1.9V      35.79mA    22.52mA    49.06mA
5.42V     42.57mA    27.03mA    57.6mA
6.3V      55.19mA    35.19mA    73.91mA
7.2V      81.51mA    52.18mA    108.4mA
[Pullup]
|Voltage   I(typ)   I(min)   I(max)
-3.6V     330uA      290uA      330uA
-1.27V    2.011mA    1.347mA    2.56mA
-1.05V    4.628mA    2.191mA    7.616mA
-940mV    9.591mA    3.262mA    21.02mA
-830mV    22.24mA    5.683mA    36mA
-720mV    28.46mA    11.34mA    35.87mA
-610mV    25.92mA    17.01mA    32.61mA
-500mV    21.74mA    15.5mA     27.75mA
820mV     -29.79mA   -20.52mA   -39.2mA
2.03V     -54.53mA   -36.77mA   -72.89mA
3.02V     -60.23mA   -39.71mA   -81.88mA
7.2V      -70.9mA    -46.86mA   -95.92mA
[GND_clamp]
|Voltage   I(typ)   I(min)   I(max)
-3.6V     -10.99A    -11.14A    -10.93A
-1.18V    -1.033A    -1.378A    -850.8mA
-1.07V    -607mA     -947.1mA   -431.4mA
-960mV    -236.8mA   -543mA     -106.4mA
-850mV    -31.63mA   -206.7mA   -14.18mA
-740mV    -5.424mA   -29mA      -7.092mA
-630mV    -2.275mA   -2.653mA   -3.283mA
-410mV    -62.05uA   -83.52uA   -82.04uA
7.2V      0A         0A         0A
[POWER_clamp]
|Voltage   I(typ)   I(min)   I(max)
-3.6V     3.491A     3.319A     3.949A
-1.16V    368.2mA    410.8mA    372.9mA
-1.05V    234.5mA    290.2mA    214.3mA
-940mV    110.2mA    175.6mA    75.85mA
-830mV    28.53mA    79.02mA    17.73mA
-720mV    5.671mA    25.66mA    7.515mA
-610mV    1.49mA     4.301mA    2.636mA
-500mV    198.2uA    300.8uA    424.4uA
-390mV    9.667uA    18.86uA    16.14uA
7.2V      0A         0A         0A
[Ramp]
| variable   typ   min   max
dV/dt_r  1.3153/0.2568n   1.0150/0.4739n   1.5740/0.1691n
dV/dt_f  1.1557/0.2470n   0.7745/0.3764n   1.4570/0.1816n
R_load = 58.0000
[Rising Waveform]
R_fixture= 58.0000
V_fixture= 0.0
V_fixture_min= 0.0
V_fixture_max= 0.0
|time   V(typ)   V(min)   V(max)
0s        4.579nV    4.136nV    48.47nV
694.5ps   -6.129mV   181.2uV    52.96mV
784.7ps   -10.63mV   -614.4uV   420.8mV
970ps     84.98mV    -2.889mV   2.115V
1.074ns   403.7mV    -4.494mV   2.399V
1.248ns   1.447V     -9.577mV   2.548V
1.544ns   2.034V     109.7mV    2.609V
2.006ns   2.169V     1.157V     2.622V
2.412ns   2.188V     1.528V     2.623V
5.5ns     2.192V     1.692V     2.623V
[Rising Waveform]
R_fixture= 58.0000
V_fixture= 3.3000
V_fixture_min= 3.0000
V_fixture_max= 3.6000
|time   V(typ)   V(min)   V(max)
0s        1.374V     1.709V     1.172V
579.6ps   1.38V      1.695V     1.357V
674.9ps   1.442V     1.688V     1.827V
820.3ps   1.703V     1.691V     3.35V
907.1ps   2.042V     1.709V     3.562V
1.084ns   3.088V     1.804V     3.584V
1.207ns   3.269V     1.935V     3.591V
1.625ns   3.293V     2.831V     3.599V
1.793ns   3.296V     2.972V     3.599V
5.5ns     3.3V       3V         3.6V
[Falling Waveform]
R_fixture= 58.0000
V_fixture= 0.0
V_fixture_min= 0.0
V_fixture_max= 0.0
|time   V(typ)   V(min)   V(max)
0s        2.192V     1.692V     2.623V
723.6ps   2.194V     1.692V     2.563V
806.9ps   2.197V     1.692V     1.993V
925.3ps   2.188V     1.692V     327.8mV
1.023ns   2.112V     1.692V     21.19mV
1.267ns   284.3mV    1.697V     2.337mV
1.38ns    23.41mV    1.7V       1.215mV
1.713ns   2.056mV    1.491V     311.3uV
2.114ns   403.1uV    33.38mV    148.9uV
5.5ns     1.942uV    20.98uV    2.505uV
[Falling Waveform]
R_fixture= 58.0000
V_fixture= 3.3000
V_fixture_min= 3.0000
V_fixture_max= 3.6000
|time   V(typ)   V(min)   V(max)
0s        3.3V       3V         3.6V
735.7ps   3.299V     3V         3.606V
883.6ps   3.305V     3V         3.015V
1.067ns   3.288V     3V         1.559V
1.263ns   2.694V     2.999V     1.234V
1.472ns   1.719V     3.004V     1.187V
1.787ns   1.429V     2.947V     1.174V
2.244ns   1.38V      2.046V     1.172V
2.56ns    1.375V     1.804V     1.172V
5.5ns     1.374V     1.709V     1.172V
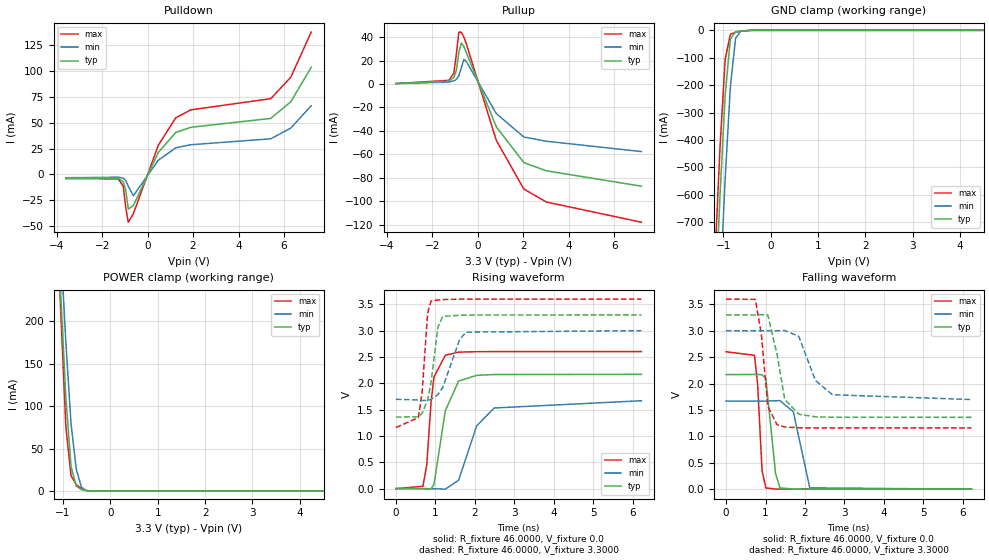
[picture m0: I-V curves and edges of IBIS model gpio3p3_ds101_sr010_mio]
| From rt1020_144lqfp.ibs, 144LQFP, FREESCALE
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[Model] gpio3p3_ds101_sr010_mio
|   Model gpio3p3_ds101_sr010_mio
| This model was characterised for following simulation conditions:
| External (pad) voltage:
|   - Typ: 3.3V,   - Min: 3.0V,   - Max: 3.6V
| Library cells for typ/min/max conditions are connected as defined below:
|  pad - External Pad
|  ipp_do - Core Input
|  ipp_obe - Output Buffer Enable
|  esd_boost - ovdd
|  ipp_dse0 - vddi
|  ipp_dse1 - vssi
|  ipp_dse2 - vddi
|  ipp_fsel0 - vssi
|  ipp_fsel1 - vddi
|  ipp_ina - ipp_ina
|  ipp_ind - ipp_ind
|  ipp_pwr_stable - vddi
|  ipp_sre - vssi
|  ovdd - ovdd
|  ovss - ovss
|  vddi - vddi
|  vssi - vssi
| All other pins connected to ground
Model_type I/O
Polarity   Non-Inverting
Enable   Active-High
Vinl =   0.9900V
Vinh =   2.3100V
Vmeas =  1.6500V
Cref =   0.0F
Rref =   46.0000
Vref =   1.6500V
C_comp   1.2179pF   1.1833pF   1.2636pF
|C_comp_pullup   0.6043pF   0.6190pF   0.5909pF
|C_comp_pulldown   0.5474pF   0.5788pF   0.5258pF
[Model Spec]
| variable   typ   min   max
Vinh   2.3100V   2.1000V   2.5200V
Vinl   0.9900V   0.9000V   1.0800V
S_overshoot_high   3.3000V   3.0000V   3.6000V
S_overshoot_low   0.0V   0.0V   0.0V
Vmeas   1.6500V   1.5000V   1.8000V
Vref   1.6500V   1.5000V   1.8000V
Cref   0.0F   0.0F   0.0F
Rref   46.0000   46.0000   46.0000
[Temperature Range]   25.0000   0.1050k   -20.0000
[Voltage Range]   3.3000V   3.0000V   3.6000V
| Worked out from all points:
|   slope of the pulldown table from 0 to 0.495 V, typ, clamps not added: 22.4 ohm
|   slope of the pullup table from 0 to 0.495 V, typ, clamps not added: 20.9 ohm
|   GND clamp passes 1 mA (typ) near -0.54 V on its own axis
|   POWER clamp passes 1 mA (typ) near -0.57 V on its own axis
|   rising waveform, R_fixture 46.0000, V_fixture 0.0: 20-80 % time 255ps typ, 482ps min, 165ps max; typ from 0 V to 2.17 V
|   rising waveform, R_fixture 46.0000, V_fixture 3.3000: 20-80 % time 210ps typ, 354ps min, 138ps max; typ from 1.36 V to 3.3 V
|   falling waveform, R_fixture 46.0000, V_fixture 0.0: 20-80 % time 134ps typ, 200ps min, 106ps max; typ from 2.17 V to 0 V
|   falling waveform, R_fixture 46.0000, V_fixture 3.3000: 20-80 % time 252ps typ, 418ps min, 177ps max; typ from 3.3 V to 1.36 V
[Pulldown]
|Voltage   I(typ)   I(min)   I(max)
-3.6V     -3.8mA     -3.27mA    -4.06mA
-1.29V    -3.686mA   -2.776mA   -4.372mA
-1.07V    -7.35mA    -3.755mA   -11.74mA
-960mV    -15.76mA   -6.049mA   -32.51mA
-850mV    -33.56mA   -11.6mA    -46.37mA
-630mV    -30.38mA   -20.68mA   -38.3mA
470mV     21.25mA    13.65mA    28.17mA
1.24V     40.59mA    25.73mA    54.86mA
1.9V      45.61mA    28.71mA    62.5mA
5.42V     54.24mA    34.46mA    73.38mA
6.3V      70.32mA    44.85mA    94.13mA
7.2V      103.8mA    66.49mA    137.9mA
[Pullup]
|Voltage   I(typ)   I(min)   I(max)
-3.6V     400uA      360uA      410uA
-1.27V    2.464mA    1.652mA    3.136mA
-1.05V    5.66mA     2.688mA    9.303mA
-940mV    11.71mA    4.002mA    25.69mA
-830mV    27.31mA    6.972mA    44.28mA
-720mV    35.03mA    13.93mA    44.13mA
-610mV    31.9mA     20.94mA    40.12mA
-500mV    26.75mA    19.08mA    34.14mA
820mV     -36.63mA   -25.24mA   -48.19mA
2.03V     -67.01mA   -45.18mA   -89.56mA
3.02V     -73.98mA   -48.78mA   -100.6mA
7.2V      -87.11mA   -57.58mA   -117.8mA
[GND_clamp]
|Voltage   I(typ)   I(min)   I(max)
-3.6V     -10.99A    -11.14A    -10.93A
-1.18V    -1.033A    -1.378A    -850.8mA
-1.07V    -607mA     -947.1mA   -431.4mA
-960mV    -236.8mA   -543mA     -106.4mA
-850mV    -31.63mA   -206.7mA   -14.18mA
-740mV    -5.424mA   -29mA      -7.092mA
-630mV    -2.275mA   -2.653mA   -3.283mA
-410mV    -62.05uA   -83.52uA   -82.04uA
7.2V      0A         0A         0A
[POWER_clamp]
|Voltage   I(typ)   I(min)   I(max)
-3.6V     3.491A     3.319A     3.949A
-1.16V    368.2mA    410.8mA    372.9mA
-1.05V    234.5mA    290.2mA    214.3mA
-940mV    110.2mA    175.6mA    75.85mA
-830mV    28.53mA    79.02mA    17.73mA
-720mV    5.671mA    25.66mA    7.515mA
-610mV    1.49mA     4.301mA    2.636mA
-500mV    198.2uA    300.8uA    424.4uA
-390mV    9.667uA    18.86uA    16.14uA
7.2V      0A         0A         0A
[Ramp]
| variable   typ   min   max
dV/dt_r  1.3018/0.2553n   1.0011/0.4815n   1.5612/0.1654n
dV/dt_f  1.1638/0.2524n   0.7818/0.4177n   1.4640/0.1769n
R_load = 46.0000
[Rising Waveform]
R_fixture= 46.0000
V_fixture= 0.0
V_fixture_min= 0.0
V_fixture_max= 0.0
|time   V(typ)   V(min)   V(max)
0s        3.606nV    3.27nV     38.16nV
684.6ps   -6.115mV   216uV      43.68mV
781.2ps   -10.76mV   -632.8uV   447.2mV
889.4ps   -3.562mV   -1.92mV    1.63V
963.8ps   76.39mV    -2.898mV   2.121V
1.252ns   1.48V      -9.663mV   2.533V
1.588ns   2.043V     157.7mV    2.592V
2.046ns   2.151V     1.191V     2.601V
2.489ns   2.167V     1.531V     2.602V
6.22ns    2.17V      1.669V     2.602V
[Rising Waveform]
R_fixture= 46.0000
V_fixture= 3.3000
V_fixture_min= 3.0000
V_fixture_max= 3.6000
|time   V(typ)   V(min)   V(max)
0s        1.36V      1.697V     1.16V
568.3ps   1.364V     1.683V     1.348V
662ps     1.427V     1.675V     1.815V
803.8ps   1.684V     1.676V     3.338V
889.9ps   2.019V     1.694V     3.563V
1.063ns   3.061V     1.786V     3.583V
1.183ns   3.269V     1.913V     3.59V
1.613ns   3.293V     2.83V      3.599V
1.775ns   3.296V     2.972V     3.599V
6.22ns    3.3V       3V         3.6V
[Falling Waveform]
R_fixture= 46.0000
V_fixture= 0.0
V_fixture_min= 0.0
V_fixture_max= 0.0
|time   V(typ)   V(min)   V(max)
0s        2.17V      1.669V     2.602V
720.4ps   2.172V     1.669V     2.534V
799.5ps   2.175V     1.669V     1.993V
913.3ps   2.165V     1.669V     347.5mV
1.008ns   2.098V     1.669V     22.91mV
1.256ns   290.2mV    1.674V     2.576mV
1.367ns   23.77mV    1.677V     1.401mV
1.705ns   2.303mV    1.466V     325.3uV
2.122ns   461.7uV    24.55mV    122.6uV
6.22ns    -449.6nV   8.424uV    866.8nV
[Falling Waveform]
R_fixture= 46.0000
V_fixture= 3.3000
V_fixture_min= 3.0000
V_fixture_max= 3.6000
|time   V(typ)   V(min)   V(max)
0s        3.3V       3V         3.6V
741.6ps   3.299V     3V         3.594V
894.2ps   3.306V     3V         2.937V
1.058ns   3.301V     3V         1.57V
1.294ns   2.546V     3V         1.218V
1.487ns   1.7V       3.005V     1.178V
1.844ns   1.418V     2.892V     1.163V
2.268ns   1.37V      2.055V     1.16V
2.697ns   1.362V     1.788V     1.16V
6.22ns    1.36V      1.697V     1.16V
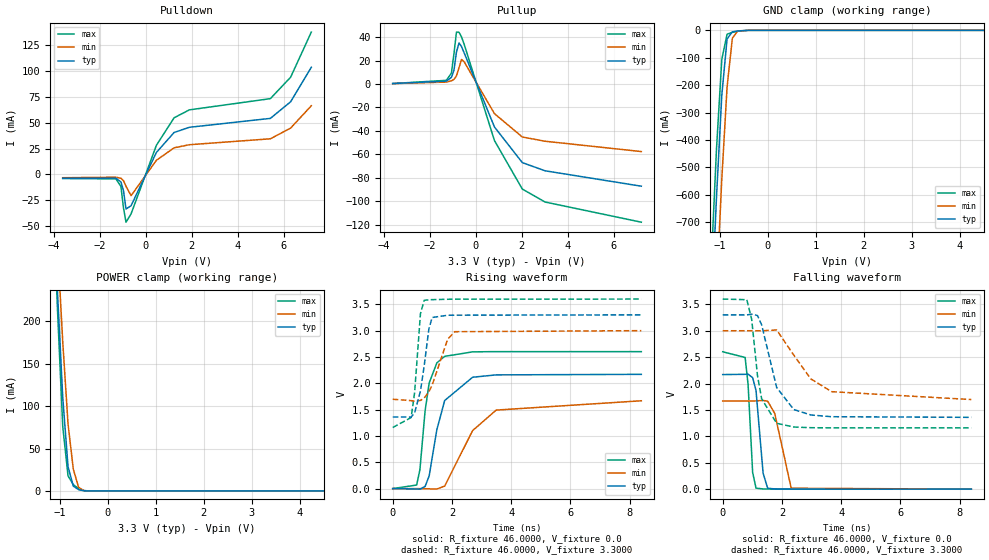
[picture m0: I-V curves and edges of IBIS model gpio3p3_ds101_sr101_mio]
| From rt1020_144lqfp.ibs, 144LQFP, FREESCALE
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[Model] gpio3p3_ds101_sr101_mio
|   Model gpio3p3_ds101_sr101_mio
| This model was characterised for following simulation conditions:
| External (pad) voltage:
|   - Typ: 3.3V,   - Min: 3.0V,   - Max: 3.6V
| Library cells for typ/min/max conditions are connected as defined below:
|  pad - External Pad
|  ipp_do - Core Input
|  ipp_obe - Output Buffer Enable
|  esd_boost - ovdd
|  ipp_dse0 - vddi
|  ipp_dse1 - vssi
|  ipp_dse2 - vddi
|  ipp_fsel0 - vddi
|  ipp_fsel1 - vssi
|  ipp_ina - ipp_ina
|  ipp_ind - ipp_ind
|  ipp_pwr_stable - vddi
|  ipp_sre - vddi
|  ovdd - ovdd
|  ovss - ovss
|  vddi - vddi
|  vssi - vssi
| All other pins connected to ground
Model_type I/O
Polarity   Non-Inverting
Enable   Active-High
Vinl =   0.9900V
Vinh =   2.3100V
Vmeas =  1.6500V
Cref =   0.0F
Rref =   46.0000
Vref =   1.6500V
C_comp   1.2178pF   1.1833pF   1.2636pF
|C_comp_pullup   0.6042pF   0.6189pF   0.5908pF
|C_comp_pulldown   0.5474pF   0.5788pF   0.5258pF
[Model Spec]
| variable   typ   min   max
Vinh   2.3100V   2.1000V   2.5200V
Vinl   0.9900V   0.9000V   1.0800V
S_overshoot_high   3.3000V   3.0000V   3.6000V
S_overshoot_low   0.0V   0.0V   0.0V
Vmeas   1.6500V   1.5000V   1.8000V
Vref   1.6500V   1.5000V   1.8000V
Cref   0.0F   0.0F   0.0F
Rref   46.0000   46.0000   46.0000
[Temperature Range]   25.0000   0.1050k   -20.0000
[Voltage Range]   3.3000V   3.0000V   3.6000V
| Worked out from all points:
|   slope of the pulldown table from 0 to 0.495 V, typ, clamps not added: 22.4 ohm
|   slope of the pullup table from 0 to 0.495 V, typ, clamps not added: 20.9 ohm
|   GND clamp passes 1 mA (typ) near -0.54 V on its own axis
|   POWER clamp passes 1 mA (typ) near -0.57 V on its own axis
|   rising waveform, R_fixture 46.0000, V_fixture 0.0: 20-80 % time 504ps typ, 982ps min, 311ps max; typ from 0 V to 2.17 V
|   rising waveform, R_fixture 46.0000, V_fixture 3.3000: 20-80 % time 287ps typ, 463ps min, 197ps max; typ from 1.36 V to 3.3 V
|   falling waveform, R_fixture 46.0000, V_fixture 0.0: 20-80 % time 185ps typ, 272ps min, 142ps max; typ from 2.17 V to 0 V
|   falling waveform, R_fixture 46.0000, V_fixture 3.3000: 20-80 % time 576ps typ, 1.03ns min, 342ps max; typ from 3.3 V to 1.36 V
[Pulldown]
|Voltage   I(typ)   I(min)   I(max)
-3.6V     -3.8mA     -3.27mA    -4.06mA
-1.29V    -3.686mA   -2.776mA   -4.372mA
-1.07V    -7.35mA    -3.755mA   -11.74mA
-960mV    -15.76mA   -6.049mA   -32.51mA
-850mV    -33.56mA   -11.6mA    -46.37mA
-630mV    -30.38mA   -20.68mA   -38.3mA
470mV     21.25mA    13.65mA    28.17mA
1.24V     40.59mA    25.73mA    54.86mA
1.9V      45.61mA    28.71mA    62.5mA
5.42V     54.24mA    34.46mA    73.38mA
6.3V      70.32mA    44.85mA    94.13mA
7.2V      103.8mA    66.49mA    137.9mA
[Pullup]
|Voltage   I(typ)   I(min)   I(max)
-3.6V     400uA      360uA      410uA
-1.27V    2.464mA    1.652mA    3.136mA
-1.05V    5.66mA     2.688mA    9.303mA
-940mV    11.71mA    4.002mA    25.69mA
-830mV    27.31mA    6.972mA    44.28mA
-720mV    35.03mA    13.93mA    44.13mA
-610mV    31.9mA     20.94mA    40.12mA
-500mV    26.75mA    19.08mA    34.14mA
820mV     -36.63mA   -25.24mA   -48.19mA
2.03V     -67.01mA   -45.18mA   -89.56mA
3.02V     -73.98mA   -48.78mA   -100.6mA
7.2V      -87.11mA   -57.58mA   -117.8mA
[GND_clamp]
|Voltage   I(typ)   I(min)   I(max)
-3.6V     -10.99A    -11.14A    -10.93A
-1.18V    -1.033A    -1.378A    -850.8mA
-1.07V    -607mA     -947.1mA   -431.4mA
-960mV    -236.8mA   -543mA     -106.4mA
-850mV    -31.63mA   -206.7mA   -14.18mA
-740mV    -5.424mA   -29mA      -7.092mA
-630mV    -2.275mA   -2.653mA   -3.283mA
-410mV    -62.05uA   -83.52uA   -82.05uA
7.2V      0A         0A         0A
[POWER_clamp]
|Voltage   I(typ)   I(min)   I(max)
-3.6V     3.491A     3.319A     3.949A
-1.16V    368.2mA    410.8mA    372.9mA
-1.05V    234.5mA    290.2mA    214.3mA
-940mV    110.2mA    175.6mA    75.85mA
-830mV    28.53mA    79.02mA    17.73mA
-720mV    5.671mA    25.66mA    7.515mA
-610mV    1.49mA     4.301mA    2.636mA
-500mV    198.2uA    300.8uA    424.4uA
-390mV    9.667uA    18.86uA    16.14uA
7.2V      0A         0A         0A
[Ramp]
| variable   typ   min   max
dV/dt_r  1.3019/0.5036n   1.0009/0.9822n   1.5612/0.3115n
dV/dt_f  1.1638/0.5758n   0.7816/1.0283n   1.4640/0.3421n
R_load = 46.0000
[Rising Waveform]
R_fixture= 46.0000
V_fixture= 0.0
V_fixture_min= 0.0
V_fixture_max= 0.0
|time   V(typ)   V(min)   V(max)
0s        3.606nV    3.248nV    38.16nV
807.5ps   -7.269mV   -285.9uV   66.93mV
918.2ps   -11.03mV   -1.319mV   359.4mV
1.092ns   40.43mV    -3.135mV   1.472V
1.23ns    238.8mV    -5.148mV   2.005V
1.49ns    1.12V      -8.393mV   2.388V
1.754ns   1.673V     47.79mV    2.512V
2.697ns   2.115V     1.102V     2.597V
3.492ns   2.16V      1.491V     2.602V
8.39ns    2.17V      1.668V     2.602V
[Rising Waveform]
R_fixture= 46.0000
V_fixture= 3.3000
V_fixture_min= 3.0000
V_fixture_max= 3.6000
|time   V(typ)   V(min)   V(max)
0s        1.36V      1.697V     1.16V
622ps     1.359V     1.671V     1.349V
740.1ps   1.44V      1.659V     1.828V
936.8ps   1.853V     1.674V     3.324V
1.062ns   2.332V     1.72V      3.576V
1.221ns   3.031V     1.837V     3.586V
1.33ns    3.25V      1.964V     3.589V
1.854ns   3.292V     2.836V     3.596V
2.092ns   3.294V     2.98V      3.598V
8.39ns    3.3V       3V         3.6V
[Falling Waveform]
R_fixture= 46.0000
V_fixture= 0.0
V_fixture_min= 0.0
V_fixture_max= 0.0
|time   V(typ)   V(min)   V(max)
0s        2.17V      1.669V     2.602V
757.1ps   2.175V     1.669V     2.494V
857.3ps   2.177V     1.669V     1.975V
1.01ns    2.112V     1.67V      318.6mV
1.124ns   1.868V     1.672V     19.45mV
1.363ns   303.2mV    1.68V      4.446mV
1.518ns   16.85mV    1.665V     2.989mV
1.757ns   4.834mV    1.433V     1.69mV
2.312ns   1.634mV    17.75mV    437.8uV
8.39ns    358.9nV    3.291uV    156.3nV
[Falling Waveform]
R_fixture= 46.0000
V_fixture= 3.3000
V_fixture_min= 3.0000
V_fixture_max= 3.6000
|time   V(typ)   V(min)   V(max)
0s        3.3V       3V         3.6V
814.3ps   3.3V       3V         3.588V
978.5ps   3.315V     3V         3.213V
1.174ns   3.288V     2.999V     2.148V
1.315ns   3.11V      2.999V     1.71V
1.821ns   1.925V     3.015V     1.247V
2.398ns   1.508V     2.539V     1.177V
2.974ns   1.405V     2.088V     1.164V
3.675ns   1.372V     1.846V     1.161V
8.39ns    1.36V      1.697V     1.16V
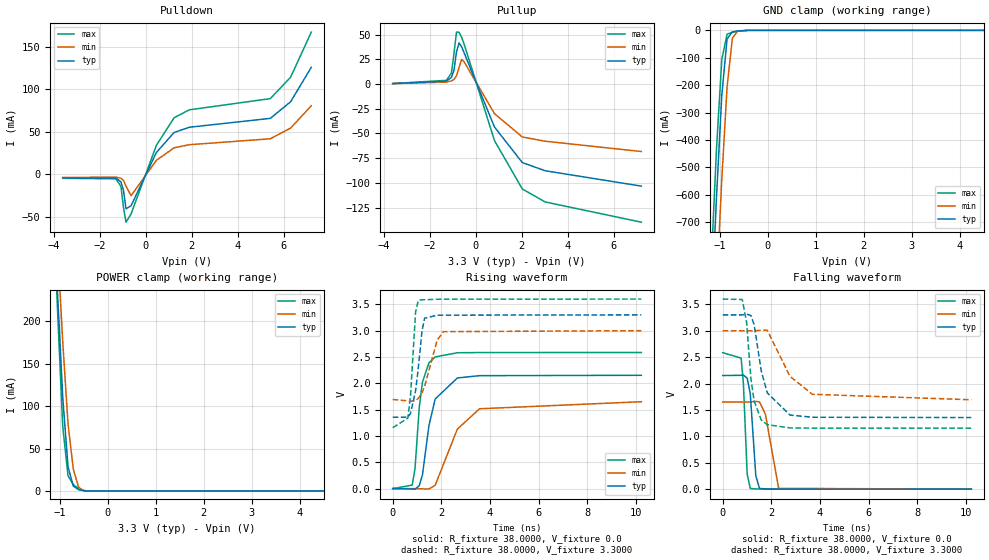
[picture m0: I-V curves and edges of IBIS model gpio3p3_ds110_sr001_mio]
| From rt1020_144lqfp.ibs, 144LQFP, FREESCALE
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[Model] gpio3p3_ds110_sr001_mio
|   Model gpio3p3_ds110_sr001_mio
| This model was characterised for following simulation conditions:
| External (pad) voltage:
|   - Typ: 3.3V,   - Min: 3.0V,   - Max: 3.6V
| Library cells for typ/min/max conditions are connected as defined below:
|  pad - External Pad
|  ipp_do - Core Input
|  ipp_obe - Output Buffer Enable
|  esd_boost - ovdd
|  ipp_dse0 - vssi
|  ipp_dse1 - vddi
|  ipp_dse2 - vddi
|  ipp_fsel0 - vddi
|  ipp_fsel1 - vssi
|  ipp_ina - ipp_ina
|  ipp_ind - ipp_ind
|  ipp_pwr_stable - vddi
|  ipp_sre - vssi
|  ovdd - ovdd
|  ovss - ovss
|  vddi - vddi
|  vssi - vssi
| All other pins connected to ground
Model_type I/O
Polarity   Non-Inverting
Enable   Active-High
Vinl =   0.9900V
Vinh =   2.3100V
Vmeas =  1.6500V
Cref =   0.0F
Rref =   38.0000
Vref =   1.6500V
C_comp   1.2178pF   1.1833pF   1.2636pF
|C_comp_pullup   0.6042pF   0.6189pF   0.5908pF
|C_comp_pulldown   0.5474pF   0.5788pF   0.5258pF
[Model Spec]
| variable   typ   min   max
Vinh   2.3100V   2.1000V   2.5200V
Vinl   0.9900V   0.9000V   1.0800V
S_overshoot_high   3.3000V   3.0000V   3.6000V
S_overshoot_low   0.0V   0.0V   0.0V
Vmeas   1.6500V   1.5000V   1.8000V
Vref   1.6500V   1.5000V   1.8000V
Cref   0.0F   0.0F   0.0F
Rref   38.0000   38.0000   38.0000
[Temperature Range]   25.0000   0.1050k   -20.0000
[Voltage Range]   3.3000V   3.0000V   3.6000V
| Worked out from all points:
|   slope of the pulldown table from 0 to 0.495 V, typ, clamps not added: 18.4 ohm
|   slope of the pullup table from 0 to 0.495 V, typ, clamps not added: 17.6 ohm
|   GND clamp passes 1 mA (typ) near -0.54 V on its own axis
|   POWER clamp passes 1 mA (typ) near -0.57 V on its own axis
|   rising waveform, R_fixture 38.0000, V_fixture 0.0: 20-80 % time 480ps typ, 926ps min, 298ps max; typ from 0 V to 2.15 V
|   rising waveform, R_fixture 38.0000, V_fixture 3.3000: 20-80 % time 280ps typ, 455ps min, 191ps max; typ from 1.36 V to 3.3 V
|   falling waveform, R_fixture 38.0000, V_fixture 0.0: 20-80 % time 176ps typ, 260ps min, 136ps max; typ from 2.15 V to 0 V
|   falling waveform, R_fixture 38.0000, V_fixture 3.3000: 20-80 % time 518ps typ, 909ps min, 311ps max; typ from 3.3 V to 1.36 V
[Pulldown]
|Voltage   I(typ)   I(min)   I(max)
-3.6V     -4.3mA     -3.7mA     -4.6mA
-1.29V    -4.333mA   -3.193mA   -5.198mA
-1.07V    -8.777mA   -4.485mA   -14.02mA
-960mV    -18.76mA   -7.185mA   -39.09mA
-850mV    -40.59mA   -13.79mA   -56.24mA
-630mV    -36.88mA   -25.09mA   -46.47mA
470mV     25.8mA     16.59mA    34.2mA
1.24V     49.32mA    31.28mA    66.64mA
1.9V      55.43mA    34.9mA     75.94mA
5.42V     65.92mA    41.89mA    89.15mA
6.3V      85.43mA    54.51mA    114.3mA
7.2V      126mA      80.78mA    167.4mA
[Pullup]
|Voltage   I(typ)   I(min)   I(max)
-3.6V     480uA      430uA      490uA
-1.27V    2.916mA    1.958mA    3.713mA
-1.05V    6.695mA    3.185mA    11mA
-940mV    13.85mA    4.743mA    30.4mA
-830mV    32.4mA     8.263mA    52.57mA
-720mV    41.6mA     16.53mA    52.38mA
-610mV    37.87mA    24.88mA    47.61mA
-500mV    31.75mA    22.65mA    40.51mA
820mV     -43.47mA   -29.95mA   -57.17mA
2.03V     -79.48mA   -53.58mA   -106.2mA
3.02V     -87.73mA   -57.84mA   -119.3mA
7.2V      -103.3mA   -68.29mA   -139.8mA
[GND_clamp]
|Voltage   I(typ)   I(min)   I(max)
-3.6V     -10.99A    -11.14A    -10.93A
-1.18V    -1.033A    -1.378A    -850.8mA
-1.07V    -607mA     -947.1mA   -431.4mA
-960mV    -236.8mA   -543mA     -106.4mA
-850mV    -31.63mA   -206.7mA   -14.18mA
-740mV    -5.424mA   -29mA      -7.092mA
-630mV    -2.275mA   -2.653mA   -3.283mA
-410mV    -62.05uA   -83.52uA   -82.05uA
7.2V      0A         0A         0A
[POWER_clamp]
|Voltage   I(typ)   I(min)   I(max)
-3.6V     3.491A     3.319A     3.949A
-1.16V    368.2mA    410.8mA    372.9mA
-1.05V    234.5mA    290.2mA    214.3mA
-940mV    110.2mA    175.6mA    75.85mA
-830mV    28.53mA    79.02mA    17.73mA
-720mV    5.671mA    25.66mA    7.515mA
-610mV    1.49mA     4.301mA    2.636mA
-500mV    198.2uA    300.8uA    424.4uA
-390mV    9.667uA    18.86uA    16.14uA
7.2V      0A         0A         0A
[Ramp]
| variable   typ   min   max
dV/dt_r  1.2910/0.4796n   0.9900/0.9263n   1.5507/0.2979n
dV/dt_f  1.1667/0.5179n   0.7844/0.9086n   1.4664/0.3112n
R_load = 38.0000
[Rising Waveform]
R_fixture= 38.0000
V_fixture= 0.0
V_fixture_min= 0.0
V_fixture_max= 0.0
|time   V(typ)   V(min)   V(max)
0s        2.972nV    2.696nV    31.46nV
800.7ps   -7.028mV   -265.9uV   65.93mV
920ps     -11.15mV   -1.376mV   389.2mV
1.091ns   53.18mV    -3.159mV   1.534V
1.222ns   255.4mV    -5.125mV   2.021V
1.491ns   1.196V     -7.92mV    2.388V
1.746ns   1.701V     61.33mV    2.501V
2.66ns    2.101V     1.13V      2.58V
3.572ns   2.145V     1.516V     2.584V
10.23ns   2.152V     1.65V      2.585V
[Rising Waveform]
R_fixture= 38.0000
V_fixture= 3.3000
V_fixture_min= 3.0000
V_fixture_max= 3.6000
|time   V(typ)   V(min)   V(max)
0s        1.356V     1.693V     1.156V
622.4ps   1.355V     1.667V     1.337V
733.7ps   1.429V     1.655V     1.769V
942ps     1.859V     1.673V     3.357V
1.054ns   2.293V     1.714V     3.575V
1.205ns   2.99V      1.82V      3.586V
1.311ns   3.236V     1.938V     3.588V
1.831ns   3.292V     2.82V      3.596V
2.083ns   3.294V     2.981V     3.598V
10.23ns   3.3V       3V         3.6V
[Falling Waveform]
R_fixture= 38.0000
V_fixture= 0.0
V_fixture_min= 0.0
V_fixture_max= 0.0
|time   V(typ)   V(min)   V(max)
0s        2.152V     1.65V      2.585V
757.8ps   2.156V     1.65V      2.482V
851.6ps   2.16V      1.65V      2V
1.007ns   2.104V     1.651V     284.1mV
1.134ns   1.81V      1.653V     13.5mV
1.362ns   253.4mV    1.662V     4.281mV
1.514ns   14.28mV    1.651V     2.847mV
1.756ns   4.638mV    1.421V     1.54mV
2.302ns   1.5mV      15.39mV    358.8uV
10.23ns   78.2nV     215.8nV    60.58nV
[Falling Waveform]
R_fixture= 38.0000
V_fixture= 3.3000
V_fixture_min= 3.0000
V_fixture_max= 3.6000
|time   V(typ)   V(min)   V(max)
0s        3.3V       3V         3.6V
804.4ps   3.3V       3V         3.591V
982.6ps   3.316V     3V         3.161V
1.16ns    3.288V     2.999V     2.095V
1.293ns   3.117V     2.999V     1.671V
1.585ns   2.241V     3.01V      1.311V
1.834ns   1.823V     3.01V      1.221V
2.769ns   1.403V     2.136V     1.16V
3.691ns   1.362V     1.797V     1.156V
10.23ns   1.356V     1.693V     1.156V
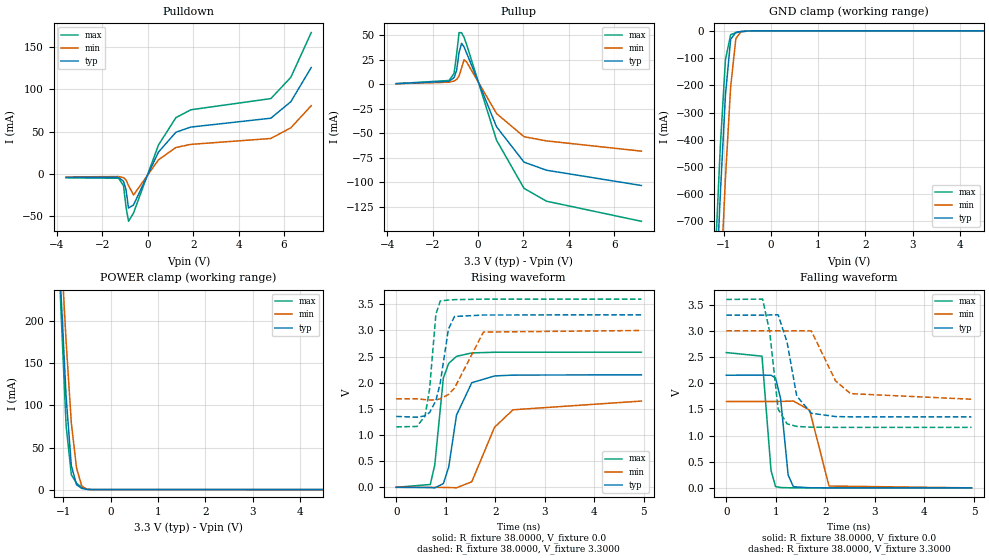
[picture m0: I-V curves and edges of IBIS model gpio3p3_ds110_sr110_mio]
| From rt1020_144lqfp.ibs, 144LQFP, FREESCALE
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[Model] gpio3p3_ds110_sr110_mio
|   Model gpio3p3_ds110_sr110_mio
| This model was characterised for following simulation conditions:
| External (pad) voltage:
|   - Typ: 3.3V,   - Min: 3.0V,   - Max: 3.6V
| Library cells for typ/min/max conditions are connected as defined below:
|  pad - External Pad
|  ipp_do - Core Input
|  ipp_obe - Output Buffer Enable
|  esd_boost - ovdd
|  ipp_dse0 - vssi
|  ipp_dse1 - vddi
|  ipp_dse2 - vddi
|  ipp_fsel0 - vssi
|  ipp_fsel1 - vddi
|  ipp_ina - ipp_ina
|  ipp_ind - ipp_ind
|  ipp_pwr_stable - vddi
|  ipp_sre - vddi
|  ovdd - ovdd
|  ovss - ovss
|  vddi - vddi
|  vssi - vssi
| All other pins connected to ground
Model_type I/O
Polarity   Non-Inverting
Enable   Active-High
Vinl =   0.9900V
Vinh =   2.3100V
Vmeas =  1.6500V
Cref =   0.0F
Rref =   38.0000
Vref =   1.6500V
C_comp   1.2179pF   1.1833pF   1.2636pF
|C_comp_pullup   0.6043pF   0.6190pF   0.5909pF
|C_comp_pulldown   0.5474pF   0.5788pF   0.5258pF
[Model Spec]
| variable   typ   min   max
Vinh   2.3100V   2.1000V   2.5200V
Vinl   0.9900V   0.9000V   1.0800V
S_overshoot_high   3.3000V   3.0000V   3.6000V
S_overshoot_low   0.0V   0.0V   0.0V
Vmeas   1.6500V   1.5000V   1.8000V
Vref   1.6500V   1.5000V   1.8000V
Cref   0.0F   0.0F   0.0F
Rref   38.0000   38.0000   38.0000
[Temperature Range]   25.0000   0.1050k   -20.0000
[Voltage Range]   3.3000V   3.0000V   3.6000V
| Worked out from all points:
|   slope of the pulldown table from 0 to 0.495 V, typ, clamps not added: 18.4 ohm
|   slope of the pullup table from 0 to 0.495 V, typ, clamps not added: 17.6 ohm
|   GND clamp passes 1 mA (typ) near -0.54 V on its own axis
|   POWER clamp passes 1 mA (typ) near -0.57 V on its own axis
|   rising waveform, R_fixture 38.0000, V_fixture 0.0: 20-80 % time 244ps typ, 457ps min, 157ps max; typ from 0 V to 2.15 V
|   rising waveform, R_fixture 38.0000, V_fixture 3.3000: 20-80 % time 203ps typ, 347ps min, 134ps max; typ from 1.36 V to 3.3 V
|   falling waveform, R_fixture 38.0000, V_fixture 0.0: 20-80 % time 126ps typ, 187ps min, 99.8ps max; typ from 2.15 V to 0 V
|   falling waveform, R_fixture 38.0000, V_fixture 3.3000: 20-80 % time 229ps typ, 364ps min, 165ps max; typ from 3.3 V to 1.36 V
[Pulldown]
|Voltage   I(typ)   I(min)   I(max)
-3.6V     -4.3mA     -3.7mA     -4.6mA
-1.29V    -4.333mA   -3.193mA   -5.198mA
-1.07V    -8.777mA   -4.485mA   -14.02mA
-960mV    -18.76mA   -7.185mA   -39.09mA
-850mV    -40.59mA   -13.79mA   -56.24mA
-630mV    -36.88mA   -25.09mA   -46.47mA
470mV     25.8mA     16.59mA    34.2mA
1.24V     49.32mA    31.28mA    66.64mA
1.9V      55.43mA    34.9mA     75.94mA
5.42V     65.92mA    41.89mA    89.15mA
6.3V      85.43mA    54.51mA    114.3mA
7.2V      126mA      80.78mA    167.4mA
[Pullup]
|Voltage   I(typ)   I(min)   I(max)
-3.6V     480uA      430uA      490uA
-1.27V    2.916mA    1.958mA    3.713mA
-1.05V    6.695mA    3.185mA    11mA
-940mV    13.85mA    4.743mA    30.4mA
-830mV    32.4mA     8.263mA    52.57mA
-720mV    41.6mA     16.53mA    52.38mA
-610mV    37.87mA    24.88mA    47.61mA
-500mV    31.75mA    22.65mA    40.51mA
820mV     -43.47mA   -29.95mA   -57.17mA
2.03V     -79.48mA   -53.58mA   -106.2mA
3.02V     -87.73mA   -57.84mA   -119.3mA
7.2V      -103.3mA   -68.29mA   -139.8mA
[GND_clamp]
|Voltage   I(typ)   I(min)   I(max)
-3.6V     -10.99A    -11.14A    -10.93A
-1.18V    -1.033A    -1.378A    -850.8mA
-1.07V    -607mA     -947.1mA   -431.4mA
-960mV    -236.8mA   -543mA     -106.4mA
-850mV    -31.63mA   -206.7mA   -14.18mA
-740mV    -5.424mA   -29mA      -7.092mA
-630mV    -2.275mA   -2.653mA   -3.283mA
-410mV    -62.05uA   -83.52uA   -82.04uA
7.2V      0A         0A         0A
[POWER_clamp]
|Voltage   I(typ)   I(min)   I(max)
-3.6V     3.491A     3.319A     3.949A
-1.16V    368.2mA    410.8mA    372.9mA
-1.05V    234.5mA    290.2mA    214.3mA
-940mV    110.2mA    175.6mA    75.85mA
-830mV    28.53mA    79.02mA    17.73mA
-720mV    5.671mA    25.66mA    7.515mA
-610mV    1.49mA     4.301mA    2.636mA
-500mV    198.2uA    300.8uA    424.4uA
-390mV    9.667uA    18.86uA    16.14uA
7.2V      0A         0A         0A
[Ramp]
| variable   typ   min   max
dV/dt_r  1.2910/0.2439n   0.9899/0.4575n   1.5507/0.1574n
dV/dt_f  1.1666/0.2293n   0.7844/0.3642n   1.4664/0.1651n
R_load = 38.0000
[Rising Waveform]
R_fixture= 38.0000
V_fixture= 0.0
V_fixture_min= 0.0
V_fixture_max= 0.0
|time   V(typ)   V(min)   V(max)
0s        2.972nV    2.696nV    31.46nV
688.7ps   -5.995mV   150.4uV    54.53mV
778.8ps   -10.43mV   -646uV     429mV
952.1ps   70.9mV     -2.729mV   2.093V
1.06ns    386mV      -4.323mV   2.37V
1.217ns   1.38V      -8.668mV   2.505V
1.526ns   2.001V     106.1mV    2.571V
1.985ns   2.13V      1.149V     2.584V
2.358ns   2.147V     1.483V     2.584V
4.95ns    2.152V     1.65V      2.585V
[Rising Waveform]
R_fixture= 38.0000
V_fixture= 3.3000
V_fixture_min= 3.0000
V_fixture_max= 3.6000
|time   V(typ)   V(min)   V(max)
0s        1.356V     1.693V     1.156V
419.1ps   1.341V     1.692V     1.164V
583.8ps   1.367V     1.677V     1.369V
674.5ps   1.432V     1.67V      1.883V
800.7ps   1.656V     1.673V     3.309V
888.6ps   1.991V     1.692V     3.564V
1.053ns   3.022V     1.775V     3.583V
1.177ns   3.268V     1.898V     3.59V
1.761ns   3.296V     2.97V      3.6V
4.95ns    3.3V       3V         3.6V
[Falling Waveform]
R_fixture= 38.0000
V_fixture= 0.0
V_fixture_min= 0.0
V_fixture_max= 0.0
|time   V(typ)   V(min)   V(max)
0s        2.152V     1.65V      2.585V
719.9ps   2.154V     1.65V      2.516V
902.7ps   2.151V     1.65V      332.1mV
993.3ps   2.101V     1.651V     24.48mV
1.096ns   1.703V     1.652V     6.559mV
1.248ns   245.1mV    1.655V     2.287mV
1.354ns   21.77mV    1.659V     1.198mV
1.682ns   2.101mV    1.485V     249.4uV
2.074ns   366.1uV    34.43mV    99.36uV
4.95ns    3.718uV    20.92uV    2.975uV
[Falling Waveform]
R_fixture= 38.0000
V_fixture= 3.3000
V_fixture_min= 3.0000
V_fixture_max= 3.6000
|time   V(typ)   V(min)   V(max)
0s        3.3V       3V         3.6V
731.9ps   3.299V     3V         3.606V
874.5ps   3.304V     3V         2.987V
1.046ns   3.307V     3V         1.505V
1.226ns   2.786V     2.999V     1.223V
1.421ns   1.755V     3.002V     1.174V
1.716ns   1.426V     2.999V     1.159V
2.205ns   1.362V     2.045V     1.156V
2.507ns   1.357V     1.8V       1.156V
4.95ns    1.356V     1.693V     1.156V
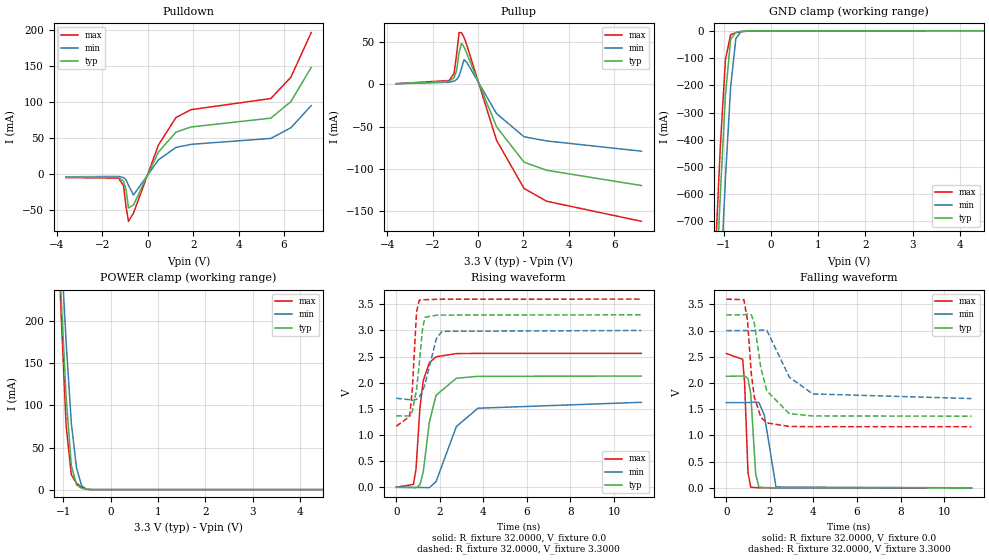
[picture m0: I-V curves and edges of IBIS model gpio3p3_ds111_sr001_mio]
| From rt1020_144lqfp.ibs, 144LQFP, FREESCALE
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[Model] gpio3p3_ds111_sr001_mio
|   Model gpio3p3_ds111_sr001_mio
| This model was characterised for following simulation conditions:
| External (pad) voltage:
|   - Typ: 3.3V,   - Min: 3.0V,   - Max: 3.6V
| Library cells for typ/min/max conditions are connected as defined below:
|  pad - External Pad
|  ipp_do - Core Input
|  ipp_obe - Output Buffer Enable
|  esd_boost - ovdd
|  ipp_dse0 - vddi
|  ipp_dse1 - vddi
|  ipp_dse2 - vddi
|  ipp_fsel0 - vddi
|  ipp_fsel1 - vssi
|  ipp_ina - ipp_ina
|  ipp_ind - ipp_ind
|  ipp_pwr_stable - vddi
|  ipp_sre - vssi
|  ovdd - ovdd
|  ovss - ovss
|  vddi - vddi
|  vssi - vssi
| All other pins connected to ground
Model_type I/O
Polarity   Non-Inverting
Enable   Active-High
Vinl =   0.9900V
Vinh =   2.3100V
Vmeas =  1.6500V
Cref =   0.0F
Rref =   32.0000
Vref =   1.6500V
C_comp   1.2178pF   1.1833pF   1.2636pF
|C_comp_pullup   0.6042pF   0.6189pF   0.5908pF
|C_comp_pulldown   0.5474pF   0.5788pF   0.5258pF
[Model Spec]
| variable   typ   min   max
Vinh   2.3100V   2.1000V   2.5200V
Vinl   0.9900V   0.9000V   1.0800V
S_overshoot_high   3.3000V   3.0000V   3.6000V
S_overshoot_low   0.0V   0.0V   0.0V
Vmeas   1.6500V   1.5000V   1.8000V
Vref   1.6500V   1.5000V   1.8000V
Cref   0.0F   0.0F   0.0F
Rref   32.0000   32.0000   32.0000
[Temperature Range]   25.0000   0.1050k   -20.0000
[Voltage Range]   3.3000V   3.0000V   3.6000V
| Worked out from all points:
|   slope of the pulldown table from 0 to 0.495 V, typ, clamps not added: 15.7 ohm
|   slope of the pullup table from 0 to 0.495 V, typ, clamps not added: 15.2 ohm
|   GND clamp passes 1 mA (typ) near -0.54 V on its own axis
|   POWER clamp passes 1 mA (typ) near -0.57 V on its own axis
|   rising waveform, R_fixture 32.0000, V_fixture 0.0: 20-80 % time 492ps typ, 961ps min, 303ps max; typ from 0 V to 2.13 V
|   rising waveform, R_fixture 32.0000, V_fixture 3.3000: 20-80 % time 283ps typ, 459ps min, 193ps max; typ from 1.37 V to 3.3 V
|   falling waveform, R_fixture 32.0000, V_fixture 0.0: 20-80 % time 175ps typ, 260ps min, 134ps max; typ from 2.13 V to 0 V
|   falling waveform, R_fixture 32.0000, V_fixture 3.3000: 20-80 % time 564ps typ, 1ns min, 334ps max; typ from 3.3 V to 1.37 V
[Pulldown]
|Voltage   I(typ)   I(min)   I(max)
-3.6V     -4.81mA    -4.13mA    -5.14mA
-1.29V    -4.981mA   -3.61mA    -6.026mA
-1.07V    -10.21mA   -5.217mA   -16.32mA
-960mV    -21.78mA   -8.325mA   -45.73mA
-850mV    -47.64mA   -15.99mA   -66.12mA
-630mV    -43.37mA   -29.51mA   -54.64mA
470mV     30.36mA    19.52mA    40.23mA
1.24V     58.04mA    36.82mA    78.41mA
1.9V      65.25mA    41.09mA    89.38mA
5.42V     77.59mA    49.31mA    104.9mA
6.3V      100.5mA    64.16mA    134.5mA
7.2V      148.3mA    95.06mA    196.8mA
[Pullup]
|Voltage   I(typ)   I(min)   I(max)
-3.6V     550uA      500uA      560uA
-1.27V    3.369mA    2.263mA    4.289mA
-1.05V    7.728mA    3.682mA    12.69mA
-940mV    15.97mA    5.483mA    35.11mA
-830mV    37.5mA     9.554mA    60.87mA
-720mV    48.16mA    19.14mA    60.63mA
-610mV    43.84mA    28.82mA    55.11mA
-500mV    36.76mA    26.22mA    46.88mA
820mV     -50.31mA   -34.66mA   -66.15mA
2.03V     -91.95mA   -61.99mA   -122.9mA
3.02V     -101.5mA   -66.9mA    -138mA
7.2V      -119.5mA   -79mA      -161.7mA
[GND_clamp]
|Voltage   I(typ)   I(min)   I(max)
-3.6V     -10.99A    -11.14A    -10.93A
-1.18V    -1.033A    -1.378A    -850.8mA
-1.07V    -607mA     -947.1mA   -431.4mA
-960mV    -236.8mA   -543mA     -106.4mA
-850mV    -31.63mA   -206.7mA   -14.18mA
-740mV    -5.424mA   -29mA      -7.092mA
-630mV    -2.275mA   -2.653mA   -3.283mA
-410mV    -62.05uA   -83.52uA   -82.05uA
7.2V      0A         0A         0A
[POWER_clamp]
|Voltage   I(typ)   I(min)   I(max)
-3.6V     3.491A     3.319A     3.949A
-1.16V    368.2mA    410.8mA    372.9mA
-1.05V    234.5mA    290.2mA    214.3mA
-940mV    110.2mA    175.6mA    75.85mA
-830mV    28.53mA    79.02mA    17.73mA
-720mV    5.671mA    25.66mA    7.515mA
-610mV    1.49mA     4.301mA    2.636mA
-500mV    198.2uA    300.8uA    424.4uA
-390mV    9.667uA    18.86uA    16.14uA
7.2V      0A         0A         0A
[Ramp]
| variable   typ   min   max
dV/dt_r  1.2768/0.4922n   0.9757/0.9610n   1.5371/0.3032n
dV/dt_f  1.1599/0.5641n   0.7783/1.0006n   1.4600/0.3343n
R_load = 32.0000
[Rising Waveform]
R_fixture= 32.0000
V_fixture= 0.0
V_fixture_min= 0.0
V_fixture_max= 0.0
|time   V(typ)   V(min)   V(max)
0s        2.52nV     2.269nV    26.7nV
792.8ps   -6.814mV   -216.6uV   55.89mV
908.8ps   -10.7mV    -1.276mV   343.8mV
1.089ns   47.56mV    -3.121mV   1.513V
1.242ns   293.8mV    -5.377mV   2.042V
1.523ns   1.248V     -6.424mV   2.383V
1.831ns   1.761V     108.6mV    2.497V
2.763ns   2.086V     1.163V     2.558V
3.754ns   2.123V     1.513V     2.562V
11.26ns   2.128V     1.626V     2.562V
[Rising Waveform]
R_fixture= 32.0000
V_fixture= 3.3000
V_fixture_min= 3.0000
V_fixture_max= 3.6000
|time   V(typ)   V(min)   V(max)
0s        1.367V     1.703V     1.167V
617.5ps   1.366V     1.676V     1.355V
741.5ps   1.455V     1.664V     1.882V
934ps     1.873V     1.682V     3.357V
1.06ns    2.365V     1.73V      3.579V
1.21ns    3.034V     1.841V     3.587V
1.32ns    3.252V     1.969V     3.589V
1.842ns   3.292V     2.84V      3.596V
2.101ns   3.295V     2.984V     3.598V
11.26ns   3.3V       3V         3.6V
[Falling Waveform]
R_fixture= 32.0000
V_fixture= 0.0
V_fixture_min= 0.0
V_fixture_max= 0.0
|time   V(typ)   V(min)   V(max)
0s        2.128V     1.626V     2.562V
751.5ps   2.133V     1.626V     2.452V
841.9ps   2.136V     1.626V     1.982V
994.4ps   2.081V     1.627V     289.8mV
1.121ns   1.796V     1.629V     14.16mV
1.347ns   265.5mV    1.638V     4.366mV
1.496ns   15.33mV    1.627V     2.976mV
1.746ns   4.614mV    1.388V     1.628mV
2.281ns   1.63mV     16.29mV    416.1uV
11.26ns   40.27nV    105.3nV    43.29nV
[Falling Waveform]
R_fixture= 32.0000
V_fixture= 3.3000
V_fixture_min= 3.0000
V_fixture_max= 3.6000
|time   V(typ)   V(min)   V(max)
0s        3.3V       3V         3.6V
806.8ps   3.3V       3V         3.59V
971.2ps   3.315V     3V         3.2V
1.151ns   3.299V     2.999V     2.163V
1.291ns   3.129V     2.999V     1.724V
1.585ns   2.289V     3.01V      1.347V
1.859ns   1.85V      3.006V     1.239V
2.892ns   1.415V     2.113V     1.171V
3.967ns   1.372V     1.792V     1.167V
11.26ns   1.367V     1.703V     1.167V
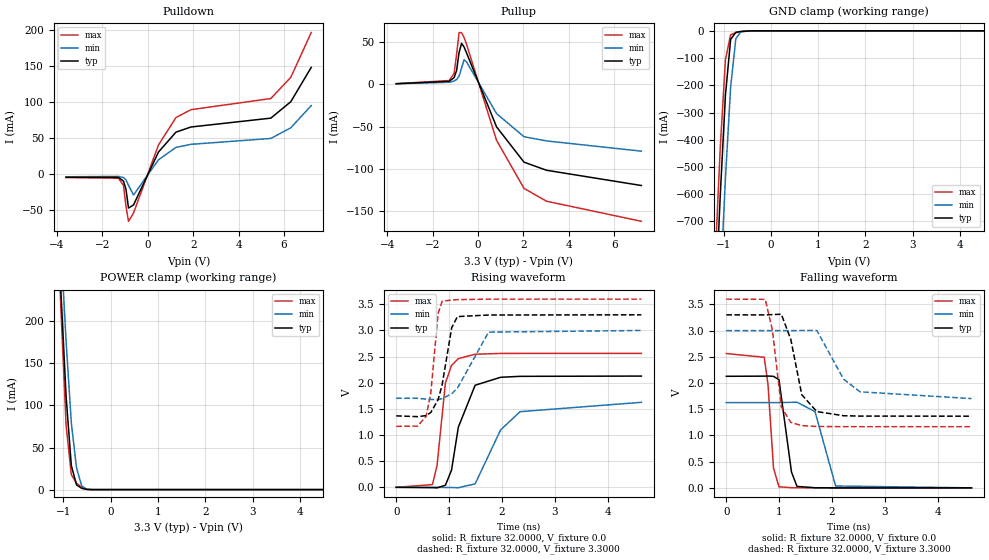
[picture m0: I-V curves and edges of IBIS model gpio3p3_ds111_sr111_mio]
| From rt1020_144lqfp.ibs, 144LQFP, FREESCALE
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[Model] gpio3p3_ds111_sr111_mio
|   Model gpio3p3_ds111_sr111_mio
| This model was characterised for following simulation conditions:
| External (pad) voltage:
|   - Typ: 3.3V,   - Min: 3.0V,   - Max: 3.6V
| Library cells for typ/min/max conditions are connected as defined below:
|  pad - External Pad
|  ipp_do - Core Input
|  ipp_obe - Output Buffer Enable
|  esd_boost - ovdd
|  ipp_dse0 - vddi
|  ipp_dse1 - vddi
|  ipp_dse2 - vddi
|  ipp_fsel0 - vddi
|  ipp_fsel1 - vddi
|  ipp_ina - ipp_ina
|  ipp_ind - ipp_ind
|  ipp_pwr_stable - vddi
|  ipp_sre - vddi
|  ovdd - ovdd
|  ovss - ovss
|  vddi - vddi
|  vssi - vssi
| All other pins connected to ground
Model_type I/O
Polarity   Non-Inverting
Enable   Active-High
Vinl =   0.9900V
Vinh =   2.3100V
Vmeas =  1.6500V
Cref =   0.0F
Rref =   32.0000
Vref =   1.6500V
C_comp   1.2179pF   1.1833pF   1.2636pF
|C_comp_pullup   0.6043pF   0.6190pF   0.5909pF
|C_comp_pulldown   0.5474pF   0.5788pF   0.5258pF
[Model Spec]
| variable   typ   min   max
Vinh   2.3100V   2.1000V   2.5200V
Vinl   0.9900V   0.9000V   1.0800V
S_overshoot_high   3.3000V   3.0000V   3.6000V
S_overshoot_low   0.0V   0.0V   0.0V
Vmeas   1.6500V   1.5000V   1.8000V
Vref   1.6500V   1.5000V   1.8000V
Cref   0.0F   0.0F   0.0F
Rref   32.0000   32.0000   32.0000
[Temperature Range]   25.0000   0.1050k   -20.0000
[Voltage Range]   3.3000V   3.0000V   3.6000V
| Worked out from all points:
|   slope of the pulldown table from 0 to 0.495 V, typ, clamps not added: 15.7 ohm
|   slope of the pullup table from 0 to 0.495 V, typ, clamps not added: 15.2 ohm
|   GND clamp passes 1 mA (typ) near -0.54 V on its own axis
|   POWER clamp passes 1 mA (typ) near -0.57 V on its own axis
|   rising waveform, R_fixture 32.0000, V_fixture 0.0: 20-80 % time 247ps typ, 468ps min, 158ps max; typ from 0 V to 2.13 V
|   rising waveform, R_fixture 32.0000, V_fixture 3.3000: 20-80 % time 206ps typ, 351ps min, 135ps max; typ from 1.37 V to 3.3 V
|   falling waveform, R_fixture 32.0000, V_fixture 0.0: 20-80 % time 126ps typ, 190ps min, 99.1ps max; typ from 2.13 V to 0 V
|   falling waveform, R_fixture 32.0000, V_fixture 3.3000: 20-80 % time 237ps typ, 396ps min, 165ps max; typ from 3.3 V to 1.37 V
[Pulldown]
|Voltage   I(typ)   I(min)   I(max)
-3.6V     -4.81mA    -4.13mA    -5.14mA
-1.29V    -4.981mA   -3.61mA    -6.026mA
-1.07V    -10.21mA   -5.217mA   -16.32mA
-960mV    -21.78mA   -8.325mA   -45.73mA
-850mV    -47.64mA   -15.99mA   -66.12mA
-630mV    -43.37mA   -29.51mA   -54.64mA
470mV     30.36mA    19.52mA    40.23mA
1.24V     58.04mA    36.82mA    78.41mA
1.9V      65.25mA    41.09mA    89.38mA
5.42V     77.59mA    49.31mA    104.9mA
6.3V      100.5mA    64.16mA    134.5mA
7.2V      148.3mA    95.06mA    196.8mA
[Pullup]
|Voltage   I(typ)   I(min)   I(max)
-3.6V     550uA      500uA      560uA
-1.27V    3.369mA    2.263mA    4.289mA
-1.05V    7.728mA    3.682mA    12.69mA
-940mV    15.97mA    5.483mA    35.11mA
-830mV    37.5mA     9.554mA    60.87mA
-720mV    48.16mA    19.14mA    60.63mA
-610mV    43.84mA    28.82mA    55.11mA
-500mV    36.76mA    26.22mA    46.88mA
820mV     -50.31mA   -34.66mA   -66.15mA
2.03V     -91.95mA   -61.99mA   -122.9mA
3.02V     -101.5mA   -66.9mA    -138mA
7.2V      -119.5mA   -79mA      -161.7mA
[GND_clamp]
|Voltage   I(typ)   I(min)   I(max)
-3.6V     -10.99A    -11.14A    -10.93A
-1.18V    -1.033A    -1.378A    -850.8mA
-1.07V    -607mA     -947.1mA   -431.4mA
-960mV    -236.8mA   -543mA     -106.4mA
-850mV    -31.63mA   -206.7mA   -14.18mA
-740mV    -5.424mA   -29mA      -7.092mA
-630mV    -2.275mA   -2.653mA   -3.283mA
-410mV    -62.05uA   -83.52uA   -82.04uA
7.2V      0A         0A         0A
[POWER_clamp]
|Voltage   I(typ)   I(min)   I(max)
-3.6V     3.491A     3.319A     3.949A
-1.16V    368.2mA    410.8mA    372.9mA
-1.05V    234.5mA    290.2mA    214.3mA
-940mV    110.2mA    175.6mA    75.85mA
-830mV    28.53mA    79.02mA    17.73mA
-720mV    5.671mA    25.66mA    7.515mA
-610mV    1.49mA     4.301mA    2.636mA
-500mV    198.2uA    300.8uA    424.4uA
-390mV    9.667uA    18.86uA    16.14uA
7.2V      0A         0A         0A
[Ramp]
| variable   typ   min   max
dV/dt_r  1.2768/0.2469n   0.9754/0.4682n   1.5371/0.1578n
dV/dt_f  1.1599/0.2369n   0.7782/0.3962n   1.4600/0.1653n
R_load = 32.0000
[Rising Waveform]
R_fixture= 32.0000
V_fixture= 0.0
V_fixture_min= 0.0
V_fixture_max= 0.0
|time   V(typ)   V(min)   V(max)
0s        2.52nV     2.284nV    26.7nV
684.8ps   -6.074mV   164.4uV    52.12mV
772.6ps   -10.22mV   -605.2uV   412.7mV
930.9ps   39.68mV    -2.49mV    1.993V
1.047ns   328.6mV    -4.147mV   2.332V
1.176ns   1.151V     -7.176mV   2.462V
1.494ns   1.953V     66.69mV    2.546V
1.976ns   2.105V     1.098V     2.561V
2.344ns   2.123V     1.447V     2.562V
4.64ns    2.128V     1.626V     2.562V
[Rising Waveform]
R_fixture= 32.0000
V_fixture= 3.3000
V_fixture_min= 3.0000
V_fixture_max= 3.6000
|time   V(typ)   V(min)   V(max)
0s        1.367V     1.703V     1.167V
403.7ps   1.352V     1.703V     1.171V
565.7ps   1.372V     1.688V     1.358V
654.5ps   1.431V     1.68V      1.802V
792.9ps   1.676V     1.682V     3.321V
869ps     1.959V     1.696V     3.559V
1.051ns   3.056V     1.79V      3.584V
1.159ns   3.266V     1.898V     3.59V
1.748ns   3.296V     2.969V     3.6V
4.64ns    3.3V       3V         3.6V
[Falling Waveform]
R_fixture= 32.0000
V_fixture= 0.0
V_fixture_min= 0.0
V_fixture_max= 0.0
|time   V(typ)   V(min)   V(max)
0s        2.128V     1.626V     2.562V
716.6ps   2.131V     1.626V     2.491V
788.7ps   2.133V     1.626V     1.972V
893.2ps   2.127V     1.626V     375.2mV
996.5ps   2.063V     1.627V     20.32mV
1.233ns   302.6mV    1.631V     2.6mV
1.337ns   27.76mV    1.634V     1.424mV
1.679ns   2.282mV    1.454V     270.2uV
2.068ns   444.2uV    35.54mV    91.52uV
4.64ns    5.115uV    26.07uV    3.61uV
[Falling Waveform]
R_fixture= 32.0000
V_fixture= 3.3000
V_fixture_min= 3.0000
V_fixture_max= 3.6000
|time   V(typ)   V(min)   V(max)
0s        3.3V       3V         3.6V
736.9ps   3.299V     3V         3.596V
871.4ps   3.305V     3V         3.013V
1.041ns   3.312V     3V         1.543V
1.221ns   2.828V     2.999V     1.247V
1.428ns   1.776V     3.002V     1.188V
1.713ns   1.455V     3.002V     1.171V
2.219ns   1.376V     2.074V     1.167V
2.529ns   1.369V     1.832V     1.167V
4.64ns    1.367V     1.703V     1.167V
